VERSION 5.7 ;
BUSBITCHARS "[]" ;
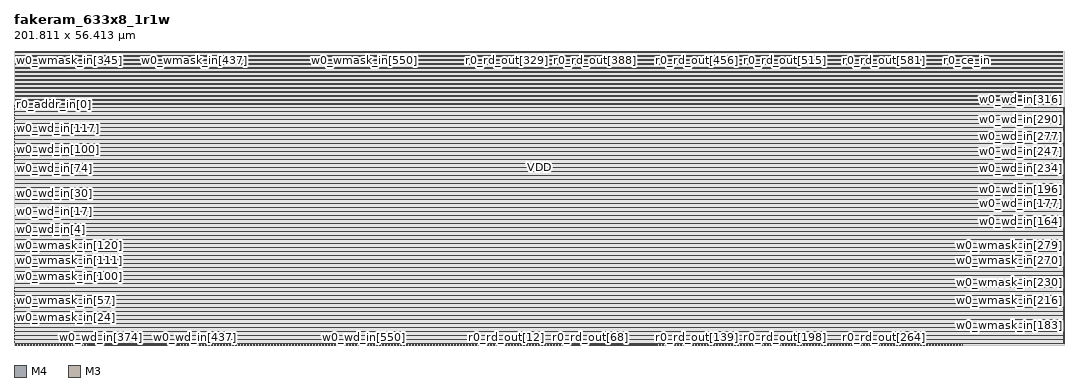
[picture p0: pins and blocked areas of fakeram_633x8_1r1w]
MACRO fakeram_633x8_1r1w
  FOREIGN fakeram_633x8_1r1w 0 0 ;
  SYMMETRY X Y R90 ;
  SIZE 201.811 BY 56.413 ;
  CLASS BLOCK ;
  PIN w0_wmask_in[0]
    DIRECTION INPUT ;
    USE SIGNAL ;
    SHAPE ABUTMENT ;
    PORT
      LAYER M4 ;
      RECT 0.000 0.276 0.072 0.300 ;
    END
  END w0_wmask_in[0]
  PIN w0_wmask_in[1]
    DIRECTION INPUT ;
    USE SIGNAL ;
    SHAPE ABUTMENT ;
    PORT
      LAYER M4 ;
      RECT 0.000 0.420 0.072 0.444 ;
    END
  END w0_wmask_in[1]
  PIN w0_wmask_in[2]
    DIRECTION INPUT ;
    USE SIGNAL ;
    SHAPE ABUTMENT ;
    PORT
      LAYER M4 ;
      RECT 0.000 0.564 0.072 0.588 ;
    END
  END w0_wmask_in[2]
  PIN w0_wmask_in[3]
    DIRECTION INPUT ;
    USE SIGNAL ;
    SHAPE ABUTMENT ;
    PORT
      LAYER M4 ;
      RECT 0.000 0.708 0.072 0.732 ;
    END
  END w0_wmask_in[3]
  PIN w0_wmask_in[4]
    DIRECTION INPUT ;
    USE SIGNAL ;
    SHAPE ABUTMENT ;
    PORT
      LAYER M4 ;
      RECT 0.000 0.852 0.072 0.876 ;
    END
  END w0_wmask_in[4]
  PIN w0_wmask_in[5]
    DIRECTION INPUT ;
    USE SIGNAL ;
    SHAPE ABUTMENT ;
    PORT
      LAYER M4 ;
      RECT 0.000 0.996 0.072 1.020 ;
    END
  END w0_wmask_in[5]
  PIN w0_wmask_in[6]
    DIRECTION INPUT ;
    USE SIGNAL ;
    SHAPE ABUTMENT ;
    PORT
      LAYER M4 ;
      RECT 0.000 1.140 0.072 1.164 ;
    END
  END w0_wmask_in[6]
  PIN w0_wmask_in[7]
    DIRECTION INPUT ;
    USE SIGNAL ;
    SHAPE ABUTMENT ;
    PORT
      LAYER M4 ;
      RECT 0.000 1.284 0.072 1.308 ;
    END
  END w0_wmask_in[7]
  PIN w0_wmask_in[8]
    DIRECTION INPUT ;
    USE SIGNAL ;
    SHAPE ABUTMENT ;
    PORT
      LAYER M4 ;
      RECT 0.000 1.428 0.072 1.452 ;
    END
  END w0_wmask_in[8]
  PIN w0_wmask_in[9]
    DIRECTION INPUT ;
    USE SIGNAL ;
    SHAPE ABUTMENT ;
    PORT
      LAYER M4 ;
      RECT 0.000 1.572 0.072 1.596 ;
    END
  END w0_wmask_in[9]
  PIN w0_wmask_in[10]
    DIRECTION INPUT ;
    USE SIGNAL ;
    SHAPE ABUTMENT ;
    PORT
      LAYER M4 ;
      RECT 0.000 1.716 0.072 1.740 ;
    END
  END w0_wmask_in[10]
  PIN w0_wmask_in[11]
    DIRECTION INPUT ;
    USE SIGNAL ;
    SHAPE ABUTMENT ;
    PORT
      LAYER M4 ;
      RECT 0.000 1.860 0.072 1.884 ;
    END
  END w0_wmask_in[11]
  PIN w0_wmask_in[12]
    DIRECTION INPUT ;
    USE SIGNAL ;
    SHAPE ABUTMENT ;
    PORT
      LAYER M4 ;
      RECT 0.000 2.004 0.072 2.028 ;
    END
  END w0_wmask_in[12]
  PIN w0_wmask_in[13]
    DIRECTION INPUT ;
    USE SIGNAL ;
    SHAPE ABUTMENT ;
    PORT
      LAYER M4 ;
      RECT 0.000 2.148 0.072 2.172 ;
    END
  END w0_wmask_in[13]
  PIN w0_wmask_in[14]
    DIRECTION INPUT ;
    USE SIGNAL ;
    SHAPE ABUTMENT ;
    PORT
      LAYER M4 ;
      RECT 0.000 2.292 0.072 2.316 ;
    END
  END w0_wmask_in[14]
  PIN w0_wmask_in[15]
    DIRECTION INPUT ;
    USE SIGNAL ;
    SHAPE ABUTMENT ;
    PORT
      LAYER M4 ;
      RECT 0.000 2.436 0.072 2.460 ;
    END
  END w0_wmask_in[15]
  PIN w0_wmask_in[16]
    DIRECTION INPUT ;
    USE SIGNAL ;
    SHAPE ABUTMENT ;
    PORT
      LAYER M4 ;
      RECT 0.000 2.580 0.072 2.604 ;
    END
  END w0_wmask_in[16]
  PIN w0_wmask_in[17]
    DIRECTION INPUT ;
    USE SIGNAL ;
    SHAPE ABUTMENT ;
    PORT
      LAYER M4 ;
      RECT 0.000 2.724 0.072 2.748 ;
    END
  END w0_wmask_in[17]
  PIN w0_wmask_in[18]
    DIRECTION INPUT ;
    USE SIGNAL ;
    SHAPE ABUTMENT ;
    PORT
      LAYER M4 ;
      RECT 0.000 2.868 0.072 2.892 ;
    END
  END w0_wmask_in[18]
  PIN w0_wmask_in[19]
    DIRECTION INPUT ;
    USE SIGNAL ;
    SHAPE ABUTMENT ;
    PORT
      LAYER M4 ;
      RECT 0.000 3.012 0.072 3.036 ;
    END
  END w0_wmask_in[19]
  PIN w0_wmask_in[20]
    DIRECTION INPUT ;
    USE SIGNAL ;
    SHAPE ABUTMENT ;
    PORT
      LAYER M4 ;
      RECT 0.000 3.156 0.072 3.180 ;
    END
  END w0_wmask_in[20]
  PIN w0_wmask_in[21]
    DIRECTION INPUT ;
    USE SIGNAL ;
    SHAPE ABUTMENT ;
    PORT
      LAYER M4 ;
      RECT 0.000 3.300 0.072 3.324 ;
    END
  END w0_wmask_in[21]
  PIN w0_wmask_in[22]
    DIRECTION INPUT ;
    USE SIGNAL ;
    SHAPE ABUTMENT ;
    PORT
      LAYER M4 ;
      RECT 0.000 3.444 0.072 3.468 ;
    END
  END w0_wmask_in[22]
  PIN w0_wmask_in[23]
    DIRECTION INPUT ;
    USE SIGNAL ;
    SHAPE ABUTMENT ;
    PORT
      LAYER M4 ;
      RECT 0.000 3.588 0.072 3.612 ;
    END
  END w0_wmask_in[23]
  PIN w0_wmask_in[24]
    DIRECTION INPUT ;
    USE SIGNAL ;
    SHAPE ABUTMENT ;
    PORT
      LAYER M4 ;
      RECT 0.000 3.732 0.072 3.756 ;
    END
  END w0_wmask_in[24]
  PIN w0_wmask_in[25]
    DIRECTION INPUT ;
    USE SIGNAL ;
    SHAPE ABUTMENT ;
    PORT
      LAYER M4 ;
      RECT 0.000 3.876 0.072 3.900 ;
    END
  END w0_wmask_in[25]
  PIN w0_wmask_in[26]
    DIRECTION INPUT ;
    USE SIGNAL ;
    SHAPE ABUTMENT ;
    PORT
      LAYER M4 ;
      RECT 0.000 4.020 0.072 4.044 ;
    END
  END w0_wmask_in[26]
  PIN w0_wmask_in[27]
    DIRECTION INPUT ;
    USE SIGNAL ;
    SHAPE ABUTMENT ;
    PORT
      LAYER M4 ;
      RECT 0.000 4.164 0.072 4.188 ;
    END
  END w0_wmask_in[27]
  PIN w0_wmask_in[28]
    DIRECTION INPUT ;
    USE SIGNAL ;
    SHAPE ABUTMENT ;
    PORT
      LAYER M4 ;
      RECT 0.000 4.308 0.072 4.332 ;
    END
  END w0_wmask_in[28]
  PIN w0_wmask_in[29]
    DIRECTION INPUT ;
    USE SIGNAL ;
    SHAPE ABUTMENT ;
    PORT
      LAYER M4 ;
      RECT 0.000 4.452 0.072 4.476 ;
    END
  END w0_wmask_in[29]
  PIN w0_wmask_in[30]
    DIRECTION INPUT ;
    USE SIGNAL ;
    SHAPE ABUTMENT ;
    PORT
      LAYER M4 ;
      RECT 0.000 4.596 0.072 4.620 ;
    END
  END w0_wmask_in[30]
  PIN w0_wmask_in[31]
    DIRECTION INPUT ;
    USE SIGNAL ;
    SHAPE ABUTMENT ;
    PORT
      LAYER M4 ;
      RECT 0.000 4.740 0.072 4.764 ;
    END
  END w0_wmask_in[31]
  PIN w0_wmask_in[32]
    DIRECTION INPUT ;
    USE SIGNAL ;
    SHAPE ABUTMENT ;
    PORT
      LAYER M4 ;
      RECT 0.000 4.884 0.072 4.908 ;
    END
  END w0_wmask_in[32]
  PIN w0_wmask_in[33]
    DIRECTION INPUT ;
    USE SIGNAL ;
    SHAPE ABUTMENT ;
    PORT
      LAYER M4 ;
      RECT 0.000 5.028 0.072 5.052 ;
    END
  END w0_wmask_in[33]
  PIN w0_wmask_in[34]
    DIRECTION INPUT ;
    USE SIGNAL ;
    SHAPE ABUTMENT ;
    PORT
      LAYER M4 ;
      RECT 0.000 5.172 0.072 5.196 ;
    END
  END w0_wmask_in[34]
  PIN w0_wmask_in[35]
    DIRECTION INPUT ;
    USE SIGNAL ;
    SHAPE ABUTMENT ;
    PORT
      LAYER M4 ;
      RECT 0.000 5.316 0.072 5.340 ;
    END
  END w0_wmask_in[35]
  PIN w0_wmask_in[36]
    DIRECTION INPUT ;
    USE SIGNAL ;
    SHAPE ABUTMENT ;
    PORT
      LAYER M4 ;
      RECT 0.000 5.460 0.072 5.484 ;
    END
  END w0_wmask_in[36]
  PIN w0_wmask_in[37]
    DIRECTION INPUT ;
    USE SIGNAL ;
    SHAPE ABUTMENT ;
    PORT
      LAYER M4 ;
      RECT 0.000 5.604 0.072 5.628 ;
    END
  END w0_wmask_in[37]
  PIN w0_wmask_in[38]
    DIRECTION INPUT ;
    USE SIGNAL ;
    SHAPE ABUTMENT ;
    PORT
      LAYER M4 ;
      RECT 0.000 5.748 0.072 5.772 ;
    END
  END w0_wmask_in[38]
  PIN w0_wmask_in[39]
    DIRECTION INPUT ;
    USE SIGNAL ;
    SHAPE ABUTMENT ;
    PORT
      LAYER M4 ;
      RECT 0.000 5.892 0.072 5.916 ;
    END
  END w0_wmask_in[39]
  PIN w0_wmask_in[40]
    DIRECTION INPUT ;
    USE SIGNAL ;
    SHAPE ABUTMENT ;
    PORT
      LAYER M4 ;
      RECT 0.000 6.036 0.072 6.060 ;
    END
  END w0_wmask_in[40]
  PIN w0_wmask_in[41]
    DIRECTION INPUT ;
    USE SIGNAL ;
    SHAPE ABUTMENT ;
    PORT
      LAYER M4 ;
      RECT 0.000 6.180 0.072 6.204 ;
    END
  END w0_wmask_in[41]
  PIN w0_wmask_in[42]
    DIRECTION INPUT ;
    USE SIGNAL ;
    SHAPE ABUTMENT ;
    PORT
      LAYER M4 ;
      RECT 0.000 6.324 0.072 6.348 ;
    END
  END w0_wmask_in[42]
  PIN w0_wmask_in[43]
    DIRECTION INPUT ;
    USE SIGNAL ;
    SHAPE ABUTMENT ;
    PORT
      LAYER M4 ;
      RECT 0.000 6.468 0.072 6.492 ;
    END
  END w0_wmask_in[43]
  PIN w0_wmask_in[44]
    DIRECTION INPUT ;
    USE SIGNAL ;
    SHAPE ABUTMENT ;
    PORT
      LAYER M4 ;
      RECT 0.000 6.612 0.072 6.636 ;
    END
  END w0_wmask_in[44]
  PIN w0_wmask_in[45]
    DIRECTION INPUT ;
    USE SIGNAL ;
    SHAPE ABUTMENT ;
    PORT
      LAYER M4 ;
      RECT 0.000 6.756 0.072 6.780 ;
    END
  END w0_wmask_in[45]
  PIN w0_wmask_in[46]
    DIRECTION INPUT ;
    USE SIGNAL ;
    SHAPE ABUTMENT ;
    PORT
      LAYER M4 ;
      RECT 0.000 6.900 0.072 6.924 ;
    END
  END w0_wmask_in[46]
  PIN w0_wmask_in[47]
    DIRECTION INPUT ;
    USE SIGNAL ;
    SHAPE ABUTMENT ;
    PORT
      LAYER M4 ;
      RECT 0.000 7.044 0.072 7.068 ;
    END
  END w0_wmask_in[47]
  PIN w0_wmask_in[48]
    DIRECTION INPUT ;
    USE SIGNAL ;
    SHAPE ABUTMENT ;
    PORT
      LAYER M4 ;
      RECT 0.000 7.188 0.072 7.212 ;
    END
  END w0_wmask_in[48]
  PIN w0_wmask_in[49]
    DIRECTION INPUT ;
    USE SIGNAL ;
    SHAPE ABUTMENT ;
    PORT
      LAYER M4 ;
      RECT 0.000 7.332 0.072 7.356 ;
    END
  END w0_wmask_in[49]
  PIN w0_wmask_in[50]
    DIRECTION INPUT ;
    USE SIGNAL ;
    SHAPE ABUTMENT ;
    PORT
      LAYER M4 ;
      RECT 0.000 7.476 0.072 7.500 ;
    END
  END w0_wmask_in[50]
  PIN w0_wmask_in[51]
    DIRECTION INPUT ;
    USE SIGNAL ;
    SHAPE ABUTMENT ;
    PORT
      LAYER M4 ;
      RECT 0.000 7.620 0.072 7.644 ;
    END
  END w0_wmask_in[51]
  PIN w0_wmask_in[52]
    DIRECTION INPUT ;
    USE SIGNAL ;
    SHAPE ABUTMENT ;
    PORT
      LAYER M4 ;
      RECT 0.000 7.764 0.072 7.788 ;
    END
  END w0_wmask_in[52]
  PIN w0_wmask_in[53]
    DIRECTION INPUT ;
    USE SIGNAL ;
    SHAPE ABUTMENT ;
    PORT
      LAYER M4 ;
      RECT 0.000 7.908 0.072 7.932 ;
    END
  END w0_wmask_in[53]
  PIN w0_wmask_in[54]
    DIRECTION INPUT ;
    USE SIGNAL ;
    SHAPE ABUTMENT ;
    PORT
      LAYER M4 ;
      RECT 0.000 8.052 0.072 8.076 ;
    END
  END w0_wmask_in[54]
  PIN w0_wmask_in[55]
    DIRECTION INPUT ;
    USE SIGNAL ;
    SHAPE ABUTMENT ;
    PORT
      LAYER M4 ;
      RECT 0.000 8.196 0.072 8.220 ;
    END
  END w0_wmask_in[55]
  PIN w0_wmask_in[56]
    DIRECTION INPUT ;
    USE SIGNAL ;
    SHAPE ABUTMENT ;
    PORT
      LAYER M4 ;
      RECT 0.000 8.340 0.072 8.364 ;
    END
  END w0_wmask_in[56]
  PIN w0_wmask_in[57]
    DIRECTION INPUT ;
    USE SIGNAL ;
    SHAPE ABUTMENT ;
    PORT
      LAYER M4 ;
      RECT 0.000 8.484 0.072 8.508 ;
    END
  END w0_wmask_in[57]
  PIN w0_wmask_in[58]
    DIRECTION INPUT ;
    USE SIGNAL ;
    SHAPE ABUTMENT ;
    PORT
      LAYER M4 ;
      RECT 0.000 8.628 0.072 8.652 ;
    END
  END w0_wmask_in[58]
  PIN w0_wmask_in[59]
    DIRECTION INPUT ;
    USE SIGNAL ;
    SHAPE ABUTMENT ;
    PORT
      LAYER M4 ;
      RECT 0.000 8.772 0.072 8.796 ;
    END
  END w0_wmask_in[59]
  PIN w0_wmask_in[60]
    DIRECTION INPUT ;
    USE SIGNAL ;
    SHAPE ABUTMENT ;
    PORT
      LAYER M4 ;
      RECT 0.000 8.916 0.072 8.940 ;
    END
  END w0_wmask_in[60]
  PIN w0_wmask_in[61]
    DIRECTION INPUT ;
    USE SIGNAL ;
    SHAPE ABUTMENT ;
    PORT
      LAYER M4 ;
      RECT 0.000 9.060 0.072 9.084 ;
    END
  END w0_wmask_in[61]
  PIN w0_wmask_in[62]
    DIRECTION INPUT ;
    USE SIGNAL ;
    SHAPE ABUTMENT ;
    PORT
      LAYER M4 ;
      RECT 0.000 9.204 0.072 9.228 ;
    END
  END w0_wmask_in[62]
  PIN w0_wmask_in[63]
    DIRECTION INPUT ;
    USE SIGNAL ;
    SHAPE ABUTMENT ;
    PORT
      LAYER M4 ;
      RECT 0.000 9.348 0.072 9.372 ;
    END
  END w0_wmask_in[63]
  PIN w0_wmask_in[64]
    DIRECTION INPUT ;
    USE SIGNAL ;
    SHAPE ABUTMENT ;
    PORT
      LAYER M4 ;
      RECT 0.000 9.492 0.072 9.516 ;
    END
  END w0_wmask_in[64]
  PIN w0_wmask_in[65]
    DIRECTION INPUT ;
    USE SIGNAL ;
    SHAPE ABUTMENT ;
    PORT
      LAYER M4 ;
      RECT 0.000 9.636 0.072 9.660 ;
    END
  END w0_wmask_in[65]
  PIN w0_wmask_in[66]
    DIRECTION INPUT ;
    USE SIGNAL ;
    SHAPE ABUTMENT ;
    PORT
      LAYER M4 ;
      RECT 0.000 9.780 0.072 9.804 ;
    END
  END w0_wmask_in[66]
  PIN w0_wmask_in[67]
    DIRECTION INPUT ;
    USE SIGNAL ;
    SHAPE ABUTMENT ;
    PORT
      LAYER M4 ;
      RECT 0.000 9.924 0.072 9.948 ;
    END
  END w0_wmask_in[67]
  PIN w0_wmask_in[68]
    DIRECTION INPUT ;
    USE SIGNAL ;
    SHAPE ABUTMENT ;
    PORT
      LAYER M4 ;
      RECT 0.000 10.068 0.072 10.092 ;
    END
  END w0_wmask_in[68]
  PIN w0_wmask_in[69]
    DIRECTION INPUT ;
    USE SIGNAL ;
    SHAPE ABUTMENT ;
    PORT
      LAYER M4 ;
      RECT 0.000 10.212 0.072 10.236 ;
    END
  END w0_wmask_in[69]
  PIN w0_wmask_in[70]
    DIRECTION INPUT ;
    USE SIGNAL ;
    SHAPE ABUTMENT ;
    PORT
      LAYER M4 ;
      RECT 0.000 10.356 0.072 10.380 ;
    END
  END w0_wmask_in[70]
  PIN w0_wmask_in[71]
    DIRECTION INPUT ;
    USE SIGNAL ;
    SHAPE ABUTMENT ;
    PORT
      LAYER M4 ;
      RECT 0.000 10.500 0.072 10.524 ;
    END
  END w0_wmask_in[71]
  PIN w0_wmask_in[72]
    DIRECTION INPUT ;
    USE SIGNAL ;
    SHAPE ABUTMENT ;
    PORT
      LAYER M4 ;
      RECT 0.000 10.644 0.072 10.668 ;
    END
  END w0_wmask_in[72]
  PIN w0_wmask_in[73]
    DIRECTION INPUT ;
    USE SIGNAL ;
    SHAPE ABUTMENT ;
    PORT
      LAYER M4 ;
      RECT 0.000 10.788 0.072 10.812 ;
    END
  END w0_wmask_in[73]
  PIN w0_wmask_in[74]
    DIRECTION INPUT ;
    USE SIGNAL ;
    SHAPE ABUTMENT ;
    PORT
      LAYER M4 ;
      RECT 0.000 10.932 0.072 10.956 ;
    END
  END w0_wmask_in[74]
  PIN w0_wmask_in[75]
    DIRECTION INPUT ;
    USE SIGNAL ;
    SHAPE ABUTMENT ;
    PORT
      LAYER M4 ;
      RECT 0.000 11.076 0.072 11.100 ;
    END
  END w0_wmask_in[75]
  PIN w0_wmask_in[76]
    DIRECTION INPUT ;
    USE SIGNAL ;
    SHAPE ABUTMENT ;
    PORT
      LAYER M4 ;
      RECT 0.000 11.220 0.072 11.244 ;
    END
  END w0_wmask_in[76]
  PIN w0_wmask_in[77]
    DIRECTION INPUT ;
    USE SIGNAL ;
    SHAPE ABUTMENT ;
    PORT
      LAYER M4 ;
      RECT 0.000 11.364 0.072 11.388 ;
    END
  END w0_wmask_in[77]
  PIN w0_wmask_in[78]
    DIRECTION INPUT ;
    USE SIGNAL ;
    SHAPE ABUTMENT ;
    PORT
      LAYER M4 ;
      RECT 0.000 11.508 0.072 11.532 ;
    END
  END w0_wmask_in[78]
  PIN w0_wmask_in[79]
    DIRECTION INPUT ;
    USE SIGNAL ;
    SHAPE ABUTMENT ;
    PORT
      LAYER M4 ;
      RECT 0.000 11.652 0.072 11.676 ;
    END
  END w0_wmask_in[79]
  PIN w0_wmask_in[80]
    DIRECTION INPUT ;
    USE SIGNAL ;
    SHAPE ABUTMENT ;
    PORT
      LAYER M4 ;
      RECT 0.000 11.796 0.072 11.820 ;
    END
  END w0_wmask_in[80]
  PIN w0_wmask_in[81]
    DIRECTION INPUT ;
    USE SIGNAL ;
    SHAPE ABUTMENT ;
    PORT
      LAYER M4 ;
      RECT 0.000 11.940 0.072 11.964 ;
    END
  END w0_wmask_in[81]
  PIN w0_wmask_in[82]
    DIRECTION INPUT ;
    USE SIGNAL ;
    SHAPE ABUTMENT ;
    PORT
      LAYER M4 ;
      RECT 0.000 12.084 0.072 12.108 ;
    END
  END w0_wmask_in[82]
  PIN w0_wmask_in[83]
    DIRECTION INPUT ;
    USE SIGNAL ;
    SHAPE ABUTMENT ;
    PORT
      LAYER M4 ;
      RECT 0.000 12.228 0.072 12.252 ;
    END
  END w0_wmask_in[83]
  PIN w0_wmask_in[84]
    DIRECTION INPUT ;
    USE SIGNAL ;
    SHAPE ABUTMENT ;
    PORT
      LAYER M4 ;
      RECT 0.000 12.372 0.072 12.396 ;
    END
  END w0_wmask_in[84]
  PIN w0_wmask_in[85]
    DIRECTION INPUT ;
    USE SIGNAL ;
    SHAPE ABUTMENT ;
    PORT
      LAYER M4 ;
      RECT 0.000 12.516 0.072 12.540 ;
    END
  END w0_wmask_in[85]
  PIN w0_wmask_in[86]
    DIRECTION INPUT ;
    USE SIGNAL ;
    SHAPE ABUTMENT ;
    PORT
      LAYER M4 ;
      RECT 0.000 12.660 0.072 12.684 ;
    END
  END w0_wmask_in[86]
  PIN w0_wmask_in[87]
    DIRECTION INPUT ;
    USE SIGNAL ;
    SHAPE ABUTMENT ;
    PORT
      LAYER M4 ;
      RECT 0.000 12.804 0.072 12.828 ;
    END
  END w0_wmask_in[87]
  PIN w0_wmask_in[88]
    DIRECTION INPUT ;
    USE SIGNAL ;
    SHAPE ABUTMENT ;
    PORT
      LAYER M4 ;
      RECT 0.000 12.948 0.072 12.972 ;
    END
  END w0_wmask_in[88]
  PIN w0_wmask_in[89]
    DIRECTION INPUT ;
    USE SIGNAL ;
    SHAPE ABUTMENT ;
    PORT
      LAYER M4 ;
      RECT 0.000 13.092 0.072 13.116 ;
    END
  END w0_wmask_in[89]
  PIN w0_wmask_in[90]
    DIRECTION INPUT ;
    USE SIGNAL ;
    SHAPE ABUTMENT ;
    PORT
      LAYER M4 ;
      RECT 0.000 13.236 0.072 13.260 ;
    END
  END w0_wmask_in[90]
  PIN w0_wmask_in[91]
    DIRECTION INPUT ;
    USE SIGNAL ;
    SHAPE ABUTMENT ;
    PORT
      LAYER M4 ;
      RECT 0.000 13.380 0.072 13.404 ;
    END
  END w0_wmask_in[91]
  PIN w0_wmask_in[92]
    DIRECTION INPUT ;
    USE SIGNAL ;
    SHAPE ABUTMENT ;
    PORT
      LAYER M4 ;
      RECT 0.000 13.524 0.072 13.548 ;
    END
  END w0_wmask_in[92]
  PIN w0_wmask_in[93]
    DIRECTION INPUT ;
    USE SIGNAL ;
    SHAPE ABUTMENT ;
    PORT
      LAYER M4 ;
      RECT 0.000 13.668 0.072 13.692 ;
    END
  END w0_wmask_in[93]
  PIN w0_wmask_in[94]
    DIRECTION INPUT ;
    USE SIGNAL ;
    SHAPE ABUTMENT ;
    PORT
      LAYER M4 ;
      RECT 0.000 13.812 0.072 13.836 ;
    END
  END w0_wmask_in[94]
  PIN w0_wmask_in[95]
    DIRECTION INPUT ;
    USE SIGNAL ;
    SHAPE ABUTMENT ;
    PORT
      LAYER M4 ;
      RECT 0.000 13.956 0.072 13.980 ;
    END
  END w0_wmask_in[95]
  PIN w0_wmask_in[96]
    DIRECTION INPUT ;
    USE SIGNAL ;
    SHAPE ABUTMENT ;
    PORT
      LAYER M4 ;
      RECT 0.000 14.100 0.072 14.124 ;
    END
  END w0_wmask_in[96]
  PIN w0_wmask_in[97]
    DIRECTION INPUT ;
    USE SIGNAL ;
    SHAPE ABUTMENT ;
    PORT
      LAYER M4 ;
      RECT 0.000 14.244 0.072 14.268 ;
    END
  END w0_wmask_in[97]
  PIN w0_wmask_in[98]
    DIRECTION INPUT ;
    USE SIGNAL ;
    SHAPE ABUTMENT ;
    PORT
      LAYER M4 ;
      RECT 0.000 14.388 0.072 14.412 ;
    END
  END w0_wmask_in[98]
  PIN w0_wmask_in[99]
    DIRECTION INPUT ;
    USE SIGNAL ;
    SHAPE ABUTMENT ;
    PORT
      LAYER M4 ;
      RECT 0.000 14.532 0.072 14.556 ;
    END
  END w0_wmask_in[99]
  PIN w0_wmask_in[100]
    DIRECTION INPUT ;
    USE SIGNAL ;
    SHAPE ABUTMENT ;
    PORT
      LAYER M4 ;
      RECT 0.000 14.676 0.072 14.700 ;
    END
  END w0_wmask_in[100]
  PIN w0_wmask_in[101]
    DIRECTION INPUT ;
    USE SIGNAL ;
    SHAPE ABUTMENT ;
    PORT
      LAYER M4 ;
      RECT 0.000 14.820 0.072 14.844 ;
    END
  END w0_wmask_in[101]
  PIN w0_wmask_in[102]
    DIRECTION INPUT ;
    USE SIGNAL ;
    SHAPE ABUTMENT ;
    PORT
      LAYER M4 ;
      RECT 0.000 14.964 0.072 14.988 ;
    END
  END w0_wmask_in[102]
  PIN w0_wmask_in[103]
    DIRECTION INPUT ;
    USE SIGNAL ;
    SHAPE ABUTMENT ;
    PORT
      LAYER M4 ;
      RECT 0.000 15.108 0.072 15.132 ;
    END
  END w0_wmask_in[103]
  PIN w0_wmask_in[104]
    DIRECTION INPUT ;
    USE SIGNAL ;
    SHAPE ABUTMENT ;
    PORT
      LAYER M4 ;
      RECT 0.000 15.252 0.072 15.276 ;
    END
  END w0_wmask_in[104]
  PIN w0_wmask_in[105]
    DIRECTION INPUT ;
    USE SIGNAL ;
    SHAPE ABUTMENT ;
    PORT
      LAYER M4 ;
      RECT 0.000 15.396 0.072 15.420 ;
    END
  END w0_wmask_in[105]
  PIN w0_wmask_in[106]
    DIRECTION INPUT ;
    USE SIGNAL ;
    SHAPE ABUTMENT ;
    PORT
      LAYER M4 ;
      RECT 0.000 15.540 0.072 15.564 ;
    END
  END w0_wmask_in[106]
  PIN w0_wmask_in[107]
    DIRECTION INPUT ;
    USE SIGNAL ;
    SHAPE ABUTMENT ;
    PORT
      LAYER M4 ;
      RECT 0.000 15.684 0.072 15.708 ;
    END
  END w0_wmask_in[107]
  PIN w0_wmask_in[108]
    DIRECTION INPUT ;
    USE SIGNAL ;
    SHAPE ABUTMENT ;
    PORT
      LAYER M4 ;
      RECT 0.000 15.828 0.072 15.852 ;
    END
  END w0_wmask_in[108]
  PIN w0_wmask_in[109]
    DIRECTION INPUT ;
    USE SIGNAL ;
    SHAPE ABUTMENT ;
    PORT
      LAYER M4 ;
      RECT 0.000 15.972 0.072 15.996 ;
    END
  END w0_wmask_in[109]
  PIN w0_wmask_in[110]
    DIRECTION INPUT ;
    USE SIGNAL ;
    SHAPE ABUTMENT ;
    PORT
      LAYER M4 ;
      RECT 0.000 16.116 0.072 16.140 ;
    END
  END w0_wmask_in[110]
  PIN w0_wmask_in[111]
    DIRECTION INPUT ;
    USE SIGNAL ;
    SHAPE ABUTMENT ;
    PORT
      LAYER M4 ;
      RECT 0.000 16.260 0.072 16.284 ;
    END
  END w0_wmask_in[111]
  PIN w0_wmask_in[112]
    DIRECTION INPUT ;
    USE SIGNAL ;
    SHAPE ABUTMENT ;
    PORT
      LAYER M4 ;
      RECT 0.000 16.404 0.072 16.428 ;
    END
  END w0_wmask_in[112]
  PIN w0_wmask_in[113]
    DIRECTION INPUT ;
    USE SIGNAL ;
    SHAPE ABUTMENT ;
    PORT
      LAYER M4 ;
      RECT 0.000 16.548 0.072 16.572 ;
    END
  END w0_wmask_in[113]
  PIN w0_wmask_in[114]
    DIRECTION INPUT ;
    USE SIGNAL ;
    SHAPE ABUTMENT ;
    PORT
      LAYER M4 ;
      RECT 0.000 16.692 0.072 16.716 ;
    END
  END w0_wmask_in[114]
  PIN w0_wmask_in[115]
    DIRECTION INPUT ;
    USE SIGNAL ;
    SHAPE ABUTMENT ;
    PORT
      LAYER M4 ;
      RECT 0.000 16.836 0.072 16.860 ;
    END
  END w0_wmask_in[115]
  PIN w0_wmask_in[116]
    DIRECTION INPUT ;
    USE SIGNAL ;
    SHAPE ABUTMENT ;
    PORT
      LAYER M4 ;
      RECT 0.000 16.980 0.072 17.004 ;
    END
  END w0_wmask_in[116]
  PIN w0_wmask_in[117]
    DIRECTION INPUT ;
    USE SIGNAL ;
    SHAPE ABUTMENT ;
    PORT
      LAYER M4 ;
      RECT 0.000 17.124 0.072 17.148 ;
    END
  END w0_wmask_in[117]
  PIN w0_wmask_in[118]
    DIRECTION INPUT ;
    USE SIGNAL ;
    SHAPE ABUTMENT ;
    PORT
      LAYER M4 ;
      RECT 0.000 17.268 0.072 17.292 ;
    END
  END w0_wmask_in[118]
  PIN w0_wmask_in[119]
    DIRECTION INPUT ;
    USE SIGNAL ;
    SHAPE ABUTMENT ;
    PORT
      LAYER M4 ;
      RECT 0.000 17.412 0.072 17.436 ;
    END
  END w0_wmask_in[119]
  PIN w0_wmask_in[120]
    DIRECTION INPUT ;
    USE SIGNAL ;
    SHAPE ABUTMENT ;
    PORT
      LAYER M4 ;
      RECT 0.000 17.556 0.072 17.580 ;
    END
  END w0_wmask_in[120]
  PIN w0_wmask_in[121]
    DIRECTION INPUT ;
    USE SIGNAL ;
    SHAPE ABUTMENT ;
    PORT
      LAYER M4 ;
      RECT 0.000 17.700 0.072 17.724 ;
    END
  END w0_wmask_in[121]
  PIN w0_wmask_in[122]
    DIRECTION INPUT ;
    USE SIGNAL ;
    SHAPE ABUTMENT ;
    PORT
      LAYER M4 ;
      RECT 0.000 17.844 0.072 17.868 ;
    END
  END w0_wmask_in[122]
  PIN w0_wmask_in[123]
    DIRECTION INPUT ;
    USE SIGNAL ;
    SHAPE ABUTMENT ;
    PORT
      LAYER M4 ;
      RECT 0.000 17.988 0.072 18.012 ;
    END
  END w0_wmask_in[123]
  PIN w0_wmask_in[124]
    DIRECTION INPUT ;
    USE SIGNAL ;
    SHAPE ABUTMENT ;
    PORT
      LAYER M4 ;
      RECT 0.000 18.132 0.072 18.156 ;
    END
  END w0_wmask_in[124]
  PIN w0_wmask_in[125]
    DIRECTION INPUT ;
    USE SIGNAL ;
    SHAPE ABUTMENT ;
    PORT
      LAYER M4 ;
      RECT 0.000 18.276 0.072 18.300 ;
    END
  END w0_wmask_in[125]
  PIN w0_wmask_in[126]
    DIRECTION INPUT ;
    USE SIGNAL ;
    SHAPE ABUTMENT ;
    PORT
      LAYER M4 ;
      RECT 0.000 18.420 0.072 18.444 ;
    END
  END w0_wmask_in[126]
  PIN w0_wmask_in[127]
    DIRECTION INPUT ;
    USE SIGNAL ;
    SHAPE ABUTMENT ;
    PORT
      LAYER M4 ;
      RECT 0.000 18.564 0.072 18.588 ;
    END
  END w0_wmask_in[127]
  PIN w0_wmask_in[128]
    DIRECTION INPUT ;
    USE SIGNAL ;
    SHAPE ABUTMENT ;
    PORT
      LAYER M4 ;
      RECT 0.000 18.708 0.072 18.732 ;
    END
  END w0_wmask_in[128]
  PIN w0_wmask_in[129]
    DIRECTION INPUT ;
    USE SIGNAL ;
    SHAPE ABUTMENT ;
    PORT
      LAYER M4 ;
      RECT 0.000 18.852 0.072 18.876 ;
    END
  END w0_wmask_in[129]
  PIN w0_wmask_in[130]
    DIRECTION INPUT ;
    USE SIGNAL ;
    SHAPE ABUTMENT ;
    PORT
      LAYER M4 ;
      RECT 0.000 18.996 0.072 19.020 ;
    END
  END w0_wmask_in[130]
  PIN w0_wmask_in[131]
    DIRECTION INPUT ;
    USE SIGNAL ;
    SHAPE ABUTMENT ;
    PORT
      LAYER M4 ;
      RECT 0.000 19.140 0.072 19.164 ;
    END
  END w0_wmask_in[131]
  PIN w0_wmask_in[132]
    DIRECTION INPUT ;
    USE SIGNAL ;
    SHAPE ABUTMENT ;
    PORT
      LAYER M4 ;
      RECT 0.000 19.284 0.072 19.308 ;
    END
  END w0_wmask_in[132]
  PIN w0_wmask_in[133]
    DIRECTION INPUT ;
    USE SIGNAL ;
    SHAPE ABUTMENT ;
    PORT
      LAYER M4 ;
      RECT 0.000 19.428 0.072 19.452 ;
    END
  END w0_wmask_in[133]
  PIN w0_wmask_in[134]
    DIRECTION INPUT ;
    USE SIGNAL ;
    SHAPE ABUTMENT ;
    PORT
      LAYER M4 ;
      RECT 0.000 19.572 0.072 19.596 ;
    END
  END w0_wmask_in[134]
  PIN w0_wmask_in[135]
    DIRECTION INPUT ;
    USE SIGNAL ;
    SHAPE ABUTMENT ;
    PORT
      LAYER M4 ;
      RECT 0.000 19.716 0.072 19.740 ;
    END
  END w0_wmask_in[135]
  PIN w0_wmask_in[136]
    DIRECTION INPUT ;
    USE SIGNAL ;
    SHAPE ABUTMENT ;
    PORT
      LAYER M4 ;
      RECT 0.000 19.860 0.072 19.884 ;
    END
  END w0_wmask_in[136]
  PIN w0_wmask_in[137]
    DIRECTION INPUT ;
    USE SIGNAL ;
    SHAPE ABUTMENT ;
    PORT
      LAYER M4 ;
      RECT 0.000 20.004 0.072 20.028 ;
    END
  END w0_wmask_in[137]
  PIN w0_wmask_in[138]
    DIRECTION INPUT ;
    USE SIGNAL ;
    SHAPE ABUTMENT ;
    PORT
      LAYER M4 ;
      RECT 0.000 20.148 0.072 20.172 ;
    END
  END w0_wmask_in[138]
  PIN w0_wmask_in[139]
    DIRECTION INPUT ;
    USE SIGNAL ;
    SHAPE ABUTMENT ;
    PORT
      LAYER M4 ;
      RECT 0.000 20.292 0.072 20.316 ;
    END
  END w0_wmask_in[139]
  PIN w0_wmask_in[140]
    DIRECTION INPUT ;
    USE SIGNAL ;
    SHAPE ABUTMENT ;
    PORT
      LAYER M4 ;
      RECT 0.000 20.436 0.072 20.460 ;
    END
  END w0_wmask_in[140]
  PIN w0_wmask_in[141]
    DIRECTION INPUT ;
    USE SIGNAL ;
    SHAPE ABUTMENT ;
    PORT
      LAYER M4 ;
      RECT 0.000 20.580 0.072 20.604 ;
    END
  END w0_wmask_in[141]
  PIN w0_wmask_in[142]
    DIRECTION INPUT ;
    USE SIGNAL ;
    SHAPE ABUTMENT ;
    PORT
      LAYER M4 ;
      RECT 0.000 20.724 0.072 20.748 ;
    END
  END w0_wmask_in[142]
  PIN w0_wmask_in[143]
    DIRECTION INPUT ;
    USE SIGNAL ;
    SHAPE ABUTMENT ;
    PORT
      LAYER M4 ;
      RECT 0.000 20.868 0.072 20.892 ;
    END
  END w0_wmask_in[143]
  PIN w0_wmask_in[144]
    DIRECTION INPUT ;
    USE SIGNAL ;
    SHAPE ABUTMENT ;
    PORT
      LAYER M4 ;
      RECT 0.000 21.012 0.072 21.036 ;
    END
  END w0_wmask_in[144]
  PIN w0_wmask_in[145]
    DIRECTION INPUT ;
    USE SIGNAL ;
    SHAPE ABUTMENT ;
    PORT
      LAYER M4 ;
      RECT 0.000 21.156 0.072 21.180 ;
    END
  END w0_wmask_in[145]
  PIN w0_wmask_in[146]
    DIRECTION INPUT ;
    USE SIGNAL ;
    SHAPE ABUTMENT ;
    PORT
      LAYER M4 ;
      RECT 0.000 21.300 0.072 21.324 ;
    END
  END w0_wmask_in[146]
  PIN w0_wmask_in[147]
    DIRECTION INPUT ;
    USE SIGNAL ;
    SHAPE ABUTMENT ;
    PORT
      LAYER M4 ;
      RECT 0.000 21.444 0.072 21.468 ;
    END
  END w0_wmask_in[147]
  PIN w0_wmask_in[148]
    DIRECTION INPUT ;
    USE SIGNAL ;
    SHAPE ABUTMENT ;
    PORT
      LAYER M4 ;
      RECT 0.000 21.588 0.072 21.612 ;
    END
  END w0_wmask_in[148]
  PIN w0_wmask_in[149]
    DIRECTION INPUT ;
    USE SIGNAL ;
    SHAPE ABUTMENT ;
    PORT
      LAYER M4 ;
      RECT 0.000 21.732 0.072 21.756 ;
    END
  END w0_wmask_in[149]
  PIN w0_wmask_in[150]
    DIRECTION INPUT ;
    USE SIGNAL ;
    SHAPE ABUTMENT ;
    PORT
      LAYER M4 ;
      RECT 0.000 21.876 0.072 21.900 ;
    END
  END w0_wmask_in[150]
  PIN w0_wmask_in[151]
    DIRECTION INPUT ;
    USE SIGNAL ;
    SHAPE ABUTMENT ;
    PORT
      LAYER M4 ;
      RECT 0.000 22.020 0.072 22.044 ;
    END
  END w0_wmask_in[151]
  PIN w0_wmask_in[152]
    DIRECTION INPUT ;
    USE SIGNAL ;
    SHAPE ABUTMENT ;
    PORT
      LAYER M4 ;
      RECT 0.000 22.164 0.072 22.188 ;
    END
  END w0_wmask_in[152]
  PIN w0_wmask_in[153]
    DIRECTION INPUT ;
    USE SIGNAL ;
    SHAPE ABUTMENT ;
    PORT
      LAYER M4 ;
      RECT 0.000 22.308 0.072 22.332 ;
    END
  END w0_wmask_in[153]
  PIN w0_wmask_in[154]
    DIRECTION INPUT ;
    USE SIGNAL ;
    SHAPE ABUTMENT ;
    PORT
      LAYER M4 ;
      RECT 0.000 22.452 0.072 22.476 ;
    END
  END w0_wmask_in[154]
  PIN w0_wmask_in[155]
    DIRECTION INPUT ;
    USE SIGNAL ;
    SHAPE ABUTMENT ;
    PORT
      LAYER M4 ;
      RECT 0.000 22.596 0.072 22.620 ;
    END
  END w0_wmask_in[155]
  PIN w0_wmask_in[156]
    DIRECTION INPUT ;
    USE SIGNAL ;
    SHAPE ABUTMENT ;
    PORT
      LAYER M4 ;
      RECT 0.000 22.740 0.072 22.764 ;
    END
  END w0_wmask_in[156]
  PIN w0_wmask_in[157]
    DIRECTION INPUT ;
    USE SIGNAL ;
    SHAPE ABUTMENT ;
    PORT
      LAYER M4 ;
      RECT 0.000 22.884 0.072 22.908 ;
    END
  END w0_wmask_in[157]
  PIN w0_wmask_in[158]
    DIRECTION INPUT ;
    USE SIGNAL ;
    SHAPE ABUTMENT ;
    PORT
      LAYER M4 ;
      RECT 0.000 23.028 0.072 23.052 ;
    END
  END w0_wmask_in[158]
  PIN w0_wmask_in[159]
    DIRECTION INPUT ;
    USE SIGNAL ;
    SHAPE ABUTMENT ;
    PORT
      LAYER M4 ;
      RECT 201.739 0.276 201.811 0.300 ;
    END
  END w0_wmask_in[159]
  PIN w0_wmask_in[160]
    DIRECTION INPUT ;
    USE SIGNAL ;
    SHAPE ABUTMENT ;
    PORT
      LAYER M4 ;
      RECT 201.739 0.420 201.811 0.444 ;
    END
  END w0_wmask_in[160]
  PIN w0_wmask_in[161]
    DIRECTION INPUT ;
    USE SIGNAL ;
    SHAPE ABUTMENT ;
    PORT
      LAYER M4 ;
      RECT 201.739 0.564 201.811 0.588 ;
    END
  END w0_wmask_in[161]
  PIN w0_wmask_in[162]
    DIRECTION INPUT ;
    USE SIGNAL ;
    SHAPE ABUTMENT ;
    PORT
      LAYER M4 ;
      RECT 201.739 0.708 201.811 0.732 ;
    END
  END w0_wmask_in[162]
  PIN w0_wmask_in[163]
    DIRECTION INPUT ;
    USE SIGNAL ;
    SHAPE ABUTMENT ;
    PORT
      LAYER M4 ;
      RECT 201.739 0.852 201.811 0.876 ;
    END
  END w0_wmask_in[163]
  PIN w0_wmask_in[164]
    DIRECTION INPUT ;
    USE SIGNAL ;
    SHAPE ABUTMENT ;
    PORT
      LAYER M4 ;
      RECT 201.739 0.996 201.811 1.020 ;
    END
  END w0_wmask_in[164]
  PIN w0_wmask_in[165]
    DIRECTION INPUT ;
    USE SIGNAL ;
    SHAPE ABUTMENT ;
    PORT
      LAYER M4 ;
      RECT 201.739 1.140 201.811 1.164 ;
    END
  END w0_wmask_in[165]
  PIN w0_wmask_in[166]
    DIRECTION INPUT ;
    USE SIGNAL ;
    SHAPE ABUTMENT ;
    PORT
      LAYER M4 ;
      RECT 201.739 1.284 201.811 1.308 ;
    END
  END w0_wmask_in[166]
  PIN w0_wmask_in[167]
    DIRECTION INPUT ;
    USE SIGNAL ;
    SHAPE ABUTMENT ;
    PORT
      LAYER M4 ;
      RECT 201.739 1.428 201.811 1.452 ;
    END
  END w0_wmask_in[167]
  PIN w0_wmask_in[168]
    DIRECTION INPUT ;
    USE SIGNAL ;
    SHAPE ABUTMENT ;
    PORT
      LAYER M4 ;
      RECT 201.739 1.572 201.811 1.596 ;
    END
  END w0_wmask_in[168]
  PIN w0_wmask_in[169]
    DIRECTION INPUT ;
    USE SIGNAL ;
    SHAPE ABUTMENT ;
    PORT
      LAYER M4 ;
      RECT 201.739 1.716 201.811 1.740 ;
    END
  END w0_wmask_in[169]
  PIN w0_wmask_in[170]
    DIRECTION INPUT ;
    USE SIGNAL ;
    SHAPE ABUTMENT ;
    PORT
      LAYER M4 ;
      RECT 201.739 1.860 201.811 1.884 ;
    END
  END w0_wmask_in[170]
  PIN w0_wmask_in[171]
    DIRECTION INPUT ;
    USE SIGNAL ;
    SHAPE ABUTMENT ;
    PORT
      LAYER M4 ;
      RECT 201.739 2.004 201.811 2.028 ;
    END
  END w0_wmask_in[171]
  PIN w0_wmask_in[172]
    DIRECTION INPUT ;
    USE SIGNAL ;
    SHAPE ABUTMENT ;
    PORT
      LAYER M4 ;
      RECT 201.739 2.148 201.811 2.172 ;
    END
  END w0_wmask_in[172]
  PIN w0_wmask_in[173]
    DIRECTION INPUT ;
    USE SIGNAL ;
    SHAPE ABUTMENT ;
    PORT
      LAYER M4 ;
      RECT 201.739 2.292 201.811 2.316 ;
    END
  END w0_wmask_in[173]
  PIN w0_wmask_in[174]
    DIRECTION INPUT ;
    USE SIGNAL ;
    SHAPE ABUTMENT ;
    PORT
      LAYER M4 ;
      RECT 201.739 2.436 201.811 2.460 ;
    END
  END w0_wmask_in[174]
  PIN w0_wmask_in[175]
    DIRECTION INPUT ;
    USE SIGNAL ;
    SHAPE ABUTMENT ;
    PORT
      LAYER M4 ;
      RECT 201.739 2.580 201.811 2.604 ;
    END
  END w0_wmask_in[175]
  PIN w0_wmask_in[176]
    DIRECTION INPUT ;
    USE SIGNAL ;
    SHAPE ABUTMENT ;
    PORT
      LAYER M4 ;
      RECT 201.739 2.724 201.811 2.748 ;
    END
  END w0_wmask_in[176]
  PIN w0_wmask_in[177]
    DIRECTION INPUT ;
    USE SIGNAL ;
    SHAPE ABUTMENT ;
    PORT
      LAYER M4 ;
      RECT 201.739 2.868 201.811 2.892 ;
    END
  END w0_wmask_in[177]
  PIN w0_wmask_in[178]
    DIRECTION INPUT ;
    USE SIGNAL ;
    SHAPE ABUTMENT ;
    PORT
      LAYER M4 ;
      RECT 201.739 3.012 201.811 3.036 ;
    END
  END w0_wmask_in[178]
  PIN w0_wmask_in[179]
    DIRECTION INPUT ;
    USE SIGNAL ;
    SHAPE ABUTMENT ;
    PORT
      LAYER M4 ;
      RECT 201.739 3.156 201.811 3.180 ;
    END
  END w0_wmask_in[179]
  PIN w0_wmask_in[180]
    DIRECTION INPUT ;
    USE SIGNAL ;
    SHAPE ABUTMENT ;
    PORT
      LAYER M4 ;
      RECT 201.739 3.300 201.811 3.324 ;
    END
  END w0_wmask_in[180]
  PIN w0_wmask_in[181]
    DIRECTION INPUT ;
    USE SIGNAL ;
    SHAPE ABUTMENT ;
    PORT
      LAYER M4 ;
      RECT 201.739 3.444 201.811 3.468 ;
    END
  END w0_wmask_in[181]
  PIN w0_wmask_in[182]
    DIRECTION INPUT ;
    USE SIGNAL ;
    SHAPE ABUTMENT ;
    PORT
      LAYER M4 ;
      RECT 201.739 3.588 201.811 3.612 ;
    END
  END w0_wmask_in[182]
  PIN w0_wmask_in[183]
    DIRECTION INPUT ;
    USE SIGNAL ;
    SHAPE ABUTMENT ;
    PORT
      LAYER M4 ;
      RECT 201.739 3.732 201.811 3.756 ;
    END
  END w0_wmask_in[183]
  PIN w0_wmask_in[184]
    DIRECTION INPUT ;
    USE SIGNAL ;
    SHAPE ABUTMENT ;
    PORT
      LAYER M4 ;
      RECT 201.739 3.876 201.811 3.900 ;
    END
  END w0_wmask_in[184]
  PIN w0_wmask_in[185]
    DIRECTION INPUT ;
    USE SIGNAL ;
    SHAPE ABUTMENT ;
    PORT
      LAYER M4 ;
      RECT 201.739 4.020 201.811 4.044 ;
    END
  END w0_wmask_in[185]
  PIN w0_wmask_in[186]
    DIRECTION INPUT ;
    USE SIGNAL ;
    SHAPE ABUTMENT ;
    PORT
      LAYER M4 ;
      RECT 201.739 4.164 201.811 4.188 ;
    END
  END w0_wmask_in[186]
  PIN w0_wmask_in[187]
    DIRECTION INPUT ;
    USE SIGNAL ;
    SHAPE ABUTMENT ;
    PORT
      LAYER M4 ;
      RECT 201.739 4.308 201.811 4.332 ;
    END
  END w0_wmask_in[187]
  PIN w0_wmask_in[188]
    DIRECTION INPUT ;
    USE SIGNAL ;
    SHAPE ABUTMENT ;
    PORT
      LAYER M4 ;
      RECT 201.739 4.452 201.811 4.476 ;
    END
  END w0_wmask_in[188]
  PIN w0_wmask_in[189]
    DIRECTION INPUT ;
    USE SIGNAL ;
    SHAPE ABUTMENT ;
    PORT
      LAYER M4 ;
      RECT 201.739 4.596 201.811 4.620 ;
    END
  END w0_wmask_in[189]
  PIN w0_wmask_in[190]
    DIRECTION INPUT ;
    USE SIGNAL ;
    SHAPE ABUTMENT ;
    PORT
      LAYER M4 ;
      RECT 201.739 4.740 201.811 4.764 ;
    END
  END w0_wmask_in[190]
  PIN w0_wmask_in[191]
    DIRECTION INPUT ;
    USE SIGNAL ;
    SHAPE ABUTMENT ;
    PORT
      LAYER M4 ;
      RECT 201.739 4.884 201.811 4.908 ;
    END
  END w0_wmask_in[191]
  PIN w0_wmask_in[192]
    DIRECTION INPUT ;
    USE SIGNAL ;
    SHAPE ABUTMENT ;
    PORT
      LAYER M4 ;
      RECT 201.739 5.028 201.811 5.052 ;
    END
  END w0_wmask_in[192]
  PIN w0_wmask_in[193]
    DIRECTION INPUT ;
    USE SIGNAL ;
    SHAPE ABUTMENT ;
    PORT
      LAYER M4 ;
      RECT 201.739 5.172 201.811 5.196 ;
    END
  END w0_wmask_in[193]
  PIN w0_wmask_in[194]
    DIRECTION INPUT ;
    USE SIGNAL ;
    SHAPE ABUTMENT ;
    PORT
      LAYER M4 ;
      RECT 201.739 5.316 201.811 5.340 ;
    END
  END w0_wmask_in[194]
  PIN w0_wmask_in[195]
    DIRECTION INPUT ;
    USE SIGNAL ;
    SHAPE ABUTMENT ;
    PORT
      LAYER M4 ;
      RECT 201.739 5.460 201.811 5.484 ;
    END
  END w0_wmask_in[195]
  PIN w0_wmask_in[196]
    DIRECTION INPUT ;
    USE SIGNAL ;
    SHAPE ABUTMENT ;
    PORT
      LAYER M4 ;
      RECT 201.739 5.604 201.811 5.628 ;
    END
  END w0_wmask_in[196]
  PIN w0_wmask_in[197]
    DIRECTION INPUT ;
    USE SIGNAL ;
    SHAPE ABUTMENT ;
    PORT
      LAYER M4 ;
      RECT 201.739 5.748 201.811 5.772 ;
    END
  END w0_wmask_in[197]
  PIN w0_wmask_in[198]
    DIRECTION INPUT ;
    USE SIGNAL ;
    SHAPE ABUTMENT ;
    PORT
      LAYER M4 ;
      RECT 201.739 5.892 201.811 5.916 ;
    END
  END w0_wmask_in[198]
  PIN w0_wmask_in[199]
    DIRECTION INPUT ;
    USE SIGNAL ;
    SHAPE ABUTMENT ;
    PORT
      LAYER M4 ;
      RECT 201.739 6.036 201.811 6.060 ;
    END
  END w0_wmask_in[199]
  PIN w0_wmask_in[200]
    DIRECTION INPUT ;
    USE SIGNAL ;
    SHAPE ABUTMENT ;
    PORT
      LAYER M4 ;
      RECT 201.739 6.180 201.811 6.204 ;
    END
  END w0_wmask_in[200]
  PIN w0_wmask_in[201]
    DIRECTION INPUT ;
    USE SIGNAL ;
    SHAPE ABUTMENT ;
    PORT
      LAYER M4 ;
      RECT 201.739 6.324 201.811 6.348 ;
    END
  END w0_wmask_in[201]
  PIN w0_wmask_in[202]
    DIRECTION INPUT ;
    USE SIGNAL ;
    SHAPE ABUTMENT ;
    PORT
      LAYER M4 ;
      RECT 201.739 6.468 201.811 6.492 ;
    END
  END w0_wmask_in[202]
  PIN w0_wmask_in[203]
    DIRECTION INPUT ;
    USE SIGNAL ;
    SHAPE ABUTMENT ;
    PORT
      LAYER M4 ;
      RECT 201.739 6.612 201.811 6.636 ;
    END
  END w0_wmask_in[203]
  PIN w0_wmask_in[204]
    DIRECTION INPUT ;
    USE SIGNAL ;
    SHAPE ABUTMENT ;
    PORT
      LAYER M4 ;
      RECT 201.739 6.756 201.811 6.780 ;
    END
  END w0_wmask_in[204]
  PIN w0_wmask_in[205]
    DIRECTION INPUT ;
    USE SIGNAL ;
    SHAPE ABUTMENT ;
    PORT
      LAYER M4 ;
      RECT 201.739 6.900 201.811 6.924 ;
    END
  END w0_wmask_in[205]
  PIN w0_wmask_in[206]
    DIRECTION INPUT ;
    USE SIGNAL ;
    SHAPE ABUTMENT ;
    PORT
      LAYER M4 ;
      RECT 201.739 7.044 201.811 7.068 ;
    END
  END w0_wmask_in[206]
  PIN w0_wmask_in[207]
    DIRECTION INPUT ;
    USE SIGNAL ;
    SHAPE ABUTMENT ;
    PORT
      LAYER M4 ;
      RECT 201.739 7.188 201.811 7.212 ;
    END
  END w0_wmask_in[207]
  PIN w0_wmask_in[208]
    DIRECTION INPUT ;
    USE SIGNAL ;
    SHAPE ABUTMENT ;
    PORT
      LAYER M4 ;
      RECT 201.739 7.332 201.811 7.356 ;
    END
  END w0_wmask_in[208]
  PIN w0_wmask_in[209]
    DIRECTION INPUT ;
    USE SIGNAL ;
    SHAPE ABUTMENT ;
    PORT
      LAYER M4 ;
      RECT 201.739 7.476 201.811 7.500 ;
    END
  END w0_wmask_in[209]
  PIN w0_wmask_in[210]
    DIRECTION INPUT ;
    USE SIGNAL ;
    SHAPE ABUTMENT ;
    PORT
      LAYER M4 ;
      RECT 201.739 7.620 201.811 7.644 ;
    END
  END w0_wmask_in[210]
  PIN w0_wmask_in[211]
    DIRECTION INPUT ;
    USE SIGNAL ;
    SHAPE ABUTMENT ;
    PORT
      LAYER M4 ;
      RECT 201.739 7.764 201.811 7.788 ;
    END
  END w0_wmask_in[211]
  PIN w0_wmask_in[212]
    DIRECTION INPUT ;
    USE SIGNAL ;
    SHAPE ABUTMENT ;
    PORT
      LAYER M4 ;
      RECT 201.739 7.908 201.811 7.932 ;
    END
  END w0_wmask_in[212]
  PIN w0_wmask_in[213]
    DIRECTION INPUT ;
    USE SIGNAL ;
    SHAPE ABUTMENT ;
    PORT
      LAYER M4 ;
      RECT 201.739 8.052 201.811 8.076 ;
    END
  END w0_wmask_in[213]
  PIN w0_wmask_in[214]
    DIRECTION INPUT ;
    USE SIGNAL ;
    SHAPE ABUTMENT ;
    PORT
      LAYER M4 ;
      RECT 201.739 8.196 201.811 8.220 ;
    END
  END w0_wmask_in[214]
  PIN w0_wmask_in[215]
    DIRECTION INPUT ;
    USE SIGNAL ;
    SHAPE ABUTMENT ;
    PORT
      LAYER M4 ;
      RECT 201.739 8.340 201.811 8.364 ;
    END
  END w0_wmask_in[215]
  PIN w0_wmask_in[216]
    DIRECTION INPUT ;
    USE SIGNAL ;
    SHAPE ABUTMENT ;
    PORT
      LAYER M4 ;
      RECT 201.739 8.484 201.811 8.508 ;
    END
  END w0_wmask_in[216]
  PIN w0_wmask_in[217]
    DIRECTION INPUT ;
    USE SIGNAL ;
    SHAPE ABUTMENT ;
    PORT
      LAYER M4 ;
      RECT 201.739 8.628 201.811 8.652 ;
    END
  END w0_wmask_in[217]
  PIN w0_wmask_in[218]
    DIRECTION INPUT ;
    USE SIGNAL ;
    SHAPE ABUTMENT ;
    PORT
      LAYER M4 ;
      RECT 201.739 8.772 201.811 8.796 ;
    END
  END w0_wmask_in[218]
  PIN w0_wmask_in[219]
    DIRECTION INPUT ;
    USE SIGNAL ;
    SHAPE ABUTMENT ;
    PORT
      LAYER M4 ;
      RECT 201.739 8.916 201.811 8.940 ;
    END
  END w0_wmask_in[219]
  PIN w0_wmask_in[220]
    DIRECTION INPUT ;
    USE SIGNAL ;
    SHAPE ABUTMENT ;
    PORT
      LAYER M4 ;
      RECT 201.739 9.060 201.811 9.084 ;
    END
  END w0_wmask_in[220]
  PIN w0_wmask_in[221]
    DIRECTION INPUT ;
    USE SIGNAL ;
    SHAPE ABUTMENT ;
    PORT
      LAYER M4 ;
      RECT 201.739 9.204 201.811 9.228 ;
    END
  END w0_wmask_in[221]
  PIN w0_wmask_in[222]
    DIRECTION INPUT ;
    USE SIGNAL ;
    SHAPE ABUTMENT ;
    PORT
      LAYER M4 ;
      RECT 201.739 9.348 201.811 9.372 ;
    END
  END w0_wmask_in[222]
  PIN w0_wmask_in[223]
    DIRECTION INPUT ;
    USE SIGNAL ;
    SHAPE ABUTMENT ;
    PORT
      LAYER M4 ;
      RECT 201.739 9.492 201.811 9.516 ;
    END
  END w0_wmask_in[223]
  PIN w0_wmask_in[224]
    DIRECTION INPUT ;
    USE SIGNAL ;
    SHAPE ABUTMENT ;
    PORT
      LAYER M4 ;
      RECT 201.739 9.636 201.811 9.660 ;
    END
  END w0_wmask_in[224]
  PIN w0_wmask_in[225]
    DIRECTION INPUT ;
    USE SIGNAL ;
    SHAPE ABUTMENT ;
    PORT
      LAYER M4 ;
      RECT 201.739 9.780 201.811 9.804 ;
    END
  END w0_wmask_in[225]
  PIN w0_wmask_in[226]
    DIRECTION INPUT ;
    USE SIGNAL ;
    SHAPE ABUTMENT ;
    PORT
      LAYER M4 ;
      RECT 201.739 9.924 201.811 9.948 ;
    END
  END w0_wmask_in[226]
  PIN w0_wmask_in[227]
    DIRECTION INPUT ;
    USE SIGNAL ;
    SHAPE ABUTMENT ;
    PORT
      LAYER M4 ;
      RECT 201.739 10.068 201.811 10.092 ;
    END
  END w0_wmask_in[227]
  PIN w0_wmask_in[228]
    DIRECTION INPUT ;
    USE SIGNAL ;
    SHAPE ABUTMENT ;
    PORT
      LAYER M4 ;
      RECT 201.739 10.212 201.811 10.236 ;
    END
  END w0_wmask_in[228]
  PIN w0_wmask_in[229]
    DIRECTION INPUT ;
    USE SIGNAL ;
    SHAPE ABUTMENT ;
    PORT
      LAYER M4 ;
      RECT 201.739 10.356 201.811 10.380 ;
    END
  END w0_wmask_in[229]
  PIN w0_wmask_in[230]
    DIRECTION INPUT ;
    USE SIGNAL ;
    SHAPE ABUTMENT ;
    PORT
      LAYER M4 ;
      RECT 201.739 10.500 201.811 10.524 ;
    END
  END w0_wmask_in[230]
  PIN w0_wmask_in[231]
    DIRECTION INPUT ;
    USE SIGNAL ;
    SHAPE ABUTMENT ;
    PORT
      LAYER M4 ;
      RECT 201.739 10.644 201.811 10.668 ;
    END
  END w0_wmask_in[231]
  PIN w0_wmask_in[232]
    DIRECTION INPUT ;
    USE SIGNAL ;
    SHAPE ABUTMENT ;
    PORT
      LAYER M4 ;
      RECT 201.739 10.788 201.811 10.812 ;
    END
  END w0_wmask_in[232]
  PIN w0_wmask_in[233]
    DIRECTION INPUT ;
    USE SIGNAL ;
    SHAPE ABUTMENT ;
    PORT
      LAYER M4 ;
      RECT 201.739 10.932 201.811 10.956 ;
    END
  END w0_wmask_in[233]
  PIN w0_wmask_in[234]
    DIRECTION INPUT ;
    USE SIGNAL ;
    SHAPE ABUTMENT ;
    PORT
      LAYER M4 ;
      RECT 201.739 11.076 201.811 11.100 ;
    END
  END w0_wmask_in[234]
  PIN w0_wmask_in[235]
    DIRECTION INPUT ;
    USE SIGNAL ;
    SHAPE ABUTMENT ;
    PORT
      LAYER M4 ;
      RECT 201.739 11.220 201.811 11.244 ;
    END
  END w0_wmask_in[235]
  PIN w0_wmask_in[236]
    DIRECTION INPUT ;
    USE SIGNAL ;
    SHAPE ABUTMENT ;
    PORT
      LAYER M4 ;
      RECT 201.739 11.364 201.811 11.388 ;
    END
  END w0_wmask_in[236]
  PIN w0_wmask_in[237]
    DIRECTION INPUT ;
    USE SIGNAL ;
    SHAPE ABUTMENT ;
    PORT
      LAYER M4 ;
      RECT 201.739 11.508 201.811 11.532 ;
    END
  END w0_wmask_in[237]
  PIN w0_wmask_in[238]
    DIRECTION INPUT ;
    USE SIGNAL ;
    SHAPE ABUTMENT ;
    PORT
      LAYER M4 ;
      RECT 201.739 11.652 201.811 11.676 ;
    END
  END w0_wmask_in[238]
  PIN w0_wmask_in[239]
    DIRECTION INPUT ;
    USE SIGNAL ;
    SHAPE ABUTMENT ;
    PORT
      LAYER M4 ;
      RECT 201.739 11.796 201.811 11.820 ;
    END
  END w0_wmask_in[239]
  PIN w0_wmask_in[240]
    DIRECTION INPUT ;
    USE SIGNAL ;
    SHAPE ABUTMENT ;
    PORT
      LAYER M4 ;
      RECT 201.739 11.940 201.811 11.964 ;
    END
  END w0_wmask_in[240]
  PIN w0_wmask_in[241]
    DIRECTION INPUT ;
    USE SIGNAL ;
    SHAPE ABUTMENT ;
    PORT
      LAYER M4 ;
      RECT 201.739 12.084 201.811 12.108 ;
    END
  END w0_wmask_in[241]
  PIN w0_wmask_in[242]
    DIRECTION INPUT ;
    USE SIGNAL ;
    SHAPE ABUTMENT ;
    PORT
      LAYER M4 ;
      RECT 201.739 12.228 201.811 12.252 ;
    END
  END w0_wmask_in[242]
  PIN w0_wmask_in[243]
    DIRECTION INPUT ;
    USE SIGNAL ;
    SHAPE ABUTMENT ;
    PORT
      LAYER M4 ;
      RECT 201.739 12.372 201.811 12.396 ;
    END
  END w0_wmask_in[243]
  PIN w0_wmask_in[244]
    DIRECTION INPUT ;
    USE SIGNAL ;
    SHAPE ABUTMENT ;
    PORT
      LAYER M4 ;
      RECT 201.739 12.516 201.811 12.540 ;
    END
  END w0_wmask_in[244]
  PIN w0_wmask_in[245]
    DIRECTION INPUT ;
    USE SIGNAL ;
    SHAPE ABUTMENT ;
    PORT
      LAYER M4 ;
      RECT 201.739 12.660 201.811 12.684 ;
    END
  END w0_wmask_in[245]
  PIN w0_wmask_in[246]
    DIRECTION INPUT ;
    USE SIGNAL ;
    SHAPE ABUTMENT ;
    PORT
      LAYER M4 ;
      RECT 201.739 12.804 201.811 12.828 ;
    END
  END w0_wmask_in[246]
  PIN w0_wmask_in[247]
    DIRECTION INPUT ;
    USE SIGNAL ;
    SHAPE ABUTMENT ;
    PORT
      LAYER M4 ;
      RECT 201.739 12.948 201.811 12.972 ;
    END
  END w0_wmask_in[247]
  PIN w0_wmask_in[248]
    DIRECTION INPUT ;
    USE SIGNAL ;
    SHAPE ABUTMENT ;
    PORT
      LAYER M4 ;
      RECT 201.739 13.092 201.811 13.116 ;
    END
  END w0_wmask_in[248]
  PIN w0_wmask_in[249]
    DIRECTION INPUT ;
    USE SIGNAL ;
    SHAPE ABUTMENT ;
    PORT
      LAYER M4 ;
      RECT 201.739 13.236 201.811 13.260 ;
    END
  END w0_wmask_in[249]
  PIN w0_wmask_in[250]
    DIRECTION INPUT ;
    USE SIGNAL ;
    SHAPE ABUTMENT ;
    PORT
      LAYER M4 ;
      RECT 201.739 13.380 201.811 13.404 ;
    END
  END w0_wmask_in[250]
  PIN w0_wmask_in[251]
    DIRECTION INPUT ;
    USE SIGNAL ;
    SHAPE ABUTMENT ;
    PORT
      LAYER M4 ;
      RECT 201.739 13.524 201.811 13.548 ;
    END
  END w0_wmask_in[251]
  PIN w0_wmask_in[252]
    DIRECTION INPUT ;
    USE SIGNAL ;
    SHAPE ABUTMENT ;
    PORT
      LAYER M4 ;
      RECT 201.739 13.668 201.811 13.692 ;
    END
  END w0_wmask_in[252]
  PIN w0_wmask_in[253]
    DIRECTION INPUT ;
    USE SIGNAL ;
    SHAPE ABUTMENT ;
    PORT
      LAYER M4 ;
      RECT 201.739 13.812 201.811 13.836 ;
    END
  END w0_wmask_in[253]
  PIN w0_wmask_in[254]
    DIRECTION INPUT ;
    USE SIGNAL ;
    SHAPE ABUTMENT ;
    PORT
      LAYER M4 ;
      RECT 201.739 13.956 201.811 13.980 ;
    END
  END w0_wmask_in[254]
  PIN w0_wmask_in[255]
    DIRECTION INPUT ;
    USE SIGNAL ;
    SHAPE ABUTMENT ;
    PORT
      LAYER M4 ;
      RECT 201.739 14.100 201.811 14.124 ;
    END
  END w0_wmask_in[255]
  PIN w0_wmask_in[256]
    DIRECTION INPUT ;
    USE SIGNAL ;
    SHAPE ABUTMENT ;
    PORT
      LAYER M4 ;
      RECT 201.739 14.244 201.811 14.268 ;
    END
  END w0_wmask_in[256]
  PIN w0_wmask_in[257]
    DIRECTION INPUT ;
    USE SIGNAL ;
    SHAPE ABUTMENT ;
    PORT
      LAYER M4 ;
      RECT 201.739 14.388 201.811 14.412 ;
    END
  END w0_wmask_in[257]
  PIN w0_wmask_in[258]
    DIRECTION INPUT ;
    USE SIGNAL ;
    SHAPE ABUTMENT ;
    PORT
      LAYER M4 ;
      RECT 201.739 14.532 201.811 14.556 ;
    END
  END w0_wmask_in[258]
  PIN w0_wmask_in[259]
    DIRECTION INPUT ;
    USE SIGNAL ;
    SHAPE ABUTMENT ;
    PORT
      LAYER M4 ;
      RECT 201.739 14.676 201.811 14.700 ;
    END
  END w0_wmask_in[259]
  PIN w0_wmask_in[260]
    DIRECTION INPUT ;
    USE SIGNAL ;
    SHAPE ABUTMENT ;
    PORT
      LAYER M4 ;
      RECT 201.739 14.820 201.811 14.844 ;
    END
  END w0_wmask_in[260]
  PIN w0_wmask_in[261]
    DIRECTION INPUT ;
    USE SIGNAL ;
    SHAPE ABUTMENT ;
    PORT
      LAYER M4 ;
      RECT 201.739 14.964 201.811 14.988 ;
    END
  END w0_wmask_in[261]
  PIN w0_wmask_in[262]
    DIRECTION INPUT ;
    USE SIGNAL ;
    SHAPE ABUTMENT ;
    PORT
      LAYER M4 ;
      RECT 201.739 15.108 201.811 15.132 ;
    END
  END w0_wmask_in[262]
  PIN w0_wmask_in[263]
    DIRECTION INPUT ;
    USE SIGNAL ;
    SHAPE ABUTMENT ;
    PORT
      LAYER M4 ;
      RECT 201.739 15.252 201.811 15.276 ;
    END
  END w0_wmask_in[263]
  PIN w0_wmask_in[264]
    DIRECTION INPUT ;
    USE SIGNAL ;
    SHAPE ABUTMENT ;
    PORT
      LAYER M4 ;
      RECT 201.739 15.396 201.811 15.420 ;
    END
  END w0_wmask_in[264]
  PIN w0_wmask_in[265]
    DIRECTION INPUT ;
    USE SIGNAL ;
    SHAPE ABUTMENT ;
    PORT
      LAYER M4 ;
      RECT 201.739 15.540 201.811 15.564 ;
    END
  END w0_wmask_in[265]
  PIN w0_wmask_in[266]
    DIRECTION INPUT ;
    USE SIGNAL ;
    SHAPE ABUTMENT ;
    PORT
      LAYER M4 ;
      RECT 201.739 15.684 201.811 15.708 ;
    END
  END w0_wmask_in[266]
  PIN w0_wmask_in[267]
    DIRECTION INPUT ;
    USE SIGNAL ;
    SHAPE ABUTMENT ;
    PORT
      LAYER M4 ;
      RECT 201.739 15.828 201.811 15.852 ;
    END
  END w0_wmask_in[267]
  PIN w0_wmask_in[268]
    DIRECTION INPUT ;
    USE SIGNAL ;
    SHAPE ABUTMENT ;
    PORT
      LAYER M4 ;
      RECT 201.739 15.972 201.811 15.996 ;
    END
  END w0_wmask_in[268]
  PIN w0_wmask_in[269]
    DIRECTION INPUT ;
    USE SIGNAL ;
    SHAPE ABUTMENT ;
    PORT
      LAYER M4 ;
      RECT 201.739 16.116 201.811 16.140 ;
    END
  END w0_wmask_in[269]
  PIN w0_wmask_in[270]
    DIRECTION INPUT ;
    USE SIGNAL ;
    SHAPE ABUTMENT ;
    PORT
      LAYER M4 ;
      RECT 201.739 16.260 201.811 16.284 ;
    END
  END w0_wmask_in[270]
  PIN w0_wmask_in[271]
    DIRECTION INPUT ;
    USE SIGNAL ;
    SHAPE ABUTMENT ;
    PORT
      LAYER M4 ;
      RECT 201.739 16.404 201.811 16.428 ;
    END
  END w0_wmask_in[271]
  PIN w0_wmask_in[272]
    DIRECTION INPUT ;
    USE SIGNAL ;
    SHAPE ABUTMENT ;
    PORT
      LAYER M4 ;
      RECT 201.739 16.548 201.811 16.572 ;
    END
  END w0_wmask_in[272]
  PIN w0_wmask_in[273]
    DIRECTION INPUT ;
    USE SIGNAL ;
    SHAPE ABUTMENT ;
    PORT
      LAYER M4 ;
      RECT 201.739 16.692 201.811 16.716 ;
    END
  END w0_wmask_in[273]
  PIN w0_wmask_in[274]
    DIRECTION INPUT ;
    USE SIGNAL ;
    SHAPE ABUTMENT ;
    PORT
      LAYER M4 ;
      RECT 201.739 16.836 201.811 16.860 ;
    END
  END w0_wmask_in[274]
  PIN w0_wmask_in[275]
    DIRECTION INPUT ;
    USE SIGNAL ;
    SHAPE ABUTMENT ;
    PORT
      LAYER M4 ;
      RECT 201.739 16.980 201.811 17.004 ;
    END
  END w0_wmask_in[275]
  PIN w0_wmask_in[276]
    DIRECTION INPUT ;
    USE SIGNAL ;
    SHAPE ABUTMENT ;
    PORT
      LAYER M4 ;
      RECT 201.739 17.124 201.811 17.148 ;
    END
  END w0_wmask_in[276]
  PIN w0_wmask_in[277]
    DIRECTION INPUT ;
    USE SIGNAL ;
    SHAPE ABUTMENT ;
    PORT
      LAYER M4 ;
      RECT 201.739 17.268 201.811 17.292 ;
    END
  END w0_wmask_in[277]
  PIN w0_wmask_in[278]
    DIRECTION INPUT ;
    USE SIGNAL ;
    SHAPE ABUTMENT ;
    PORT
      LAYER M4 ;
      RECT 201.739 17.412 201.811 17.436 ;
    END
  END w0_wmask_in[278]
  PIN w0_wmask_in[279]
    DIRECTION INPUT ;
    USE SIGNAL ;
    SHAPE ABUTMENT ;
    PORT
      LAYER M4 ;
      RECT 201.739 17.556 201.811 17.580 ;
    END
  END w0_wmask_in[279]
  PIN w0_wmask_in[280]
    DIRECTION INPUT ;
    USE SIGNAL ;
    SHAPE ABUTMENT ;
    PORT
      LAYER M4 ;
      RECT 201.739 17.700 201.811 17.724 ;
    END
  END w0_wmask_in[280]
  PIN w0_wmask_in[281]
    DIRECTION INPUT ;
    USE SIGNAL ;
    SHAPE ABUTMENT ;
    PORT
      LAYER M4 ;
      RECT 201.739 17.844 201.811 17.868 ;
    END
  END w0_wmask_in[281]
  PIN w0_wmask_in[282]
    DIRECTION INPUT ;
    USE SIGNAL ;
    SHAPE ABUTMENT ;
    PORT
      LAYER M4 ;
      RECT 201.739 17.988 201.811 18.012 ;
    END
  END w0_wmask_in[282]
  PIN w0_wmask_in[283]
    DIRECTION INPUT ;
    USE SIGNAL ;
    SHAPE ABUTMENT ;
    PORT
      LAYER M4 ;
      RECT 201.739 18.132 201.811 18.156 ;
    END
  END w0_wmask_in[283]
  PIN w0_wmask_in[284]
    DIRECTION INPUT ;
    USE SIGNAL ;
    SHAPE ABUTMENT ;
    PORT
      LAYER M4 ;
      RECT 201.739 18.276 201.811 18.300 ;
    END
  END w0_wmask_in[284]
  PIN w0_wmask_in[285]
    DIRECTION INPUT ;
    USE SIGNAL ;
    SHAPE ABUTMENT ;
    PORT
      LAYER M4 ;
      RECT 201.739 18.420 201.811 18.444 ;
    END
  END w0_wmask_in[285]
  PIN w0_wmask_in[286]
    DIRECTION INPUT ;
    USE SIGNAL ;
    SHAPE ABUTMENT ;
    PORT
      LAYER M4 ;
      RECT 201.739 18.564 201.811 18.588 ;
    END
  END w0_wmask_in[286]
  PIN w0_wmask_in[287]
    DIRECTION INPUT ;
    USE SIGNAL ;
    SHAPE ABUTMENT ;
    PORT
      LAYER M4 ;
      RECT 201.739 18.708 201.811 18.732 ;
    END
  END w0_wmask_in[287]
  PIN w0_wmask_in[288]
    DIRECTION INPUT ;
    USE SIGNAL ;
    SHAPE ABUTMENT ;
    PORT
      LAYER M4 ;
      RECT 201.739 18.852 201.811 18.876 ;
    END
  END w0_wmask_in[288]
  PIN w0_wmask_in[289]
    DIRECTION INPUT ;
    USE SIGNAL ;
    SHAPE ABUTMENT ;
    PORT
      LAYER M4 ;
      RECT 201.739 18.996 201.811 19.020 ;
    END
  END w0_wmask_in[289]
  PIN w0_wmask_in[290]
    DIRECTION INPUT ;
    USE SIGNAL ;
    SHAPE ABUTMENT ;
    PORT
      LAYER M4 ;
      RECT 201.739 19.140 201.811 19.164 ;
    END
  END w0_wmask_in[290]
  PIN w0_wmask_in[291]
    DIRECTION INPUT ;
    USE SIGNAL ;
    SHAPE ABUTMENT ;
    PORT
      LAYER M4 ;
      RECT 201.739 19.284 201.811 19.308 ;
    END
  END w0_wmask_in[291]
  PIN w0_wmask_in[292]
    DIRECTION INPUT ;
    USE SIGNAL ;
    SHAPE ABUTMENT ;
    PORT
      LAYER M4 ;
      RECT 201.739 19.428 201.811 19.452 ;
    END
  END w0_wmask_in[292]
  PIN w0_wmask_in[293]
    DIRECTION INPUT ;
    USE SIGNAL ;
    SHAPE ABUTMENT ;
    PORT
      LAYER M4 ;
      RECT 201.739 19.572 201.811 19.596 ;
    END
  END w0_wmask_in[293]
  PIN w0_wmask_in[294]
    DIRECTION INPUT ;
    USE SIGNAL ;
    SHAPE ABUTMENT ;
    PORT
      LAYER M4 ;
      RECT 201.739 19.716 201.811 19.740 ;
    END
  END w0_wmask_in[294]
  PIN w0_wmask_in[295]
    DIRECTION INPUT ;
    USE SIGNAL ;
    SHAPE ABUTMENT ;
    PORT
      LAYER M4 ;
      RECT 201.739 19.860 201.811 19.884 ;
    END
  END w0_wmask_in[295]
  PIN w0_wmask_in[296]
    DIRECTION INPUT ;
    USE SIGNAL ;
    SHAPE ABUTMENT ;
    PORT
      LAYER M4 ;
      RECT 201.739 20.004 201.811 20.028 ;
    END
  END w0_wmask_in[296]
  PIN w0_wmask_in[297]
    DIRECTION INPUT ;
    USE SIGNAL ;
    SHAPE ABUTMENT ;
    PORT
      LAYER M4 ;
      RECT 201.739 20.148 201.811 20.172 ;
    END
  END w0_wmask_in[297]
  PIN w0_wmask_in[298]
    DIRECTION INPUT ;
    USE SIGNAL ;
    SHAPE ABUTMENT ;
    PORT
      LAYER M4 ;
      RECT 201.739 20.292 201.811 20.316 ;
    END
  END w0_wmask_in[298]
  PIN w0_wmask_in[299]
    DIRECTION INPUT ;
    USE SIGNAL ;
    SHAPE ABUTMENT ;
    PORT
      LAYER M4 ;
      RECT 201.739 20.436 201.811 20.460 ;
    END
  END w0_wmask_in[299]
  PIN w0_wmask_in[300]
    DIRECTION INPUT ;
    USE SIGNAL ;
    SHAPE ABUTMENT ;
    PORT
      LAYER M4 ;
      RECT 201.739 20.580 201.811 20.604 ;
    END
  END w0_wmask_in[300]
  PIN w0_wmask_in[301]
    DIRECTION INPUT ;
    USE SIGNAL ;
    SHAPE ABUTMENT ;
    PORT
      LAYER M4 ;
      RECT 201.739 20.724 201.811 20.748 ;
    END
  END w0_wmask_in[301]
  PIN w0_wmask_in[302]
    DIRECTION INPUT ;
    USE SIGNAL ;
    SHAPE ABUTMENT ;
    PORT
      LAYER M4 ;
      RECT 201.739 20.868 201.811 20.892 ;
    END
  END w0_wmask_in[302]
  PIN w0_wmask_in[303]
    DIRECTION INPUT ;
    USE SIGNAL ;
    SHAPE ABUTMENT ;
    PORT
      LAYER M4 ;
      RECT 201.739 21.012 201.811 21.036 ;
    END
  END w0_wmask_in[303]
  PIN w0_wmask_in[304]
    DIRECTION INPUT ;
    USE SIGNAL ;
    SHAPE ABUTMENT ;
    PORT
      LAYER M4 ;
      RECT 201.739 21.156 201.811 21.180 ;
    END
  END w0_wmask_in[304]
  PIN w0_wmask_in[305]
    DIRECTION INPUT ;
    USE SIGNAL ;
    SHAPE ABUTMENT ;
    PORT
      LAYER M4 ;
      RECT 201.739 21.300 201.811 21.324 ;
    END
  END w0_wmask_in[305]
  PIN w0_wmask_in[306]
    DIRECTION INPUT ;
    USE SIGNAL ;
    SHAPE ABUTMENT ;
    PORT
      LAYER M4 ;
      RECT 201.739 21.444 201.811 21.468 ;
    END
  END w0_wmask_in[306]
  PIN w0_wmask_in[307]
    DIRECTION INPUT ;
    USE SIGNAL ;
    SHAPE ABUTMENT ;
    PORT
      LAYER M4 ;
      RECT 201.739 21.588 201.811 21.612 ;
    END
  END w0_wmask_in[307]
  PIN w0_wmask_in[308]
    DIRECTION INPUT ;
    USE SIGNAL ;
    SHAPE ABUTMENT ;
    PORT
      LAYER M4 ;
      RECT 201.739 21.732 201.811 21.756 ;
    END
  END w0_wmask_in[308]
  PIN w0_wmask_in[309]
    DIRECTION INPUT ;
    USE SIGNAL ;
    SHAPE ABUTMENT ;
    PORT
      LAYER M4 ;
      RECT 201.739 21.876 201.811 21.900 ;
    END
  END w0_wmask_in[309]
  PIN w0_wmask_in[310]
    DIRECTION INPUT ;
    USE SIGNAL ;
    SHAPE ABUTMENT ;
    PORT
      LAYER M4 ;
      RECT 201.739 22.020 201.811 22.044 ;
    END
  END w0_wmask_in[310]
  PIN w0_wmask_in[311]
    DIRECTION INPUT ;
    USE SIGNAL ;
    SHAPE ABUTMENT ;
    PORT
      LAYER M4 ;
      RECT 201.739 22.164 201.811 22.188 ;
    END
  END w0_wmask_in[311]
  PIN w0_wmask_in[312]
    DIRECTION INPUT ;
    USE SIGNAL ;
    SHAPE ABUTMENT ;
    PORT
      LAYER M4 ;
      RECT 201.739 22.308 201.811 22.332 ;
    END
  END w0_wmask_in[312]
  PIN w0_wmask_in[313]
    DIRECTION INPUT ;
    USE SIGNAL ;
    SHAPE ABUTMENT ;
    PORT
      LAYER M4 ;
      RECT 201.739 22.452 201.811 22.476 ;
    END
  END w0_wmask_in[313]
  PIN w0_wmask_in[314]
    DIRECTION INPUT ;
    USE SIGNAL ;
    SHAPE ABUTMENT ;
    PORT
      LAYER M4 ;
      RECT 201.739 22.596 201.811 22.620 ;
    END
  END w0_wmask_in[314]
  PIN w0_wmask_in[315]
    DIRECTION INPUT ;
    USE SIGNAL ;
    SHAPE ABUTMENT ;
    PORT
      LAYER M4 ;
      RECT 201.739 22.740 201.811 22.764 ;
    END
  END w0_wmask_in[315]
  PIN w0_wmask_in[316]
    DIRECTION INPUT ;
    USE SIGNAL ;
    SHAPE ABUTMENT ;
    PORT
      LAYER M4 ;
      RECT 201.739 22.884 201.811 22.908 ;
    END
  END w0_wmask_in[316]
  PIN w0_wmask_in[317]
    DIRECTION INPUT ;
    USE SIGNAL ;
    SHAPE ABUTMENT ;
    PORT
      LAYER M3 ;
      RECT 0.207 56.359 0.225 56.413 ;
    END
  END w0_wmask_in[317]
  PIN w0_wmask_in[318]
    DIRECTION INPUT ;
    USE SIGNAL ;
    SHAPE ABUTMENT ;
    PORT
      LAYER M3 ;
      RECT 0.495 56.359 0.513 56.413 ;
    END
  END w0_wmask_in[318]
  PIN w0_wmask_in[319]
    DIRECTION INPUT ;
    USE SIGNAL ;
    SHAPE ABUTMENT ;
    PORT
      LAYER M3 ;
      RECT 0.783 56.359 0.801 56.413 ;
    END
  END w0_wmask_in[319]
  PIN w0_wmask_in[320]
    DIRECTION INPUT ;
    USE SIGNAL ;
    SHAPE ABUTMENT ;
    PORT
      LAYER M3 ;
      RECT 1.071 56.359 1.089 56.413 ;
    END
  END w0_wmask_in[320]
  PIN w0_wmask_in[321]
    DIRECTION INPUT ;
    USE SIGNAL ;
    SHAPE ABUTMENT ;
    PORT
      LAYER M3 ;
      RECT 1.359 56.359 1.377 56.413 ;
    END
  END w0_wmask_in[321]
  PIN w0_wmask_in[322]
    DIRECTION INPUT ;
    USE SIGNAL ;
    SHAPE ABUTMENT ;
    PORT
      LAYER M3 ;
      RECT 1.647 56.359 1.665 56.413 ;
    END
  END w0_wmask_in[322]
  PIN w0_wmask_in[323]
    DIRECTION INPUT ;
    USE SIGNAL ;
    SHAPE ABUTMENT ;
    PORT
      LAYER M3 ;
      RECT 1.935 56.359 1.953 56.413 ;
    END
  END w0_wmask_in[323]
  PIN w0_wmask_in[324]
    DIRECTION INPUT ;
    USE SIGNAL ;
    SHAPE ABUTMENT ;
    PORT
      LAYER M3 ;
      RECT 2.223 56.359 2.241 56.413 ;
    END
  END w0_wmask_in[324]
  PIN w0_wmask_in[325]
    DIRECTION INPUT ;
    USE SIGNAL ;
    SHAPE ABUTMENT ;
    PORT
      LAYER M3 ;
      RECT 2.511 56.359 2.529 56.413 ;
    END
  END w0_wmask_in[325]
  PIN w0_wmask_in[326]
    DIRECTION INPUT ;
    USE SIGNAL ;
    SHAPE ABUTMENT ;
    PORT
      LAYER M3 ;
      RECT 2.799 56.359 2.817 56.413 ;
    END
  END w0_wmask_in[326]
  PIN w0_wmask_in[327]
    DIRECTION INPUT ;
    USE SIGNAL ;
    SHAPE ABUTMENT ;
    PORT
      LAYER M3 ;
      RECT 3.087 56.359 3.105 56.413 ;
    END
  END w0_wmask_in[327]
  PIN w0_wmask_in[328]
    DIRECTION INPUT ;
    USE SIGNAL ;
    SHAPE ABUTMENT ;
    PORT
      LAYER M3 ;
      RECT 3.375 56.359 3.393 56.413 ;
    END
  END w0_wmask_in[328]
  PIN w0_wmask_in[329]
    DIRECTION INPUT ;
    USE SIGNAL ;
    SHAPE ABUTMENT ;
    PORT
      LAYER M3 ;
      RECT 3.663 56.359 3.681 56.413 ;
    END
  END w0_wmask_in[329]
  PIN w0_wmask_in[330]
    DIRECTION INPUT ;
    USE SIGNAL ;
    SHAPE ABUTMENT ;
    PORT
      LAYER M3 ;
      RECT 3.951 56.359 3.969 56.413 ;
    END
  END w0_wmask_in[330]
  PIN w0_wmask_in[331]
    DIRECTION INPUT ;
    USE SIGNAL ;
    SHAPE ABUTMENT ;
    PORT
      LAYER M3 ;
      RECT 4.239 56.359 4.257 56.413 ;
    END
  END w0_wmask_in[331]
  PIN w0_wmask_in[332]
    DIRECTION INPUT ;
    USE SIGNAL ;
    SHAPE ABUTMENT ;
    PORT
      LAYER M3 ;
      RECT 4.527 56.359 4.545 56.413 ;
    END
  END w0_wmask_in[332]
  PIN w0_wmask_in[333]
    DIRECTION INPUT ;
    USE SIGNAL ;
    SHAPE ABUTMENT ;
    PORT
      LAYER M3 ;
      RECT 4.815 56.359 4.833 56.413 ;
    END
  END w0_wmask_in[333]
  PIN w0_wmask_in[334]
    DIRECTION INPUT ;
    USE SIGNAL ;
    SHAPE ABUTMENT ;
    PORT
      LAYER M3 ;
      RECT 5.103 56.359 5.121 56.413 ;
    END
  END w0_wmask_in[334]
  PIN w0_wmask_in[335]
    DIRECTION INPUT ;
    USE SIGNAL ;
    SHAPE ABUTMENT ;
    PORT
      LAYER M3 ;
      RECT 5.391 56.359 5.409 56.413 ;
    END
  END w0_wmask_in[335]
  PIN w0_wmask_in[336]
    DIRECTION INPUT ;
    USE SIGNAL ;
    SHAPE ABUTMENT ;
    PORT
      LAYER M3 ;
      RECT 5.679 56.359 5.697 56.413 ;
    END
  END w0_wmask_in[336]
  PIN w0_wmask_in[337]
    DIRECTION INPUT ;
    USE SIGNAL ;
    SHAPE ABUTMENT ;
    PORT
      LAYER M3 ;
      RECT 5.967 56.359 5.985 56.413 ;
    END
  END w0_wmask_in[337]
  PIN w0_wmask_in[338]
    DIRECTION INPUT ;
    USE SIGNAL ;
    SHAPE ABUTMENT ;
    PORT
      LAYER M3 ;
      RECT 6.255 56.359 6.273 56.413 ;
    END
  END w0_wmask_in[338]
  PIN w0_wmask_in[339]
    DIRECTION INPUT ;
    USE SIGNAL ;
    SHAPE ABUTMENT ;
    PORT
      LAYER M3 ;
      RECT 6.543 56.359 6.561 56.413 ;
    END
  END w0_wmask_in[339]
  PIN w0_wmask_in[340]
    DIRECTION INPUT ;
    USE SIGNAL ;
    SHAPE ABUTMENT ;
    PORT
      LAYER M3 ;
      RECT 6.831 56.359 6.849 56.413 ;
    END
  END w0_wmask_in[340]
  PIN w0_wmask_in[341]
    DIRECTION INPUT ;
    USE SIGNAL ;
    SHAPE ABUTMENT ;
    PORT
      LAYER M3 ;
      RECT 7.119 56.359 7.137 56.413 ;
    END
  END w0_wmask_in[341]
  PIN w0_wmask_in[342]
    DIRECTION INPUT ;
    USE SIGNAL ;
    SHAPE ABUTMENT ;
    PORT
      LAYER M3 ;
      RECT 7.407 56.359 7.425 56.413 ;
    END
  END w0_wmask_in[342]
  PIN w0_wmask_in[343]
    DIRECTION INPUT ;
    USE SIGNAL ;
    SHAPE ABUTMENT ;
    PORT
      LAYER M3 ;
      RECT 7.695 56.359 7.713 56.413 ;
    END
  END w0_wmask_in[343]
  PIN w0_wmask_in[344]
    DIRECTION INPUT ;
    USE SIGNAL ;
    SHAPE ABUTMENT ;
    PORT
      LAYER M3 ;
      RECT 7.983 56.359 8.001 56.413 ;
    END
  END w0_wmask_in[344]
  PIN w0_wmask_in[345]
    DIRECTION INPUT ;
    USE SIGNAL ;
    SHAPE ABUTMENT ;
    PORT
      LAYER M3 ;
      RECT 8.271 56.359 8.289 56.413 ;
    END
  END w0_wmask_in[345]
  PIN w0_wmask_in[346]
    DIRECTION INPUT ;
    USE SIGNAL ;
    SHAPE ABUTMENT ;
    PORT
      LAYER M3 ;
      RECT 8.559 56.359 8.577 56.413 ;
    END
  END w0_wmask_in[346]
  PIN w0_wmask_in[347]
    DIRECTION INPUT ;
    USE SIGNAL ;
    SHAPE ABUTMENT ;
    PORT
      LAYER M3 ;
      RECT 8.847 56.359 8.865 56.413 ;
    END
  END w0_wmask_in[347]
  PIN w0_wmask_in[348]
    DIRECTION INPUT ;
    USE SIGNAL ;
    SHAPE ABUTMENT ;
    PORT
      LAYER M3 ;
      RECT 9.135 56.359 9.153 56.413 ;
    END
  END w0_wmask_in[348]
  PIN w0_wmask_in[349]
    DIRECTION INPUT ;
    USE SIGNAL ;
    SHAPE ABUTMENT ;
    PORT
      LAYER M3 ;
      RECT 9.423 56.359 9.441 56.413 ;
    END
  END w0_wmask_in[349]
  PIN w0_wmask_in[350]
    DIRECTION INPUT ;
    USE SIGNAL ;
    SHAPE ABUTMENT ;
    PORT
      LAYER M3 ;
      RECT 9.711 56.359 9.729 56.413 ;
    END
  END w0_wmask_in[350]
  PIN w0_wmask_in[351]
    DIRECTION INPUT ;
    USE SIGNAL ;
    SHAPE ABUTMENT ;
    PORT
      LAYER M3 ;
      RECT 9.999 56.359 10.017 56.413 ;
    END
  END w0_wmask_in[351]
  PIN w0_wmask_in[352]
    DIRECTION INPUT ;
    USE SIGNAL ;
    SHAPE ABUTMENT ;
    PORT
      LAYER M3 ;
      RECT 10.287 56.359 10.305 56.413 ;
    END
  END w0_wmask_in[352]
  PIN w0_wmask_in[353]
    DIRECTION INPUT ;
    USE SIGNAL ;
    SHAPE ABUTMENT ;
    PORT
      LAYER M3 ;
      RECT 10.575 56.359 10.593 56.413 ;
    END
  END w0_wmask_in[353]
  PIN w0_wmask_in[354]
    DIRECTION INPUT ;
    USE SIGNAL ;
    SHAPE ABUTMENT ;
    PORT
      LAYER M3 ;
      RECT 10.863 56.359 10.881 56.413 ;
    END
  END w0_wmask_in[354]
  PIN w0_wmask_in[355]
    DIRECTION INPUT ;
    USE SIGNAL ;
    SHAPE ABUTMENT ;
    PORT
      LAYER M3 ;
      RECT 11.151 56.359 11.169 56.413 ;
    END
  END w0_wmask_in[355]
  PIN w0_wmask_in[356]
    DIRECTION INPUT ;
    USE SIGNAL ;
    SHAPE ABUTMENT ;
    PORT
      LAYER M3 ;
      RECT 11.439 56.359 11.457 56.413 ;
    END
  END w0_wmask_in[356]
  PIN w0_wmask_in[357]
    DIRECTION INPUT ;
    USE SIGNAL ;
    SHAPE ABUTMENT ;
    PORT
      LAYER M3 ;
      RECT 11.727 56.359 11.745 56.413 ;
    END
  END w0_wmask_in[357]
  PIN w0_wmask_in[358]
    DIRECTION INPUT ;
    USE SIGNAL ;
    SHAPE ABUTMENT ;
    PORT
      LAYER M3 ;
      RECT 12.015 56.359 12.033 56.413 ;
    END
  END w0_wmask_in[358]
  PIN w0_wmask_in[359]
    DIRECTION INPUT ;
    USE SIGNAL ;
    SHAPE ABUTMENT ;
    PORT
      LAYER M3 ;
      RECT 12.303 56.359 12.321 56.413 ;
    END
  END w0_wmask_in[359]
  PIN w0_wmask_in[360]
    DIRECTION INPUT ;
    USE SIGNAL ;
    SHAPE ABUTMENT ;
    PORT
      LAYER M3 ;
      RECT 12.591 56.359 12.609 56.413 ;
    END
  END w0_wmask_in[360]
  PIN w0_wmask_in[361]
    DIRECTION INPUT ;
    USE SIGNAL ;
    SHAPE ABUTMENT ;
    PORT
      LAYER M3 ;
      RECT 12.879 56.359 12.897 56.413 ;
    END
  END w0_wmask_in[361]
  PIN w0_wmask_in[362]
    DIRECTION INPUT ;
    USE SIGNAL ;
    SHAPE ABUTMENT ;
    PORT
      LAYER M3 ;
      RECT 13.167 56.359 13.185 56.413 ;
    END
  END w0_wmask_in[362]
  PIN w0_wmask_in[363]
    DIRECTION INPUT ;
    USE SIGNAL ;
    SHAPE ABUTMENT ;
    PORT
      LAYER M3 ;
      RECT 13.455 56.359 13.473 56.413 ;
    END
  END w0_wmask_in[363]
  PIN w0_wmask_in[364]
    DIRECTION INPUT ;
    USE SIGNAL ;
    SHAPE ABUTMENT ;
    PORT
      LAYER M3 ;
      RECT 13.743 56.359 13.761 56.413 ;
    END
  END w0_wmask_in[364]
  PIN w0_wmask_in[365]
    DIRECTION INPUT ;
    USE SIGNAL ;
    SHAPE ABUTMENT ;
    PORT
      LAYER M3 ;
      RECT 14.031 56.359 14.049 56.413 ;
    END
  END w0_wmask_in[365]
  PIN w0_wmask_in[366]
    DIRECTION INPUT ;
    USE SIGNAL ;
    SHAPE ABUTMENT ;
    PORT
      LAYER M3 ;
      RECT 14.319 56.359 14.337 56.413 ;
    END
  END w0_wmask_in[366]
  PIN w0_wmask_in[367]
    DIRECTION INPUT ;
    USE SIGNAL ;
    SHAPE ABUTMENT ;
    PORT
      LAYER M3 ;
      RECT 14.607 56.359 14.625 56.413 ;
    END
  END w0_wmask_in[367]
  PIN w0_wmask_in[368]
    DIRECTION INPUT ;
    USE SIGNAL ;
    SHAPE ABUTMENT ;
    PORT
      LAYER M3 ;
      RECT 14.895 56.359 14.913 56.413 ;
    END
  END w0_wmask_in[368]
  PIN w0_wmask_in[369]
    DIRECTION INPUT ;
    USE SIGNAL ;
    SHAPE ABUTMENT ;
    PORT
      LAYER M3 ;
      RECT 15.183 56.359 15.201 56.413 ;
    END
  END w0_wmask_in[369]
  PIN w0_wmask_in[370]
    DIRECTION INPUT ;
    USE SIGNAL ;
    SHAPE ABUTMENT ;
    PORT
      LAYER M3 ;
      RECT 15.471 56.359 15.489 56.413 ;
    END
  END w0_wmask_in[370]
  PIN w0_wmask_in[371]
    DIRECTION INPUT ;
    USE SIGNAL ;
    SHAPE ABUTMENT ;
    PORT
      LAYER M3 ;
      RECT 15.759 56.359 15.777 56.413 ;
    END
  END w0_wmask_in[371]
  PIN w0_wmask_in[372]
    DIRECTION INPUT ;
    USE SIGNAL ;
    SHAPE ABUTMENT ;
    PORT
      LAYER M3 ;
      RECT 16.047 56.359 16.065 56.413 ;
    END
  END w0_wmask_in[372]
  PIN w0_wmask_in[373]
    DIRECTION INPUT ;
    USE SIGNAL ;
    SHAPE ABUTMENT ;
    PORT
      LAYER M3 ;
      RECT 16.335 56.359 16.353 56.413 ;
    END
  END w0_wmask_in[373]
  PIN w0_wmask_in[374]
    DIRECTION INPUT ;
    USE SIGNAL ;
    SHAPE ABUTMENT ;
    PORT
      LAYER M3 ;
      RECT 16.623 56.359 16.641 56.413 ;
    END
  END w0_wmask_in[374]
  PIN w0_wmask_in[375]
    DIRECTION INPUT ;
    USE SIGNAL ;
    SHAPE ABUTMENT ;
    PORT
      LAYER M3 ;
      RECT 16.911 56.359 16.929 56.413 ;
    END
  END w0_wmask_in[375]
  PIN w0_wmask_in[376]
    DIRECTION INPUT ;
    USE SIGNAL ;
    SHAPE ABUTMENT ;
    PORT
      LAYER M3 ;
      RECT 17.199 56.359 17.217 56.413 ;
    END
  END w0_wmask_in[376]
  PIN w0_wmask_in[377]
    DIRECTION INPUT ;
    USE SIGNAL ;
    SHAPE ABUTMENT ;
    PORT
      LAYER M3 ;
      RECT 17.487 56.359 17.505 56.413 ;
    END
  END w0_wmask_in[377]
  PIN w0_wmask_in[378]
    DIRECTION INPUT ;
    USE SIGNAL ;
    SHAPE ABUTMENT ;
    PORT
      LAYER M3 ;
      RECT 17.775 56.359 17.793 56.413 ;
    END
  END w0_wmask_in[378]
  PIN w0_wmask_in[379]
    DIRECTION INPUT ;
    USE SIGNAL ;
    SHAPE ABUTMENT ;
    PORT
      LAYER M3 ;
      RECT 18.063 56.359 18.081 56.413 ;
    END
  END w0_wmask_in[379]
  PIN w0_wmask_in[380]
    DIRECTION INPUT ;
    USE SIGNAL ;
    SHAPE ABUTMENT ;
    PORT
      LAYER M3 ;
      RECT 18.351 56.359 18.369 56.413 ;
    END
  END w0_wmask_in[380]
  PIN w0_wmask_in[381]
    DIRECTION INPUT ;
    USE SIGNAL ;
    SHAPE ABUTMENT ;
    PORT
      LAYER M3 ;
      RECT 18.639 56.359 18.657 56.413 ;
    END
  END w0_wmask_in[381]
  PIN w0_wmask_in[382]
    DIRECTION INPUT ;
    USE SIGNAL ;
    SHAPE ABUTMENT ;
    PORT
      LAYER M3 ;
      RECT 18.927 56.359 18.945 56.413 ;
    END
  END w0_wmask_in[382]
  PIN w0_wmask_in[383]
    DIRECTION INPUT ;
    USE SIGNAL ;
    SHAPE ABUTMENT ;
    PORT
      LAYER M3 ;
      RECT 19.215 56.359 19.233 56.413 ;
    END
  END w0_wmask_in[383]
  PIN w0_wmask_in[384]
    DIRECTION INPUT ;
    USE SIGNAL ;
    SHAPE ABUTMENT ;
    PORT
      LAYER M3 ;
      RECT 19.503 56.359 19.521 56.413 ;
    END
  END w0_wmask_in[384]
  PIN w0_wmask_in[385]
    DIRECTION INPUT ;
    USE SIGNAL ;
    SHAPE ABUTMENT ;
    PORT
      LAYER M3 ;
      RECT 19.791 56.359 19.809 56.413 ;
    END
  END w0_wmask_in[385]
  PIN w0_wmask_in[386]
    DIRECTION INPUT ;
    USE SIGNAL ;
    SHAPE ABUTMENT ;
    PORT
      LAYER M3 ;
      RECT 20.079 56.359 20.097 56.413 ;
    END
  END w0_wmask_in[386]
  PIN w0_wmask_in[387]
    DIRECTION INPUT ;
    USE SIGNAL ;
    SHAPE ABUTMENT ;
    PORT
      LAYER M3 ;
      RECT 20.367 56.359 20.385 56.413 ;
    END
  END w0_wmask_in[387]
  PIN w0_wmask_in[388]
    DIRECTION INPUT ;
    USE SIGNAL ;
    SHAPE ABUTMENT ;
    PORT
      LAYER M3 ;
      RECT 20.655 56.359 20.673 56.413 ;
    END
  END w0_wmask_in[388]
  PIN w0_wmask_in[389]
    DIRECTION INPUT ;
    USE SIGNAL ;
    SHAPE ABUTMENT ;
    PORT
      LAYER M3 ;
      RECT 20.943 56.359 20.961 56.413 ;
    END
  END w0_wmask_in[389]
  PIN w0_wmask_in[390]
    DIRECTION INPUT ;
    USE SIGNAL ;
    SHAPE ABUTMENT ;
    PORT
      LAYER M3 ;
      RECT 21.231 56.359 21.249 56.413 ;
    END
  END w0_wmask_in[390]
  PIN w0_wmask_in[391]
    DIRECTION INPUT ;
    USE SIGNAL ;
    SHAPE ABUTMENT ;
    PORT
      LAYER M3 ;
      RECT 21.519 56.359 21.537 56.413 ;
    END
  END w0_wmask_in[391]
  PIN w0_wmask_in[392]
    DIRECTION INPUT ;
    USE SIGNAL ;
    SHAPE ABUTMENT ;
    PORT
      LAYER M3 ;
      RECT 21.807 56.359 21.825 56.413 ;
    END
  END w0_wmask_in[392]
  PIN w0_wmask_in[393]
    DIRECTION INPUT ;
    USE SIGNAL ;
    SHAPE ABUTMENT ;
    PORT
      LAYER M3 ;
      RECT 22.095 56.359 22.113 56.413 ;
    END
  END w0_wmask_in[393]
  PIN w0_wmask_in[394]
    DIRECTION INPUT ;
    USE SIGNAL ;
    SHAPE ABUTMENT ;
    PORT
      LAYER M3 ;
      RECT 22.383 56.359 22.401 56.413 ;
    END
  END w0_wmask_in[394]
  PIN w0_wmask_in[395]
    DIRECTION INPUT ;
    USE SIGNAL ;
    SHAPE ABUTMENT ;
    PORT
      LAYER M3 ;
      RECT 22.671 56.359 22.689 56.413 ;
    END
  END w0_wmask_in[395]
  PIN w0_wmask_in[396]
    DIRECTION INPUT ;
    USE SIGNAL ;
    SHAPE ABUTMENT ;
    PORT
      LAYER M3 ;
      RECT 22.959 56.359 22.977 56.413 ;
    END
  END w0_wmask_in[396]
  PIN w0_wmask_in[397]
    DIRECTION INPUT ;
    USE SIGNAL ;
    SHAPE ABUTMENT ;
    PORT
      LAYER M3 ;
      RECT 23.247 56.359 23.265 56.413 ;
    END
  END w0_wmask_in[397]
  PIN w0_wmask_in[398]
    DIRECTION INPUT ;
    USE SIGNAL ;
    SHAPE ABUTMENT ;
    PORT
      LAYER M3 ;
      RECT 23.535 56.359 23.553 56.413 ;
    END
  END w0_wmask_in[398]
  PIN w0_wmask_in[399]
    DIRECTION INPUT ;
    USE SIGNAL ;
    SHAPE ABUTMENT ;
    PORT
      LAYER M3 ;
      RECT 23.823 56.359 23.841 56.413 ;
    END
  END w0_wmask_in[399]
  PIN w0_wmask_in[400]
    DIRECTION INPUT ;
    USE SIGNAL ;
    SHAPE ABUTMENT ;
    PORT
      LAYER M3 ;
      RECT 24.111 56.359 24.129 56.413 ;
    END
  END w0_wmask_in[400]
  PIN w0_wmask_in[401]
    DIRECTION INPUT ;
    USE SIGNAL ;
    SHAPE ABUTMENT ;
    PORT
      LAYER M3 ;
      RECT 24.399 56.359 24.417 56.413 ;
    END
  END w0_wmask_in[401]
  PIN w0_wmask_in[402]
    DIRECTION INPUT ;
    USE SIGNAL ;
    SHAPE ABUTMENT ;
    PORT
      LAYER M3 ;
      RECT 24.687 56.359 24.705 56.413 ;
    END
  END w0_wmask_in[402]
  PIN w0_wmask_in[403]
    DIRECTION INPUT ;
    USE SIGNAL ;
    SHAPE ABUTMENT ;
    PORT
      LAYER M3 ;
      RECT 24.975 56.359 24.993 56.413 ;
    END
  END w0_wmask_in[403]
  PIN w0_wmask_in[404]
    DIRECTION INPUT ;
    USE SIGNAL ;
    SHAPE ABUTMENT ;
    PORT
      LAYER M3 ;
      RECT 25.263 56.359 25.281 56.413 ;
    END
  END w0_wmask_in[404]
  PIN w0_wmask_in[405]
    DIRECTION INPUT ;
    USE SIGNAL ;
    SHAPE ABUTMENT ;
    PORT
      LAYER M3 ;
      RECT 25.551 56.359 25.569 56.413 ;
    END
  END w0_wmask_in[405]
  PIN w0_wmask_in[406]
    DIRECTION INPUT ;
    USE SIGNAL ;
    SHAPE ABUTMENT ;
    PORT
      LAYER M3 ;
      RECT 25.839 56.359 25.857 56.413 ;
    END
  END w0_wmask_in[406]
  PIN w0_wmask_in[407]
    DIRECTION INPUT ;
    USE SIGNAL ;
    SHAPE ABUTMENT ;
    PORT
      LAYER M3 ;
      RECT 26.127 56.359 26.145 56.413 ;
    END
  END w0_wmask_in[407]
  PIN w0_wmask_in[408]
    DIRECTION INPUT ;
    USE SIGNAL ;
    SHAPE ABUTMENT ;
    PORT
      LAYER M3 ;
      RECT 26.415 56.359 26.433 56.413 ;
    END
  END w0_wmask_in[408]
  PIN w0_wmask_in[409]
    DIRECTION INPUT ;
    USE SIGNAL ;
    SHAPE ABUTMENT ;
    PORT
      LAYER M3 ;
      RECT 26.703 56.359 26.721 56.413 ;
    END
  END w0_wmask_in[409]
  PIN w0_wmask_in[410]
    DIRECTION INPUT ;
    USE SIGNAL ;
    SHAPE ABUTMENT ;
    PORT
      LAYER M3 ;
      RECT 26.991 56.359 27.009 56.413 ;
    END
  END w0_wmask_in[410]
  PIN w0_wmask_in[411]
    DIRECTION INPUT ;
    USE SIGNAL ;
    SHAPE ABUTMENT ;
    PORT
      LAYER M3 ;
      RECT 27.279 56.359 27.297 56.413 ;
    END
  END w0_wmask_in[411]
  PIN w0_wmask_in[412]
    DIRECTION INPUT ;
    USE SIGNAL ;
    SHAPE ABUTMENT ;
    PORT
      LAYER M3 ;
      RECT 27.567 56.359 27.585 56.413 ;
    END
  END w0_wmask_in[412]
  PIN w0_wmask_in[413]
    DIRECTION INPUT ;
    USE SIGNAL ;
    SHAPE ABUTMENT ;
    PORT
      LAYER M3 ;
      RECT 27.855 56.359 27.873 56.413 ;
    END
  END w0_wmask_in[413]
  PIN w0_wmask_in[414]
    DIRECTION INPUT ;
    USE SIGNAL ;
    SHAPE ABUTMENT ;
    PORT
      LAYER M3 ;
      RECT 28.143 56.359 28.161 56.413 ;
    END
  END w0_wmask_in[414]
  PIN w0_wmask_in[415]
    DIRECTION INPUT ;
    USE SIGNAL ;
    SHAPE ABUTMENT ;
    PORT
      LAYER M3 ;
      RECT 28.431 56.359 28.449 56.413 ;
    END
  END w0_wmask_in[415]
  PIN w0_wmask_in[416]
    DIRECTION INPUT ;
    USE SIGNAL ;
    SHAPE ABUTMENT ;
    PORT
      LAYER M3 ;
      RECT 28.719 56.359 28.737 56.413 ;
    END
  END w0_wmask_in[416]
  PIN w0_wmask_in[417]
    DIRECTION INPUT ;
    USE SIGNAL ;
    SHAPE ABUTMENT ;
    PORT
      LAYER M3 ;
      RECT 29.007 56.359 29.025 56.413 ;
    END
  END w0_wmask_in[417]
  PIN w0_wmask_in[418]
    DIRECTION INPUT ;
    USE SIGNAL ;
    SHAPE ABUTMENT ;
    PORT
      LAYER M3 ;
      RECT 29.295 56.359 29.313 56.413 ;
    END
  END w0_wmask_in[418]
  PIN w0_wmask_in[419]
    DIRECTION INPUT ;
    USE SIGNAL ;
    SHAPE ABUTMENT ;
    PORT
      LAYER M3 ;
      RECT 29.583 56.359 29.601 56.413 ;
    END
  END w0_wmask_in[419]
  PIN w0_wmask_in[420]
    DIRECTION INPUT ;
    USE SIGNAL ;
    SHAPE ABUTMENT ;
    PORT
      LAYER M3 ;
      RECT 29.871 56.359 29.889 56.413 ;
    END
  END w0_wmask_in[420]
  PIN w0_wmask_in[421]
    DIRECTION INPUT ;
    USE SIGNAL ;
    SHAPE ABUTMENT ;
    PORT
      LAYER M3 ;
      RECT 30.159 56.359 30.177 56.413 ;
    END
  END w0_wmask_in[421]
  PIN w0_wmask_in[422]
    DIRECTION INPUT ;
    USE SIGNAL ;
    SHAPE ABUTMENT ;
    PORT
      LAYER M3 ;
      RECT 30.447 56.359 30.465 56.413 ;
    END
  END w0_wmask_in[422]
  PIN w0_wmask_in[423]
    DIRECTION INPUT ;
    USE SIGNAL ;
    SHAPE ABUTMENT ;
    PORT
      LAYER M3 ;
      RECT 30.735 56.359 30.753 56.413 ;
    END
  END w0_wmask_in[423]
  PIN w0_wmask_in[424]
    DIRECTION INPUT ;
    USE SIGNAL ;
    SHAPE ABUTMENT ;
    PORT
      LAYER M3 ;
      RECT 31.023 56.359 31.041 56.413 ;
    END
  END w0_wmask_in[424]
  PIN w0_wmask_in[425]
    DIRECTION INPUT ;
    USE SIGNAL ;
    SHAPE ABUTMENT ;
    PORT
      LAYER M3 ;
      RECT 31.311 56.359 31.329 56.413 ;
    END
  END w0_wmask_in[425]
  PIN w0_wmask_in[426]
    DIRECTION INPUT ;
    USE SIGNAL ;
    SHAPE ABUTMENT ;
    PORT
      LAYER M3 ;
      RECT 31.599 56.359 31.617 56.413 ;
    END
  END w0_wmask_in[426]
  PIN w0_wmask_in[427]
    DIRECTION INPUT ;
    USE SIGNAL ;
    SHAPE ABUTMENT ;
    PORT
      LAYER M3 ;
      RECT 31.887 56.359 31.905 56.413 ;
    END
  END w0_wmask_in[427]
  PIN w0_wmask_in[428]
    DIRECTION INPUT ;
    USE SIGNAL ;
    SHAPE ABUTMENT ;
    PORT
      LAYER M3 ;
      RECT 32.175 56.359 32.193 56.413 ;
    END
  END w0_wmask_in[428]
  PIN w0_wmask_in[429]
    DIRECTION INPUT ;
    USE SIGNAL ;
    SHAPE ABUTMENT ;
    PORT
      LAYER M3 ;
      RECT 32.463 56.359 32.481 56.413 ;
    END
  END w0_wmask_in[429]
  PIN w0_wmask_in[430]
    DIRECTION INPUT ;
    USE SIGNAL ;
    SHAPE ABUTMENT ;
    PORT
      LAYER M3 ;
      RECT 32.751 56.359 32.769 56.413 ;
    END
  END w0_wmask_in[430]
  PIN w0_wmask_in[431]
    DIRECTION INPUT ;
    USE SIGNAL ;
    SHAPE ABUTMENT ;
    PORT
      LAYER M3 ;
      RECT 33.039 56.359 33.057 56.413 ;
    END
  END w0_wmask_in[431]
  PIN w0_wmask_in[432]
    DIRECTION INPUT ;
    USE SIGNAL ;
    SHAPE ABUTMENT ;
    PORT
      LAYER M3 ;
      RECT 33.327 56.359 33.345 56.413 ;
    END
  END w0_wmask_in[432]
  PIN w0_wmask_in[433]
    DIRECTION INPUT ;
    USE SIGNAL ;
    SHAPE ABUTMENT ;
    PORT
      LAYER M3 ;
      RECT 33.615 56.359 33.633 56.413 ;
    END
  END w0_wmask_in[433]
  PIN w0_wmask_in[434]
    DIRECTION INPUT ;
    USE SIGNAL ;
    SHAPE ABUTMENT ;
    PORT
      LAYER M3 ;
      RECT 33.903 56.359 33.921 56.413 ;
    END
  END w0_wmask_in[434]
  PIN w0_wmask_in[435]
    DIRECTION INPUT ;
    USE SIGNAL ;
    SHAPE ABUTMENT ;
    PORT
      LAYER M3 ;
      RECT 34.191 56.359 34.209 56.413 ;
    END
  END w0_wmask_in[435]
  PIN w0_wmask_in[436]
    DIRECTION INPUT ;
    USE SIGNAL ;
    SHAPE ABUTMENT ;
    PORT
      LAYER M3 ;
      RECT 34.479 56.359 34.497 56.413 ;
    END
  END w0_wmask_in[436]
  PIN w0_wmask_in[437]
    DIRECTION INPUT ;
    USE SIGNAL ;
    SHAPE ABUTMENT ;
    PORT
      LAYER M3 ;
      RECT 34.767 56.359 34.785 56.413 ;
    END
  END w0_wmask_in[437]
  PIN w0_wmask_in[438]
    DIRECTION INPUT ;
    USE SIGNAL ;
    SHAPE ABUTMENT ;
    PORT
      LAYER M3 ;
      RECT 35.055 56.359 35.073 56.413 ;
    END
  END w0_wmask_in[438]
  PIN w0_wmask_in[439]
    DIRECTION INPUT ;
    USE SIGNAL ;
    SHAPE ABUTMENT ;
    PORT
      LAYER M3 ;
      RECT 35.343 56.359 35.361 56.413 ;
    END
  END w0_wmask_in[439]
  PIN w0_wmask_in[440]
    DIRECTION INPUT ;
    USE SIGNAL ;
    SHAPE ABUTMENT ;
    PORT
      LAYER M3 ;
      RECT 35.631 56.359 35.649 56.413 ;
    END
  END w0_wmask_in[440]
  PIN w0_wmask_in[441]
    DIRECTION INPUT ;
    USE SIGNAL ;
    SHAPE ABUTMENT ;
    PORT
      LAYER M3 ;
      RECT 35.919 56.359 35.937 56.413 ;
    END
  END w0_wmask_in[441]
  PIN w0_wmask_in[442]
    DIRECTION INPUT ;
    USE SIGNAL ;
    SHAPE ABUTMENT ;
    PORT
      LAYER M3 ;
      RECT 36.207 56.359 36.225 56.413 ;
    END
  END w0_wmask_in[442]
  PIN w0_wmask_in[443]
    DIRECTION INPUT ;
    USE SIGNAL ;
    SHAPE ABUTMENT ;
    PORT
      LAYER M3 ;
      RECT 36.495 56.359 36.513 56.413 ;
    END
  END w0_wmask_in[443]
  PIN w0_wmask_in[444]
    DIRECTION INPUT ;
    USE SIGNAL ;
    SHAPE ABUTMENT ;
    PORT
      LAYER M3 ;
      RECT 36.783 56.359 36.801 56.413 ;
    END
  END w0_wmask_in[444]
  PIN w0_wmask_in[445]
    DIRECTION INPUT ;
    USE SIGNAL ;
    SHAPE ABUTMENT ;
    PORT
      LAYER M3 ;
      RECT 37.071 56.359 37.089 56.413 ;
    END
  END w0_wmask_in[445]
  PIN w0_wmask_in[446]
    DIRECTION INPUT ;
    USE SIGNAL ;
    SHAPE ABUTMENT ;
    PORT
      LAYER M3 ;
      RECT 37.359 56.359 37.377 56.413 ;
    END
  END w0_wmask_in[446]
  PIN w0_wmask_in[447]
    DIRECTION INPUT ;
    USE SIGNAL ;
    SHAPE ABUTMENT ;
    PORT
      LAYER M3 ;
      RECT 37.647 56.359 37.665 56.413 ;
    END
  END w0_wmask_in[447]
  PIN w0_wmask_in[448]
    DIRECTION INPUT ;
    USE SIGNAL ;
    SHAPE ABUTMENT ;
    PORT
      LAYER M3 ;
      RECT 37.935 56.359 37.953 56.413 ;
    END
  END w0_wmask_in[448]
  PIN w0_wmask_in[449]
    DIRECTION INPUT ;
    USE SIGNAL ;
    SHAPE ABUTMENT ;
    PORT
      LAYER M3 ;
      RECT 38.223 56.359 38.241 56.413 ;
    END
  END w0_wmask_in[449]
  PIN w0_wmask_in[450]
    DIRECTION INPUT ;
    USE SIGNAL ;
    SHAPE ABUTMENT ;
    PORT
      LAYER M3 ;
      RECT 38.511 56.359 38.529 56.413 ;
    END
  END w0_wmask_in[450]
  PIN w0_wmask_in[451]
    DIRECTION INPUT ;
    USE SIGNAL ;
    SHAPE ABUTMENT ;
    PORT
      LAYER M3 ;
      RECT 38.799 56.359 38.817 56.413 ;
    END
  END w0_wmask_in[451]
  PIN w0_wmask_in[452]
    DIRECTION INPUT ;
    USE SIGNAL ;
    SHAPE ABUTMENT ;
    PORT
      LAYER M3 ;
      RECT 39.087 56.359 39.105 56.413 ;
    END
  END w0_wmask_in[452]
  PIN w0_wmask_in[453]
    DIRECTION INPUT ;
    USE SIGNAL ;
    SHAPE ABUTMENT ;
    PORT
      LAYER M3 ;
      RECT 39.375 56.359 39.393 56.413 ;
    END
  END w0_wmask_in[453]
  PIN w0_wmask_in[454]
    DIRECTION INPUT ;
    USE SIGNAL ;
    SHAPE ABUTMENT ;
    PORT
      LAYER M3 ;
      RECT 39.663 56.359 39.681 56.413 ;
    END
  END w0_wmask_in[454]
  PIN w0_wmask_in[455]
    DIRECTION INPUT ;
    USE SIGNAL ;
    SHAPE ABUTMENT ;
    PORT
      LAYER M3 ;
      RECT 39.951 56.359 39.969 56.413 ;
    END
  END w0_wmask_in[455]
  PIN w0_wmask_in[456]
    DIRECTION INPUT ;
    USE SIGNAL ;
    SHAPE ABUTMENT ;
    PORT
      LAYER M3 ;
      RECT 40.239 56.359 40.257 56.413 ;
    END
  END w0_wmask_in[456]
  PIN w0_wmask_in[457]
    DIRECTION INPUT ;
    USE SIGNAL ;
    SHAPE ABUTMENT ;
    PORT
      LAYER M3 ;
      RECT 40.527 56.359 40.545 56.413 ;
    END
  END w0_wmask_in[457]
  PIN w0_wmask_in[458]
    DIRECTION INPUT ;
    USE SIGNAL ;
    SHAPE ABUTMENT ;
    PORT
      LAYER M3 ;
      RECT 40.815 56.359 40.833 56.413 ;
    END
  END w0_wmask_in[458]
  PIN w0_wmask_in[459]
    DIRECTION INPUT ;
    USE SIGNAL ;
    SHAPE ABUTMENT ;
    PORT
      LAYER M3 ;
      RECT 41.103 56.359 41.121 56.413 ;
    END
  END w0_wmask_in[459]
  PIN w0_wmask_in[460]
    DIRECTION INPUT ;
    USE SIGNAL ;
    SHAPE ABUTMENT ;
    PORT
      LAYER M3 ;
      RECT 41.391 56.359 41.409 56.413 ;
    END
  END w0_wmask_in[460]
  PIN w0_wmask_in[461]
    DIRECTION INPUT ;
    USE SIGNAL ;
    SHAPE ABUTMENT ;
    PORT
      LAYER M3 ;
      RECT 41.679 56.359 41.697 56.413 ;
    END
  END w0_wmask_in[461]
  PIN w0_wmask_in[462]
    DIRECTION INPUT ;
    USE SIGNAL ;
    SHAPE ABUTMENT ;
    PORT
      LAYER M3 ;
      RECT 41.967 56.359 41.985 56.413 ;
    END
  END w0_wmask_in[462]
  PIN w0_wmask_in[463]
    DIRECTION INPUT ;
    USE SIGNAL ;
    SHAPE ABUTMENT ;
    PORT
      LAYER M3 ;
      RECT 42.255 56.359 42.273 56.413 ;
    END
  END w0_wmask_in[463]
  PIN w0_wmask_in[464]
    DIRECTION INPUT ;
    USE SIGNAL ;
    SHAPE ABUTMENT ;
    PORT
      LAYER M3 ;
      RECT 42.543 56.359 42.561 56.413 ;
    END
  END w0_wmask_in[464]
  PIN w0_wmask_in[465]
    DIRECTION INPUT ;
    USE SIGNAL ;
    SHAPE ABUTMENT ;
    PORT
      LAYER M3 ;
      RECT 42.831 56.359 42.849 56.413 ;
    END
  END w0_wmask_in[465]
  PIN w0_wmask_in[466]
    DIRECTION INPUT ;
    USE SIGNAL ;
    SHAPE ABUTMENT ;
    PORT
      LAYER M3 ;
      RECT 43.119 56.359 43.137 56.413 ;
    END
  END w0_wmask_in[466]
  PIN w0_wmask_in[467]
    DIRECTION INPUT ;
    USE SIGNAL ;
    SHAPE ABUTMENT ;
    PORT
      LAYER M3 ;
      RECT 43.407 56.359 43.425 56.413 ;
    END
  END w0_wmask_in[467]
  PIN w0_wmask_in[468]
    DIRECTION INPUT ;
    USE SIGNAL ;
    SHAPE ABUTMENT ;
    PORT
      LAYER M3 ;
      RECT 43.695 56.359 43.713 56.413 ;
    END
  END w0_wmask_in[468]
  PIN w0_wmask_in[469]
    DIRECTION INPUT ;
    USE SIGNAL ;
    SHAPE ABUTMENT ;
    PORT
      LAYER M3 ;
      RECT 43.983 56.359 44.001 56.413 ;
    END
  END w0_wmask_in[469]
  PIN w0_wmask_in[470]
    DIRECTION INPUT ;
    USE SIGNAL ;
    SHAPE ABUTMENT ;
    PORT
      LAYER M3 ;
      RECT 44.271 56.359 44.289 56.413 ;
    END
  END w0_wmask_in[470]
  PIN w0_wmask_in[471]
    DIRECTION INPUT ;
    USE SIGNAL ;
    SHAPE ABUTMENT ;
    PORT
      LAYER M3 ;
      RECT 44.559 56.359 44.577 56.413 ;
    END
  END w0_wmask_in[471]
  PIN w0_wmask_in[472]
    DIRECTION INPUT ;
    USE SIGNAL ;
    SHAPE ABUTMENT ;
    PORT
      LAYER M3 ;
      RECT 44.847 56.359 44.865 56.413 ;
    END
  END w0_wmask_in[472]
  PIN w0_wmask_in[473]
    DIRECTION INPUT ;
    USE SIGNAL ;
    SHAPE ABUTMENT ;
    PORT
      LAYER M3 ;
      RECT 45.135 56.359 45.153 56.413 ;
    END
  END w0_wmask_in[473]
  PIN w0_wmask_in[474]
    DIRECTION INPUT ;
    USE SIGNAL ;
    SHAPE ABUTMENT ;
    PORT
      LAYER M3 ;
      RECT 45.423 56.359 45.441 56.413 ;
    END
  END w0_wmask_in[474]
  PIN w0_wmask_in[475]
    DIRECTION INPUT ;
    USE SIGNAL ;
    SHAPE ABUTMENT ;
    PORT
      LAYER M3 ;
      RECT 45.711 56.359 45.729 56.413 ;
    END
  END w0_wmask_in[475]
  PIN w0_wmask_in[476]
    DIRECTION INPUT ;
    USE SIGNAL ;
    SHAPE ABUTMENT ;
    PORT
      LAYER M3 ;
      RECT 45.999 56.359 46.017 56.413 ;
    END
  END w0_wmask_in[476]
  PIN w0_wmask_in[477]
    DIRECTION INPUT ;
    USE SIGNAL ;
    SHAPE ABUTMENT ;
    PORT
      LAYER M3 ;
      RECT 46.287 56.359 46.305 56.413 ;
    END
  END w0_wmask_in[477]
  PIN w0_wmask_in[478]
    DIRECTION INPUT ;
    USE SIGNAL ;
    SHAPE ABUTMENT ;
    PORT
      LAYER M3 ;
      RECT 46.575 56.359 46.593 56.413 ;
    END
  END w0_wmask_in[478]
  PIN w0_wmask_in[479]
    DIRECTION INPUT ;
    USE SIGNAL ;
    SHAPE ABUTMENT ;
    PORT
      LAYER M3 ;
      RECT 46.863 56.359 46.881 56.413 ;
    END
  END w0_wmask_in[479]
  PIN w0_wmask_in[480]
    DIRECTION INPUT ;
    USE SIGNAL ;
    SHAPE ABUTMENT ;
    PORT
      LAYER M3 ;
      RECT 47.151 56.359 47.169 56.413 ;
    END
  END w0_wmask_in[480]
  PIN w0_wmask_in[481]
    DIRECTION INPUT ;
    USE SIGNAL ;
    SHAPE ABUTMENT ;
    PORT
      LAYER M3 ;
      RECT 47.439 56.359 47.457 56.413 ;
    END
  END w0_wmask_in[481]
  PIN w0_wmask_in[482]
    DIRECTION INPUT ;
    USE SIGNAL ;
    SHAPE ABUTMENT ;
    PORT
      LAYER M3 ;
      RECT 47.727 56.359 47.745 56.413 ;
    END
  END w0_wmask_in[482]
  PIN w0_wmask_in[483]
    DIRECTION INPUT ;
    USE SIGNAL ;
    SHAPE ABUTMENT ;
    PORT
      LAYER M3 ;
      RECT 48.015 56.359 48.033 56.413 ;
    END
  END w0_wmask_in[483]
  PIN w0_wmask_in[484]
    DIRECTION INPUT ;
    USE SIGNAL ;
    SHAPE ABUTMENT ;
    PORT
      LAYER M3 ;
      RECT 48.303 56.359 48.321 56.413 ;
    END
  END w0_wmask_in[484]
  PIN w0_wmask_in[485]
    DIRECTION INPUT ;
    USE SIGNAL ;
    SHAPE ABUTMENT ;
    PORT
      LAYER M3 ;
      RECT 48.591 56.359 48.609 56.413 ;
    END
  END w0_wmask_in[485]
  PIN w0_wmask_in[486]
    DIRECTION INPUT ;
    USE SIGNAL ;
    SHAPE ABUTMENT ;
    PORT
      LAYER M3 ;
      RECT 48.879 56.359 48.897 56.413 ;
    END
  END w0_wmask_in[486]
  PIN w0_wmask_in[487]
    DIRECTION INPUT ;
    USE SIGNAL ;
    SHAPE ABUTMENT ;
    PORT
      LAYER M3 ;
      RECT 49.167 56.359 49.185 56.413 ;
    END
  END w0_wmask_in[487]
  PIN w0_wmask_in[488]
    DIRECTION INPUT ;
    USE SIGNAL ;
    SHAPE ABUTMENT ;
    PORT
      LAYER M3 ;
      RECT 49.455 56.359 49.473 56.413 ;
    END
  END w0_wmask_in[488]
  PIN w0_wmask_in[489]
    DIRECTION INPUT ;
    USE SIGNAL ;
    SHAPE ABUTMENT ;
    PORT
      LAYER M3 ;
      RECT 49.743 56.359 49.761 56.413 ;
    END
  END w0_wmask_in[489]
  PIN w0_wmask_in[490]
    DIRECTION INPUT ;
    USE SIGNAL ;
    SHAPE ABUTMENT ;
    PORT
      LAYER M3 ;
      RECT 50.031 56.359 50.049 56.413 ;
    END
  END w0_wmask_in[490]
  PIN w0_wmask_in[491]
    DIRECTION INPUT ;
    USE SIGNAL ;
    SHAPE ABUTMENT ;
    PORT
      LAYER M3 ;
      RECT 50.319 56.359 50.337 56.413 ;
    END
  END w0_wmask_in[491]
  PIN w0_wmask_in[492]
    DIRECTION INPUT ;
    USE SIGNAL ;
    SHAPE ABUTMENT ;
    PORT
      LAYER M3 ;
      RECT 50.607 56.359 50.625 56.413 ;
    END
  END w0_wmask_in[492]
  PIN w0_wmask_in[493]
    DIRECTION INPUT ;
    USE SIGNAL ;
    SHAPE ABUTMENT ;
    PORT
      LAYER M3 ;
      RECT 50.895 56.359 50.913 56.413 ;
    END
  END w0_wmask_in[493]
  PIN w0_wmask_in[494]
    DIRECTION INPUT ;
    USE SIGNAL ;
    SHAPE ABUTMENT ;
    PORT
      LAYER M3 ;
      RECT 51.183 56.359 51.201 56.413 ;
    END
  END w0_wmask_in[494]
  PIN w0_wmask_in[495]
    DIRECTION INPUT ;
    USE SIGNAL ;
    SHAPE ABUTMENT ;
    PORT
      LAYER M3 ;
      RECT 51.471 56.359 51.489 56.413 ;
    END
  END w0_wmask_in[495]
  PIN w0_wmask_in[496]
    DIRECTION INPUT ;
    USE SIGNAL ;
    SHAPE ABUTMENT ;
    PORT
      LAYER M3 ;
      RECT 51.759 56.359 51.777 56.413 ;
    END
  END w0_wmask_in[496]
  PIN w0_wmask_in[497]
    DIRECTION INPUT ;
    USE SIGNAL ;
    SHAPE ABUTMENT ;
    PORT
      LAYER M3 ;
      RECT 52.047 56.359 52.065 56.413 ;
    END
  END w0_wmask_in[497]
  PIN w0_wmask_in[498]
    DIRECTION INPUT ;
    USE SIGNAL ;
    SHAPE ABUTMENT ;
    PORT
      LAYER M3 ;
      RECT 52.335 56.359 52.353 56.413 ;
    END
  END w0_wmask_in[498]
  PIN w0_wmask_in[499]
    DIRECTION INPUT ;
    USE SIGNAL ;
    SHAPE ABUTMENT ;
    PORT
      LAYER M3 ;
      RECT 52.623 56.359 52.641 56.413 ;
    END
  END w0_wmask_in[499]
  PIN w0_wmask_in[500]
    DIRECTION INPUT ;
    USE SIGNAL ;
    SHAPE ABUTMENT ;
    PORT
      LAYER M3 ;
      RECT 52.911 56.359 52.929 56.413 ;
    END
  END w0_wmask_in[500]
  PIN w0_wmask_in[501]
    DIRECTION INPUT ;
    USE SIGNAL ;
    SHAPE ABUTMENT ;
    PORT
      LAYER M3 ;
      RECT 53.199 56.359 53.217 56.413 ;
    END
  END w0_wmask_in[501]
  PIN w0_wmask_in[502]
    DIRECTION INPUT ;
    USE SIGNAL ;
    SHAPE ABUTMENT ;
    PORT
      LAYER M3 ;
      RECT 53.487 56.359 53.505 56.413 ;
    END
  END w0_wmask_in[502]
  PIN w0_wmask_in[503]
    DIRECTION INPUT ;
    USE SIGNAL ;
    SHAPE ABUTMENT ;
    PORT
      LAYER M3 ;
      RECT 53.775 56.359 53.793 56.413 ;
    END
  END w0_wmask_in[503]
  PIN w0_wmask_in[504]
    DIRECTION INPUT ;
    USE SIGNAL ;
    SHAPE ABUTMENT ;
    PORT
      LAYER M3 ;
      RECT 54.063 56.359 54.081 56.413 ;
    END
  END w0_wmask_in[504]
  PIN w0_wmask_in[505]
    DIRECTION INPUT ;
    USE SIGNAL ;
    SHAPE ABUTMENT ;
    PORT
      LAYER M3 ;
      RECT 54.351 56.359 54.369 56.413 ;
    END
  END w0_wmask_in[505]
  PIN w0_wmask_in[506]
    DIRECTION INPUT ;
    USE SIGNAL ;
    SHAPE ABUTMENT ;
    PORT
      LAYER M3 ;
      RECT 54.639 56.359 54.657 56.413 ;
    END
  END w0_wmask_in[506]
  PIN w0_wmask_in[507]
    DIRECTION INPUT ;
    USE SIGNAL ;
    SHAPE ABUTMENT ;
    PORT
      LAYER M3 ;
      RECT 54.927 56.359 54.945 56.413 ;
    END
  END w0_wmask_in[507]
  PIN w0_wmask_in[508]
    DIRECTION INPUT ;
    USE SIGNAL ;
    SHAPE ABUTMENT ;
    PORT
      LAYER M3 ;
      RECT 55.215 56.359 55.233 56.413 ;
    END
  END w0_wmask_in[508]
  PIN w0_wmask_in[509]
    DIRECTION INPUT ;
    USE SIGNAL ;
    SHAPE ABUTMENT ;
    PORT
      LAYER M3 ;
      RECT 55.503 56.359 55.521 56.413 ;
    END
  END w0_wmask_in[509]
  PIN w0_wmask_in[510]
    DIRECTION INPUT ;
    USE SIGNAL ;
    SHAPE ABUTMENT ;
    PORT
      LAYER M3 ;
      RECT 55.791 56.359 55.809 56.413 ;
    END
  END w0_wmask_in[510]
  PIN w0_wmask_in[511]
    DIRECTION INPUT ;
    USE SIGNAL ;
    SHAPE ABUTMENT ;
    PORT
      LAYER M3 ;
      RECT 56.079 56.359 56.097 56.413 ;
    END
  END w0_wmask_in[511]
  PIN w0_wmask_in[512]
    DIRECTION INPUT ;
    USE SIGNAL ;
    SHAPE ABUTMENT ;
    PORT
      LAYER M3 ;
      RECT 56.367 56.359 56.385 56.413 ;
    END
  END w0_wmask_in[512]
  PIN w0_wmask_in[513]
    DIRECTION INPUT ;
    USE SIGNAL ;
    SHAPE ABUTMENT ;
    PORT
      LAYER M3 ;
      RECT 56.655 56.359 56.673 56.413 ;
    END
  END w0_wmask_in[513]
  PIN w0_wmask_in[514]
    DIRECTION INPUT ;
    USE SIGNAL ;
    SHAPE ABUTMENT ;
    PORT
      LAYER M3 ;
      RECT 56.943 56.359 56.961 56.413 ;
    END
  END w0_wmask_in[514]
  PIN w0_wmask_in[515]
    DIRECTION INPUT ;
    USE SIGNAL ;
    SHAPE ABUTMENT ;
    PORT
      LAYER M3 ;
      RECT 57.231 56.359 57.249 56.413 ;
    END
  END w0_wmask_in[515]
  PIN w0_wmask_in[516]
    DIRECTION INPUT ;
    USE SIGNAL ;
    SHAPE ABUTMENT ;
    PORT
      LAYER M3 ;
      RECT 57.519 56.359 57.537 56.413 ;
    END
  END w0_wmask_in[516]
  PIN w0_wmask_in[517]
    DIRECTION INPUT ;
    USE SIGNAL ;
    SHAPE ABUTMENT ;
    PORT
      LAYER M3 ;
      RECT 57.807 56.359 57.825 56.413 ;
    END
  END w0_wmask_in[517]
  PIN w0_wmask_in[518]
    DIRECTION INPUT ;
    USE SIGNAL ;
    SHAPE ABUTMENT ;
    PORT
      LAYER M3 ;
      RECT 58.095 56.359 58.113 56.413 ;
    END
  END w0_wmask_in[518]
  PIN w0_wmask_in[519]
    DIRECTION INPUT ;
    USE SIGNAL ;
    SHAPE ABUTMENT ;
    PORT
      LAYER M3 ;
      RECT 58.383 56.359 58.401 56.413 ;
    END
  END w0_wmask_in[519]
  PIN w0_wmask_in[520]
    DIRECTION INPUT ;
    USE SIGNAL ;
    SHAPE ABUTMENT ;
    PORT
      LAYER M3 ;
      RECT 58.671 56.359 58.689 56.413 ;
    END
  END w0_wmask_in[520]
  PIN w0_wmask_in[521]
    DIRECTION INPUT ;
    USE SIGNAL ;
    SHAPE ABUTMENT ;
    PORT
      LAYER M3 ;
      RECT 58.959 56.359 58.977 56.413 ;
    END
  END w0_wmask_in[521]
  PIN w0_wmask_in[522]
    DIRECTION INPUT ;
    USE SIGNAL ;
    SHAPE ABUTMENT ;
    PORT
      LAYER M3 ;
      RECT 59.247 56.359 59.265 56.413 ;
    END
  END w0_wmask_in[522]
  PIN w0_wmask_in[523]
    DIRECTION INPUT ;
    USE SIGNAL ;
    SHAPE ABUTMENT ;
    PORT
      LAYER M3 ;
      RECT 59.535 56.359 59.553 56.413 ;
    END
  END w0_wmask_in[523]
  PIN w0_wmask_in[524]
    DIRECTION INPUT ;
    USE SIGNAL ;
    SHAPE ABUTMENT ;
    PORT
      LAYER M3 ;
      RECT 59.823 56.359 59.841 56.413 ;
    END
  END w0_wmask_in[524]
  PIN w0_wmask_in[525]
    DIRECTION INPUT ;
    USE SIGNAL ;
    SHAPE ABUTMENT ;
    PORT
      LAYER M3 ;
      RECT 60.111 56.359 60.129 56.413 ;
    END
  END w0_wmask_in[525]
  PIN w0_wmask_in[526]
    DIRECTION INPUT ;
    USE SIGNAL ;
    SHAPE ABUTMENT ;
    PORT
      LAYER M3 ;
      RECT 60.399 56.359 60.417 56.413 ;
    END
  END w0_wmask_in[526]
  PIN w0_wmask_in[527]
    DIRECTION INPUT ;
    USE SIGNAL ;
    SHAPE ABUTMENT ;
    PORT
      LAYER M3 ;
      RECT 60.687 56.359 60.705 56.413 ;
    END
  END w0_wmask_in[527]
  PIN w0_wmask_in[528]
    DIRECTION INPUT ;
    USE SIGNAL ;
    SHAPE ABUTMENT ;
    PORT
      LAYER M3 ;
      RECT 60.975 56.359 60.993 56.413 ;
    END
  END w0_wmask_in[528]
  PIN w0_wmask_in[529]
    DIRECTION INPUT ;
    USE SIGNAL ;
    SHAPE ABUTMENT ;
    PORT
      LAYER M3 ;
      RECT 61.263 56.359 61.281 56.413 ;
    END
  END w0_wmask_in[529]
  PIN w0_wmask_in[530]
    DIRECTION INPUT ;
    USE SIGNAL ;
    SHAPE ABUTMENT ;
    PORT
      LAYER M3 ;
      RECT 61.551 56.359 61.569 56.413 ;
    END
  END w0_wmask_in[530]
  PIN w0_wmask_in[531]
    DIRECTION INPUT ;
    USE SIGNAL ;
    SHAPE ABUTMENT ;
    PORT
      LAYER M3 ;
      RECT 61.839 56.359 61.857 56.413 ;
    END
  END w0_wmask_in[531]
  PIN w0_wmask_in[532]
    DIRECTION INPUT ;
    USE SIGNAL ;
    SHAPE ABUTMENT ;
    PORT
      LAYER M3 ;
      RECT 62.127 56.359 62.145 56.413 ;
    END
  END w0_wmask_in[532]
  PIN w0_wmask_in[533]
    DIRECTION INPUT ;
    USE SIGNAL ;
    SHAPE ABUTMENT ;
    PORT
      LAYER M3 ;
      RECT 62.415 56.359 62.433 56.413 ;
    END
  END w0_wmask_in[533]
  PIN w0_wmask_in[534]
    DIRECTION INPUT ;
    USE SIGNAL ;
    SHAPE ABUTMENT ;
    PORT
      LAYER M3 ;
      RECT 62.703 56.359 62.721 56.413 ;
    END
  END w0_wmask_in[534]
  PIN w0_wmask_in[535]
    DIRECTION INPUT ;
    USE SIGNAL ;
    SHAPE ABUTMENT ;
    PORT
      LAYER M3 ;
      RECT 62.991 56.359 63.009 56.413 ;
    END
  END w0_wmask_in[535]
  PIN w0_wmask_in[536]
    DIRECTION INPUT ;
    USE SIGNAL ;
    SHAPE ABUTMENT ;
    PORT
      LAYER M3 ;
      RECT 63.279 56.359 63.297 56.413 ;
    END
  END w0_wmask_in[536]
  PIN w0_wmask_in[537]
    DIRECTION INPUT ;
    USE SIGNAL ;
    SHAPE ABUTMENT ;
    PORT
      LAYER M3 ;
      RECT 63.567 56.359 63.585 56.413 ;
    END
  END w0_wmask_in[537]
  PIN w0_wmask_in[538]
    DIRECTION INPUT ;
    USE SIGNAL ;
    SHAPE ABUTMENT ;
    PORT
      LAYER M3 ;
      RECT 63.855 56.359 63.873 56.413 ;
    END
  END w0_wmask_in[538]
  PIN w0_wmask_in[539]
    DIRECTION INPUT ;
    USE SIGNAL ;
    SHAPE ABUTMENT ;
    PORT
      LAYER M3 ;
      RECT 64.143 56.359 64.161 56.413 ;
    END
  END w0_wmask_in[539]
  PIN w0_wmask_in[540]
    DIRECTION INPUT ;
    USE SIGNAL ;
    SHAPE ABUTMENT ;
    PORT
      LAYER M3 ;
      RECT 64.431 56.359 64.449 56.413 ;
    END
  END w0_wmask_in[540]
  PIN w0_wmask_in[541]
    DIRECTION INPUT ;
    USE SIGNAL ;
    SHAPE ABUTMENT ;
    PORT
      LAYER M3 ;
      RECT 64.719 56.359 64.737 56.413 ;
    END
  END w0_wmask_in[541]
  PIN w0_wmask_in[542]
    DIRECTION INPUT ;
    USE SIGNAL ;
    SHAPE ABUTMENT ;
    PORT
      LAYER M3 ;
      RECT 65.007 56.359 65.025 56.413 ;
    END
  END w0_wmask_in[542]
  PIN w0_wmask_in[543]
    DIRECTION INPUT ;
    USE SIGNAL ;
    SHAPE ABUTMENT ;
    PORT
      LAYER M3 ;
      RECT 65.295 56.359 65.313 56.413 ;
    END
  END w0_wmask_in[543]
  PIN w0_wmask_in[544]
    DIRECTION INPUT ;
    USE SIGNAL ;
    SHAPE ABUTMENT ;
    PORT
      LAYER M3 ;
      RECT 65.583 56.359 65.601 56.413 ;
    END
  END w0_wmask_in[544]
  PIN w0_wmask_in[545]
    DIRECTION INPUT ;
    USE SIGNAL ;
    SHAPE ABUTMENT ;
    PORT
      LAYER M3 ;
      RECT 65.871 56.359 65.889 56.413 ;
    END
  END w0_wmask_in[545]
  PIN w0_wmask_in[546]
    DIRECTION INPUT ;
    USE SIGNAL ;
    SHAPE ABUTMENT ;
    PORT
      LAYER M3 ;
      RECT 66.159 56.359 66.177 56.413 ;
    END
  END w0_wmask_in[546]
  PIN w0_wmask_in[547]
    DIRECTION INPUT ;
    USE SIGNAL ;
    SHAPE ABUTMENT ;
    PORT
      LAYER M3 ;
      RECT 66.447 56.359 66.465 56.413 ;
    END
  END w0_wmask_in[547]
  PIN w0_wmask_in[548]
    DIRECTION INPUT ;
    USE SIGNAL ;
    SHAPE ABUTMENT ;
    PORT
      LAYER M3 ;
      RECT 66.735 56.359 66.753 56.413 ;
    END
  END w0_wmask_in[548]
  PIN w0_wmask_in[549]
    DIRECTION INPUT ;
    USE SIGNAL ;
    SHAPE ABUTMENT ;
    PORT
      LAYER M3 ;
      RECT 67.023 56.359 67.041 56.413 ;
    END
  END w0_wmask_in[549]
  PIN w0_wmask_in[550]
    DIRECTION INPUT ;
    USE SIGNAL ;
    SHAPE ABUTMENT ;
    PORT
      LAYER M3 ;
      RECT 67.311 56.359 67.329 56.413 ;
    END
  END w0_wmask_in[550]
  PIN w0_wmask_in[551]
    DIRECTION INPUT ;
    USE SIGNAL ;
    SHAPE ABUTMENT ;
    PORT
      LAYER M3 ;
      RECT 67.599 56.359 67.617 56.413 ;
    END
  END w0_wmask_in[551]
  PIN w0_wmask_in[552]
    DIRECTION INPUT ;
    USE SIGNAL ;
    SHAPE ABUTMENT ;
    PORT
      LAYER M3 ;
      RECT 67.887 56.359 67.905 56.413 ;
    END
  END w0_wmask_in[552]
  PIN w0_wmask_in[553]
    DIRECTION INPUT ;
    USE SIGNAL ;
    SHAPE ABUTMENT ;
    PORT
      LAYER M3 ;
      RECT 68.175 56.359 68.193 56.413 ;
    END
  END w0_wmask_in[553]
  PIN w0_wmask_in[554]
    DIRECTION INPUT ;
    USE SIGNAL ;
    SHAPE ABUTMENT ;
    PORT
      LAYER M3 ;
      RECT 68.463 56.359 68.481 56.413 ;
    END
  END w0_wmask_in[554]
  PIN w0_wmask_in[555]
    DIRECTION INPUT ;
    USE SIGNAL ;
    SHAPE ABUTMENT ;
    PORT
      LAYER M3 ;
      RECT 68.751 56.359 68.769 56.413 ;
    END
  END w0_wmask_in[555]
  PIN w0_wmask_in[556]
    DIRECTION INPUT ;
    USE SIGNAL ;
    SHAPE ABUTMENT ;
    PORT
      LAYER M3 ;
      RECT 69.039 56.359 69.057 56.413 ;
    END
  END w0_wmask_in[556]
  PIN w0_wmask_in[557]
    DIRECTION INPUT ;
    USE SIGNAL ;
    SHAPE ABUTMENT ;
    PORT
      LAYER M3 ;
      RECT 69.327 56.359 69.345 56.413 ;
    END
  END w0_wmask_in[557]
  PIN w0_wmask_in[558]
    DIRECTION INPUT ;
    USE SIGNAL ;
    SHAPE ABUTMENT ;
    PORT
      LAYER M3 ;
      RECT 69.615 56.359 69.633 56.413 ;
    END
  END w0_wmask_in[558]
  PIN w0_wmask_in[559]
    DIRECTION INPUT ;
    USE SIGNAL ;
    SHAPE ABUTMENT ;
    PORT
      LAYER M3 ;
      RECT 69.903 56.359 69.921 56.413 ;
    END
  END w0_wmask_in[559]
  PIN w0_wmask_in[560]
    DIRECTION INPUT ;
    USE SIGNAL ;
    SHAPE ABUTMENT ;
    PORT
      LAYER M3 ;
      RECT 70.191 56.359 70.209 56.413 ;
    END
  END w0_wmask_in[560]
  PIN w0_wmask_in[561]
    DIRECTION INPUT ;
    USE SIGNAL ;
    SHAPE ABUTMENT ;
    PORT
      LAYER M3 ;
      RECT 70.479 56.359 70.497 56.413 ;
    END
  END w0_wmask_in[561]
  PIN w0_wmask_in[562]
    DIRECTION INPUT ;
    USE SIGNAL ;
    SHAPE ABUTMENT ;
    PORT
      LAYER M3 ;
      RECT 70.767 56.359 70.785 56.413 ;
    END
  END w0_wmask_in[562]
  PIN w0_wmask_in[563]
    DIRECTION INPUT ;
    USE SIGNAL ;
    SHAPE ABUTMENT ;
    PORT
      LAYER M3 ;
      RECT 71.055 56.359 71.073 56.413 ;
    END
  END w0_wmask_in[563]
  PIN w0_wmask_in[564]
    DIRECTION INPUT ;
    USE SIGNAL ;
    SHAPE ABUTMENT ;
    PORT
      LAYER M3 ;
      RECT 71.343 56.359 71.361 56.413 ;
    END
  END w0_wmask_in[564]
  PIN w0_wmask_in[565]
    DIRECTION INPUT ;
    USE SIGNAL ;
    SHAPE ABUTMENT ;
    PORT
      LAYER M3 ;
      RECT 71.631 56.359 71.649 56.413 ;
    END
  END w0_wmask_in[565]
  PIN w0_wmask_in[566]
    DIRECTION INPUT ;
    USE SIGNAL ;
    SHAPE ABUTMENT ;
    PORT
      LAYER M3 ;
      RECT 71.919 56.359 71.937 56.413 ;
    END
  END w0_wmask_in[566]
  PIN w0_wmask_in[567]
    DIRECTION INPUT ;
    USE SIGNAL ;
    SHAPE ABUTMENT ;
    PORT
      LAYER M3 ;
      RECT 72.207 56.359 72.225 56.413 ;
    END
  END w0_wmask_in[567]
  PIN w0_wmask_in[568]
    DIRECTION INPUT ;
    USE SIGNAL ;
    SHAPE ABUTMENT ;
    PORT
      LAYER M3 ;
      RECT 72.495 56.359 72.513 56.413 ;
    END
  END w0_wmask_in[568]
  PIN w0_wmask_in[569]
    DIRECTION INPUT ;
    USE SIGNAL ;
    SHAPE ABUTMENT ;
    PORT
      LAYER M3 ;
      RECT 72.783 56.359 72.801 56.413 ;
    END
  END w0_wmask_in[569]
  PIN w0_wmask_in[570]
    DIRECTION INPUT ;
    USE SIGNAL ;
    SHAPE ABUTMENT ;
    PORT
      LAYER M3 ;
      RECT 73.071 56.359 73.089 56.413 ;
    END
  END w0_wmask_in[570]
  PIN w0_wmask_in[571]
    DIRECTION INPUT ;
    USE SIGNAL ;
    SHAPE ABUTMENT ;
    PORT
      LAYER M3 ;
      RECT 73.359 56.359 73.377 56.413 ;
    END
  END w0_wmask_in[571]
  PIN w0_wmask_in[572]
    DIRECTION INPUT ;
    USE SIGNAL ;
    SHAPE ABUTMENT ;
    PORT
      LAYER M3 ;
      RECT 73.647 56.359 73.665 56.413 ;
    END
  END w0_wmask_in[572]
  PIN w0_wmask_in[573]
    DIRECTION INPUT ;
    USE SIGNAL ;
    SHAPE ABUTMENT ;
    PORT
      LAYER M3 ;
      RECT 73.935 56.359 73.953 56.413 ;
    END
  END w0_wmask_in[573]
  PIN w0_wmask_in[574]
    DIRECTION INPUT ;
    USE SIGNAL ;
    SHAPE ABUTMENT ;
    PORT
      LAYER M3 ;
      RECT 74.223 56.359 74.241 56.413 ;
    END
  END w0_wmask_in[574]
  PIN w0_wmask_in[575]
    DIRECTION INPUT ;
    USE SIGNAL ;
    SHAPE ABUTMENT ;
    PORT
      LAYER M3 ;
      RECT 74.511 56.359 74.529 56.413 ;
    END
  END w0_wmask_in[575]
  PIN w0_wmask_in[576]
    DIRECTION INPUT ;
    USE SIGNAL ;
    SHAPE ABUTMENT ;
    PORT
      LAYER M3 ;
      RECT 74.799 56.359 74.817 56.413 ;
    END
  END w0_wmask_in[576]
  PIN w0_wmask_in[577]
    DIRECTION INPUT ;
    USE SIGNAL ;
    SHAPE ABUTMENT ;
    PORT
      LAYER M3 ;
      RECT 75.087 56.359 75.105 56.413 ;
    END
  END w0_wmask_in[577]
  PIN w0_wmask_in[578]
    DIRECTION INPUT ;
    USE SIGNAL ;
    SHAPE ABUTMENT ;
    PORT
      LAYER M3 ;
      RECT 75.375 56.359 75.393 56.413 ;
    END
  END w0_wmask_in[578]
  PIN w0_wmask_in[579]
    DIRECTION INPUT ;
    USE SIGNAL ;
    SHAPE ABUTMENT ;
    PORT
      LAYER M3 ;
      RECT 75.663 56.359 75.681 56.413 ;
    END
  END w0_wmask_in[579]
  PIN w0_wmask_in[580]
    DIRECTION INPUT ;
    USE SIGNAL ;
    SHAPE ABUTMENT ;
    PORT
      LAYER M3 ;
      RECT 75.951 56.359 75.969 56.413 ;
    END
  END w0_wmask_in[580]
  PIN w0_wmask_in[581]
    DIRECTION INPUT ;
    USE SIGNAL ;
    SHAPE ABUTMENT ;
    PORT
      LAYER M3 ;
      RECT 76.239 56.359 76.257 56.413 ;
    END
  END w0_wmask_in[581]
  PIN w0_wmask_in[582]
    DIRECTION INPUT ;
    USE SIGNAL ;
    SHAPE ABUTMENT ;
    PORT
      LAYER M3 ;
      RECT 76.527 56.359 76.545 56.413 ;
    END
  END w0_wmask_in[582]
  PIN w0_wmask_in[583]
    DIRECTION INPUT ;
    USE SIGNAL ;
    SHAPE ABUTMENT ;
    PORT
      LAYER M3 ;
      RECT 76.815 56.359 76.833 56.413 ;
    END
  END w0_wmask_in[583]
  PIN w0_wmask_in[584]
    DIRECTION INPUT ;
    USE SIGNAL ;
    SHAPE ABUTMENT ;
    PORT
      LAYER M3 ;
      RECT 77.103 56.359 77.121 56.413 ;
    END
  END w0_wmask_in[584]
  PIN w0_wmask_in[585]
    DIRECTION INPUT ;
    USE SIGNAL ;
    SHAPE ABUTMENT ;
    PORT
      LAYER M3 ;
      RECT 77.391 56.359 77.409 56.413 ;
    END
  END w0_wmask_in[585]
  PIN w0_wmask_in[586]
    DIRECTION INPUT ;
    USE SIGNAL ;
    SHAPE ABUTMENT ;
    PORT
      LAYER M3 ;
      RECT 77.679 56.359 77.697 56.413 ;
    END
  END w0_wmask_in[586]
  PIN w0_wmask_in[587]
    DIRECTION INPUT ;
    USE SIGNAL ;
    SHAPE ABUTMENT ;
    PORT
      LAYER M3 ;
      RECT 77.967 56.359 77.985 56.413 ;
    END
  END w0_wmask_in[587]
  PIN w0_wmask_in[588]
    DIRECTION INPUT ;
    USE SIGNAL ;
    SHAPE ABUTMENT ;
    PORT
      LAYER M3 ;
      RECT 78.255 56.359 78.273 56.413 ;
    END
  END w0_wmask_in[588]
  PIN w0_wmask_in[589]
    DIRECTION INPUT ;
    USE SIGNAL ;
    SHAPE ABUTMENT ;
    PORT
      LAYER M3 ;
      RECT 78.543 56.359 78.561 56.413 ;
    END
  END w0_wmask_in[589]
  PIN w0_wmask_in[590]
    DIRECTION INPUT ;
    USE SIGNAL ;
    SHAPE ABUTMENT ;
    PORT
      LAYER M3 ;
      RECT 78.831 56.359 78.849 56.413 ;
    END
  END w0_wmask_in[590]
  PIN w0_wmask_in[591]
    DIRECTION INPUT ;
    USE SIGNAL ;
    SHAPE ABUTMENT ;
    PORT
      LAYER M3 ;
      RECT 79.119 56.359 79.137 56.413 ;
    END
  END w0_wmask_in[591]
  PIN w0_wmask_in[592]
    DIRECTION INPUT ;
    USE SIGNAL ;
    SHAPE ABUTMENT ;
    PORT
      LAYER M3 ;
      RECT 79.407 56.359 79.425 56.413 ;
    END
  END w0_wmask_in[592]
  PIN w0_wmask_in[593]
    DIRECTION INPUT ;
    USE SIGNAL ;
    SHAPE ABUTMENT ;
    PORT
      LAYER M3 ;
      RECT 79.695 56.359 79.713 56.413 ;
    END
  END w0_wmask_in[593]
  PIN w0_wmask_in[594]
    DIRECTION INPUT ;
    USE SIGNAL ;
    SHAPE ABUTMENT ;
    PORT
      LAYER M3 ;
      RECT 79.983 56.359 80.001 56.413 ;
    END
  END w0_wmask_in[594]
  PIN w0_wmask_in[595]
    DIRECTION INPUT ;
    USE SIGNAL ;
    SHAPE ABUTMENT ;
    PORT
      LAYER M3 ;
      RECT 80.271 56.359 80.289 56.413 ;
    END
  END w0_wmask_in[595]
  PIN w0_wmask_in[596]
    DIRECTION INPUT ;
    USE SIGNAL ;
    SHAPE ABUTMENT ;
    PORT
      LAYER M3 ;
      RECT 80.559 56.359 80.577 56.413 ;
    END
  END w0_wmask_in[596]
  PIN w0_wmask_in[597]
    DIRECTION INPUT ;
    USE SIGNAL ;
    SHAPE ABUTMENT ;
    PORT
      LAYER M3 ;
      RECT 80.847 56.359 80.865 56.413 ;
    END
  END w0_wmask_in[597]
  PIN w0_wmask_in[598]
    DIRECTION INPUT ;
    USE SIGNAL ;
    SHAPE ABUTMENT ;
    PORT
      LAYER M3 ;
      RECT 81.135 56.359 81.153 56.413 ;
    END
  END w0_wmask_in[598]
  PIN w0_wmask_in[599]
    DIRECTION INPUT ;
    USE SIGNAL ;
    SHAPE ABUTMENT ;
    PORT
      LAYER M3 ;
      RECT 81.423 56.359 81.441 56.413 ;
    END
  END w0_wmask_in[599]
  PIN w0_wmask_in[600]
    DIRECTION INPUT ;
    USE SIGNAL ;
    SHAPE ABUTMENT ;
    PORT
      LAYER M3 ;
      RECT 81.711 56.359 81.729 56.413 ;
    END
  END w0_wmask_in[600]
  PIN w0_wmask_in[601]
    DIRECTION INPUT ;
    USE SIGNAL ;
    SHAPE ABUTMENT ;
    PORT
      LAYER M3 ;
      RECT 81.999 56.359 82.017 56.413 ;
    END
  END w0_wmask_in[601]
  PIN w0_wmask_in[602]
    DIRECTION INPUT ;
    USE SIGNAL ;
    SHAPE ABUTMENT ;
    PORT
      LAYER M3 ;
      RECT 82.287 56.359 82.305 56.413 ;
    END
  END w0_wmask_in[602]
  PIN w0_wmask_in[603]
    DIRECTION INPUT ;
    USE SIGNAL ;
    SHAPE ABUTMENT ;
    PORT
      LAYER M3 ;
      RECT 82.575 56.359 82.593 56.413 ;
    END
  END w0_wmask_in[603]
  PIN w0_wmask_in[604]
    DIRECTION INPUT ;
    USE SIGNAL ;
    SHAPE ABUTMENT ;
    PORT
      LAYER M3 ;
      RECT 82.863 56.359 82.881 56.413 ;
    END
  END w0_wmask_in[604]
  PIN w0_wmask_in[605]
    DIRECTION INPUT ;
    USE SIGNAL ;
    SHAPE ABUTMENT ;
    PORT
      LAYER M3 ;
      RECT 83.151 56.359 83.169 56.413 ;
    END
  END w0_wmask_in[605]
  PIN w0_wmask_in[606]
    DIRECTION INPUT ;
    USE SIGNAL ;
    SHAPE ABUTMENT ;
    PORT
      LAYER M3 ;
      RECT 83.439 56.359 83.457 56.413 ;
    END
  END w0_wmask_in[606]
  PIN w0_wmask_in[607]
    DIRECTION INPUT ;
    USE SIGNAL ;
    SHAPE ABUTMENT ;
    PORT
      LAYER M3 ;
      RECT 83.727 56.359 83.745 56.413 ;
    END
  END w0_wmask_in[607]
  PIN w0_wmask_in[608]
    DIRECTION INPUT ;
    USE SIGNAL ;
    SHAPE ABUTMENT ;
    PORT
      LAYER M3 ;
      RECT 84.015 56.359 84.033 56.413 ;
    END
  END w0_wmask_in[608]
  PIN w0_wmask_in[609]
    DIRECTION INPUT ;
    USE SIGNAL ;
    SHAPE ABUTMENT ;
    PORT
      LAYER M3 ;
      RECT 84.303 56.359 84.321 56.413 ;
    END
  END w0_wmask_in[609]
  PIN w0_wmask_in[610]
    DIRECTION INPUT ;
    USE SIGNAL ;
    SHAPE ABUTMENT ;
    PORT
      LAYER M3 ;
      RECT 84.591 56.359 84.609 56.413 ;
    END
  END w0_wmask_in[610]
  PIN w0_wmask_in[611]
    DIRECTION INPUT ;
    USE SIGNAL ;
    SHAPE ABUTMENT ;
    PORT
      LAYER M3 ;
      RECT 84.879 56.359 84.897 56.413 ;
    END
  END w0_wmask_in[611]
  PIN w0_wmask_in[612]
    DIRECTION INPUT ;
    USE SIGNAL ;
    SHAPE ABUTMENT ;
    PORT
      LAYER M3 ;
      RECT 85.167 56.359 85.185 56.413 ;
    END
  END w0_wmask_in[612]
  PIN w0_wmask_in[613]
    DIRECTION INPUT ;
    USE SIGNAL ;
    SHAPE ABUTMENT ;
    PORT
      LAYER M3 ;
      RECT 85.455 56.359 85.473 56.413 ;
    END
  END w0_wmask_in[613]
  PIN w0_wmask_in[614]
    DIRECTION INPUT ;
    USE SIGNAL ;
    SHAPE ABUTMENT ;
    PORT
      LAYER M3 ;
      RECT 85.743 56.359 85.761 56.413 ;
    END
  END w0_wmask_in[614]
  PIN w0_wmask_in[615]
    DIRECTION INPUT ;
    USE SIGNAL ;
    SHAPE ABUTMENT ;
    PORT
      LAYER M3 ;
      RECT 86.031 56.359 86.049 56.413 ;
    END
  END w0_wmask_in[615]
  PIN w0_wmask_in[616]
    DIRECTION INPUT ;
    USE SIGNAL ;
    SHAPE ABUTMENT ;
    PORT
      LAYER M3 ;
      RECT 86.319 56.359 86.337 56.413 ;
    END
  END w0_wmask_in[616]
  PIN w0_wmask_in[617]
    DIRECTION INPUT ;
    USE SIGNAL ;
    SHAPE ABUTMENT ;
    PORT
      LAYER M3 ;
      RECT 86.607 56.359 86.625 56.413 ;
    END
  END w0_wmask_in[617]
  PIN w0_wmask_in[618]
    DIRECTION INPUT ;
    USE SIGNAL ;
    SHAPE ABUTMENT ;
    PORT
      LAYER M3 ;
      RECT 86.895 56.359 86.913 56.413 ;
    END
  END w0_wmask_in[618]
  PIN w0_wmask_in[619]
    DIRECTION INPUT ;
    USE SIGNAL ;
    SHAPE ABUTMENT ;
    PORT
      LAYER M3 ;
      RECT 87.183 56.359 87.201 56.413 ;
    END
  END w0_wmask_in[619]
  PIN w0_wmask_in[620]
    DIRECTION INPUT ;
    USE SIGNAL ;
    SHAPE ABUTMENT ;
    PORT
      LAYER M3 ;
      RECT 87.471 56.359 87.489 56.413 ;
    END
  END w0_wmask_in[620]
  PIN w0_wmask_in[621]
    DIRECTION INPUT ;
    USE SIGNAL ;
    SHAPE ABUTMENT ;
    PORT
      LAYER M3 ;
      RECT 87.759 56.359 87.777 56.413 ;
    END
  END w0_wmask_in[621]
  PIN w0_wmask_in[622]
    DIRECTION INPUT ;
    USE SIGNAL ;
    SHAPE ABUTMENT ;
    PORT
      LAYER M3 ;
      RECT 88.047 56.359 88.065 56.413 ;
    END
  END w0_wmask_in[622]
  PIN w0_wmask_in[623]
    DIRECTION INPUT ;
    USE SIGNAL ;
    SHAPE ABUTMENT ;
    PORT
      LAYER M3 ;
      RECT 88.335 56.359 88.353 56.413 ;
    END
  END w0_wmask_in[623]
  PIN w0_wmask_in[624]
    DIRECTION INPUT ;
    USE SIGNAL ;
    SHAPE ABUTMENT ;
    PORT
      LAYER M3 ;
      RECT 88.623 56.359 88.641 56.413 ;
    END
  END w0_wmask_in[624]
  PIN w0_wmask_in[625]
    DIRECTION INPUT ;
    USE SIGNAL ;
    SHAPE ABUTMENT ;
    PORT
      LAYER M3 ;
      RECT 88.911 56.359 88.929 56.413 ;
    END
  END w0_wmask_in[625]
  PIN w0_wmask_in[626]
    DIRECTION INPUT ;
    USE SIGNAL ;
    SHAPE ABUTMENT ;
    PORT
      LAYER M3 ;
      RECT 89.199 56.359 89.217 56.413 ;
    END
  END w0_wmask_in[626]
  PIN w0_wmask_in[627]
    DIRECTION INPUT ;
    USE SIGNAL ;
    SHAPE ABUTMENT ;
    PORT
      LAYER M3 ;
      RECT 89.487 56.359 89.505 56.413 ;
    END
  END w0_wmask_in[627]
  PIN w0_wmask_in[628]
    DIRECTION INPUT ;
    USE SIGNAL ;
    SHAPE ABUTMENT ;
    PORT
      LAYER M3 ;
      RECT 89.775 56.359 89.793 56.413 ;
    END
  END w0_wmask_in[628]
  PIN w0_wmask_in[629]
    DIRECTION INPUT ;
    USE SIGNAL ;
    SHAPE ABUTMENT ;
    PORT
      LAYER M3 ;
      RECT 90.063 56.359 90.081 56.413 ;
    END
  END w0_wmask_in[629]
  PIN w0_wmask_in[630]
    DIRECTION INPUT ;
    USE SIGNAL ;
    SHAPE ABUTMENT ;
    PORT
      LAYER M3 ;
      RECT 90.351 56.359 90.369 56.413 ;
    END
  END w0_wmask_in[630]
  PIN w0_wmask_in[631]
    DIRECTION INPUT ;
    USE SIGNAL ;
    SHAPE ABUTMENT ;
    PORT
      LAYER M3 ;
      RECT 90.639 56.359 90.657 56.413 ;
    END
  END w0_wmask_in[631]
  PIN w0_wmask_in[632]
    DIRECTION INPUT ;
    USE SIGNAL ;
    SHAPE ABUTMENT ;
    PORT
      LAYER M3 ;
      RECT 90.927 56.359 90.945 56.413 ;
    END
  END w0_wmask_in[632]
  PIN w0_wd_in[0]
    DIRECTION INPUT ;
    USE SIGNAL ;
    SHAPE ABUTMENT ;
    PORT
      LAYER M4 ;
      RECT 0.000 23.172 0.072 23.196 ;
    END
  END w0_wd_in[0]
  PIN w0_wd_in[1]
    DIRECTION INPUT ;
    USE SIGNAL ;
    SHAPE ABUTMENT ;
    PORT
      LAYER M4 ;
      RECT 0.000 23.316 0.072 23.340 ;
    END
  END w0_wd_in[1]
  PIN w0_wd_in[2]
    DIRECTION INPUT ;
    USE SIGNAL ;
    SHAPE ABUTMENT ;
    PORT
      LAYER M4 ;
      RECT 0.000 23.460 0.072 23.484 ;
    END
  END w0_wd_in[2]
  PIN w0_wd_in[3]
    DIRECTION INPUT ;
    USE SIGNAL ;
    SHAPE ABUTMENT ;
    PORT
      LAYER M4 ;
      RECT 0.000 23.604 0.072 23.628 ;
    END
  END w0_wd_in[3]
  PIN w0_wd_in[4]
    DIRECTION INPUT ;
    USE SIGNAL ;
    SHAPE ABUTMENT ;
    PORT
      LAYER M4 ;
      RECT 0.000 23.748 0.072 23.772 ;
    END
  END w0_wd_in[4]
  PIN w0_wd_in[5]
    DIRECTION INPUT ;
    USE SIGNAL ;
    SHAPE ABUTMENT ;
    PORT
      LAYER M4 ;
      RECT 0.000 23.892 0.072 23.916 ;
    END
  END w0_wd_in[5]
  PIN w0_wd_in[6]
    DIRECTION INPUT ;
    USE SIGNAL ;
    SHAPE ABUTMENT ;
    PORT
      LAYER M4 ;
      RECT 0.000 24.036 0.072 24.060 ;
    END
  END w0_wd_in[6]
  PIN w0_wd_in[7]
    DIRECTION INPUT ;
    USE SIGNAL ;
    SHAPE ABUTMENT ;
    PORT
      LAYER M4 ;
      RECT 0.000 24.180 0.072 24.204 ;
    END
  END w0_wd_in[7]
  PIN w0_wd_in[8]
    DIRECTION INPUT ;
    USE SIGNAL ;
    SHAPE ABUTMENT ;
    PORT
      LAYER M4 ;
      RECT 0.000 24.324 0.072 24.348 ;
    END
  END w0_wd_in[8]
  PIN w0_wd_in[9]
    DIRECTION INPUT ;
    USE SIGNAL ;
    SHAPE ABUTMENT ;
    PORT
      LAYER M4 ;
      RECT 0.000 24.468 0.072 24.492 ;
    END
  END w0_wd_in[9]
  PIN w0_wd_in[10]
    DIRECTION INPUT ;
    USE SIGNAL ;
    SHAPE ABUTMENT ;
    PORT
      LAYER M4 ;
      RECT 0.000 24.612 0.072 24.636 ;
    END
  END w0_wd_in[10]
  PIN w0_wd_in[11]
    DIRECTION INPUT ;
    USE SIGNAL ;
    SHAPE ABUTMENT ;
    PORT
      LAYER M4 ;
      RECT 0.000 24.756 0.072 24.780 ;
    END
  END w0_wd_in[11]
  PIN w0_wd_in[12]
    DIRECTION INPUT ;
    USE SIGNAL ;
    SHAPE ABUTMENT ;
    PORT
      LAYER M4 ;
      RECT 0.000 24.900 0.072 24.924 ;
    END
  END w0_wd_in[12]
  PIN w0_wd_in[13]
    DIRECTION INPUT ;
    USE SIGNAL ;
    SHAPE ABUTMENT ;
    PORT
      LAYER M4 ;
      RECT 0.000 25.044 0.072 25.068 ;
    END
  END w0_wd_in[13]
  PIN w0_wd_in[14]
    DIRECTION INPUT ;
    USE SIGNAL ;
    SHAPE ABUTMENT ;
    PORT
      LAYER M4 ;
      RECT 0.000 25.188 0.072 25.212 ;
    END
  END w0_wd_in[14]
  PIN w0_wd_in[15]
    DIRECTION INPUT ;
    USE SIGNAL ;
    SHAPE ABUTMENT ;
    PORT
      LAYER M4 ;
      RECT 0.000 25.332 0.072 25.356 ;
    END
  END w0_wd_in[15]
  PIN w0_wd_in[16]
    DIRECTION INPUT ;
    USE SIGNAL ;
    SHAPE ABUTMENT ;
    PORT
      LAYER M4 ;
      RECT 0.000 25.476 0.072 25.500 ;
    END
  END w0_wd_in[16]
  PIN w0_wd_in[17]
    DIRECTION INPUT ;
    USE SIGNAL ;
    SHAPE ABUTMENT ;
    PORT
      LAYER M4 ;
      RECT 0.000 25.620 0.072 25.644 ;
    END
  END w0_wd_in[17]
  PIN w0_wd_in[18]
    DIRECTION INPUT ;
    USE SIGNAL ;
    SHAPE ABUTMENT ;
    PORT
      LAYER M4 ;
      RECT 0.000 25.764 0.072 25.788 ;
    END
  END w0_wd_in[18]
  PIN w0_wd_in[19]
    DIRECTION INPUT ;
    USE SIGNAL ;
    SHAPE ABUTMENT ;
    PORT
      LAYER M4 ;
      RECT 0.000 25.908 0.072 25.932 ;
    END
  END w0_wd_in[19]
  PIN w0_wd_in[20]
    DIRECTION INPUT ;
    USE SIGNAL ;
    SHAPE ABUTMENT ;
    PORT
      LAYER M4 ;
      RECT 0.000 26.052 0.072 26.076 ;
    END
  END w0_wd_in[20]
  PIN w0_wd_in[21]
    DIRECTION INPUT ;
    USE SIGNAL ;
    SHAPE ABUTMENT ;
    PORT
      LAYER M4 ;
      RECT 0.000 26.196 0.072 26.220 ;
    END
  END w0_wd_in[21]
  PIN w0_wd_in[22]
    DIRECTION INPUT ;
    USE SIGNAL ;
    SHAPE ABUTMENT ;
    PORT
      LAYER M4 ;
      RECT 0.000 26.340 0.072 26.364 ;
    END
  END w0_wd_in[22]
  PIN w0_wd_in[23]
    DIRECTION INPUT ;
    USE SIGNAL ;
    SHAPE ABUTMENT ;
    PORT
      LAYER M4 ;
      RECT 0.000 26.484 0.072 26.508 ;
    END
  END w0_wd_in[23]
  PIN w0_wd_in[24]
    DIRECTION INPUT ;
    USE SIGNAL ;
    SHAPE ABUTMENT ;
    PORT
      LAYER M4 ;
      RECT 0.000 26.628 0.072 26.652 ;
    END
  END w0_wd_in[24]
  PIN w0_wd_in[25]
    DIRECTION INPUT ;
    USE SIGNAL ;
    SHAPE ABUTMENT ;
    PORT
      LAYER M4 ;
      RECT 0.000 26.772 0.072 26.796 ;
    END
  END w0_wd_in[25]
  PIN w0_wd_in[26]
    DIRECTION INPUT ;
    USE SIGNAL ;
    SHAPE ABUTMENT ;
    PORT
      LAYER M4 ;
      RECT 0.000 26.916 0.072 26.940 ;
    END
  END w0_wd_in[26]
  PIN w0_wd_in[27]
    DIRECTION INPUT ;
    USE SIGNAL ;
    SHAPE ABUTMENT ;
    PORT
      LAYER M4 ;
      RECT 0.000 27.060 0.072 27.084 ;
    END
  END w0_wd_in[27]
  PIN w0_wd_in[28]
    DIRECTION INPUT ;
    USE SIGNAL ;
    SHAPE ABUTMENT ;
    PORT
      LAYER M4 ;
      RECT 0.000 27.204 0.072 27.228 ;
    END
  END w0_wd_in[28]
  PIN w0_wd_in[29]
    DIRECTION INPUT ;
    USE SIGNAL ;
    SHAPE ABUTMENT ;
    PORT
      LAYER M4 ;
      RECT 0.000 27.348 0.072 27.372 ;
    END
  END w0_wd_in[29]
  PIN w0_wd_in[30]
    DIRECTION INPUT ;
    USE SIGNAL ;
    SHAPE ABUTMENT ;
    PORT
      LAYER M4 ;
      RECT 0.000 27.492 0.072 27.516 ;
    END
  END w0_wd_in[30]
  PIN w0_wd_in[31]
    DIRECTION INPUT ;
    USE SIGNAL ;
    SHAPE ABUTMENT ;
    PORT
      LAYER M4 ;
      RECT 0.000 27.636 0.072 27.660 ;
    END
  END w0_wd_in[31]
  PIN w0_wd_in[32]
    DIRECTION INPUT ;
    USE SIGNAL ;
    SHAPE ABUTMENT ;
    PORT
      LAYER M4 ;
      RECT 0.000 27.780 0.072 27.804 ;
    END
  END w0_wd_in[32]
  PIN w0_wd_in[33]
    DIRECTION INPUT ;
    USE SIGNAL ;
    SHAPE ABUTMENT ;
    PORT
      LAYER M4 ;
      RECT 0.000 27.924 0.072 27.948 ;
    END
  END w0_wd_in[33]
  PIN w0_wd_in[34]
    DIRECTION INPUT ;
    USE SIGNAL ;
    SHAPE ABUTMENT ;
    PORT
      LAYER M4 ;
      RECT 0.000 28.068 0.072 28.092 ;
    END
  END w0_wd_in[34]
  PIN w0_wd_in[35]
    DIRECTION INPUT ;
    USE SIGNAL ;
    SHAPE ABUTMENT ;
    PORT
      LAYER M4 ;
      RECT 0.000 28.212 0.072 28.236 ;
    END
  END w0_wd_in[35]
  PIN w0_wd_in[36]
    DIRECTION INPUT ;
    USE SIGNAL ;
    SHAPE ABUTMENT ;
    PORT
      LAYER M4 ;
      RECT 0.000 28.356 0.072 28.380 ;
    END
  END w0_wd_in[36]
  PIN w0_wd_in[37]
    DIRECTION INPUT ;
    USE SIGNAL ;
    SHAPE ABUTMENT ;
    PORT
      LAYER M4 ;
      RECT 0.000 28.500 0.072 28.524 ;
    END
  END w0_wd_in[37]
  PIN w0_wd_in[38]
    DIRECTION INPUT ;
    USE SIGNAL ;
    SHAPE ABUTMENT ;
    PORT
      LAYER M4 ;
      RECT 0.000 28.644 0.072 28.668 ;
    END
  END w0_wd_in[38]
  PIN w0_wd_in[39]
    DIRECTION INPUT ;
    USE SIGNAL ;
    SHAPE ABUTMENT ;
    PORT
      LAYER M4 ;
      RECT 0.000 28.788 0.072 28.812 ;
    END
  END w0_wd_in[39]
  PIN w0_wd_in[40]
    DIRECTION INPUT ;
    USE SIGNAL ;
    SHAPE ABUTMENT ;
    PORT
      LAYER M4 ;
      RECT 0.000 28.932 0.072 28.956 ;
    END
  END w0_wd_in[40]
  PIN w0_wd_in[41]
    DIRECTION INPUT ;
    USE SIGNAL ;
    SHAPE ABUTMENT ;
    PORT
      LAYER M4 ;
      RECT 0.000 29.076 0.072 29.100 ;
    END
  END w0_wd_in[41]
  PIN w0_wd_in[42]
    DIRECTION INPUT ;
    USE SIGNAL ;
    SHAPE ABUTMENT ;
    PORT
      LAYER M4 ;
      RECT 0.000 29.220 0.072 29.244 ;
    END
  END w0_wd_in[42]
  PIN w0_wd_in[43]
    DIRECTION INPUT ;
    USE SIGNAL ;
    SHAPE ABUTMENT ;
    PORT
      LAYER M4 ;
      RECT 0.000 29.364 0.072 29.388 ;
    END
  END w0_wd_in[43]
  PIN w0_wd_in[44]
    DIRECTION INPUT ;
    USE SIGNAL ;
    SHAPE ABUTMENT ;
    PORT
      LAYER M4 ;
      RECT 0.000 29.508 0.072 29.532 ;
    END
  END w0_wd_in[44]
  PIN w0_wd_in[45]
    DIRECTION INPUT ;
    USE SIGNAL ;
    SHAPE ABUTMENT ;
    PORT
      LAYER M4 ;
      RECT 0.000 29.652 0.072 29.676 ;
    END
  END w0_wd_in[45]
  PIN w0_wd_in[46]
    DIRECTION INPUT ;
    USE SIGNAL ;
    SHAPE ABUTMENT ;
    PORT
      LAYER M4 ;
      RECT 0.000 29.796 0.072 29.820 ;
    END
  END w0_wd_in[46]
  PIN w0_wd_in[47]
    DIRECTION INPUT ;
    USE SIGNAL ;
    SHAPE ABUTMENT ;
    PORT
      LAYER M4 ;
      RECT 0.000 29.940 0.072 29.964 ;
    END
  END w0_wd_in[47]
  PIN w0_wd_in[48]
    DIRECTION INPUT ;
    USE SIGNAL ;
    SHAPE ABUTMENT ;
    PORT
      LAYER M4 ;
      RECT 0.000 30.084 0.072 30.108 ;
    END
  END w0_wd_in[48]
  PIN w0_wd_in[49]
    DIRECTION INPUT ;
    USE SIGNAL ;
    SHAPE ABUTMENT ;
    PORT
      LAYER M4 ;
      RECT 0.000 30.228 0.072 30.252 ;
    END
  END w0_wd_in[49]
  PIN w0_wd_in[50]
    DIRECTION INPUT ;
    USE SIGNAL ;
    SHAPE ABUTMENT ;
    PORT
      LAYER M4 ;
      RECT 0.000 30.372 0.072 30.396 ;
    END
  END w0_wd_in[50]
  PIN w0_wd_in[51]
    DIRECTION INPUT ;
    USE SIGNAL ;
    SHAPE ABUTMENT ;
    PORT
      LAYER M4 ;
      RECT 0.000 30.516 0.072 30.540 ;
    END
  END w0_wd_in[51]
  PIN w0_wd_in[52]
    DIRECTION INPUT ;
    USE SIGNAL ;
    SHAPE ABUTMENT ;
    PORT
      LAYER M4 ;
      RECT 0.000 30.660 0.072 30.684 ;
    END
  END w0_wd_in[52]
  PIN w0_wd_in[53]
    DIRECTION INPUT ;
    USE SIGNAL ;
    SHAPE ABUTMENT ;
    PORT
      LAYER M4 ;
      RECT 0.000 30.804 0.072 30.828 ;
    END
  END w0_wd_in[53]
  PIN w0_wd_in[54]
    DIRECTION INPUT ;
    USE SIGNAL ;
    SHAPE ABUTMENT ;
    PORT
      LAYER M4 ;
      RECT 0.000 30.948 0.072 30.972 ;
    END
  END w0_wd_in[54]
  PIN w0_wd_in[55]
    DIRECTION INPUT ;
    USE SIGNAL ;
    SHAPE ABUTMENT ;
    PORT
      LAYER M4 ;
      RECT 0.000 31.092 0.072 31.116 ;
    END
  END w0_wd_in[55]
  PIN w0_wd_in[56]
    DIRECTION INPUT ;
    USE SIGNAL ;
    SHAPE ABUTMENT ;
    PORT
      LAYER M4 ;
      RECT 0.000 31.236 0.072 31.260 ;
    END
  END w0_wd_in[56]
  PIN w0_wd_in[57]
    DIRECTION INPUT ;
    USE SIGNAL ;
    SHAPE ABUTMENT ;
    PORT
      LAYER M4 ;
      RECT 0.000 31.380 0.072 31.404 ;
    END
  END w0_wd_in[57]
  PIN w0_wd_in[58]
    DIRECTION INPUT ;
    USE SIGNAL ;
    SHAPE ABUTMENT ;
    PORT
      LAYER M4 ;
      RECT 0.000 31.524 0.072 31.548 ;
    END
  END w0_wd_in[58]
  PIN w0_wd_in[59]
    DIRECTION INPUT ;
    USE SIGNAL ;
    SHAPE ABUTMENT ;
    PORT
      LAYER M4 ;
      RECT 0.000 31.668 0.072 31.692 ;
    END
  END w0_wd_in[59]
  PIN w0_wd_in[60]
    DIRECTION INPUT ;
    USE SIGNAL ;
    SHAPE ABUTMENT ;
    PORT
      LAYER M4 ;
      RECT 0.000 31.812 0.072 31.836 ;
    END
  END w0_wd_in[60]
  PIN w0_wd_in[61]
    DIRECTION INPUT ;
    USE SIGNAL ;
    SHAPE ABUTMENT ;
    PORT
      LAYER M4 ;
      RECT 0.000 31.956 0.072 31.980 ;
    END
  END w0_wd_in[61]
  PIN w0_wd_in[62]
    DIRECTION INPUT ;
    USE SIGNAL ;
    SHAPE ABUTMENT ;
    PORT
      LAYER M4 ;
      RECT 0.000 32.100 0.072 32.124 ;
    END
  END w0_wd_in[62]
  PIN w0_wd_in[63]
    DIRECTION INPUT ;
    USE SIGNAL ;
    SHAPE ABUTMENT ;
    PORT
      LAYER M4 ;
      RECT 0.000 32.244 0.072 32.268 ;
    END
  END w0_wd_in[63]
  PIN w0_wd_in[64]
    DIRECTION INPUT ;
    USE SIGNAL ;
    SHAPE ABUTMENT ;
    PORT
      LAYER M4 ;
      RECT 0.000 32.388 0.072 32.412 ;
    END
  END w0_wd_in[64]
  PIN w0_wd_in[65]
    DIRECTION INPUT ;
    USE SIGNAL ;
    SHAPE ABUTMENT ;
    PORT
      LAYER M4 ;
      RECT 0.000 32.532 0.072 32.556 ;
    END
  END w0_wd_in[65]
  PIN w0_wd_in[66]
    DIRECTION INPUT ;
    USE SIGNAL ;
    SHAPE ABUTMENT ;
    PORT
      LAYER M4 ;
      RECT 0.000 32.676 0.072 32.700 ;
    END
  END w0_wd_in[66]
  PIN w0_wd_in[67]
    DIRECTION INPUT ;
    USE SIGNAL ;
    SHAPE ABUTMENT ;
    PORT
      LAYER M4 ;
      RECT 0.000 32.820 0.072 32.844 ;
    END
  END w0_wd_in[67]
  PIN w0_wd_in[68]
    DIRECTION INPUT ;
    USE SIGNAL ;
    SHAPE ABUTMENT ;
    PORT
      LAYER M4 ;
      RECT 0.000 32.964 0.072 32.988 ;
    END
  END w0_wd_in[68]
  PIN w0_wd_in[69]
    DIRECTION INPUT ;
    USE SIGNAL ;
    SHAPE ABUTMENT ;
    PORT
      LAYER M4 ;
      RECT 0.000 33.108 0.072 33.132 ;
    END
  END w0_wd_in[69]
  PIN w0_wd_in[70]
    DIRECTION INPUT ;
    USE SIGNAL ;
    SHAPE ABUTMENT ;
    PORT
      LAYER M4 ;
      RECT 0.000 33.252 0.072 33.276 ;
    END
  END w0_wd_in[70]
  PIN w0_wd_in[71]
    DIRECTION INPUT ;
    USE SIGNAL ;
    SHAPE ABUTMENT ;
    PORT
      LAYER M4 ;
      RECT 0.000 33.396 0.072 33.420 ;
    END
  END w0_wd_in[71]
  PIN w0_wd_in[72]
    DIRECTION INPUT ;
    USE SIGNAL ;
    SHAPE ABUTMENT ;
    PORT
      LAYER M4 ;
      RECT 0.000 33.540 0.072 33.564 ;
    END
  END w0_wd_in[72]
  PIN w0_wd_in[73]
    DIRECTION INPUT ;
    USE SIGNAL ;
    SHAPE ABUTMENT ;
    PORT
      LAYER M4 ;
      RECT 0.000 33.684 0.072 33.708 ;
    END
  END w0_wd_in[73]
  PIN w0_wd_in[74]
    DIRECTION INPUT ;
    USE SIGNAL ;
    SHAPE ABUTMENT ;
    PORT
      LAYER M4 ;
      RECT 0.000 33.828 0.072 33.852 ;
    END
  END w0_wd_in[74]
  PIN w0_wd_in[75]
    DIRECTION INPUT ;
    USE SIGNAL ;
    SHAPE ABUTMENT ;
    PORT
      LAYER M4 ;
      RECT 0.000 33.972 0.072 33.996 ;
    END
  END w0_wd_in[75]
  PIN w0_wd_in[76]
    DIRECTION INPUT ;
    USE SIGNAL ;
    SHAPE ABUTMENT ;
    PORT
      LAYER M4 ;
      RECT 0.000 34.116 0.072 34.140 ;
    END
  END w0_wd_in[76]
  PIN w0_wd_in[77]
    DIRECTION INPUT ;
    USE SIGNAL ;
    SHAPE ABUTMENT ;
    PORT
      LAYER M4 ;
      RECT 0.000 34.260 0.072 34.284 ;
    END
  END w0_wd_in[77]
  PIN w0_wd_in[78]
    DIRECTION INPUT ;
    USE SIGNAL ;
    SHAPE ABUTMENT ;
    PORT
      LAYER M4 ;
      RECT 0.000 34.404 0.072 34.428 ;
    END
  END w0_wd_in[78]
  PIN w0_wd_in[79]
    DIRECTION INPUT ;
    USE SIGNAL ;
    SHAPE ABUTMENT ;
    PORT
      LAYER M4 ;
      RECT 0.000 34.548 0.072 34.572 ;
    END
  END w0_wd_in[79]
  PIN w0_wd_in[80]
    DIRECTION INPUT ;
    USE SIGNAL ;
    SHAPE ABUTMENT ;
    PORT
      LAYER M4 ;
      RECT 0.000 34.692 0.072 34.716 ;
    END
  END w0_wd_in[80]
  PIN w0_wd_in[81]
    DIRECTION INPUT ;
    USE SIGNAL ;
    SHAPE ABUTMENT ;
    PORT
      LAYER M4 ;
      RECT 0.000 34.836 0.072 34.860 ;
    END
  END w0_wd_in[81]
  PIN w0_wd_in[82]
    DIRECTION INPUT ;
    USE SIGNAL ;
    SHAPE ABUTMENT ;
    PORT
      LAYER M4 ;
      RECT 0.000 34.980 0.072 35.004 ;
    END
  END w0_wd_in[82]
  PIN w0_wd_in[83]
    DIRECTION INPUT ;
    USE SIGNAL ;
    SHAPE ABUTMENT ;
    PORT
      LAYER M4 ;
      RECT 0.000 35.124 0.072 35.148 ;
    END
  END w0_wd_in[83]
  PIN w0_wd_in[84]
    DIRECTION INPUT ;
    USE SIGNAL ;
    SHAPE ABUTMENT ;
    PORT
      LAYER M4 ;
      RECT 0.000 35.268 0.072 35.292 ;
    END
  END w0_wd_in[84]
  PIN w0_wd_in[85]
    DIRECTION INPUT ;
    USE SIGNAL ;
    SHAPE ABUTMENT ;
    PORT
      LAYER M4 ;
      RECT 0.000 35.412 0.072 35.436 ;
    END
  END w0_wd_in[85]
  PIN w0_wd_in[86]
    DIRECTION INPUT ;
    USE SIGNAL ;
    SHAPE ABUTMENT ;
    PORT
      LAYER M4 ;
      RECT 0.000 35.556 0.072 35.580 ;
    END
  END w0_wd_in[86]
  PIN w0_wd_in[87]
    DIRECTION INPUT ;
    USE SIGNAL ;
    SHAPE ABUTMENT ;
    PORT
      LAYER M4 ;
      RECT 0.000 35.700 0.072 35.724 ;
    END
  END w0_wd_in[87]
  PIN w0_wd_in[88]
    DIRECTION INPUT ;
    USE SIGNAL ;
    SHAPE ABUTMENT ;
    PORT
      LAYER M4 ;
      RECT 0.000 35.844 0.072 35.868 ;
    END
  END w0_wd_in[88]
  PIN w0_wd_in[89]
    DIRECTION INPUT ;
    USE SIGNAL ;
    SHAPE ABUTMENT ;
    PORT
      LAYER M4 ;
      RECT 0.000 35.988 0.072 36.012 ;
    END
  END w0_wd_in[89]
  PIN w0_wd_in[90]
    DIRECTION INPUT ;
    USE SIGNAL ;
    SHAPE ABUTMENT ;
    PORT
      LAYER M4 ;
      RECT 0.000 36.132 0.072 36.156 ;
    END
  END w0_wd_in[90]
  PIN w0_wd_in[91]
    DIRECTION INPUT ;
    USE SIGNAL ;
    SHAPE ABUTMENT ;
    PORT
      LAYER M4 ;
      RECT 0.000 36.276 0.072 36.300 ;
    END
  END w0_wd_in[91]
  PIN w0_wd_in[92]
    DIRECTION INPUT ;
    USE SIGNAL ;
    SHAPE ABUTMENT ;
    PORT
      LAYER M4 ;
      RECT 0.000 36.420 0.072 36.444 ;
    END
  END w0_wd_in[92]
  PIN w0_wd_in[93]
    DIRECTION INPUT ;
    USE SIGNAL ;
    SHAPE ABUTMENT ;
    PORT
      LAYER M4 ;
      RECT 0.000 36.564 0.072 36.588 ;
    END
  END w0_wd_in[93]
  PIN w0_wd_in[94]
    DIRECTION INPUT ;
    USE SIGNAL ;
    SHAPE ABUTMENT ;
    PORT
      LAYER M4 ;
      RECT 0.000 36.708 0.072 36.732 ;
    END
  END w0_wd_in[94]
  PIN w0_wd_in[95]
    DIRECTION INPUT ;
    USE SIGNAL ;
    SHAPE ABUTMENT ;
    PORT
      LAYER M4 ;
      RECT 0.000 36.852 0.072 36.876 ;
    END
  END w0_wd_in[95]
  PIN w0_wd_in[96]
    DIRECTION INPUT ;
    USE SIGNAL ;
    SHAPE ABUTMENT ;
    PORT
      LAYER M4 ;
      RECT 0.000 36.996 0.072 37.020 ;
    END
  END w0_wd_in[96]
  PIN w0_wd_in[97]
    DIRECTION INPUT ;
    USE SIGNAL ;
    SHAPE ABUTMENT ;
    PORT
      LAYER M4 ;
      RECT 0.000 37.140 0.072 37.164 ;
    END
  END w0_wd_in[97]
  PIN w0_wd_in[98]
    DIRECTION INPUT ;
    USE SIGNAL ;
    SHAPE ABUTMENT ;
    PORT
      LAYER M4 ;
      RECT 0.000 37.284 0.072 37.308 ;
    END
  END w0_wd_in[98]
  PIN w0_wd_in[99]
    DIRECTION INPUT ;
    USE SIGNAL ;
    SHAPE ABUTMENT ;
    PORT
      LAYER M4 ;
      RECT 0.000 37.428 0.072 37.452 ;
    END
  END w0_wd_in[99]
  PIN w0_wd_in[100]
    DIRECTION INPUT ;
    USE SIGNAL ;
    SHAPE ABUTMENT ;
    PORT
      LAYER M4 ;
      RECT 0.000 37.572 0.072 37.596 ;
    END
  END w0_wd_in[100]
  PIN w0_wd_in[101]
    DIRECTION INPUT ;
    USE SIGNAL ;
    SHAPE ABUTMENT ;
    PORT
      LAYER M4 ;
      RECT 0.000 37.716 0.072 37.740 ;
    END
  END w0_wd_in[101]
  PIN w0_wd_in[102]
    DIRECTION INPUT ;
    USE SIGNAL ;
    SHAPE ABUTMENT ;
    PORT
      LAYER M4 ;
      RECT 0.000 37.860 0.072 37.884 ;
    END
  END w0_wd_in[102]
  PIN w0_wd_in[103]
    DIRECTION INPUT ;
    USE SIGNAL ;
    SHAPE ABUTMENT ;
    PORT
      LAYER M4 ;
      RECT 0.000 38.004 0.072 38.028 ;
    END
  END w0_wd_in[103]
  PIN w0_wd_in[104]
    DIRECTION INPUT ;
    USE SIGNAL ;
    SHAPE ABUTMENT ;
    PORT
      LAYER M4 ;
      RECT 0.000 38.148 0.072 38.172 ;
    END
  END w0_wd_in[104]
  PIN w0_wd_in[105]
    DIRECTION INPUT ;
    USE SIGNAL ;
    SHAPE ABUTMENT ;
    PORT
      LAYER M4 ;
      RECT 0.000 38.292 0.072 38.316 ;
    END
  END w0_wd_in[105]
  PIN w0_wd_in[106]
    DIRECTION INPUT ;
    USE SIGNAL ;
    SHAPE ABUTMENT ;
    PORT
      LAYER M4 ;
      RECT 0.000 38.436 0.072 38.460 ;
    END
  END w0_wd_in[106]
  PIN w0_wd_in[107]
    DIRECTION INPUT ;
    USE SIGNAL ;
    SHAPE ABUTMENT ;
    PORT
      LAYER M4 ;
      RECT 0.000 38.580 0.072 38.604 ;
    END
  END w0_wd_in[107]
  PIN w0_wd_in[108]
    DIRECTION INPUT ;
    USE SIGNAL ;
    SHAPE ABUTMENT ;
    PORT
      LAYER M4 ;
      RECT 0.000 38.724 0.072 38.748 ;
    END
  END w0_wd_in[108]
  PIN w0_wd_in[109]
    DIRECTION INPUT ;
    USE SIGNAL ;
    SHAPE ABUTMENT ;
    PORT
      LAYER M4 ;
      RECT 0.000 38.868 0.072 38.892 ;
    END
  END w0_wd_in[109]
  PIN w0_wd_in[110]
    DIRECTION INPUT ;
    USE SIGNAL ;
    SHAPE ABUTMENT ;
    PORT
      LAYER M4 ;
      RECT 0.000 39.012 0.072 39.036 ;
    END
  END w0_wd_in[110]
  PIN w0_wd_in[111]
    DIRECTION INPUT ;
    USE SIGNAL ;
    SHAPE ABUTMENT ;
    PORT
      LAYER M4 ;
      RECT 0.000 39.156 0.072 39.180 ;
    END
  END w0_wd_in[111]
  PIN w0_wd_in[112]
    DIRECTION INPUT ;
    USE SIGNAL ;
    SHAPE ABUTMENT ;
    PORT
      LAYER M4 ;
      RECT 0.000 39.300 0.072 39.324 ;
    END
  END w0_wd_in[112]
  PIN w0_wd_in[113]
    DIRECTION INPUT ;
    USE SIGNAL ;
    SHAPE ABUTMENT ;
    PORT
      LAYER M4 ;
      RECT 0.000 39.444 0.072 39.468 ;
    END
  END w0_wd_in[113]
  PIN w0_wd_in[114]
    DIRECTION INPUT ;
    USE SIGNAL ;
    SHAPE ABUTMENT ;
    PORT
      LAYER M4 ;
      RECT 0.000 39.588 0.072 39.612 ;
    END
  END w0_wd_in[114]
  PIN w0_wd_in[115]
    DIRECTION INPUT ;
    USE SIGNAL ;
    SHAPE ABUTMENT ;
    PORT
      LAYER M4 ;
      RECT 0.000 39.732 0.072 39.756 ;
    END
  END w0_wd_in[115]
  PIN w0_wd_in[116]
    DIRECTION INPUT ;
    USE SIGNAL ;
    SHAPE ABUTMENT ;
    PORT
      LAYER M4 ;
      RECT 0.000 39.876 0.072 39.900 ;
    END
  END w0_wd_in[116]
  PIN w0_wd_in[117]
    DIRECTION INPUT ;
    USE SIGNAL ;
    SHAPE ABUTMENT ;
    PORT
      LAYER M4 ;
      RECT 0.000 40.020 0.072 40.044 ;
    END
  END w0_wd_in[117]
  PIN w0_wd_in[118]
    DIRECTION INPUT ;
    USE SIGNAL ;
    SHAPE ABUTMENT ;
    PORT
      LAYER M4 ;
      RECT 0.000 40.164 0.072 40.188 ;
    END
  END w0_wd_in[118]
  PIN w0_wd_in[119]
    DIRECTION INPUT ;
    USE SIGNAL ;
    SHAPE ABUTMENT ;
    PORT
      LAYER M4 ;
      RECT 0.000 40.308 0.072 40.332 ;
    END
  END w0_wd_in[119]
  PIN w0_wd_in[120]
    DIRECTION INPUT ;
    USE SIGNAL ;
    SHAPE ABUTMENT ;
    PORT
      LAYER M4 ;
      RECT 0.000 40.452 0.072 40.476 ;
    END
  END w0_wd_in[120]
  PIN w0_wd_in[121]
    DIRECTION INPUT ;
    USE SIGNAL ;
    SHAPE ABUTMENT ;
    PORT
      LAYER M4 ;
      RECT 0.000 40.596 0.072 40.620 ;
    END
  END w0_wd_in[121]
  PIN w0_wd_in[122]
    DIRECTION INPUT ;
    USE SIGNAL ;
    SHAPE ABUTMENT ;
    PORT
      LAYER M4 ;
      RECT 0.000 40.740 0.072 40.764 ;
    END
  END w0_wd_in[122]
  PIN w0_wd_in[123]
    DIRECTION INPUT ;
    USE SIGNAL ;
    SHAPE ABUTMENT ;
    PORT
      LAYER M4 ;
      RECT 0.000 40.884 0.072 40.908 ;
    END
  END w0_wd_in[123]
  PIN w0_wd_in[124]
    DIRECTION INPUT ;
    USE SIGNAL ;
    SHAPE ABUTMENT ;
    PORT
      LAYER M4 ;
      RECT 0.000 41.028 0.072 41.052 ;
    END
  END w0_wd_in[124]
  PIN w0_wd_in[125]
    DIRECTION INPUT ;
    USE SIGNAL ;
    SHAPE ABUTMENT ;
    PORT
      LAYER M4 ;
      RECT 0.000 41.172 0.072 41.196 ;
    END
  END w0_wd_in[125]
  PIN w0_wd_in[126]
    DIRECTION INPUT ;
    USE SIGNAL ;
    SHAPE ABUTMENT ;
    PORT
      LAYER M4 ;
      RECT 0.000 41.316 0.072 41.340 ;
    END
  END w0_wd_in[126]
  PIN w0_wd_in[127]
    DIRECTION INPUT ;
    USE SIGNAL ;
    SHAPE ABUTMENT ;
    PORT
      LAYER M4 ;
      RECT 0.000 41.460 0.072 41.484 ;
    END
  END w0_wd_in[127]
  PIN w0_wd_in[128]
    DIRECTION INPUT ;
    USE SIGNAL ;
    SHAPE ABUTMENT ;
    PORT
      LAYER M4 ;
      RECT 0.000 41.604 0.072 41.628 ;
    END
  END w0_wd_in[128]
  PIN w0_wd_in[129]
    DIRECTION INPUT ;
    USE SIGNAL ;
    SHAPE ABUTMENT ;
    PORT
      LAYER M4 ;
      RECT 0.000 41.748 0.072 41.772 ;
    END
  END w0_wd_in[129]
  PIN w0_wd_in[130]
    DIRECTION INPUT ;
    USE SIGNAL ;
    SHAPE ABUTMENT ;
    PORT
      LAYER M4 ;
      RECT 0.000 41.892 0.072 41.916 ;
    END
  END w0_wd_in[130]
  PIN w0_wd_in[131]
    DIRECTION INPUT ;
    USE SIGNAL ;
    SHAPE ABUTMENT ;
    PORT
      LAYER M4 ;
      RECT 0.000 42.036 0.072 42.060 ;
    END
  END w0_wd_in[131]
  PIN w0_wd_in[132]
    DIRECTION INPUT ;
    USE SIGNAL ;
    SHAPE ABUTMENT ;
    PORT
      LAYER M4 ;
      RECT 0.000 42.180 0.072 42.204 ;
    END
  END w0_wd_in[132]
  PIN w0_wd_in[133]
    DIRECTION INPUT ;
    USE SIGNAL ;
    SHAPE ABUTMENT ;
    PORT
      LAYER M4 ;
      RECT 0.000 42.324 0.072 42.348 ;
    END
  END w0_wd_in[133]
  PIN w0_wd_in[134]
    DIRECTION INPUT ;
    USE SIGNAL ;
    SHAPE ABUTMENT ;
    PORT
      LAYER M4 ;
      RECT 0.000 42.468 0.072 42.492 ;
    END
  END w0_wd_in[134]
  PIN w0_wd_in[135]
    DIRECTION INPUT ;
    USE SIGNAL ;
    SHAPE ABUTMENT ;
    PORT
      LAYER M4 ;
      RECT 0.000 42.612 0.072 42.636 ;
    END
  END w0_wd_in[135]
  PIN w0_wd_in[136]
    DIRECTION INPUT ;
    USE SIGNAL ;
    SHAPE ABUTMENT ;
    PORT
      LAYER M4 ;
      RECT 0.000 42.756 0.072 42.780 ;
    END
  END w0_wd_in[136]
  PIN w0_wd_in[137]
    DIRECTION INPUT ;
    USE SIGNAL ;
    SHAPE ABUTMENT ;
    PORT
      LAYER M4 ;
      RECT 0.000 42.900 0.072 42.924 ;
    END
  END w0_wd_in[137]
  PIN w0_wd_in[138]
    DIRECTION INPUT ;
    USE SIGNAL ;
    SHAPE ABUTMENT ;
    PORT
      LAYER M4 ;
      RECT 0.000 43.044 0.072 43.068 ;
    END
  END w0_wd_in[138]
  PIN w0_wd_in[139]
    DIRECTION INPUT ;
    USE SIGNAL ;
    SHAPE ABUTMENT ;
    PORT
      LAYER M4 ;
      RECT 0.000 43.188 0.072 43.212 ;
    END
  END w0_wd_in[139]
  PIN w0_wd_in[140]
    DIRECTION INPUT ;
    USE SIGNAL ;
    SHAPE ABUTMENT ;
    PORT
      LAYER M4 ;
      RECT 0.000 43.332 0.072 43.356 ;
    END
  END w0_wd_in[140]
  PIN w0_wd_in[141]
    DIRECTION INPUT ;
    USE SIGNAL ;
    SHAPE ABUTMENT ;
    PORT
      LAYER M4 ;
      RECT 0.000 43.476 0.072 43.500 ;
    END
  END w0_wd_in[141]
  PIN w0_wd_in[142]
    DIRECTION INPUT ;
    USE SIGNAL ;
    SHAPE ABUTMENT ;
    PORT
      LAYER M4 ;
      RECT 0.000 43.620 0.072 43.644 ;
    END
  END w0_wd_in[142]
  PIN w0_wd_in[143]
    DIRECTION INPUT ;
    USE SIGNAL ;
    SHAPE ABUTMENT ;
    PORT
      LAYER M4 ;
      RECT 0.000 43.764 0.072 43.788 ;
    END
  END w0_wd_in[143]
  PIN w0_wd_in[144]
    DIRECTION INPUT ;
    USE SIGNAL ;
    SHAPE ABUTMENT ;
    PORT
      LAYER M4 ;
      RECT 0.000 43.908 0.072 43.932 ;
    END
  END w0_wd_in[144]
  PIN w0_wd_in[145]
    DIRECTION INPUT ;
    USE SIGNAL ;
    SHAPE ABUTMENT ;
    PORT
      LAYER M4 ;
      RECT 0.000 44.052 0.072 44.076 ;
    END
  END w0_wd_in[145]
  PIN w0_wd_in[146]
    DIRECTION INPUT ;
    USE SIGNAL ;
    SHAPE ABUTMENT ;
    PORT
      LAYER M4 ;
      RECT 0.000 44.196 0.072 44.220 ;
    END
  END w0_wd_in[146]
  PIN w0_wd_in[147]
    DIRECTION INPUT ;
    USE SIGNAL ;
    SHAPE ABUTMENT ;
    PORT
      LAYER M4 ;
      RECT 0.000 44.340 0.072 44.364 ;
    END
  END w0_wd_in[147]
  PIN w0_wd_in[148]
    DIRECTION INPUT ;
    USE SIGNAL ;
    SHAPE ABUTMENT ;
    PORT
      LAYER M4 ;
      RECT 0.000 44.484 0.072 44.508 ;
    END
  END w0_wd_in[148]
  PIN w0_wd_in[149]
    DIRECTION INPUT ;
    USE SIGNAL ;
    SHAPE ABUTMENT ;
    PORT
      LAYER M4 ;
      RECT 0.000 44.628 0.072 44.652 ;
    END
  END w0_wd_in[149]
  PIN w0_wd_in[150]
    DIRECTION INPUT ;
    USE SIGNAL ;
    SHAPE ABUTMENT ;
    PORT
      LAYER M4 ;
      RECT 0.000 44.772 0.072 44.796 ;
    END
  END w0_wd_in[150]
  PIN w0_wd_in[151]
    DIRECTION INPUT ;
    USE SIGNAL ;
    SHAPE ABUTMENT ;
    PORT
      LAYER M4 ;
      RECT 0.000 44.916 0.072 44.940 ;
    END
  END w0_wd_in[151]
  PIN w0_wd_in[152]
    DIRECTION INPUT ;
    USE SIGNAL ;
    SHAPE ABUTMENT ;
    PORT
      LAYER M4 ;
      RECT 0.000 45.060 0.072 45.084 ;
    END
  END w0_wd_in[152]
  PIN w0_wd_in[153]
    DIRECTION INPUT ;
    USE SIGNAL ;
    SHAPE ABUTMENT ;
    PORT
      LAYER M4 ;
      RECT 0.000 45.204 0.072 45.228 ;
    END
  END w0_wd_in[153]
  PIN w0_wd_in[154]
    DIRECTION INPUT ;
    USE SIGNAL ;
    SHAPE ABUTMENT ;
    PORT
      LAYER M4 ;
      RECT 0.000 45.348 0.072 45.372 ;
    END
  END w0_wd_in[154]
  PIN w0_wd_in[155]
    DIRECTION INPUT ;
    USE SIGNAL ;
    SHAPE ABUTMENT ;
    PORT
      LAYER M4 ;
      RECT 0.000 45.492 0.072 45.516 ;
    END
  END w0_wd_in[155]
  PIN w0_wd_in[156]
    DIRECTION INPUT ;
    USE SIGNAL ;
    SHAPE ABUTMENT ;
    PORT
      LAYER M4 ;
      RECT 0.000 45.636 0.072 45.660 ;
    END
  END w0_wd_in[156]
  PIN w0_wd_in[157]
    DIRECTION INPUT ;
    USE SIGNAL ;
    SHAPE ABUTMENT ;
    PORT
      LAYER M4 ;
      RECT 0.000 45.780 0.072 45.804 ;
    END
  END w0_wd_in[157]
  PIN w0_wd_in[158]
    DIRECTION INPUT ;
    USE SIGNAL ;
    SHAPE ABUTMENT ;
    PORT
      LAYER M4 ;
      RECT 0.000 45.924 0.072 45.948 ;
    END
  END w0_wd_in[158]
  PIN w0_wd_in[159]
    DIRECTION INPUT ;
    USE SIGNAL ;
    SHAPE ABUTMENT ;
    PORT
      LAYER M4 ;
      RECT 201.739 23.028 201.811 23.052 ;
    END
  END w0_wd_in[159]
  PIN w0_wd_in[160]
    DIRECTION INPUT ;
    USE SIGNAL ;
    SHAPE ABUTMENT ;
    PORT
      LAYER M4 ;
      RECT 201.739 23.172 201.811 23.196 ;
    END
  END w0_wd_in[160]
  PIN w0_wd_in[161]
    DIRECTION INPUT ;
    USE SIGNAL ;
    SHAPE ABUTMENT ;
    PORT
      LAYER M4 ;
      RECT 201.739 23.316 201.811 23.340 ;
    END
  END w0_wd_in[161]
  PIN w0_wd_in[162]
    DIRECTION INPUT ;
    USE SIGNAL ;
    SHAPE ABUTMENT ;
    PORT
      LAYER M4 ;
      RECT 201.739 23.460 201.811 23.484 ;
    END
  END w0_wd_in[162]
  PIN w0_wd_in[163]
    DIRECTION INPUT ;
    USE SIGNAL ;
    SHAPE ABUTMENT ;
    PORT
      LAYER M4 ;
      RECT 201.739 23.604 201.811 23.628 ;
    END
  END w0_wd_in[163]
  PIN w0_wd_in[164]
    DIRECTION INPUT ;
    USE SIGNAL ;
    SHAPE ABUTMENT ;
    PORT
      LAYER M4 ;
      RECT 201.739 23.748 201.811 23.772 ;
    END
  END w0_wd_in[164]
  PIN w0_wd_in[165]
    DIRECTION INPUT ;
    USE SIGNAL ;
    SHAPE ABUTMENT ;
    PORT
      LAYER M4 ;
      RECT 201.739 23.892 201.811 23.916 ;
    END
  END w0_wd_in[165]
  PIN w0_wd_in[166]
    DIRECTION INPUT ;
    USE SIGNAL ;
    SHAPE ABUTMENT ;
    PORT
      LAYER M4 ;
      RECT 201.739 24.036 201.811 24.060 ;
    END
  END w0_wd_in[166]
  PIN w0_wd_in[167]
    DIRECTION INPUT ;
    USE SIGNAL ;
    SHAPE ABUTMENT ;
    PORT
      LAYER M4 ;
      RECT 201.739 24.180 201.811 24.204 ;
    END
  END w0_wd_in[167]
  PIN w0_wd_in[168]
    DIRECTION INPUT ;
    USE SIGNAL ;
    SHAPE ABUTMENT ;
    PORT
      LAYER M4 ;
      RECT 201.739 24.324 201.811 24.348 ;
    END
  END w0_wd_in[168]
  PIN w0_wd_in[169]
    DIRECTION INPUT ;
    USE SIGNAL ;
    SHAPE ABUTMENT ;
    PORT
      LAYER M4 ;
      RECT 201.739 24.468 201.811 24.492 ;
    END
  END w0_wd_in[169]
  PIN w0_wd_in[170]
    DIRECTION INPUT ;
    USE SIGNAL ;
    SHAPE ABUTMENT ;
    PORT
      LAYER M4 ;
      RECT 201.739 24.612 201.811 24.636 ;
    END
  END w0_wd_in[170]
  PIN w0_wd_in[171]
    DIRECTION INPUT ;
    USE SIGNAL ;
    SHAPE ABUTMENT ;
    PORT
      LAYER M4 ;
      RECT 201.739 24.756 201.811 24.780 ;
    END
  END w0_wd_in[171]
  PIN w0_wd_in[172]
    DIRECTION INPUT ;
    USE SIGNAL ;
    SHAPE ABUTMENT ;
    PORT
      LAYER M4 ;
      RECT 201.739 24.900 201.811 24.924 ;
    END
  END w0_wd_in[172]
  PIN w0_wd_in[173]
    DIRECTION INPUT ;
    USE SIGNAL ;
    SHAPE ABUTMENT ;
    PORT
      LAYER M4 ;
      RECT 201.739 25.044 201.811 25.068 ;
    END
  END w0_wd_in[173]
  PIN w0_wd_in[174]
    DIRECTION INPUT ;
    USE SIGNAL ;
    SHAPE ABUTMENT ;
    PORT
      LAYER M4 ;
      RECT 201.739 25.188 201.811 25.212 ;
    END
  END w0_wd_in[174]
  PIN w0_wd_in[175]
    DIRECTION INPUT ;
    USE SIGNAL ;
    SHAPE ABUTMENT ;
    PORT
      LAYER M4 ;
      RECT 201.739 25.332 201.811 25.356 ;
    END
  END w0_wd_in[175]
  PIN w0_wd_in[176]
    DIRECTION INPUT ;
    USE SIGNAL ;
    SHAPE ABUTMENT ;
    PORT
      LAYER M4 ;
      RECT 201.739 25.476 201.811 25.500 ;
    END
  END w0_wd_in[176]
  PIN w0_wd_in[177]
    DIRECTION INPUT ;
    USE SIGNAL ;
    SHAPE ABUTMENT ;
    PORT
      LAYER M4 ;
      RECT 201.739 25.620 201.811 25.644 ;
    END
  END w0_wd_in[177]
  PIN w0_wd_in[178]
    DIRECTION INPUT ;
    USE SIGNAL ;
    SHAPE ABUTMENT ;
    PORT
      LAYER M4 ;
      RECT 201.739 25.764 201.811 25.788 ;
    END
  END w0_wd_in[178]
  PIN w0_wd_in[179]
    DIRECTION INPUT ;
    USE SIGNAL ;
    SHAPE ABUTMENT ;
    PORT
      LAYER M4 ;
      RECT 201.739 25.908 201.811 25.932 ;
    END
  END w0_wd_in[179]
  PIN w0_wd_in[180]
    DIRECTION INPUT ;
    USE SIGNAL ;
    SHAPE ABUTMENT ;
    PORT
      LAYER M4 ;
      RECT 201.739 26.052 201.811 26.076 ;
    END
  END w0_wd_in[180]
  PIN w0_wd_in[181]
    DIRECTION INPUT ;
    USE SIGNAL ;
    SHAPE ABUTMENT ;
    PORT
      LAYER M4 ;
      RECT 201.739 26.196 201.811 26.220 ;
    END
  END w0_wd_in[181]
  PIN w0_wd_in[182]
    DIRECTION INPUT ;
    USE SIGNAL ;
    SHAPE ABUTMENT ;
    PORT
      LAYER M4 ;
      RECT 201.739 26.340 201.811 26.364 ;
    END
  END w0_wd_in[182]
  PIN w0_wd_in[183]
    DIRECTION INPUT ;
    USE SIGNAL ;
    SHAPE ABUTMENT ;
    PORT
      LAYER M4 ;
      RECT 201.739 26.484 201.811 26.508 ;
    END
  END w0_wd_in[183]
  PIN w0_wd_in[184]
    DIRECTION INPUT ;
    USE SIGNAL ;
    SHAPE ABUTMENT ;
    PORT
      LAYER M4 ;
      RECT 201.739 26.628 201.811 26.652 ;
    END
  END w0_wd_in[184]
  PIN w0_wd_in[185]
    DIRECTION INPUT ;
    USE SIGNAL ;
    SHAPE ABUTMENT ;
    PORT
      LAYER M4 ;
      RECT 201.739 26.772 201.811 26.796 ;
    END
  END w0_wd_in[185]
  PIN w0_wd_in[186]
    DIRECTION INPUT ;
    USE SIGNAL ;
    SHAPE ABUTMENT ;
    PORT
      LAYER M4 ;
      RECT 201.739 26.916 201.811 26.940 ;
    END
  END w0_wd_in[186]
  PIN w0_wd_in[187]
    DIRECTION INPUT ;
    USE SIGNAL ;
    SHAPE ABUTMENT ;
    PORT
      LAYER M4 ;
      RECT 201.739 27.060 201.811 27.084 ;
    END
  END w0_wd_in[187]
  PIN w0_wd_in[188]
    DIRECTION INPUT ;
    USE SIGNAL ;
    SHAPE ABUTMENT ;
    PORT
      LAYER M4 ;
      RECT 201.739 27.204 201.811 27.228 ;
    END
  END w0_wd_in[188]
  PIN w0_wd_in[189]
    DIRECTION INPUT ;
    USE SIGNAL ;
    SHAPE ABUTMENT ;
    PORT
      LAYER M4 ;
      RECT 201.739 27.348 201.811 27.372 ;
    END
  END w0_wd_in[189]
  PIN w0_wd_in[190]
    DIRECTION INPUT ;
    USE SIGNAL ;
    SHAPE ABUTMENT ;
    PORT
      LAYER M4 ;
      RECT 201.739 27.492 201.811 27.516 ;
    END
  END w0_wd_in[190]
  PIN w0_wd_in[191]
    DIRECTION INPUT ;
    USE SIGNAL ;
    SHAPE ABUTMENT ;
    PORT
      LAYER M4 ;
      RECT 201.739 27.636 201.811 27.660 ;
    END
  END w0_wd_in[191]
  PIN w0_wd_in[192]
    DIRECTION INPUT ;
    USE SIGNAL ;
    SHAPE ABUTMENT ;
    PORT
      LAYER M4 ;
      RECT 201.739 27.780 201.811 27.804 ;
    END
  END w0_wd_in[192]
  PIN w0_wd_in[193]
    DIRECTION INPUT ;
    USE SIGNAL ;
    SHAPE ABUTMENT ;
    PORT
      LAYER M4 ;
      RECT 201.739 27.924 201.811 27.948 ;
    END
  END w0_wd_in[193]
  PIN w0_wd_in[194]
    DIRECTION INPUT ;
    USE SIGNAL ;
    SHAPE ABUTMENT ;
    PORT
      LAYER M4 ;
      RECT 201.739 28.068 201.811 28.092 ;
    END
  END w0_wd_in[194]
  PIN w0_wd_in[195]
    DIRECTION INPUT ;
    USE SIGNAL ;
    SHAPE ABUTMENT ;
    PORT
      LAYER M4 ;
      RECT 201.739 28.212 201.811 28.236 ;
    END
  END w0_wd_in[195]
  PIN w0_wd_in[196]
    DIRECTION INPUT ;
    USE SIGNAL ;
    SHAPE ABUTMENT ;
    PORT
      LAYER M4 ;
      RECT 201.739 28.356 201.811 28.380 ;
    END
  END w0_wd_in[196]
  PIN w0_wd_in[197]
    DIRECTION INPUT ;
    USE SIGNAL ;
    SHAPE ABUTMENT ;
    PORT
      LAYER M4 ;
      RECT 201.739 28.500 201.811 28.524 ;
    END
  END w0_wd_in[197]
  PIN w0_wd_in[198]
    DIRECTION INPUT ;
    USE SIGNAL ;
    SHAPE ABUTMENT ;
    PORT
      LAYER M4 ;
      RECT 201.739 28.644 201.811 28.668 ;
    END
  END w0_wd_in[198]
  PIN w0_wd_in[199]
    DIRECTION INPUT ;
    USE SIGNAL ;
    SHAPE ABUTMENT ;
    PORT
      LAYER M4 ;
      RECT 201.739 28.788 201.811 28.812 ;
    END
  END w0_wd_in[199]
  PIN w0_wd_in[200]
    DIRECTION INPUT ;
    USE SIGNAL ;
    SHAPE ABUTMENT ;
    PORT
      LAYER M4 ;
      RECT 201.739 28.932 201.811 28.956 ;
    END
  END w0_wd_in[200]
  PIN w0_wd_in[201]
    DIRECTION INPUT ;
    USE SIGNAL ;
    SHAPE ABUTMENT ;
    PORT
      LAYER M4 ;
      RECT 201.739 29.076 201.811 29.100 ;
    END
  END w0_wd_in[201]
  PIN w0_wd_in[202]
    DIRECTION INPUT ;
    USE SIGNAL ;
    SHAPE ABUTMENT ;
    PORT
      LAYER M4 ;
      RECT 201.739 29.220 201.811 29.244 ;
    END
  END w0_wd_in[202]
  PIN w0_wd_in[203]
    DIRECTION INPUT ;
    USE SIGNAL ;
    SHAPE ABUTMENT ;
    PORT
      LAYER M4 ;
      RECT 201.739 29.364 201.811 29.388 ;
    END
  END w0_wd_in[203]
  PIN w0_wd_in[204]
    DIRECTION INPUT ;
    USE SIGNAL ;
    SHAPE ABUTMENT ;
    PORT
      LAYER M4 ;
      RECT 201.739 29.508 201.811 29.532 ;
    END
  END w0_wd_in[204]
  PIN w0_wd_in[205]
    DIRECTION INPUT ;
    USE SIGNAL ;
    SHAPE ABUTMENT ;
    PORT
      LAYER M4 ;
      RECT 201.739 29.652 201.811 29.676 ;
    END
  END w0_wd_in[205]
  PIN w0_wd_in[206]
    DIRECTION INPUT ;
    USE SIGNAL ;
    SHAPE ABUTMENT ;
    PORT
      LAYER M4 ;
      RECT 201.739 29.796 201.811 29.820 ;
    END
  END w0_wd_in[206]
  PIN w0_wd_in[207]
    DIRECTION INPUT ;
    USE SIGNAL ;
    SHAPE ABUTMENT ;
    PORT
      LAYER M4 ;
      RECT 201.739 29.940 201.811 29.964 ;
    END
  END w0_wd_in[207]
  PIN w0_wd_in[208]
    DIRECTION INPUT ;
    USE SIGNAL ;
    SHAPE ABUTMENT ;
    PORT
      LAYER M4 ;
      RECT 201.739 30.084 201.811 30.108 ;
    END
  END w0_wd_in[208]
  PIN w0_wd_in[209]
    DIRECTION INPUT ;
    USE SIGNAL ;
    SHAPE ABUTMENT ;
    PORT
      LAYER M4 ;
      RECT 201.739 30.228 201.811 30.252 ;
    END
  END w0_wd_in[209]
  PIN w0_wd_in[210]
    DIRECTION INPUT ;
    USE SIGNAL ;
    SHAPE ABUTMENT ;
    PORT
      LAYER M4 ;
      RECT 201.739 30.372 201.811 30.396 ;
    END
  END w0_wd_in[210]
  PIN w0_wd_in[211]
    DIRECTION INPUT ;
    USE SIGNAL ;
    SHAPE ABUTMENT ;
    PORT
      LAYER M4 ;
      RECT 201.739 30.516 201.811 30.540 ;
    END
  END w0_wd_in[211]
  PIN w0_wd_in[212]
    DIRECTION INPUT ;
    USE SIGNAL ;
    SHAPE ABUTMENT ;
    PORT
      LAYER M4 ;
      RECT 201.739 30.660 201.811 30.684 ;
    END
  END w0_wd_in[212]
  PIN w0_wd_in[213]
    DIRECTION INPUT ;
    USE SIGNAL ;
    SHAPE ABUTMENT ;
    PORT
      LAYER M4 ;
      RECT 201.739 30.804 201.811 30.828 ;
    END
  END w0_wd_in[213]
  PIN w0_wd_in[214]
    DIRECTION INPUT ;
    USE SIGNAL ;
    SHAPE ABUTMENT ;
    PORT
      LAYER M4 ;
      RECT 201.739 30.948 201.811 30.972 ;
    END
  END w0_wd_in[214]
  PIN w0_wd_in[215]
    DIRECTION INPUT ;
    USE SIGNAL ;
    SHAPE ABUTMENT ;
    PORT
      LAYER M4 ;
      RECT 201.739 31.092 201.811 31.116 ;
    END
  END w0_wd_in[215]
  PIN w0_wd_in[216]
    DIRECTION INPUT ;
    USE SIGNAL ;
    SHAPE ABUTMENT ;
    PORT
      LAYER M4 ;
      RECT 201.739 31.236 201.811 31.260 ;
    END
  END w0_wd_in[216]
  PIN w0_wd_in[217]
    DIRECTION INPUT ;
    USE SIGNAL ;
    SHAPE ABUTMENT ;
    PORT
      LAYER M4 ;
      RECT 201.739 31.380 201.811 31.404 ;
    END
  END w0_wd_in[217]
  PIN w0_wd_in[218]
    DIRECTION INPUT ;
    USE SIGNAL ;
    SHAPE ABUTMENT ;
    PORT
      LAYER M4 ;
      RECT 201.739 31.524 201.811 31.548 ;
    END
  END w0_wd_in[218]
  PIN w0_wd_in[219]
    DIRECTION INPUT ;
    USE SIGNAL ;
    SHAPE ABUTMENT ;
    PORT
      LAYER M4 ;
      RECT 201.739 31.668 201.811 31.692 ;
    END
  END w0_wd_in[219]
  PIN w0_wd_in[220]
    DIRECTION INPUT ;
    USE SIGNAL ;
    SHAPE ABUTMENT ;
    PORT
      LAYER M4 ;
      RECT 201.739 31.812 201.811 31.836 ;
    END
  END w0_wd_in[220]
  PIN w0_wd_in[221]
    DIRECTION INPUT ;
    USE SIGNAL ;
    SHAPE ABUTMENT ;
    PORT
      LAYER M4 ;
      RECT 201.739 31.956 201.811 31.980 ;
    END
  END w0_wd_in[221]
  PIN w0_wd_in[222]
    DIRECTION INPUT ;
    USE SIGNAL ;
    SHAPE ABUTMENT ;
    PORT
      LAYER M4 ;
      RECT 201.739 32.100 201.811 32.124 ;
    END
  END w0_wd_in[222]
  PIN w0_wd_in[223]
    DIRECTION INPUT ;
    USE SIGNAL ;
    SHAPE ABUTMENT ;
    PORT
      LAYER M4 ;
      RECT 201.739 32.244 201.811 32.268 ;
    END
  END w0_wd_in[223]
  PIN w0_wd_in[224]
    DIRECTION INPUT ;
    USE SIGNAL ;
    SHAPE ABUTMENT ;
    PORT
      LAYER M4 ;
      RECT 201.739 32.388 201.811 32.412 ;
    END
  END w0_wd_in[224]
  PIN w0_wd_in[225]
    DIRECTION INPUT ;
    USE SIGNAL ;
    SHAPE ABUTMENT ;
    PORT
      LAYER M4 ;
      RECT 201.739 32.532 201.811 32.556 ;
    END
  END w0_wd_in[225]
  PIN w0_wd_in[226]
    DIRECTION INPUT ;
    USE SIGNAL ;
    SHAPE ABUTMENT ;
    PORT
      LAYER M4 ;
      RECT 201.739 32.676 201.811 32.700 ;
    END
  END w0_wd_in[226]
  PIN w0_wd_in[227]
    DIRECTION INPUT ;
    USE SIGNAL ;
    SHAPE ABUTMENT ;
    PORT
      LAYER M4 ;
      RECT 201.739 32.820 201.811 32.844 ;
    END
  END w0_wd_in[227]
  PIN w0_wd_in[228]
    DIRECTION INPUT ;
    USE SIGNAL ;
    SHAPE ABUTMENT ;
    PORT
      LAYER M4 ;
      RECT 201.739 32.964 201.811 32.988 ;
    END
  END w0_wd_in[228]
  PIN w0_wd_in[229]
    DIRECTION INPUT ;
    USE SIGNAL ;
    SHAPE ABUTMENT ;
    PORT
      LAYER M4 ;
      RECT 201.739 33.108 201.811 33.132 ;
    END
  END w0_wd_in[229]
  PIN w0_wd_in[230]
    DIRECTION INPUT ;
    USE SIGNAL ;
    SHAPE ABUTMENT ;
    PORT
      LAYER M4 ;
      RECT 201.739 33.252 201.811 33.276 ;
    END
  END w0_wd_in[230]
  PIN w0_wd_in[231]
    DIRECTION INPUT ;
    USE SIGNAL ;
    SHAPE ABUTMENT ;
    PORT
      LAYER M4 ;
      RECT 201.739 33.396 201.811 33.420 ;
    END
  END w0_wd_in[231]
  PIN w0_wd_in[232]
    DIRECTION INPUT ;
    USE SIGNAL ;
    SHAPE ABUTMENT ;
    PORT
      LAYER M4 ;
      RECT 201.739 33.540 201.811 33.564 ;
    END
  END w0_wd_in[232]
  PIN w0_wd_in[233]
    DIRECTION INPUT ;
    USE SIGNAL ;
    SHAPE ABUTMENT ;
    PORT
      LAYER M4 ;
      RECT 201.739 33.684 201.811 33.708 ;
    END
  END w0_wd_in[233]
  PIN w0_wd_in[234]
    DIRECTION INPUT ;
    USE SIGNAL ;
    SHAPE ABUTMENT ;
    PORT
      LAYER M4 ;
      RECT 201.739 33.828 201.811 33.852 ;
    END
  END w0_wd_in[234]
  PIN w0_wd_in[235]
    DIRECTION INPUT ;
    USE SIGNAL ;
    SHAPE ABUTMENT ;
    PORT
      LAYER M4 ;
      RECT 201.739 33.972 201.811 33.996 ;
    END
  END w0_wd_in[235]
  PIN w0_wd_in[236]
    DIRECTION INPUT ;
    USE SIGNAL ;
    SHAPE ABUTMENT ;
    PORT
      LAYER M4 ;
      RECT 201.739 34.116 201.811 34.140 ;
    END
  END w0_wd_in[236]
  PIN w0_wd_in[237]
    DIRECTION INPUT ;
    USE SIGNAL ;
    SHAPE ABUTMENT ;
    PORT
      LAYER M4 ;
      RECT 201.739 34.260 201.811 34.284 ;
    END
  END w0_wd_in[237]
  PIN w0_wd_in[238]
    DIRECTION INPUT ;
    USE SIGNAL ;
    SHAPE ABUTMENT ;
    PORT
      LAYER M4 ;
      RECT 201.739 34.404 201.811 34.428 ;
    END
  END w0_wd_in[238]
  PIN w0_wd_in[239]
    DIRECTION INPUT ;
    USE SIGNAL ;
    SHAPE ABUTMENT ;
    PORT
      LAYER M4 ;
      RECT 201.739 34.548 201.811 34.572 ;
    END
  END w0_wd_in[239]
  PIN w0_wd_in[240]
    DIRECTION INPUT ;
    USE SIGNAL ;
    SHAPE ABUTMENT ;
    PORT
      LAYER M4 ;
      RECT 201.739 34.692 201.811 34.716 ;
    END
  END w0_wd_in[240]
  PIN w0_wd_in[241]
    DIRECTION INPUT ;
    USE SIGNAL ;
    SHAPE ABUTMENT ;
    PORT
      LAYER M4 ;
      RECT 201.739 34.836 201.811 34.860 ;
    END
  END w0_wd_in[241]
  PIN w0_wd_in[242]
    DIRECTION INPUT ;
    USE SIGNAL ;
    SHAPE ABUTMENT ;
    PORT
      LAYER M4 ;
      RECT 201.739 34.980 201.811 35.004 ;
    END
  END w0_wd_in[242]
  PIN w0_wd_in[243]
    DIRECTION INPUT ;
    USE SIGNAL ;
    SHAPE ABUTMENT ;
    PORT
      LAYER M4 ;
      RECT 201.739 35.124 201.811 35.148 ;
    END
  END w0_wd_in[243]
  PIN w0_wd_in[244]
    DIRECTION INPUT ;
    USE SIGNAL ;
    SHAPE ABUTMENT ;
    PORT
      LAYER M4 ;
      RECT 201.739 35.268 201.811 35.292 ;
    END
  END w0_wd_in[244]
  PIN w0_wd_in[245]
    DIRECTION INPUT ;
    USE SIGNAL ;
    SHAPE ABUTMENT ;
    PORT
      LAYER M4 ;
      RECT 201.739 35.412 201.811 35.436 ;
    END
  END w0_wd_in[245]
  PIN w0_wd_in[246]
    DIRECTION INPUT ;
    USE SIGNAL ;
    SHAPE ABUTMENT ;
    PORT
      LAYER M4 ;
      RECT 201.739 35.556 201.811 35.580 ;
    END
  END w0_wd_in[246]
  PIN w0_wd_in[247]
    DIRECTION INPUT ;
    USE SIGNAL ;
    SHAPE ABUTMENT ;
    PORT
      LAYER M4 ;
      RECT 201.739 35.700 201.811 35.724 ;
    END
  END w0_wd_in[247]
  PIN w0_wd_in[248]
    DIRECTION INPUT ;
    USE SIGNAL ;
    SHAPE ABUTMENT ;
    PORT
      LAYER M4 ;
      RECT 201.739 35.844 201.811 35.868 ;
    END
  END w0_wd_in[248]
  PIN w0_wd_in[249]
    DIRECTION INPUT ;
    USE SIGNAL ;
    SHAPE ABUTMENT ;
    PORT
      LAYER M4 ;
      RECT 201.739 35.988 201.811 36.012 ;
    END
  END w0_wd_in[249]
  PIN w0_wd_in[250]
    DIRECTION INPUT ;
    USE SIGNAL ;
    SHAPE ABUTMENT ;
    PORT
      LAYER M4 ;
      RECT 201.739 36.132 201.811 36.156 ;
    END
  END w0_wd_in[250]
  PIN w0_wd_in[251]
    DIRECTION INPUT ;
    USE SIGNAL ;
    SHAPE ABUTMENT ;
    PORT
      LAYER M4 ;
      RECT 201.739 36.276 201.811 36.300 ;
    END
  END w0_wd_in[251]
  PIN w0_wd_in[252]
    DIRECTION INPUT ;
    USE SIGNAL ;
    SHAPE ABUTMENT ;
    PORT
      LAYER M4 ;
      RECT 201.739 36.420 201.811 36.444 ;
    END
  END w0_wd_in[252]
  PIN w0_wd_in[253]
    DIRECTION INPUT ;
    USE SIGNAL ;
    SHAPE ABUTMENT ;
    PORT
      LAYER M4 ;
      RECT 201.739 36.564 201.811 36.588 ;
    END
  END w0_wd_in[253]
  PIN w0_wd_in[254]
    DIRECTION INPUT ;
    USE SIGNAL ;
    SHAPE ABUTMENT ;
    PORT
      LAYER M4 ;
      RECT 201.739 36.708 201.811 36.732 ;
    END
  END w0_wd_in[254]
  PIN w0_wd_in[255]
    DIRECTION INPUT ;
    USE SIGNAL ;
    SHAPE ABUTMENT ;
    PORT
      LAYER M4 ;
      RECT 201.739 36.852 201.811 36.876 ;
    END
  END w0_wd_in[255]
  PIN w0_wd_in[256]
    DIRECTION INPUT ;
    USE SIGNAL ;
    SHAPE ABUTMENT ;
    PORT
      LAYER M4 ;
      RECT 201.739 36.996 201.811 37.020 ;
    END
  END w0_wd_in[256]
  PIN w0_wd_in[257]
    DIRECTION INPUT ;
    USE SIGNAL ;
    SHAPE ABUTMENT ;
    PORT
      LAYER M4 ;
      RECT 201.739 37.140 201.811 37.164 ;
    END
  END w0_wd_in[257]
  PIN w0_wd_in[258]
    DIRECTION INPUT ;
    USE SIGNAL ;
    SHAPE ABUTMENT ;
    PORT
      LAYER M4 ;
      RECT 201.739 37.284 201.811 37.308 ;
    END
  END w0_wd_in[258]
  PIN w0_wd_in[259]
    DIRECTION INPUT ;
    USE SIGNAL ;
    SHAPE ABUTMENT ;
    PORT
      LAYER M4 ;
      RECT 201.739 37.428 201.811 37.452 ;
    END
  END w0_wd_in[259]
  PIN w0_wd_in[260]
    DIRECTION INPUT ;
    USE SIGNAL ;
    SHAPE ABUTMENT ;
    PORT
      LAYER M4 ;
      RECT 201.739 37.572 201.811 37.596 ;
    END
  END w0_wd_in[260]
  PIN w0_wd_in[261]
    DIRECTION INPUT ;
    USE SIGNAL ;
    SHAPE ABUTMENT ;
    PORT
      LAYER M4 ;
      RECT 201.739 37.716 201.811 37.740 ;
    END
  END w0_wd_in[261]
  PIN w0_wd_in[262]
    DIRECTION INPUT ;
    USE SIGNAL ;
    SHAPE ABUTMENT ;
    PORT
      LAYER M4 ;
      RECT 201.739 37.860 201.811 37.884 ;
    END
  END w0_wd_in[262]
  PIN w0_wd_in[263]
    DIRECTION INPUT ;
    USE SIGNAL ;
    SHAPE ABUTMENT ;
    PORT
      LAYER M4 ;
      RECT 201.739 38.004 201.811 38.028 ;
    END
  END w0_wd_in[263]
  PIN w0_wd_in[264]
    DIRECTION INPUT ;
    USE SIGNAL ;
    SHAPE ABUTMENT ;
    PORT
      LAYER M4 ;
      RECT 201.739 38.148 201.811 38.172 ;
    END
  END w0_wd_in[264]
  PIN w0_wd_in[265]
    DIRECTION INPUT ;
    USE SIGNAL ;
    SHAPE ABUTMENT ;
    PORT
      LAYER M4 ;
      RECT 201.739 38.292 201.811 38.316 ;
    END
  END w0_wd_in[265]
  PIN w0_wd_in[266]
    DIRECTION INPUT ;
    USE SIGNAL ;
    SHAPE ABUTMENT ;
    PORT
      LAYER M4 ;
      RECT 201.739 38.436 201.811 38.460 ;
    END
  END w0_wd_in[266]
  PIN w0_wd_in[267]
    DIRECTION INPUT ;
    USE SIGNAL ;
    SHAPE ABUTMENT ;
    PORT
      LAYER M4 ;
      RECT 201.739 38.580 201.811 38.604 ;
    END
  END w0_wd_in[267]
  PIN w0_wd_in[268]
    DIRECTION INPUT ;
    USE SIGNAL ;
    SHAPE ABUTMENT ;
    PORT
      LAYER M4 ;
      RECT 201.739 38.724 201.811 38.748 ;
    END
  END w0_wd_in[268]
  PIN w0_wd_in[269]
    DIRECTION INPUT ;
    USE SIGNAL ;
    SHAPE ABUTMENT ;
    PORT
      LAYER M4 ;
      RECT 201.739 38.868 201.811 38.892 ;
    END
  END w0_wd_in[269]
  PIN w0_wd_in[270]
    DIRECTION INPUT ;
    USE SIGNAL ;
    SHAPE ABUTMENT ;
    PORT
      LAYER M4 ;
      RECT 201.739 39.012 201.811 39.036 ;
    END
  END w0_wd_in[270]
  PIN w0_wd_in[271]
    DIRECTION INPUT ;
    USE SIGNAL ;
    SHAPE ABUTMENT ;
    PORT
      LAYER M4 ;
      RECT 201.739 39.156 201.811 39.180 ;
    END
  END w0_wd_in[271]
  PIN w0_wd_in[272]
    DIRECTION INPUT ;
    USE SIGNAL ;
    SHAPE ABUTMENT ;
    PORT
      LAYER M4 ;
      RECT 201.739 39.300 201.811 39.324 ;
    END
  END w0_wd_in[272]
  PIN w0_wd_in[273]
    DIRECTION INPUT ;
    USE SIGNAL ;
    SHAPE ABUTMENT ;
    PORT
      LAYER M4 ;
      RECT 201.739 39.444 201.811 39.468 ;
    END
  END w0_wd_in[273]
  PIN w0_wd_in[274]
    DIRECTION INPUT ;
    USE SIGNAL ;
    SHAPE ABUTMENT ;
    PORT
      LAYER M4 ;
      RECT 201.739 39.588 201.811 39.612 ;
    END
  END w0_wd_in[274]
  PIN w0_wd_in[275]
    DIRECTION INPUT ;
    USE SIGNAL ;
    SHAPE ABUTMENT ;
    PORT
      LAYER M4 ;
      RECT 201.739 39.732 201.811 39.756 ;
    END
  END w0_wd_in[275]
  PIN w0_wd_in[276]
    DIRECTION INPUT ;
    USE SIGNAL ;
    SHAPE ABUTMENT ;
    PORT
      LAYER M4 ;
      RECT 201.739 39.876 201.811 39.900 ;
    END
  END w0_wd_in[276]
  PIN w0_wd_in[277]
    DIRECTION INPUT ;
    USE SIGNAL ;
    SHAPE ABUTMENT ;
    PORT
      LAYER M4 ;
      RECT 201.739 40.020 201.811 40.044 ;
    END
  END w0_wd_in[277]
  PIN w0_wd_in[278]
    DIRECTION INPUT ;
    USE SIGNAL ;
    SHAPE ABUTMENT ;
    PORT
      LAYER M4 ;
      RECT 201.739 40.164 201.811 40.188 ;
    END
  END w0_wd_in[278]
  PIN w0_wd_in[279]
    DIRECTION INPUT ;
    USE SIGNAL ;
    SHAPE ABUTMENT ;
    PORT
      LAYER M4 ;
      RECT 201.739 40.308 201.811 40.332 ;
    END
  END w0_wd_in[279]
  PIN w0_wd_in[280]
    DIRECTION INPUT ;
    USE SIGNAL ;
    SHAPE ABUTMENT ;
    PORT
      LAYER M4 ;
      RECT 201.739 40.452 201.811 40.476 ;
    END
  END w0_wd_in[280]
  PIN w0_wd_in[281]
    DIRECTION INPUT ;
    USE SIGNAL ;
    SHAPE ABUTMENT ;
    PORT
      LAYER M4 ;
      RECT 201.739 40.596 201.811 40.620 ;
    END
  END w0_wd_in[281]
  PIN w0_wd_in[282]
    DIRECTION INPUT ;
    USE SIGNAL ;
    SHAPE ABUTMENT ;
    PORT
      LAYER M4 ;
      RECT 201.739 40.740 201.811 40.764 ;
    END
  END w0_wd_in[282]
  PIN w0_wd_in[283]
    DIRECTION INPUT ;
    USE SIGNAL ;
    SHAPE ABUTMENT ;
    PORT
      LAYER M4 ;
      RECT 201.739 40.884 201.811 40.908 ;
    END
  END w0_wd_in[283]
  PIN w0_wd_in[284]
    DIRECTION INPUT ;
    USE SIGNAL ;
    SHAPE ABUTMENT ;
    PORT
      LAYER M4 ;
      RECT 201.739 41.028 201.811 41.052 ;
    END
  END w0_wd_in[284]
  PIN w0_wd_in[285]
    DIRECTION INPUT ;
    USE SIGNAL ;
    SHAPE ABUTMENT ;
    PORT
      LAYER M4 ;
      RECT 201.739 41.172 201.811 41.196 ;
    END
  END w0_wd_in[285]
  PIN w0_wd_in[286]
    DIRECTION INPUT ;
    USE SIGNAL ;
    SHAPE ABUTMENT ;
    PORT
      LAYER M4 ;
      RECT 201.739 41.316 201.811 41.340 ;
    END
  END w0_wd_in[286]
  PIN w0_wd_in[287]
    DIRECTION INPUT ;
    USE SIGNAL ;
    SHAPE ABUTMENT ;
    PORT
      LAYER M4 ;
      RECT 201.739 41.460 201.811 41.484 ;
    END
  END w0_wd_in[287]
  PIN w0_wd_in[288]
    DIRECTION INPUT ;
    USE SIGNAL ;
    SHAPE ABUTMENT ;
    PORT
      LAYER M4 ;
      RECT 201.739 41.604 201.811 41.628 ;
    END
  END w0_wd_in[288]
  PIN w0_wd_in[289]
    DIRECTION INPUT ;
    USE SIGNAL ;
    SHAPE ABUTMENT ;
    PORT
      LAYER M4 ;
      RECT 201.739 41.748 201.811 41.772 ;
    END
  END w0_wd_in[289]
  PIN w0_wd_in[290]
    DIRECTION INPUT ;
    USE SIGNAL ;
    SHAPE ABUTMENT ;
    PORT
      LAYER M4 ;
      RECT 201.739 41.892 201.811 41.916 ;
    END
  END w0_wd_in[290]
  PIN w0_wd_in[291]
    DIRECTION INPUT ;
    USE SIGNAL ;
    SHAPE ABUTMENT ;
    PORT
      LAYER M4 ;
      RECT 201.739 42.036 201.811 42.060 ;
    END
  END w0_wd_in[291]
  PIN w0_wd_in[292]
    DIRECTION INPUT ;
    USE SIGNAL ;
    SHAPE ABUTMENT ;
    PORT
      LAYER M4 ;
      RECT 201.739 42.180 201.811 42.204 ;
    END
  END w0_wd_in[292]
  PIN w0_wd_in[293]
    DIRECTION INPUT ;
    USE SIGNAL ;
    SHAPE ABUTMENT ;
    PORT
      LAYER M4 ;
      RECT 201.739 42.324 201.811 42.348 ;
    END
  END w0_wd_in[293]
  PIN w0_wd_in[294]
    DIRECTION INPUT ;
    USE SIGNAL ;
    SHAPE ABUTMENT ;
    PORT
      LAYER M4 ;
      RECT 201.739 42.468 201.811 42.492 ;
    END
  END w0_wd_in[294]
  PIN w0_wd_in[295]
    DIRECTION INPUT ;
    USE SIGNAL ;
    SHAPE ABUTMENT ;
    PORT
      LAYER M4 ;
      RECT 201.739 42.612 201.811 42.636 ;
    END
  END w0_wd_in[295]
  PIN w0_wd_in[296]
    DIRECTION INPUT ;
    USE SIGNAL ;
    SHAPE ABUTMENT ;
    PORT
      LAYER M4 ;
      RECT 201.739 42.756 201.811 42.780 ;
    END
  END w0_wd_in[296]
  PIN w0_wd_in[297]
    DIRECTION INPUT ;
    USE SIGNAL ;
    SHAPE ABUTMENT ;
    PORT
      LAYER M4 ;
      RECT 201.739 42.900 201.811 42.924 ;
    END
  END w0_wd_in[297]
  PIN w0_wd_in[298]
    DIRECTION INPUT ;
    USE SIGNAL ;
    SHAPE ABUTMENT ;
    PORT
      LAYER M4 ;
      RECT 201.739 43.044 201.811 43.068 ;
    END
  END w0_wd_in[298]
  PIN w0_wd_in[299]
    DIRECTION INPUT ;
    USE SIGNAL ;
    SHAPE ABUTMENT ;
    PORT
      LAYER M4 ;
      RECT 201.739 43.188 201.811 43.212 ;
    END
  END w0_wd_in[299]
  PIN w0_wd_in[300]
    DIRECTION INPUT ;
    USE SIGNAL ;
    SHAPE ABUTMENT ;
    PORT
      LAYER M4 ;
      RECT 201.739 43.332 201.811 43.356 ;
    END
  END w0_wd_in[300]
  PIN w0_wd_in[301]
    DIRECTION INPUT ;
    USE SIGNAL ;
    SHAPE ABUTMENT ;
    PORT
      LAYER M4 ;
      RECT 201.739 43.476 201.811 43.500 ;
    END
  END w0_wd_in[301]
  PIN w0_wd_in[302]
    DIRECTION INPUT ;
    USE SIGNAL ;
    SHAPE ABUTMENT ;
    PORT
      LAYER M4 ;
      RECT 201.739 43.620 201.811 43.644 ;
    END
  END w0_wd_in[302]
  PIN w0_wd_in[303]
    DIRECTION INPUT ;
    USE SIGNAL ;
    SHAPE ABUTMENT ;
    PORT
      LAYER M4 ;
      RECT 201.739 43.764 201.811 43.788 ;
    END
  END w0_wd_in[303]
  PIN w0_wd_in[304]
    DIRECTION INPUT ;
    USE SIGNAL ;
    SHAPE ABUTMENT ;
    PORT
      LAYER M4 ;
      RECT 201.739 43.908 201.811 43.932 ;
    END
  END w0_wd_in[304]
  PIN w0_wd_in[305]
    DIRECTION INPUT ;
    USE SIGNAL ;
    SHAPE ABUTMENT ;
    PORT
      LAYER M4 ;
      RECT 201.739 44.052 201.811 44.076 ;
    END
  END w0_wd_in[305]
  PIN w0_wd_in[306]
    DIRECTION INPUT ;
    USE SIGNAL ;
    SHAPE ABUTMENT ;
    PORT
      LAYER M4 ;
      RECT 201.739 44.196 201.811 44.220 ;
    END
  END w0_wd_in[306]
  PIN w0_wd_in[307]
    DIRECTION INPUT ;
    USE SIGNAL ;
    SHAPE ABUTMENT ;
    PORT
      LAYER M4 ;
      RECT 201.739 44.340 201.811 44.364 ;
    END
  END w0_wd_in[307]
  PIN w0_wd_in[308]
    DIRECTION INPUT ;
    USE SIGNAL ;
    SHAPE ABUTMENT ;
    PORT
      LAYER M4 ;
      RECT 201.739 44.484 201.811 44.508 ;
    END
  END w0_wd_in[308]
  PIN w0_wd_in[309]
    DIRECTION INPUT ;
    USE SIGNAL ;
    SHAPE ABUTMENT ;
    PORT
      LAYER M4 ;
      RECT 201.739 44.628 201.811 44.652 ;
    END
  END w0_wd_in[309]
  PIN w0_wd_in[310]
    DIRECTION INPUT ;
    USE SIGNAL ;
    SHAPE ABUTMENT ;
    PORT
      LAYER M4 ;
      RECT 201.739 44.772 201.811 44.796 ;
    END
  END w0_wd_in[310]
  PIN w0_wd_in[311]
    DIRECTION INPUT ;
    USE SIGNAL ;
    SHAPE ABUTMENT ;
    PORT
      LAYER M4 ;
      RECT 201.739 44.916 201.811 44.940 ;
    END
  END w0_wd_in[311]
  PIN w0_wd_in[312]
    DIRECTION INPUT ;
    USE SIGNAL ;
    SHAPE ABUTMENT ;
    PORT
      LAYER M4 ;
      RECT 201.739 45.060 201.811 45.084 ;
    END
  END w0_wd_in[312]
  PIN w0_wd_in[313]
    DIRECTION INPUT ;
    USE SIGNAL ;
    SHAPE ABUTMENT ;
    PORT
      LAYER M4 ;
      RECT 201.739 45.204 201.811 45.228 ;
    END
  END w0_wd_in[313]
  PIN w0_wd_in[314]
    DIRECTION INPUT ;
    USE SIGNAL ;
    SHAPE ABUTMENT ;
    PORT
      LAYER M4 ;
      RECT 201.739 45.348 201.811 45.372 ;
    END
  END w0_wd_in[314]
  PIN w0_wd_in[315]
    DIRECTION INPUT ;
    USE SIGNAL ;
    SHAPE ABUTMENT ;
    PORT
      LAYER M4 ;
      RECT 201.739 45.492 201.811 45.516 ;
    END
  END w0_wd_in[315]
  PIN w0_wd_in[316]
    DIRECTION INPUT ;
    USE SIGNAL ;
    SHAPE ABUTMENT ;
    PORT
      LAYER M4 ;
      RECT 201.739 45.636 201.811 45.660 ;
    END
  END w0_wd_in[316]
  PIN w0_wd_in[317]
    DIRECTION OUTPUT ;
    USE SIGNAL ;
    SHAPE ABUTMENT ;
    PORT
      LAYER M3 ;
      RECT 0.207 0.000 0.225 0.054 ;
    END
  END w0_wd_in[317]
  PIN w0_wd_in[318]
    DIRECTION OUTPUT ;
    USE SIGNAL ;
    SHAPE ABUTMENT ;
    PORT
      LAYER M3 ;
      RECT 0.495 0.000 0.513 0.054 ;
    END
  END w0_wd_in[318]
  PIN w0_wd_in[319]
    DIRECTION OUTPUT ;
    USE SIGNAL ;
    SHAPE ABUTMENT ;
    PORT
      LAYER M3 ;
      RECT 0.783 0.000 0.801 0.054 ;
    END
  END w0_wd_in[319]
  PIN w0_wd_in[320]
    DIRECTION OUTPUT ;
    USE SIGNAL ;
    SHAPE ABUTMENT ;
    PORT
      LAYER M3 ;
      RECT 1.071 0.000 1.089 0.054 ;
    END
  END w0_wd_in[320]
  PIN w0_wd_in[321]
    DIRECTION OUTPUT ;
    USE SIGNAL ;
    SHAPE ABUTMENT ;
    PORT
      LAYER M3 ;
      RECT 1.359 0.000 1.377 0.054 ;
    END
  END w0_wd_in[321]
  PIN w0_wd_in[322]
    DIRECTION OUTPUT ;
    USE SIGNAL ;
    SHAPE ABUTMENT ;
    PORT
      LAYER M3 ;
      RECT 1.647 0.000 1.665 0.054 ;
    END
  END w0_wd_in[322]
  PIN w0_wd_in[323]
    DIRECTION OUTPUT ;
    USE SIGNAL ;
    SHAPE ABUTMENT ;
    PORT
      LAYER M3 ;
      RECT 1.935 0.000 1.953 0.054 ;
    END
  END w0_wd_in[323]
  PIN w0_wd_in[324]
    DIRECTION OUTPUT ;
    USE SIGNAL ;
    SHAPE ABUTMENT ;
    PORT
      LAYER M3 ;
      RECT 2.223 0.000 2.241 0.054 ;
    END
  END w0_wd_in[324]
  PIN w0_wd_in[325]
    DIRECTION OUTPUT ;
    USE SIGNAL ;
    SHAPE ABUTMENT ;
    PORT
      LAYER M3 ;
      RECT 2.511 0.000 2.529 0.054 ;
    END
  END w0_wd_in[325]
  PIN w0_wd_in[326]
    DIRECTION OUTPUT ;
    USE SIGNAL ;
    SHAPE ABUTMENT ;
    PORT
      LAYER M3 ;
      RECT 2.799 0.000 2.817 0.054 ;
    END
  END w0_wd_in[326]
  PIN w0_wd_in[327]
    DIRECTION OUTPUT ;
    USE SIGNAL ;
    SHAPE ABUTMENT ;
    PORT
      LAYER M3 ;
      RECT 3.087 0.000 3.105 0.054 ;
    END
  END w0_wd_in[327]
  PIN w0_wd_in[328]
    DIRECTION OUTPUT ;
    USE SIGNAL ;
    SHAPE ABUTMENT ;
    PORT
      LAYER M3 ;
      RECT 3.375 0.000 3.393 0.054 ;
    END
  END w0_wd_in[328]
  PIN w0_wd_in[329]
    DIRECTION OUTPUT ;
    USE SIGNAL ;
    SHAPE ABUTMENT ;
    PORT
      LAYER M3 ;
      RECT 3.663 0.000 3.681 0.054 ;
    END
  END w0_wd_in[329]
  PIN w0_wd_in[330]
    DIRECTION OUTPUT ;
    USE SIGNAL ;
    SHAPE ABUTMENT ;
    PORT
      LAYER M3 ;
      RECT 3.951 0.000 3.969 0.054 ;
    END
  END w0_wd_in[330]
  PIN w0_wd_in[331]
    DIRECTION OUTPUT ;
    USE SIGNAL ;
    SHAPE ABUTMENT ;
    PORT
      LAYER M3 ;
      RECT 4.239 0.000 4.257 0.054 ;
    END
  END w0_wd_in[331]
  PIN w0_wd_in[332]
    DIRECTION OUTPUT ;
    USE SIGNAL ;
    SHAPE ABUTMENT ;
    PORT
      LAYER M3 ;
      RECT 4.527 0.000 4.545 0.054 ;
    END
  END w0_wd_in[332]
  PIN w0_wd_in[333]
    DIRECTION OUTPUT ;
    USE SIGNAL ;
    SHAPE ABUTMENT ;
    PORT
      LAYER M3 ;
      RECT 4.815 0.000 4.833 0.054 ;
    END
  END w0_wd_in[333]
  PIN w0_wd_in[334]
    DIRECTION OUTPUT ;
    USE SIGNAL ;
    SHAPE ABUTMENT ;
    PORT
      LAYER M3 ;
      RECT 5.103 0.000 5.121 0.054 ;
    END
  END w0_wd_in[334]
  PIN w0_wd_in[335]
    DIRECTION OUTPUT ;
    USE SIGNAL ;
    SHAPE ABUTMENT ;
    PORT
      LAYER M3 ;
      RECT 5.391 0.000 5.409 0.054 ;
    END
  END w0_wd_in[335]
  PIN w0_wd_in[336]
    DIRECTION OUTPUT ;
    USE SIGNAL ;
    SHAPE ABUTMENT ;
    PORT
      LAYER M3 ;
      RECT 5.679 0.000 5.697 0.054 ;
    END
  END w0_wd_in[336]
  PIN w0_wd_in[337]
    DIRECTION OUTPUT ;
    USE SIGNAL ;
    SHAPE ABUTMENT ;
    PORT
      LAYER M3 ;
      RECT 5.967 0.000 5.985 0.054 ;
    END
  END w0_wd_in[337]
  PIN w0_wd_in[338]
    DIRECTION OUTPUT ;
    USE SIGNAL ;
    SHAPE ABUTMENT ;
    PORT
      LAYER M3 ;
      RECT 6.255 0.000 6.273 0.054 ;
    END
  END w0_wd_in[338]
  PIN w0_wd_in[339]
    DIRECTION OUTPUT ;
    USE SIGNAL ;
    SHAPE ABUTMENT ;
    PORT
      LAYER M3 ;
      RECT 6.543 0.000 6.561 0.054 ;
    END
  END w0_wd_in[339]
  PIN w0_wd_in[340]
    DIRECTION OUTPUT ;
    USE SIGNAL ;
    SHAPE ABUTMENT ;
    PORT
      LAYER M3 ;
      RECT 6.831 0.000 6.849 0.054 ;
    END
  END w0_wd_in[340]
  PIN w0_wd_in[341]
    DIRECTION OUTPUT ;
    USE SIGNAL ;
    SHAPE ABUTMENT ;
    PORT
      LAYER M3 ;
      RECT 7.119 0.000 7.137 0.054 ;
    END
  END w0_wd_in[341]
  PIN w0_wd_in[342]
    DIRECTION OUTPUT ;
    USE SIGNAL ;
    SHAPE ABUTMENT ;
    PORT
      LAYER M3 ;
      RECT 7.407 0.000 7.425 0.054 ;
    END
  END w0_wd_in[342]
  PIN w0_wd_in[343]
    DIRECTION OUTPUT ;
    USE SIGNAL ;
    SHAPE ABUTMENT ;
    PORT
      LAYER M3 ;
      RECT 7.695 0.000 7.713 0.054 ;
    END
  END w0_wd_in[343]
  PIN w0_wd_in[344]
    DIRECTION OUTPUT ;
    USE SIGNAL ;
    SHAPE ABUTMENT ;
    PORT
      LAYER M3 ;
      RECT 7.983 0.000 8.001 0.054 ;
    END
  END w0_wd_in[344]
  PIN w0_wd_in[345]
    DIRECTION OUTPUT ;
    USE SIGNAL ;
    SHAPE ABUTMENT ;
    PORT
      LAYER M3 ;
      RECT 8.271 0.000 8.289 0.054 ;
    END
  END w0_wd_in[345]
  PIN w0_wd_in[346]
    DIRECTION OUTPUT ;
    USE SIGNAL ;
    SHAPE ABUTMENT ;
    PORT
      LAYER M3 ;
      RECT 8.559 0.000 8.577 0.054 ;
    END
  END w0_wd_in[346]
  PIN w0_wd_in[347]
    DIRECTION OUTPUT ;
    USE SIGNAL ;
    SHAPE ABUTMENT ;
    PORT
      LAYER M3 ;
      RECT 8.847 0.000 8.865 0.054 ;
    END
  END w0_wd_in[347]
  PIN w0_wd_in[348]
    DIRECTION OUTPUT ;
    USE SIGNAL ;
    SHAPE ABUTMENT ;
    PORT
      LAYER M3 ;
      RECT 9.135 0.000 9.153 0.054 ;
    END
  END w0_wd_in[348]
  PIN w0_wd_in[349]
    DIRECTION OUTPUT ;
    USE SIGNAL ;
    SHAPE ABUTMENT ;
    PORT
      LAYER M3 ;
      RECT 9.423 0.000 9.441 0.054 ;
    END
  END w0_wd_in[349]
  PIN w0_wd_in[350]
    DIRECTION OUTPUT ;
    USE SIGNAL ;
    SHAPE ABUTMENT ;
    PORT
      LAYER M3 ;
      RECT 9.711 0.000 9.729 0.054 ;
    END
  END w0_wd_in[350]
  PIN w0_wd_in[351]
    DIRECTION OUTPUT ;
    USE SIGNAL ;
    SHAPE ABUTMENT ;
    PORT
      LAYER M3 ;
      RECT 9.999 0.000 10.017 0.054 ;
    END
  END w0_wd_in[351]
  PIN w0_wd_in[352]
    DIRECTION OUTPUT ;
    USE SIGNAL ;
    SHAPE ABUTMENT ;
    PORT
      LAYER M3 ;
      RECT 10.287 0.000 10.305 0.054 ;
    END
  END w0_wd_in[352]
  PIN w0_wd_in[353]
    DIRECTION OUTPUT ;
    USE SIGNAL ;
    SHAPE ABUTMENT ;
    PORT
      LAYER M3 ;
      RECT 10.575 0.000 10.593 0.054 ;
    END
  END w0_wd_in[353]
  PIN w0_wd_in[354]
    DIRECTION OUTPUT ;
    USE SIGNAL ;
    SHAPE ABUTMENT ;
    PORT
      LAYER M3 ;
      RECT 10.863 0.000 10.881 0.054 ;
    END
  END w0_wd_in[354]
  PIN w0_wd_in[355]
    DIRECTION OUTPUT ;
    USE SIGNAL ;
    SHAPE ABUTMENT ;
    PORT
      LAYER M3 ;
      RECT 11.151 0.000 11.169 0.054 ;
    END
  END w0_wd_in[355]
  PIN w0_wd_in[356]
    DIRECTION OUTPUT ;
    USE SIGNAL ;
    SHAPE ABUTMENT ;
    PORT
      LAYER M3 ;
      RECT 11.439 0.000 11.457 0.054 ;
    END
  END w0_wd_in[356]
  PIN w0_wd_in[357]
    DIRECTION OUTPUT ;
    USE SIGNAL ;
    SHAPE ABUTMENT ;
    PORT
      LAYER M3 ;
      RECT 11.727 0.000 11.745 0.054 ;
    END
  END w0_wd_in[357]
  PIN w0_wd_in[358]
    DIRECTION OUTPUT ;
    USE SIGNAL ;
    SHAPE ABUTMENT ;
    PORT
      LAYER M3 ;
      RECT 12.015 0.000 12.033 0.054 ;
    END
  END w0_wd_in[358]
  PIN w0_wd_in[359]
    DIRECTION OUTPUT ;
    USE SIGNAL ;
    SHAPE ABUTMENT ;
    PORT
      LAYER M3 ;
      RECT 12.303 0.000 12.321 0.054 ;
    END
  END w0_wd_in[359]
  PIN w0_wd_in[360]
    DIRECTION OUTPUT ;
    USE SIGNAL ;
    SHAPE ABUTMENT ;
    PORT
      LAYER M3 ;
      RECT 12.591 0.000 12.609 0.054 ;
    END
  END w0_wd_in[360]
  PIN w0_wd_in[361]
    DIRECTION OUTPUT ;
    USE SIGNAL ;
    SHAPE ABUTMENT ;
    PORT
      LAYER M3 ;
      RECT 12.879 0.000 12.897 0.054 ;
    END
  END w0_wd_in[361]
  PIN w0_wd_in[362]
    DIRECTION OUTPUT ;
    USE SIGNAL ;
    SHAPE ABUTMENT ;
    PORT
      LAYER M3 ;
      RECT 13.167 0.000 13.185 0.054 ;
    END
  END w0_wd_in[362]
  PIN w0_wd_in[363]
    DIRECTION OUTPUT ;
    USE SIGNAL ;
    SHAPE ABUTMENT ;
    PORT
      LAYER M3 ;
      RECT 13.455 0.000 13.473 0.054 ;
    END
  END w0_wd_in[363]
  PIN w0_wd_in[364]
    DIRECTION OUTPUT ;
    USE SIGNAL ;
    SHAPE ABUTMENT ;
    PORT
      LAYER M3 ;
      RECT 13.743 0.000 13.761 0.054 ;
    END
  END w0_wd_in[364]
  PIN w0_wd_in[365]
    DIRECTION OUTPUT ;
    USE SIGNAL ;
    SHAPE ABUTMENT ;
    PORT
      LAYER M3 ;
      RECT 14.031 0.000 14.049 0.054 ;
    END
  END w0_wd_in[365]
  PIN w0_wd_in[366]
    DIRECTION OUTPUT ;
    USE SIGNAL ;
    SHAPE ABUTMENT ;
    PORT
      LAYER M3 ;
      RECT 14.319 0.000 14.337 0.054 ;
    END
  END w0_wd_in[366]
  PIN w0_wd_in[367]
    DIRECTION OUTPUT ;
    USE SIGNAL ;
    SHAPE ABUTMENT ;
    PORT
      LAYER M3 ;
      RECT 14.607 0.000 14.625 0.054 ;
    END
  END w0_wd_in[367]
  PIN w0_wd_in[368]
    DIRECTION OUTPUT ;
    USE SIGNAL ;
    SHAPE ABUTMENT ;
    PORT
      LAYER M3 ;
      RECT 14.895 0.000 14.913 0.054 ;
    END
  END w0_wd_in[368]
  PIN w0_wd_in[369]
    DIRECTION OUTPUT ;
    USE SIGNAL ;
    SHAPE ABUTMENT ;
    PORT
      LAYER M3 ;
      RECT 15.183 0.000 15.201 0.054 ;
    END
  END w0_wd_in[369]
  PIN w0_wd_in[370]
    DIRECTION OUTPUT ;
    USE SIGNAL ;
    SHAPE ABUTMENT ;
    PORT
      LAYER M3 ;
      RECT 15.471 0.000 15.489 0.054 ;
    END
  END w0_wd_in[370]
  PIN w0_wd_in[371]
    DIRECTION OUTPUT ;
    USE SIGNAL ;
    SHAPE ABUTMENT ;
    PORT
      LAYER M3 ;
      RECT 15.759 0.000 15.777 0.054 ;
    END
  END w0_wd_in[371]
  PIN w0_wd_in[372]
    DIRECTION OUTPUT ;
    USE SIGNAL ;
    SHAPE ABUTMENT ;
    PORT
      LAYER M3 ;
      RECT 16.047 0.000 16.065 0.054 ;
    END
  END w0_wd_in[372]
  PIN w0_wd_in[373]
    DIRECTION OUTPUT ;
    USE SIGNAL ;
    SHAPE ABUTMENT ;
    PORT
      LAYER M3 ;
      RECT 16.335 0.000 16.353 0.054 ;
    END
  END w0_wd_in[373]
  PIN w0_wd_in[374]
    DIRECTION OUTPUT ;
    USE SIGNAL ;
    SHAPE ABUTMENT ;
    PORT
      LAYER M3 ;
      RECT 16.623 0.000 16.641 0.054 ;
    END
  END w0_wd_in[374]
  PIN w0_wd_in[375]
    DIRECTION OUTPUT ;
    USE SIGNAL ;
    SHAPE ABUTMENT ;
    PORT
      LAYER M3 ;
      RECT 16.911 0.000 16.929 0.054 ;
    END
  END w0_wd_in[375]
  PIN w0_wd_in[376]
    DIRECTION OUTPUT ;
    USE SIGNAL ;
    SHAPE ABUTMENT ;
    PORT
      LAYER M3 ;
      RECT 17.199 0.000 17.217 0.054 ;
    END
  END w0_wd_in[376]
  PIN w0_wd_in[377]
    DIRECTION OUTPUT ;
    USE SIGNAL ;
    SHAPE ABUTMENT ;
    PORT
      LAYER M3 ;
      RECT 17.487 0.000 17.505 0.054 ;
    END
  END w0_wd_in[377]
  PIN w0_wd_in[378]
    DIRECTION OUTPUT ;
    USE SIGNAL ;
    SHAPE ABUTMENT ;
    PORT
      LAYER M3 ;
      RECT 17.775 0.000 17.793 0.054 ;
    END
  END w0_wd_in[378]
  PIN w0_wd_in[379]
    DIRECTION OUTPUT ;
    USE SIGNAL ;
    SHAPE ABUTMENT ;
    PORT
      LAYER M3 ;
      RECT 18.063 0.000 18.081 0.054 ;
    END
  END w0_wd_in[379]
  PIN w0_wd_in[380]
    DIRECTION OUTPUT ;
    USE SIGNAL ;
    SHAPE ABUTMENT ;
    PORT
      LAYER M3 ;
      RECT 18.351 0.000 18.369 0.054 ;
    END
  END w0_wd_in[380]
  PIN w0_wd_in[381]
    DIRECTION OUTPUT ;
    USE SIGNAL ;
    SHAPE ABUTMENT ;
    PORT
      LAYER M3 ;
      RECT 18.639 0.000 18.657 0.054 ;
    END
  END w0_wd_in[381]
  PIN w0_wd_in[382]
    DIRECTION OUTPUT ;
    USE SIGNAL ;
    SHAPE ABUTMENT ;
    PORT
      LAYER M3 ;
      RECT 18.927 0.000 18.945 0.054 ;
    END
  END w0_wd_in[382]
  PIN w0_wd_in[383]
    DIRECTION OUTPUT ;
    USE SIGNAL ;
    SHAPE ABUTMENT ;
    PORT
      LAYER M3 ;
      RECT 19.215 0.000 19.233 0.054 ;
    END
  END w0_wd_in[383]
  PIN w0_wd_in[384]
    DIRECTION OUTPUT ;
    USE SIGNAL ;
    SHAPE ABUTMENT ;
    PORT
      LAYER M3 ;
      RECT 19.503 0.000 19.521 0.054 ;
    END
  END w0_wd_in[384]
  PIN w0_wd_in[385]
    DIRECTION OUTPUT ;
    USE SIGNAL ;
    SHAPE ABUTMENT ;
    PORT
      LAYER M3 ;
      RECT 19.791 0.000 19.809 0.054 ;
    END
  END w0_wd_in[385]
  PIN w0_wd_in[386]
    DIRECTION OUTPUT ;
    USE SIGNAL ;
    SHAPE ABUTMENT ;
    PORT
      LAYER M3 ;
      RECT 20.079 0.000 20.097 0.054 ;
    END
  END w0_wd_in[386]
  PIN w0_wd_in[387]
    DIRECTION OUTPUT ;
    USE SIGNAL ;
    SHAPE ABUTMENT ;
    PORT
      LAYER M3 ;
      RECT 20.367 0.000 20.385 0.054 ;
    END
  END w0_wd_in[387]
  PIN w0_wd_in[388]
    DIRECTION OUTPUT ;
    USE SIGNAL ;
    SHAPE ABUTMENT ;
    PORT
      LAYER M3 ;
      RECT 20.655 0.000 20.673 0.054 ;
    END
  END w0_wd_in[388]
  PIN w0_wd_in[389]
    DIRECTION OUTPUT ;
    USE SIGNAL ;
    SHAPE ABUTMENT ;
    PORT
      LAYER M3 ;
      RECT 20.943 0.000 20.961 0.054 ;
    END
  END w0_wd_in[389]
  PIN w0_wd_in[390]
    DIRECTION OUTPUT ;
    USE SIGNAL ;
    SHAPE ABUTMENT ;
    PORT
      LAYER M3 ;
      RECT 21.231 0.000 21.249 0.054 ;
    END
  END w0_wd_in[390]
  PIN w0_wd_in[391]
    DIRECTION OUTPUT ;
    USE SIGNAL ;
    SHAPE ABUTMENT ;
    PORT
      LAYER M3 ;
      RECT 21.519 0.000 21.537 0.054 ;
    END
  END w0_wd_in[391]
  PIN w0_wd_in[392]
    DIRECTION OUTPUT ;
    USE SIGNAL ;
    SHAPE ABUTMENT ;
    PORT
      LAYER M3 ;
      RECT 21.807 0.000 21.825 0.054 ;
    END
  END w0_wd_in[392]
  PIN w0_wd_in[393]
    DIRECTION OUTPUT ;
    USE SIGNAL ;
    SHAPE ABUTMENT ;
    PORT
      LAYER M3 ;
      RECT 22.095 0.000 22.113 0.054 ;
    END
  END w0_wd_in[393]
  PIN w0_wd_in[394]
    DIRECTION OUTPUT ;
    USE SIGNAL ;
    SHAPE ABUTMENT ;
    PORT
      LAYER M3 ;
      RECT 22.383 0.000 22.401 0.054 ;
    END
  END w0_wd_in[394]
  PIN w0_wd_in[395]
    DIRECTION OUTPUT ;
    USE SIGNAL ;
    SHAPE ABUTMENT ;
    PORT
      LAYER M3 ;
      RECT 22.671 0.000 22.689 0.054 ;
    END
  END w0_wd_in[395]
  PIN w0_wd_in[396]
    DIRECTION OUTPUT ;
    USE SIGNAL ;
    SHAPE ABUTMENT ;
    PORT
      LAYER M3 ;
      RECT 22.959 0.000 22.977 0.054 ;
    END
  END w0_wd_in[396]
  PIN w0_wd_in[397]
    DIRECTION OUTPUT ;
    USE SIGNAL ;
    SHAPE ABUTMENT ;
    PORT
      LAYER M3 ;
      RECT 23.247 0.000 23.265 0.054 ;
    END
  END w0_wd_in[397]
  PIN w0_wd_in[398]
    DIRECTION OUTPUT ;
    USE SIGNAL ;
    SHAPE ABUTMENT ;
    PORT
      LAYER M3 ;
      RECT 23.535 0.000 23.553 0.054 ;
    END
  END w0_wd_in[398]
  PIN w0_wd_in[399]
    DIRECTION OUTPUT ;
    USE SIGNAL ;
    SHAPE ABUTMENT ;
    PORT
      LAYER M3 ;
      RECT 23.823 0.000 23.841 0.054 ;
    END
  END w0_wd_in[399]
  PIN w0_wd_in[400]
    DIRECTION OUTPUT ;
    USE SIGNAL ;
    SHAPE ABUTMENT ;
    PORT
      LAYER M3 ;
      RECT 24.111 0.000 24.129 0.054 ;
    END
  END w0_wd_in[400]
  PIN w0_wd_in[401]
    DIRECTION OUTPUT ;
    USE SIGNAL ;
    SHAPE ABUTMENT ;
    PORT
      LAYER M3 ;
      RECT 24.399 0.000 24.417 0.054 ;
    END
  END w0_wd_in[401]
  PIN w0_wd_in[402]
    DIRECTION OUTPUT ;
    USE SIGNAL ;
    SHAPE ABUTMENT ;
    PORT
      LAYER M3 ;
      RECT 24.687 0.000 24.705 0.054 ;
    END
  END w0_wd_in[402]
  PIN w0_wd_in[403]
    DIRECTION OUTPUT ;
    USE SIGNAL ;
    SHAPE ABUTMENT ;
    PORT
      LAYER M3 ;
      RECT 24.975 0.000 24.993 0.054 ;
    END
  END w0_wd_in[403]
  PIN w0_wd_in[404]
    DIRECTION OUTPUT ;
    USE SIGNAL ;
    SHAPE ABUTMENT ;
    PORT
      LAYER M3 ;
      RECT 25.263 0.000 25.281 0.054 ;
    END
  END w0_wd_in[404]
  PIN w0_wd_in[405]
    DIRECTION OUTPUT ;
    USE SIGNAL ;
    SHAPE ABUTMENT ;
    PORT
      LAYER M3 ;
      RECT 25.551 0.000 25.569 0.054 ;
    END
  END w0_wd_in[405]
  PIN w0_wd_in[406]
    DIRECTION OUTPUT ;
    USE SIGNAL ;
    SHAPE ABUTMENT ;
    PORT
      LAYER M3 ;
      RECT 25.839 0.000 25.857 0.054 ;
    END
  END w0_wd_in[406]
  PIN w0_wd_in[407]
    DIRECTION OUTPUT ;
    USE SIGNAL ;
    SHAPE ABUTMENT ;
    PORT
      LAYER M3 ;
      RECT 26.127 0.000 26.145 0.054 ;
    END
  END w0_wd_in[407]
  PIN w0_wd_in[408]
    DIRECTION OUTPUT ;
    USE SIGNAL ;
    SHAPE ABUTMENT ;
    PORT
      LAYER M3 ;
      RECT 26.415 0.000 26.433 0.054 ;
    END
  END w0_wd_in[408]
  PIN w0_wd_in[409]
    DIRECTION OUTPUT ;
    USE SIGNAL ;
    SHAPE ABUTMENT ;
    PORT
      LAYER M3 ;
      RECT 26.703 0.000 26.721 0.054 ;
    END
  END w0_wd_in[409]
  PIN w0_wd_in[410]
    DIRECTION OUTPUT ;
    USE SIGNAL ;
    SHAPE ABUTMENT ;
    PORT
      LAYER M3 ;
      RECT 26.991 0.000 27.009 0.054 ;
    END
  END w0_wd_in[410]
  PIN w0_wd_in[411]
    DIRECTION OUTPUT ;
    USE SIGNAL ;
    SHAPE ABUTMENT ;
    PORT
      LAYER M3 ;
      RECT 27.279 0.000 27.297 0.054 ;
    END
  END w0_wd_in[411]
  PIN w0_wd_in[412]
    DIRECTION OUTPUT ;
    USE SIGNAL ;
    SHAPE ABUTMENT ;
    PORT
      LAYER M3 ;
      RECT 27.567 0.000 27.585 0.054 ;
    END
  END w0_wd_in[412]
  PIN w0_wd_in[413]
    DIRECTION OUTPUT ;
    USE SIGNAL ;
    SHAPE ABUTMENT ;
    PORT
      LAYER M3 ;
      RECT 27.855 0.000 27.873 0.054 ;
    END
  END w0_wd_in[413]
  PIN w0_wd_in[414]
    DIRECTION OUTPUT ;
    USE SIGNAL ;
    SHAPE ABUTMENT ;
    PORT
      LAYER M3 ;
      RECT 28.143 0.000 28.161 0.054 ;
    END
  END w0_wd_in[414]
  PIN w0_wd_in[415]
    DIRECTION OUTPUT ;
    USE SIGNAL ;
    SHAPE ABUTMENT ;
    PORT
      LAYER M3 ;
      RECT 28.431 0.000 28.449 0.054 ;
    END
  END w0_wd_in[415]
  PIN w0_wd_in[416]
    DIRECTION OUTPUT ;
    USE SIGNAL ;
    SHAPE ABUTMENT ;
    PORT
      LAYER M3 ;
      RECT 28.719 0.000 28.737 0.054 ;
    END
  END w0_wd_in[416]
  PIN w0_wd_in[417]
    DIRECTION OUTPUT ;
    USE SIGNAL ;
    SHAPE ABUTMENT ;
    PORT
      LAYER M3 ;
      RECT 29.007 0.000 29.025 0.054 ;
    END
  END w0_wd_in[417]
  PIN w0_wd_in[418]
    DIRECTION OUTPUT ;
    USE SIGNAL ;
    SHAPE ABUTMENT ;
    PORT
      LAYER M3 ;
      RECT 29.295 0.000 29.313 0.054 ;
    END
  END w0_wd_in[418]
  PIN w0_wd_in[419]
    DIRECTION OUTPUT ;
    USE SIGNAL ;
    SHAPE ABUTMENT ;
    PORT
      LAYER M3 ;
      RECT 29.583 0.000 29.601 0.054 ;
    END
  END w0_wd_in[419]
  PIN w0_wd_in[420]
    DIRECTION OUTPUT ;
    USE SIGNAL ;
    SHAPE ABUTMENT ;
    PORT
      LAYER M3 ;
      RECT 29.871 0.000 29.889 0.054 ;
    END
  END w0_wd_in[420]
  PIN w0_wd_in[421]
    DIRECTION OUTPUT ;
    USE SIGNAL ;
    SHAPE ABUTMENT ;
    PORT
      LAYER M3 ;
      RECT 30.159 0.000 30.177 0.054 ;
    END
  END w0_wd_in[421]
  PIN w0_wd_in[422]
    DIRECTION OUTPUT ;
    USE SIGNAL ;
    SHAPE ABUTMENT ;
    PORT
      LAYER M3 ;
      RECT 30.447 0.000 30.465 0.054 ;
    END
  END w0_wd_in[422]
  PIN w0_wd_in[423]
    DIRECTION OUTPUT ;
    USE SIGNAL ;
    SHAPE ABUTMENT ;
    PORT
      LAYER M3 ;
      RECT 30.735 0.000 30.753 0.054 ;
    END
  END w0_wd_in[423]
  PIN w0_wd_in[424]
    DIRECTION OUTPUT ;
    USE SIGNAL ;
    SHAPE ABUTMENT ;
    PORT
      LAYER M3 ;
      RECT 31.023 0.000 31.041 0.054 ;
    END
  END w0_wd_in[424]
  PIN w0_wd_in[425]
    DIRECTION OUTPUT ;
    USE SIGNAL ;
    SHAPE ABUTMENT ;
    PORT
      LAYER M3 ;
      RECT 31.311 0.000 31.329 0.054 ;
    END
  END w0_wd_in[425]
  PIN w0_wd_in[426]
    DIRECTION OUTPUT ;
    USE SIGNAL ;
    SHAPE ABUTMENT ;
    PORT
      LAYER M3 ;
      RECT 31.599 0.000 31.617 0.054 ;
    END
  END w0_wd_in[426]
  PIN w0_wd_in[427]
    DIRECTION OUTPUT ;
    USE SIGNAL ;
    SHAPE ABUTMENT ;
    PORT
      LAYER M3 ;
      RECT 31.887 0.000 31.905 0.054 ;
    END
  END w0_wd_in[427]
  PIN w0_wd_in[428]
    DIRECTION OUTPUT ;
    USE SIGNAL ;
    SHAPE ABUTMENT ;
    PORT
      LAYER M3 ;
      RECT 32.175 0.000 32.193 0.054 ;
    END
  END w0_wd_in[428]
  PIN w0_wd_in[429]
    DIRECTION OUTPUT ;
    USE SIGNAL ;
    SHAPE ABUTMENT ;
    PORT
      LAYER M3 ;
      RECT 32.463 0.000 32.481 0.054 ;
    END
  END w0_wd_in[429]
  PIN w0_wd_in[430]
    DIRECTION OUTPUT ;
    USE SIGNAL ;
    SHAPE ABUTMENT ;
    PORT
      LAYER M3 ;
      RECT 32.751 0.000 32.769 0.054 ;
    END
  END w0_wd_in[430]
  PIN w0_wd_in[431]
    DIRECTION OUTPUT ;
    USE SIGNAL ;
    SHAPE ABUTMENT ;
    PORT
      LAYER M3 ;
      RECT 33.039 0.000 33.057 0.054 ;
    END
  END w0_wd_in[431]
  PIN w0_wd_in[432]
    DIRECTION OUTPUT ;
    USE SIGNAL ;
    SHAPE ABUTMENT ;
    PORT
      LAYER M3 ;
      RECT 33.327 0.000 33.345 0.054 ;
    END
  END w0_wd_in[432]
  PIN w0_wd_in[433]
    DIRECTION OUTPUT ;
    USE SIGNAL ;
    SHAPE ABUTMENT ;
    PORT
      LAYER M3 ;
      RECT 33.615 0.000 33.633 0.054 ;
    END
  END w0_wd_in[433]
  PIN w0_wd_in[434]
    DIRECTION OUTPUT ;
    USE SIGNAL ;
    SHAPE ABUTMENT ;
    PORT
      LAYER M3 ;
      RECT 33.903 0.000 33.921 0.054 ;
    END
  END w0_wd_in[434]
  PIN w0_wd_in[435]
    DIRECTION OUTPUT ;
    USE SIGNAL ;
    SHAPE ABUTMENT ;
    PORT
      LAYER M3 ;
      RECT 34.191 0.000 34.209 0.054 ;
    END
  END w0_wd_in[435]
  PIN w0_wd_in[436]
    DIRECTION OUTPUT ;
    USE SIGNAL ;
    SHAPE ABUTMENT ;
    PORT
      LAYER M3 ;
      RECT 34.479 0.000 34.497 0.054 ;
    END
  END w0_wd_in[436]
  PIN w0_wd_in[437]
    DIRECTION OUTPUT ;
    USE SIGNAL ;
    SHAPE ABUTMENT ;
    PORT
      LAYER M3 ;
      RECT 34.767 0.000 34.785 0.054 ;
    END
  END w0_wd_in[437]
  PIN w0_wd_in[438]
    DIRECTION OUTPUT ;
    USE SIGNAL ;
    SHAPE ABUTMENT ;
    PORT
      LAYER M3 ;
      RECT 35.055 0.000 35.073 0.054 ;
    END
  END w0_wd_in[438]
  PIN w0_wd_in[439]
    DIRECTION OUTPUT ;
    USE SIGNAL ;
    SHAPE ABUTMENT ;
    PORT
      LAYER M3 ;
      RECT 35.343 0.000 35.361 0.054 ;
    END
  END w0_wd_in[439]
  PIN w0_wd_in[440]
    DIRECTION OUTPUT ;
    USE SIGNAL ;
    SHAPE ABUTMENT ;
    PORT
      LAYER M3 ;
      RECT 35.631 0.000 35.649 0.054 ;
    END
  END w0_wd_in[440]
  PIN w0_wd_in[441]
    DIRECTION OUTPUT ;
    USE SIGNAL ;
    SHAPE ABUTMENT ;
    PORT
      LAYER M3 ;
      RECT 35.919 0.000 35.937 0.054 ;
    END
  END w0_wd_in[441]
  PIN w0_wd_in[442]
    DIRECTION OUTPUT ;
    USE SIGNAL ;
    SHAPE ABUTMENT ;
    PORT
      LAYER M3 ;
      RECT 36.207 0.000 36.225 0.054 ;
    END
  END w0_wd_in[442]
  PIN w0_wd_in[443]
    DIRECTION OUTPUT ;
    USE SIGNAL ;
    SHAPE ABUTMENT ;
    PORT
      LAYER M3 ;
      RECT 36.495 0.000 36.513 0.054 ;
    END
  END w0_wd_in[443]
  PIN w0_wd_in[444]
    DIRECTION OUTPUT ;
    USE SIGNAL ;
    SHAPE ABUTMENT ;
    PORT
      LAYER M3 ;
      RECT 36.783 0.000 36.801 0.054 ;
    END
  END w0_wd_in[444]
  PIN w0_wd_in[445]
    DIRECTION OUTPUT ;
    USE SIGNAL ;
    SHAPE ABUTMENT ;
    PORT
      LAYER M3 ;
      RECT 37.071 0.000 37.089 0.054 ;
    END
  END w0_wd_in[445]
  PIN w0_wd_in[446]
    DIRECTION OUTPUT ;
    USE SIGNAL ;
    SHAPE ABUTMENT ;
    PORT
      LAYER M3 ;
      RECT 37.359 0.000 37.377 0.054 ;
    END
  END w0_wd_in[446]
  PIN w0_wd_in[447]
    DIRECTION OUTPUT ;
    USE SIGNAL ;
    SHAPE ABUTMENT ;
    PORT
      LAYER M3 ;
      RECT 37.647 0.000 37.665 0.054 ;
    END
  END w0_wd_in[447]
  PIN w0_wd_in[448]
    DIRECTION OUTPUT ;
    USE SIGNAL ;
    SHAPE ABUTMENT ;
    PORT
      LAYER M3 ;
      RECT 37.935 0.000 37.953 0.054 ;
    END
  END w0_wd_in[448]
  PIN w0_wd_in[449]
    DIRECTION OUTPUT ;
    USE SIGNAL ;
    SHAPE ABUTMENT ;
    PORT
      LAYER M3 ;
      RECT 38.223 0.000 38.241 0.054 ;
    END
  END w0_wd_in[449]
  PIN w0_wd_in[450]
    DIRECTION OUTPUT ;
    USE SIGNAL ;
    SHAPE ABUTMENT ;
    PORT
      LAYER M3 ;
      RECT 38.511 0.000 38.529 0.054 ;
    END
  END w0_wd_in[450]
  PIN w0_wd_in[451]
    DIRECTION OUTPUT ;
    USE SIGNAL ;
    SHAPE ABUTMENT ;
    PORT
      LAYER M3 ;
      RECT 38.799 0.000 38.817 0.054 ;
    END
  END w0_wd_in[451]
  PIN w0_wd_in[452]
    DIRECTION OUTPUT ;
    USE SIGNAL ;
    SHAPE ABUTMENT ;
    PORT
      LAYER M3 ;
      RECT 39.087 0.000 39.105 0.054 ;
    END
  END w0_wd_in[452]
  PIN w0_wd_in[453]
    DIRECTION OUTPUT ;
    USE SIGNAL ;
    SHAPE ABUTMENT ;
    PORT
      LAYER M3 ;
      RECT 39.375 0.000 39.393 0.054 ;
    END
  END w0_wd_in[453]
  PIN w0_wd_in[454]
    DIRECTION OUTPUT ;
    USE SIGNAL ;
    SHAPE ABUTMENT ;
    PORT
      LAYER M3 ;
      RECT 39.663 0.000 39.681 0.054 ;
    END
  END w0_wd_in[454]
  PIN w0_wd_in[455]
    DIRECTION OUTPUT ;
    USE SIGNAL ;
    SHAPE ABUTMENT ;
    PORT
      LAYER M3 ;
      RECT 39.951 0.000 39.969 0.054 ;
    END
  END w0_wd_in[455]
  PIN w0_wd_in[456]
    DIRECTION OUTPUT ;
    USE SIGNAL ;
    SHAPE ABUTMENT ;
    PORT
      LAYER M3 ;
      RECT 40.239 0.000 40.257 0.054 ;
    END
  END w0_wd_in[456]
  PIN w0_wd_in[457]
    DIRECTION OUTPUT ;
    USE SIGNAL ;
    SHAPE ABUTMENT ;
    PORT
      LAYER M3 ;
      RECT 40.527 0.000 40.545 0.054 ;
    END
  END w0_wd_in[457]
  PIN w0_wd_in[458]
    DIRECTION OUTPUT ;
    USE SIGNAL ;
    SHAPE ABUTMENT ;
    PORT
      LAYER M3 ;
      RECT 40.815 0.000 40.833 0.054 ;
    END
  END w0_wd_in[458]
  PIN w0_wd_in[459]
    DIRECTION OUTPUT ;
    USE SIGNAL ;
    SHAPE ABUTMENT ;
    PORT
      LAYER M3 ;
      RECT 41.103 0.000 41.121 0.054 ;
    END
  END w0_wd_in[459]
  PIN w0_wd_in[460]
    DIRECTION OUTPUT ;
    USE SIGNAL ;
    SHAPE ABUTMENT ;
    PORT
      LAYER M3 ;
      RECT 41.391 0.000 41.409 0.054 ;
    END
  END w0_wd_in[460]
  PIN w0_wd_in[461]
    DIRECTION OUTPUT ;
    USE SIGNAL ;
    SHAPE ABUTMENT ;
    PORT
      LAYER M3 ;
      RECT 41.679 0.000 41.697 0.054 ;
    END
  END w0_wd_in[461]
  PIN w0_wd_in[462]
    DIRECTION OUTPUT ;
    USE SIGNAL ;
    SHAPE ABUTMENT ;
    PORT
      LAYER M3 ;
      RECT 41.967 0.000 41.985 0.054 ;
    END
  END w0_wd_in[462]
  PIN w0_wd_in[463]
    DIRECTION OUTPUT ;
    USE SIGNAL ;
    SHAPE ABUTMENT ;
    PORT
      LAYER M3 ;
      RECT 42.255 0.000 42.273 0.054 ;
    END
  END w0_wd_in[463]
  PIN w0_wd_in[464]
    DIRECTION OUTPUT ;
    USE SIGNAL ;
    SHAPE ABUTMENT ;
    PORT
      LAYER M3 ;
      RECT 42.543 0.000 42.561 0.054 ;
    END
  END w0_wd_in[464]
  PIN w0_wd_in[465]
    DIRECTION OUTPUT ;
    USE SIGNAL ;
    SHAPE ABUTMENT ;
    PORT
      LAYER M3 ;
      RECT 42.831 0.000 42.849 0.054 ;
    END
  END w0_wd_in[465]
  PIN w0_wd_in[466]
    DIRECTION OUTPUT ;
    USE SIGNAL ;
    SHAPE ABUTMENT ;
    PORT
      LAYER M3 ;
      RECT 43.119 0.000 43.137 0.054 ;
    END
  END w0_wd_in[466]
  PIN w0_wd_in[467]
    DIRECTION OUTPUT ;
    USE SIGNAL ;
    SHAPE ABUTMENT ;
    PORT
      LAYER M3 ;
      RECT 43.407 0.000 43.425 0.054 ;
    END
  END w0_wd_in[467]
  PIN w0_wd_in[468]
    DIRECTION OUTPUT ;
    USE SIGNAL ;
    SHAPE ABUTMENT ;
    PORT
      LAYER M3 ;
      RECT 43.695 0.000 43.713 0.054 ;
    END
  END w0_wd_in[468]
  PIN w0_wd_in[469]
    DIRECTION OUTPUT ;
    USE SIGNAL ;
    SHAPE ABUTMENT ;
    PORT
      LAYER M3 ;
      RECT 43.983 0.000 44.001 0.054 ;
    END
  END w0_wd_in[469]
  PIN w0_wd_in[470]
    DIRECTION OUTPUT ;
    USE SIGNAL ;
    SHAPE ABUTMENT ;
    PORT
      LAYER M3 ;
      RECT 44.271 0.000 44.289 0.054 ;
    END
  END w0_wd_in[470]
  PIN w0_wd_in[471]
    DIRECTION OUTPUT ;
    USE SIGNAL ;
    SHAPE ABUTMENT ;
    PORT
      LAYER M3 ;
      RECT 44.559 0.000 44.577 0.054 ;
    END
  END w0_wd_in[471]
  PIN w0_wd_in[472]
    DIRECTION OUTPUT ;
    USE SIGNAL ;
    SHAPE ABUTMENT ;
    PORT
      LAYER M3 ;
      RECT 44.847 0.000 44.865 0.054 ;
    END
  END w0_wd_in[472]
  PIN w0_wd_in[473]
    DIRECTION OUTPUT ;
    USE SIGNAL ;
    SHAPE ABUTMENT ;
    PORT
      LAYER M3 ;
      RECT 45.135 0.000 45.153 0.054 ;
    END
  END w0_wd_in[473]
  PIN w0_wd_in[474]
    DIRECTION OUTPUT ;
    USE SIGNAL ;
    SHAPE ABUTMENT ;
    PORT
      LAYER M3 ;
      RECT 45.423 0.000 45.441 0.054 ;
    END
  END w0_wd_in[474]
  PIN w0_wd_in[475]
    DIRECTION OUTPUT ;
    USE SIGNAL ;
    SHAPE ABUTMENT ;
    PORT
      LAYER M3 ;
      RECT 45.711 0.000 45.729 0.054 ;
    END
  END w0_wd_in[475]
  PIN w0_wd_in[476]
    DIRECTION OUTPUT ;
    USE SIGNAL ;
    SHAPE ABUTMENT ;
    PORT
      LAYER M3 ;
      RECT 45.999 0.000 46.017 0.054 ;
    END
  END w0_wd_in[476]
  PIN w0_wd_in[477]
    DIRECTION OUTPUT ;
    USE SIGNAL ;
    SHAPE ABUTMENT ;
    PORT
      LAYER M3 ;
      RECT 46.287 0.000 46.305 0.054 ;
    END
  END w0_wd_in[477]
  PIN w0_wd_in[478]
    DIRECTION OUTPUT ;
    USE SIGNAL ;
    SHAPE ABUTMENT ;
    PORT
      LAYER M3 ;
      RECT 46.575 0.000 46.593 0.054 ;
    END
  END w0_wd_in[478]
  PIN w0_wd_in[479]
    DIRECTION OUTPUT ;
    USE SIGNAL ;
    SHAPE ABUTMENT ;
    PORT
      LAYER M3 ;
      RECT 46.863 0.000 46.881 0.054 ;
    END
  END w0_wd_in[479]
  PIN w0_wd_in[480]
    DIRECTION OUTPUT ;
    USE SIGNAL ;
    SHAPE ABUTMENT ;
    PORT
      LAYER M3 ;
      RECT 47.151 0.000 47.169 0.054 ;
    END
  END w0_wd_in[480]
  PIN w0_wd_in[481]
    DIRECTION OUTPUT ;
    USE SIGNAL ;
    SHAPE ABUTMENT ;
    PORT
      LAYER M3 ;
      RECT 47.439 0.000 47.457 0.054 ;
    END
  END w0_wd_in[481]
  PIN w0_wd_in[482]
    DIRECTION OUTPUT ;
    USE SIGNAL ;
    SHAPE ABUTMENT ;
    PORT
      LAYER M3 ;
      RECT 47.727 0.000 47.745 0.054 ;
    END
  END w0_wd_in[482]
  PIN w0_wd_in[483]
    DIRECTION OUTPUT ;
    USE SIGNAL ;
    SHAPE ABUTMENT ;
    PORT
      LAYER M3 ;
      RECT 48.015 0.000 48.033 0.054 ;
    END
  END w0_wd_in[483]
  PIN w0_wd_in[484]
    DIRECTION OUTPUT ;
    USE SIGNAL ;
    SHAPE ABUTMENT ;
    PORT
      LAYER M3 ;
      RECT 48.303 0.000 48.321 0.054 ;
    END
  END w0_wd_in[484]
  PIN w0_wd_in[485]
    DIRECTION OUTPUT ;
    USE SIGNAL ;
    SHAPE ABUTMENT ;
    PORT
      LAYER M3 ;
      RECT 48.591 0.000 48.609 0.054 ;
    END
  END w0_wd_in[485]
  PIN w0_wd_in[486]
    DIRECTION OUTPUT ;
    USE SIGNAL ;
    SHAPE ABUTMENT ;
    PORT
      LAYER M3 ;
      RECT 48.879 0.000 48.897 0.054 ;
    END
  END w0_wd_in[486]
  PIN w0_wd_in[487]
    DIRECTION OUTPUT ;
    USE SIGNAL ;
    SHAPE ABUTMENT ;
    PORT
      LAYER M3 ;
      RECT 49.167 0.000 49.185 0.054 ;
    END
  END w0_wd_in[487]
  PIN w0_wd_in[488]
    DIRECTION OUTPUT ;
    USE SIGNAL ;
    SHAPE ABUTMENT ;
    PORT
      LAYER M3 ;
      RECT 49.455 0.000 49.473 0.054 ;
    END
  END w0_wd_in[488]
  PIN w0_wd_in[489]
    DIRECTION OUTPUT ;
    USE SIGNAL ;
    SHAPE ABUTMENT ;
    PORT
      LAYER M3 ;
      RECT 49.743 0.000 49.761 0.054 ;
    END
  END w0_wd_in[489]
  PIN w0_wd_in[490]
    DIRECTION OUTPUT ;
    USE SIGNAL ;
    SHAPE ABUTMENT ;
    PORT
      LAYER M3 ;
      RECT 50.031 0.000 50.049 0.054 ;
    END
  END w0_wd_in[490]
  PIN w0_wd_in[491]
    DIRECTION OUTPUT ;
    USE SIGNAL ;
    SHAPE ABUTMENT ;
    PORT
      LAYER M3 ;
      RECT 50.319 0.000 50.337 0.054 ;
    END
  END w0_wd_in[491]
  PIN w0_wd_in[492]
    DIRECTION OUTPUT ;
    USE SIGNAL ;
    SHAPE ABUTMENT ;
    PORT
      LAYER M3 ;
      RECT 50.607 0.000 50.625 0.054 ;
    END
  END w0_wd_in[492]
  PIN w0_wd_in[493]
    DIRECTION OUTPUT ;
    USE SIGNAL ;
    SHAPE ABUTMENT ;
    PORT
      LAYER M3 ;
      RECT 50.895 0.000 50.913 0.054 ;
    END
  END w0_wd_in[493]
  PIN w0_wd_in[494]
    DIRECTION OUTPUT ;
    USE SIGNAL ;
    SHAPE ABUTMENT ;
    PORT
      LAYER M3 ;
      RECT 51.183 0.000 51.201 0.054 ;
    END
  END w0_wd_in[494]
  PIN w0_wd_in[495]
    DIRECTION OUTPUT ;
    USE SIGNAL ;
    SHAPE ABUTMENT ;
    PORT
      LAYER M3 ;
      RECT 51.471 0.000 51.489 0.054 ;
    END
  END w0_wd_in[495]
  PIN w0_wd_in[496]
    DIRECTION OUTPUT ;
    USE SIGNAL ;
    SHAPE ABUTMENT ;
    PORT
      LAYER M3 ;
      RECT 51.759 0.000 51.777 0.054 ;
    END
  END w0_wd_in[496]
  PIN w0_wd_in[497]
    DIRECTION OUTPUT ;
    USE SIGNAL ;
    SHAPE ABUTMENT ;
    PORT
      LAYER M3 ;
      RECT 52.047 0.000 52.065 0.054 ;
    END
  END w0_wd_in[497]
  PIN w0_wd_in[498]
    DIRECTION OUTPUT ;
    USE SIGNAL ;
    SHAPE ABUTMENT ;
    PORT
      LAYER M3 ;
      RECT 52.335 0.000 52.353 0.054 ;
    END
  END w0_wd_in[498]
  PIN w0_wd_in[499]
    DIRECTION OUTPUT ;
    USE SIGNAL ;
    SHAPE ABUTMENT ;
    PORT
      LAYER M3 ;
      RECT 52.623 0.000 52.641 0.054 ;
    END
  END w0_wd_in[499]
  PIN w0_wd_in[500]
    DIRECTION OUTPUT ;
    USE SIGNAL ;
    SHAPE ABUTMENT ;
    PORT
      LAYER M3 ;
      RECT 52.911 0.000 52.929 0.054 ;
    END
  END w0_wd_in[500]
  PIN w0_wd_in[501]
    DIRECTION OUTPUT ;
    USE SIGNAL ;
    SHAPE ABUTMENT ;
    PORT
      LAYER M3 ;
      RECT 53.199 0.000 53.217 0.054 ;
    END
  END w0_wd_in[501]
  PIN w0_wd_in[502]
    DIRECTION OUTPUT ;
    USE SIGNAL ;
    SHAPE ABUTMENT ;
    PORT
      LAYER M3 ;
      RECT 53.487 0.000 53.505 0.054 ;
    END
  END w0_wd_in[502]
  PIN w0_wd_in[503]
    DIRECTION OUTPUT ;
    USE SIGNAL ;
    SHAPE ABUTMENT ;
    PORT
      LAYER M3 ;
      RECT 53.775 0.000 53.793 0.054 ;
    END
  END w0_wd_in[503]
  PIN w0_wd_in[504]
    DIRECTION OUTPUT ;
    USE SIGNAL ;
    SHAPE ABUTMENT ;
    PORT
      LAYER M3 ;
      RECT 54.063 0.000 54.081 0.054 ;
    END
  END w0_wd_in[504]
  PIN w0_wd_in[505]
    DIRECTION OUTPUT ;
    USE SIGNAL ;
    SHAPE ABUTMENT ;
    PORT
      LAYER M3 ;
      RECT 54.351 0.000 54.369 0.054 ;
    END
  END w0_wd_in[505]
  PIN w0_wd_in[506]
    DIRECTION OUTPUT ;
    USE SIGNAL ;
    SHAPE ABUTMENT ;
    PORT
      LAYER M3 ;
      RECT 54.639 0.000 54.657 0.054 ;
    END
  END w0_wd_in[506]
  PIN w0_wd_in[507]
    DIRECTION OUTPUT ;
    USE SIGNAL ;
    SHAPE ABUTMENT ;
    PORT
      LAYER M3 ;
      RECT 54.927 0.000 54.945 0.054 ;
    END
  END w0_wd_in[507]
  PIN w0_wd_in[508]
    DIRECTION OUTPUT ;
    USE SIGNAL ;
    SHAPE ABUTMENT ;
    PORT
      LAYER M3 ;
      RECT 55.215 0.000 55.233 0.054 ;
    END
  END w0_wd_in[508]
  PIN w0_wd_in[509]
    DIRECTION OUTPUT ;
    USE SIGNAL ;
    SHAPE ABUTMENT ;
    PORT
      LAYER M3 ;
      RECT 55.503 0.000 55.521 0.054 ;
    END
  END w0_wd_in[509]
  PIN w0_wd_in[510]
    DIRECTION OUTPUT ;
    USE SIGNAL ;
    SHAPE ABUTMENT ;
    PORT
      LAYER M3 ;
      RECT 55.791 0.000 55.809 0.054 ;
    END
  END w0_wd_in[510]
  PIN w0_wd_in[511]
    DIRECTION OUTPUT ;
    USE SIGNAL ;
    SHAPE ABUTMENT ;
    PORT
      LAYER M3 ;
      RECT 56.079 0.000 56.097 0.054 ;
    END
  END w0_wd_in[511]
  PIN w0_wd_in[512]
    DIRECTION OUTPUT ;
    USE SIGNAL ;
    SHAPE ABUTMENT ;
    PORT
      LAYER M3 ;
      RECT 56.367 0.000 56.385 0.054 ;
    END
  END w0_wd_in[512]
  PIN w0_wd_in[513]
    DIRECTION OUTPUT ;
    USE SIGNAL ;
    SHAPE ABUTMENT ;
    PORT
      LAYER M3 ;
      RECT 56.655 0.000 56.673 0.054 ;
    END
  END w0_wd_in[513]
  PIN w0_wd_in[514]
    DIRECTION OUTPUT ;
    USE SIGNAL ;
    SHAPE ABUTMENT ;
    PORT
      LAYER M3 ;
      RECT 56.943 0.000 56.961 0.054 ;
    END
  END w0_wd_in[514]
  PIN w0_wd_in[515]
    DIRECTION OUTPUT ;
    USE SIGNAL ;
    SHAPE ABUTMENT ;
    PORT
      LAYER M3 ;
      RECT 57.231 0.000 57.249 0.054 ;
    END
  END w0_wd_in[515]
  PIN w0_wd_in[516]
    DIRECTION OUTPUT ;
    USE SIGNAL ;
    SHAPE ABUTMENT ;
    PORT
      LAYER M3 ;
      RECT 57.519 0.000 57.537 0.054 ;
    END
  END w0_wd_in[516]
  PIN w0_wd_in[517]
    DIRECTION OUTPUT ;
    USE SIGNAL ;
    SHAPE ABUTMENT ;
    PORT
      LAYER M3 ;
      RECT 57.807 0.000 57.825 0.054 ;
    END
  END w0_wd_in[517]
  PIN w0_wd_in[518]
    DIRECTION OUTPUT ;
    USE SIGNAL ;
    SHAPE ABUTMENT ;
    PORT
      LAYER M3 ;
      RECT 58.095 0.000 58.113 0.054 ;
    END
  END w0_wd_in[518]
  PIN w0_wd_in[519]
    DIRECTION OUTPUT ;
    USE SIGNAL ;
    SHAPE ABUTMENT ;
    PORT
      LAYER M3 ;
      RECT 58.383 0.000 58.401 0.054 ;
    END
  END w0_wd_in[519]
  PIN w0_wd_in[520]
    DIRECTION OUTPUT ;
    USE SIGNAL ;
    SHAPE ABUTMENT ;
    PORT
      LAYER M3 ;
      RECT 58.671 0.000 58.689 0.054 ;
    END
  END w0_wd_in[520]
  PIN w0_wd_in[521]
    DIRECTION OUTPUT ;
    USE SIGNAL ;
    SHAPE ABUTMENT ;
    PORT
      LAYER M3 ;
      RECT 58.959 0.000 58.977 0.054 ;
    END
  END w0_wd_in[521]
  PIN w0_wd_in[522]
    DIRECTION OUTPUT ;
    USE SIGNAL ;
    SHAPE ABUTMENT ;
    PORT
      LAYER M3 ;
      RECT 59.247 0.000 59.265 0.054 ;
    END
  END w0_wd_in[522]
  PIN w0_wd_in[523]
    DIRECTION OUTPUT ;
    USE SIGNAL ;
    SHAPE ABUTMENT ;
    PORT
      LAYER M3 ;
      RECT 59.535 0.000 59.553 0.054 ;
    END
  END w0_wd_in[523]
  PIN w0_wd_in[524]
    DIRECTION OUTPUT ;
    USE SIGNAL ;
    SHAPE ABUTMENT ;
    PORT
      LAYER M3 ;
      RECT 59.823 0.000 59.841 0.054 ;
    END
  END w0_wd_in[524]
  PIN w0_wd_in[525]
    DIRECTION OUTPUT ;
    USE SIGNAL ;
    SHAPE ABUTMENT ;
    PORT
      LAYER M3 ;
      RECT 60.111 0.000 60.129 0.054 ;
    END
  END w0_wd_in[525]
  PIN w0_wd_in[526]
    DIRECTION OUTPUT ;
    USE SIGNAL ;
    SHAPE ABUTMENT ;
    PORT
      LAYER M3 ;
      RECT 60.399 0.000 60.417 0.054 ;
    END
  END w0_wd_in[526]
  PIN w0_wd_in[527]
    DIRECTION OUTPUT ;
    USE SIGNAL ;
    SHAPE ABUTMENT ;
    PORT
      LAYER M3 ;
      RECT 60.687 0.000 60.705 0.054 ;
    END
  END w0_wd_in[527]
  PIN w0_wd_in[528]
    DIRECTION OUTPUT ;
    USE SIGNAL ;
    SHAPE ABUTMENT ;
    PORT
      LAYER M3 ;
      RECT 60.975 0.000 60.993 0.054 ;
    END
  END w0_wd_in[528]
  PIN w0_wd_in[529]
    DIRECTION OUTPUT ;
    USE SIGNAL ;
    SHAPE ABUTMENT ;
    PORT
      LAYER M3 ;
      RECT 61.263 0.000 61.281 0.054 ;
    END
  END w0_wd_in[529]
  PIN w0_wd_in[530]
    DIRECTION OUTPUT ;
    USE SIGNAL ;
    SHAPE ABUTMENT ;
    PORT
      LAYER M3 ;
      RECT 61.551 0.000 61.569 0.054 ;
    END
  END w0_wd_in[530]
  PIN w0_wd_in[531]
    DIRECTION OUTPUT ;
    USE SIGNAL ;
    SHAPE ABUTMENT ;
    PORT
      LAYER M3 ;
      RECT 61.839 0.000 61.857 0.054 ;
    END
  END w0_wd_in[531]
  PIN w0_wd_in[532]
    DIRECTION OUTPUT ;
    USE SIGNAL ;
    SHAPE ABUTMENT ;
    PORT
      LAYER M3 ;
      RECT 62.127 0.000 62.145 0.054 ;
    END
  END w0_wd_in[532]
  PIN w0_wd_in[533]
    DIRECTION OUTPUT ;
    USE SIGNAL ;
    SHAPE ABUTMENT ;
    PORT
      LAYER M3 ;
      RECT 62.415 0.000 62.433 0.054 ;
    END
  END w0_wd_in[533]
  PIN w0_wd_in[534]
    DIRECTION OUTPUT ;
    USE SIGNAL ;
    SHAPE ABUTMENT ;
    PORT
      LAYER M3 ;
      RECT 62.703 0.000 62.721 0.054 ;
    END
  END w0_wd_in[534]
  PIN w0_wd_in[535]
    DIRECTION OUTPUT ;
    USE SIGNAL ;
    SHAPE ABUTMENT ;
    PORT
      LAYER M3 ;
      RECT 62.991 0.000 63.009 0.054 ;
    END
  END w0_wd_in[535]
  PIN w0_wd_in[536]
    DIRECTION OUTPUT ;
    USE SIGNAL ;
    SHAPE ABUTMENT ;
    PORT
      LAYER M3 ;
      RECT 63.279 0.000 63.297 0.054 ;
    END
  END w0_wd_in[536]
  PIN w0_wd_in[537]
    DIRECTION OUTPUT ;
    USE SIGNAL ;
    SHAPE ABUTMENT ;
    PORT
      LAYER M3 ;
      RECT 63.567 0.000 63.585 0.054 ;
    END
  END w0_wd_in[537]
  PIN w0_wd_in[538]
    DIRECTION OUTPUT ;
    USE SIGNAL ;
    SHAPE ABUTMENT ;
    PORT
      LAYER M3 ;
      RECT 63.855 0.000 63.873 0.054 ;
    END
  END w0_wd_in[538]
  PIN w0_wd_in[539]
    DIRECTION OUTPUT ;
    USE SIGNAL ;
    SHAPE ABUTMENT ;
    PORT
      LAYER M3 ;
      RECT 64.143 0.000 64.161 0.054 ;
    END
  END w0_wd_in[539]
  PIN w0_wd_in[540]
    DIRECTION OUTPUT ;
    USE SIGNAL ;
    SHAPE ABUTMENT ;
    PORT
      LAYER M3 ;
      RECT 64.431 0.000 64.449 0.054 ;
    END
  END w0_wd_in[540]
  PIN w0_wd_in[541]
    DIRECTION OUTPUT ;
    USE SIGNAL ;
    SHAPE ABUTMENT ;
    PORT
      LAYER M3 ;
      RECT 64.719 0.000 64.737 0.054 ;
    END
  END w0_wd_in[541]
  PIN w0_wd_in[542]
    DIRECTION OUTPUT ;
    USE SIGNAL ;
    SHAPE ABUTMENT ;
    PORT
      LAYER M3 ;
      RECT 65.007 0.000 65.025 0.054 ;
    END
  END w0_wd_in[542]
  PIN w0_wd_in[543]
    DIRECTION OUTPUT ;
    USE SIGNAL ;
    SHAPE ABUTMENT ;
    PORT
      LAYER M3 ;
      RECT 65.295 0.000 65.313 0.054 ;
    END
  END w0_wd_in[543]
  PIN w0_wd_in[544]
    DIRECTION OUTPUT ;
    USE SIGNAL ;
    SHAPE ABUTMENT ;
    PORT
      LAYER M3 ;
      RECT 65.583 0.000 65.601 0.054 ;
    END
  END w0_wd_in[544]
  PIN w0_wd_in[545]
    DIRECTION OUTPUT ;
    USE SIGNAL ;
    SHAPE ABUTMENT ;
    PORT
      LAYER M3 ;
      RECT 65.871 0.000 65.889 0.054 ;
    END
  END w0_wd_in[545]
  PIN w0_wd_in[546]
    DIRECTION OUTPUT ;
    USE SIGNAL ;
    SHAPE ABUTMENT ;
    PORT
      LAYER M3 ;
      RECT 66.159 0.000 66.177 0.054 ;
    END
  END w0_wd_in[546]
  PIN w0_wd_in[547]
    DIRECTION OUTPUT ;
    USE SIGNAL ;
    SHAPE ABUTMENT ;
    PORT
      LAYER M3 ;
      RECT 66.447 0.000 66.465 0.054 ;
    END
  END w0_wd_in[547]
  PIN w0_wd_in[548]
    DIRECTION OUTPUT ;
    USE SIGNAL ;
    SHAPE ABUTMENT ;
    PORT
      LAYER M3 ;
      RECT 66.735 0.000 66.753 0.054 ;
    END
  END w0_wd_in[548]
  PIN w0_wd_in[549]
    DIRECTION OUTPUT ;
    USE SIGNAL ;
    SHAPE ABUTMENT ;
    PORT
      LAYER M3 ;
      RECT 67.023 0.000 67.041 0.054 ;
    END
  END w0_wd_in[549]
  PIN w0_wd_in[550]
    DIRECTION OUTPUT ;
    USE SIGNAL ;
    SHAPE ABUTMENT ;
    PORT
      LAYER M3 ;
      RECT 67.311 0.000 67.329 0.054 ;
    END
  END w0_wd_in[550]
  PIN w0_wd_in[551]
    DIRECTION OUTPUT ;
    USE SIGNAL ;
    SHAPE ABUTMENT ;
    PORT
      LAYER M3 ;
      RECT 67.599 0.000 67.617 0.054 ;
    END
  END w0_wd_in[551]
  PIN w0_wd_in[552]
    DIRECTION OUTPUT ;
    USE SIGNAL ;
    SHAPE ABUTMENT ;
    PORT
      LAYER M3 ;
      RECT 67.887 0.000 67.905 0.054 ;
    END
  END w0_wd_in[552]
  PIN w0_wd_in[553]
    DIRECTION OUTPUT ;
    USE SIGNAL ;
    SHAPE ABUTMENT ;
    PORT
      LAYER M3 ;
      RECT 68.175 0.000 68.193 0.054 ;
    END
  END w0_wd_in[553]
  PIN w0_wd_in[554]
    DIRECTION OUTPUT ;
    USE SIGNAL ;
    SHAPE ABUTMENT ;
    PORT
      LAYER M3 ;
      RECT 68.463 0.000 68.481 0.054 ;
    END
  END w0_wd_in[554]
  PIN w0_wd_in[555]
    DIRECTION OUTPUT ;
    USE SIGNAL ;
    SHAPE ABUTMENT ;
    PORT
      LAYER M3 ;
      RECT 68.751 0.000 68.769 0.054 ;
    END
  END w0_wd_in[555]
  PIN w0_wd_in[556]
    DIRECTION OUTPUT ;
    USE SIGNAL ;
    SHAPE ABUTMENT ;
    PORT
      LAYER M3 ;
      RECT 69.039 0.000 69.057 0.054 ;
    END
  END w0_wd_in[556]
  PIN w0_wd_in[557]
    DIRECTION OUTPUT ;
    USE SIGNAL ;
    SHAPE ABUTMENT ;
    PORT
      LAYER M3 ;
      RECT 69.327 0.000 69.345 0.054 ;
    END
  END w0_wd_in[557]
  PIN w0_wd_in[558]
    DIRECTION OUTPUT ;
    USE SIGNAL ;
    SHAPE ABUTMENT ;
    PORT
      LAYER M3 ;
      RECT 69.615 0.000 69.633 0.054 ;
    END
  END w0_wd_in[558]
  PIN w0_wd_in[559]
    DIRECTION OUTPUT ;
    USE SIGNAL ;
    SHAPE ABUTMENT ;
    PORT
      LAYER M3 ;
      RECT 69.903 0.000 69.921 0.054 ;
    END
  END w0_wd_in[559]
  PIN w0_wd_in[560]
    DIRECTION OUTPUT ;
    USE SIGNAL ;
    SHAPE ABUTMENT ;
    PORT
      LAYER M3 ;
      RECT 70.191 0.000 70.209 0.054 ;
    END
  END w0_wd_in[560]
  PIN w0_wd_in[561]
    DIRECTION OUTPUT ;
    USE SIGNAL ;
    SHAPE ABUTMENT ;
    PORT
      LAYER M3 ;
      RECT 70.479 0.000 70.497 0.054 ;
    END
  END w0_wd_in[561]
  PIN w0_wd_in[562]
    DIRECTION OUTPUT ;
    USE SIGNAL ;
    SHAPE ABUTMENT ;
    PORT
      LAYER M3 ;
      RECT 70.767 0.000 70.785 0.054 ;
    END
  END w0_wd_in[562]
  PIN w0_wd_in[563]
    DIRECTION OUTPUT ;
    USE SIGNAL ;
    SHAPE ABUTMENT ;
    PORT
      LAYER M3 ;
      RECT 71.055 0.000 71.073 0.054 ;
    END
  END w0_wd_in[563]
  PIN w0_wd_in[564]
    DIRECTION OUTPUT ;
    USE SIGNAL ;
    SHAPE ABUTMENT ;
    PORT
      LAYER M3 ;
      RECT 71.343 0.000 71.361 0.054 ;
    END
  END w0_wd_in[564]
  PIN w0_wd_in[565]
    DIRECTION OUTPUT ;
    USE SIGNAL ;
    SHAPE ABUTMENT ;
    PORT
      LAYER M3 ;
      RECT 71.631 0.000 71.649 0.054 ;
    END
  END w0_wd_in[565]
  PIN w0_wd_in[566]
    DIRECTION OUTPUT ;
    USE SIGNAL ;
    SHAPE ABUTMENT ;
    PORT
      LAYER M3 ;
      RECT 71.919 0.000 71.937 0.054 ;
    END
  END w0_wd_in[566]
  PIN w0_wd_in[567]
    DIRECTION OUTPUT ;
    USE SIGNAL ;
    SHAPE ABUTMENT ;
    PORT
      LAYER M3 ;
      RECT 72.207 0.000 72.225 0.054 ;
    END
  END w0_wd_in[567]
  PIN w0_wd_in[568]
    DIRECTION OUTPUT ;
    USE SIGNAL ;
    SHAPE ABUTMENT ;
    PORT
      LAYER M3 ;
      RECT 72.495 0.000 72.513 0.054 ;
    END
  END w0_wd_in[568]
  PIN w0_wd_in[569]
    DIRECTION OUTPUT ;
    USE SIGNAL ;
    SHAPE ABUTMENT ;
    PORT
      LAYER M3 ;
      RECT 72.783 0.000 72.801 0.054 ;
    END
  END w0_wd_in[569]
  PIN w0_wd_in[570]
    DIRECTION OUTPUT ;
    USE SIGNAL ;
    SHAPE ABUTMENT ;
    PORT
      LAYER M3 ;
      RECT 73.071 0.000 73.089 0.054 ;
    END
  END w0_wd_in[570]
  PIN w0_wd_in[571]
    DIRECTION OUTPUT ;
    USE SIGNAL ;
    SHAPE ABUTMENT ;
    PORT
      LAYER M3 ;
      RECT 73.359 0.000 73.377 0.054 ;
    END
  END w0_wd_in[571]
  PIN w0_wd_in[572]
    DIRECTION OUTPUT ;
    USE SIGNAL ;
    SHAPE ABUTMENT ;
    PORT
      LAYER M3 ;
      RECT 73.647 0.000 73.665 0.054 ;
    END
  END w0_wd_in[572]
  PIN w0_wd_in[573]
    DIRECTION OUTPUT ;
    USE SIGNAL ;
    SHAPE ABUTMENT ;
    PORT
      LAYER M3 ;
      RECT 73.935 0.000 73.953 0.054 ;
    END
  END w0_wd_in[573]
  PIN w0_wd_in[574]
    DIRECTION OUTPUT ;
    USE SIGNAL ;
    SHAPE ABUTMENT ;
    PORT
      LAYER M3 ;
      RECT 74.223 0.000 74.241 0.054 ;
    END
  END w0_wd_in[574]
  PIN w0_wd_in[575]
    DIRECTION OUTPUT ;
    USE SIGNAL ;
    SHAPE ABUTMENT ;
    PORT
      LAYER M3 ;
      RECT 74.511 0.000 74.529 0.054 ;
    END
  END w0_wd_in[575]
  PIN w0_wd_in[576]
    DIRECTION OUTPUT ;
    USE SIGNAL ;
    SHAPE ABUTMENT ;
    PORT
      LAYER M3 ;
      RECT 74.799 0.000 74.817 0.054 ;
    END
  END w0_wd_in[576]
  PIN w0_wd_in[577]
    DIRECTION OUTPUT ;
    USE SIGNAL ;
    SHAPE ABUTMENT ;
    PORT
      LAYER M3 ;
      RECT 75.087 0.000 75.105 0.054 ;
    END
  END w0_wd_in[577]
  PIN w0_wd_in[578]
    DIRECTION OUTPUT ;
    USE SIGNAL ;
    SHAPE ABUTMENT ;
    PORT
      LAYER M3 ;
      RECT 75.375 0.000 75.393 0.054 ;
    END
  END w0_wd_in[578]
  PIN w0_wd_in[579]
    DIRECTION OUTPUT ;
    USE SIGNAL ;
    SHAPE ABUTMENT ;
    PORT
      LAYER M3 ;
      RECT 75.663 0.000 75.681 0.054 ;
    END
  END w0_wd_in[579]
  PIN w0_wd_in[580]
    DIRECTION OUTPUT ;
    USE SIGNAL ;
    SHAPE ABUTMENT ;
    PORT
      LAYER M3 ;
      RECT 75.951 0.000 75.969 0.054 ;
    END
  END w0_wd_in[580]
  PIN w0_wd_in[581]
    DIRECTION OUTPUT ;
    USE SIGNAL ;
    SHAPE ABUTMENT ;
    PORT
      LAYER M3 ;
      RECT 76.239 0.000 76.257 0.054 ;
    END
  END w0_wd_in[581]
  PIN w0_wd_in[582]
    DIRECTION OUTPUT ;
    USE SIGNAL ;
    SHAPE ABUTMENT ;
    PORT
      LAYER M3 ;
      RECT 76.527 0.000 76.545 0.054 ;
    END
  END w0_wd_in[582]
  PIN w0_wd_in[583]
    DIRECTION OUTPUT ;
    USE SIGNAL ;
    SHAPE ABUTMENT ;
    PORT
      LAYER M3 ;
      RECT 76.815 0.000 76.833 0.054 ;
    END
  END w0_wd_in[583]
  PIN w0_wd_in[584]
    DIRECTION OUTPUT ;
    USE SIGNAL ;
    SHAPE ABUTMENT ;
    PORT
      LAYER M3 ;
      RECT 77.103 0.000 77.121 0.054 ;
    END
  END w0_wd_in[584]
  PIN w0_wd_in[585]
    DIRECTION OUTPUT ;
    USE SIGNAL ;
    SHAPE ABUTMENT ;
    PORT
      LAYER M3 ;
      RECT 77.391 0.000 77.409 0.054 ;
    END
  END w0_wd_in[585]
  PIN w0_wd_in[586]
    DIRECTION OUTPUT ;
    USE SIGNAL ;
    SHAPE ABUTMENT ;
    PORT
      LAYER M3 ;
      RECT 77.679 0.000 77.697 0.054 ;
    END
  END w0_wd_in[586]
  PIN w0_wd_in[587]
    DIRECTION OUTPUT ;
    USE SIGNAL ;
    SHAPE ABUTMENT ;
    PORT
      LAYER M3 ;
      RECT 77.967 0.000 77.985 0.054 ;
    END
  END w0_wd_in[587]
  PIN w0_wd_in[588]
    DIRECTION OUTPUT ;
    USE SIGNAL ;
    SHAPE ABUTMENT ;
    PORT
      LAYER M3 ;
      RECT 78.255 0.000 78.273 0.054 ;
    END
  END w0_wd_in[588]
  PIN w0_wd_in[589]
    DIRECTION OUTPUT ;
    USE SIGNAL ;
    SHAPE ABUTMENT ;
    PORT
      LAYER M3 ;
      RECT 78.543 0.000 78.561 0.054 ;
    END
  END w0_wd_in[589]
  PIN w0_wd_in[590]
    DIRECTION OUTPUT ;
    USE SIGNAL ;
    SHAPE ABUTMENT ;
    PORT
      LAYER M3 ;
      RECT 78.831 0.000 78.849 0.054 ;
    END
  END w0_wd_in[590]
  PIN w0_wd_in[591]
    DIRECTION OUTPUT ;
    USE SIGNAL ;
    SHAPE ABUTMENT ;
    PORT
      LAYER M3 ;
      RECT 79.119 0.000 79.137 0.054 ;
    END
  END w0_wd_in[591]
  PIN w0_wd_in[592]
    DIRECTION OUTPUT ;
    USE SIGNAL ;
    SHAPE ABUTMENT ;
    PORT
      LAYER M3 ;
      RECT 79.407 0.000 79.425 0.054 ;
    END
  END w0_wd_in[592]
  PIN w0_wd_in[593]
    DIRECTION OUTPUT ;
    USE SIGNAL ;
    SHAPE ABUTMENT ;
    PORT
      LAYER M3 ;
      RECT 79.695 0.000 79.713 0.054 ;
    END
  END w0_wd_in[593]
  PIN w0_wd_in[594]
    DIRECTION OUTPUT ;
    USE SIGNAL ;
    SHAPE ABUTMENT ;
    PORT
      LAYER M3 ;
      RECT 79.983 0.000 80.001 0.054 ;
    END
  END w0_wd_in[594]
  PIN w0_wd_in[595]
    DIRECTION OUTPUT ;
    USE SIGNAL ;
    SHAPE ABUTMENT ;
    PORT
      LAYER M3 ;
      RECT 80.271 0.000 80.289 0.054 ;
    END
  END w0_wd_in[595]
  PIN w0_wd_in[596]
    DIRECTION OUTPUT ;
    USE SIGNAL ;
    SHAPE ABUTMENT ;
    PORT
      LAYER M3 ;
      RECT 80.559 0.000 80.577 0.054 ;
    END
  END w0_wd_in[596]
  PIN w0_wd_in[597]
    DIRECTION OUTPUT ;
    USE SIGNAL ;
    SHAPE ABUTMENT ;
    PORT
      LAYER M3 ;
      RECT 80.847 0.000 80.865 0.054 ;
    END
  END w0_wd_in[597]
  PIN w0_wd_in[598]
    DIRECTION OUTPUT ;
    USE SIGNAL ;
    SHAPE ABUTMENT ;
    PORT
      LAYER M3 ;
      RECT 81.135 0.000 81.153 0.054 ;
    END
  END w0_wd_in[598]
  PIN w0_wd_in[599]
    DIRECTION OUTPUT ;
    USE SIGNAL ;
    SHAPE ABUTMENT ;
    PORT
      LAYER M3 ;
      RECT 81.423 0.000 81.441 0.054 ;
    END
  END w0_wd_in[599]
  PIN w0_wd_in[600]
    DIRECTION OUTPUT ;
    USE SIGNAL ;
    SHAPE ABUTMENT ;
    PORT
      LAYER M3 ;
      RECT 81.711 0.000 81.729 0.054 ;
    END
  END w0_wd_in[600]
  PIN w0_wd_in[601]
    DIRECTION OUTPUT ;
    USE SIGNAL ;
    SHAPE ABUTMENT ;
    PORT
      LAYER M3 ;
      RECT 81.999 0.000 82.017 0.054 ;
    END
  END w0_wd_in[601]
  PIN w0_wd_in[602]
    DIRECTION OUTPUT ;
    USE SIGNAL ;
    SHAPE ABUTMENT ;
    PORT
      LAYER M3 ;
      RECT 82.287 0.000 82.305 0.054 ;
    END
  END w0_wd_in[602]
  PIN w0_wd_in[603]
    DIRECTION OUTPUT ;
    USE SIGNAL ;
    SHAPE ABUTMENT ;
    PORT
      LAYER M3 ;
      RECT 82.575 0.000 82.593 0.054 ;
    END
  END w0_wd_in[603]
  PIN w0_wd_in[604]
    DIRECTION OUTPUT ;
    USE SIGNAL ;
    SHAPE ABUTMENT ;
    PORT
      LAYER M3 ;
      RECT 82.863 0.000 82.881 0.054 ;
    END
  END w0_wd_in[604]
  PIN w0_wd_in[605]
    DIRECTION OUTPUT ;
    USE SIGNAL ;
    SHAPE ABUTMENT ;
    PORT
      LAYER M3 ;
      RECT 83.151 0.000 83.169 0.054 ;
    END
  END w0_wd_in[605]
  PIN w0_wd_in[606]
    DIRECTION OUTPUT ;
    USE SIGNAL ;
    SHAPE ABUTMENT ;
    PORT
      LAYER M3 ;
      RECT 83.439 0.000 83.457 0.054 ;
    END
  END w0_wd_in[606]
  PIN w0_wd_in[607]
    DIRECTION OUTPUT ;
    USE SIGNAL ;
    SHAPE ABUTMENT ;
    PORT
      LAYER M3 ;
      RECT 83.727 0.000 83.745 0.054 ;
    END
  END w0_wd_in[607]
  PIN w0_wd_in[608]
    DIRECTION OUTPUT ;
    USE SIGNAL ;
    SHAPE ABUTMENT ;
    PORT
      LAYER M3 ;
      RECT 84.015 0.000 84.033 0.054 ;
    END
  END w0_wd_in[608]
  PIN w0_wd_in[609]
    DIRECTION OUTPUT ;
    USE SIGNAL ;
    SHAPE ABUTMENT ;
    PORT
      LAYER M3 ;
      RECT 84.303 0.000 84.321 0.054 ;
    END
  END w0_wd_in[609]
  PIN w0_wd_in[610]
    DIRECTION OUTPUT ;
    USE SIGNAL ;
    SHAPE ABUTMENT ;
    PORT
      LAYER M3 ;
      RECT 84.591 0.000 84.609 0.054 ;
    END
  END w0_wd_in[610]
  PIN w0_wd_in[611]
    DIRECTION OUTPUT ;
    USE SIGNAL ;
    SHAPE ABUTMENT ;
    PORT
      LAYER M3 ;
      RECT 84.879 0.000 84.897 0.054 ;
    END
  END w0_wd_in[611]
  PIN w0_wd_in[612]
    DIRECTION OUTPUT ;
    USE SIGNAL ;
    SHAPE ABUTMENT ;
    PORT
      LAYER M3 ;
      RECT 85.167 0.000 85.185 0.054 ;
    END
  END w0_wd_in[612]
  PIN w0_wd_in[613]
    DIRECTION OUTPUT ;
    USE SIGNAL ;
    SHAPE ABUTMENT ;
    PORT
      LAYER M3 ;
      RECT 85.455 0.000 85.473 0.054 ;
    END
  END w0_wd_in[613]
  PIN w0_wd_in[614]
    DIRECTION OUTPUT ;
    USE SIGNAL ;
    SHAPE ABUTMENT ;
    PORT
      LAYER M3 ;
      RECT 85.743 0.000 85.761 0.054 ;
    END
  END w0_wd_in[614]
  PIN w0_wd_in[615]
    DIRECTION OUTPUT ;
    USE SIGNAL ;
    SHAPE ABUTMENT ;
    PORT
      LAYER M3 ;
      RECT 86.031 0.000 86.049 0.054 ;
    END
  END w0_wd_in[615]
  PIN w0_wd_in[616]
    DIRECTION OUTPUT ;
    USE SIGNAL ;
    SHAPE ABUTMENT ;
    PORT
      LAYER M3 ;
      RECT 86.319 0.000 86.337 0.054 ;
    END
  END w0_wd_in[616]
  PIN w0_wd_in[617]
    DIRECTION OUTPUT ;
    USE SIGNAL ;
    SHAPE ABUTMENT ;
    PORT
      LAYER M3 ;
      RECT 86.607 0.000 86.625 0.054 ;
    END
  END w0_wd_in[617]
  PIN w0_wd_in[618]
    DIRECTION OUTPUT ;
    USE SIGNAL ;
    SHAPE ABUTMENT ;
    PORT
      LAYER M3 ;
      RECT 86.895 0.000 86.913 0.054 ;
    END
  END w0_wd_in[618]
  PIN w0_wd_in[619]
    DIRECTION OUTPUT ;
    USE SIGNAL ;
    SHAPE ABUTMENT ;
    PORT
      LAYER M3 ;
      RECT 87.183 0.000 87.201 0.054 ;
    END
  END w0_wd_in[619]
  PIN w0_wd_in[620]
    DIRECTION OUTPUT ;
    USE SIGNAL ;
    SHAPE ABUTMENT ;
    PORT
      LAYER M3 ;
      RECT 87.471 0.000 87.489 0.054 ;
    END
  END w0_wd_in[620]
  PIN w0_wd_in[621]
    DIRECTION OUTPUT ;
    USE SIGNAL ;
    SHAPE ABUTMENT ;
    PORT
      LAYER M3 ;
      RECT 87.759 0.000 87.777 0.054 ;
    END
  END w0_wd_in[621]
  PIN w0_wd_in[622]
    DIRECTION OUTPUT ;
    USE SIGNAL ;
    SHAPE ABUTMENT ;
    PORT
      LAYER M3 ;
      RECT 88.047 0.000 88.065 0.054 ;
    END
  END w0_wd_in[622]
  PIN w0_wd_in[623]
    DIRECTION OUTPUT ;
    USE SIGNAL ;
    SHAPE ABUTMENT ;
    PORT
      LAYER M3 ;
      RECT 88.335 0.000 88.353 0.054 ;
    END
  END w0_wd_in[623]
  PIN w0_wd_in[624]
    DIRECTION OUTPUT ;
    USE SIGNAL ;
    SHAPE ABUTMENT ;
    PORT
      LAYER M3 ;
      RECT 88.623 0.000 88.641 0.054 ;
    END
  END w0_wd_in[624]
  PIN w0_wd_in[625]
    DIRECTION OUTPUT ;
    USE SIGNAL ;
    SHAPE ABUTMENT ;
    PORT
      LAYER M3 ;
      RECT 88.911 0.000 88.929 0.054 ;
    END
  END w0_wd_in[625]
  PIN w0_wd_in[626]
    DIRECTION OUTPUT ;
    USE SIGNAL ;
    SHAPE ABUTMENT ;
    PORT
      LAYER M3 ;
      RECT 89.199 0.000 89.217 0.054 ;
    END
  END w0_wd_in[626]
  PIN w0_wd_in[627]
    DIRECTION OUTPUT ;
    USE SIGNAL ;
    SHAPE ABUTMENT ;
    PORT
      LAYER M3 ;
      RECT 89.487 0.000 89.505 0.054 ;
    END
  END w0_wd_in[627]
  PIN w0_wd_in[628]
    DIRECTION OUTPUT ;
    USE SIGNAL ;
    SHAPE ABUTMENT ;
    PORT
      LAYER M3 ;
      RECT 89.775 0.000 89.793 0.054 ;
    END
  END w0_wd_in[628]
  PIN w0_wd_in[629]
    DIRECTION OUTPUT ;
    USE SIGNAL ;
    SHAPE ABUTMENT ;
    PORT
      LAYER M3 ;
      RECT 90.063 0.000 90.081 0.054 ;
    END
  END w0_wd_in[629]
  PIN w0_wd_in[630]
    DIRECTION OUTPUT ;
    USE SIGNAL ;
    SHAPE ABUTMENT ;
    PORT
      LAYER M3 ;
      RECT 90.351 0.000 90.369 0.054 ;
    END
  END w0_wd_in[630]
  PIN w0_wd_in[631]
    DIRECTION OUTPUT ;
    USE SIGNAL ;
    SHAPE ABUTMENT ;
    PORT
      LAYER M3 ;
      RECT 90.639 0.000 90.657 0.054 ;
    END
  END w0_wd_in[631]
  PIN w0_wd_in[632]
    DIRECTION OUTPUT ;
    USE SIGNAL ;
    SHAPE ABUTMENT ;
    PORT
      LAYER M3 ;
      RECT 90.927 0.000 90.945 0.054 ;
    END
  END w0_wd_in[632]
  PIN r0_rd_out[0]
    DIRECTION OUTPUT ;
    USE SIGNAL ;
    SHAPE ABUTMENT ;
    PORT
      LAYER M3 ;
      RECT 91.215 0.000 91.233 0.054 ;
    END
  END r0_rd_out[0]
  PIN r0_rd_out[1]
    DIRECTION OUTPUT ;
    USE SIGNAL ;
    SHAPE ABUTMENT ;
    PORT
      LAYER M3 ;
      RECT 91.503 0.000 91.521 0.054 ;
    END
  END r0_rd_out[1]
  PIN r0_rd_out[2]
    DIRECTION OUTPUT ;
    USE SIGNAL ;
    SHAPE ABUTMENT ;
    PORT
      LAYER M3 ;
      RECT 91.791 0.000 91.809 0.054 ;
    END
  END r0_rd_out[2]
  PIN r0_rd_out[3]
    DIRECTION OUTPUT ;
    USE SIGNAL ;
    SHAPE ABUTMENT ;
    PORT
      LAYER M3 ;
      RECT 92.079 0.000 92.097 0.054 ;
    END
  END r0_rd_out[3]
  PIN r0_rd_out[4]
    DIRECTION OUTPUT ;
    USE SIGNAL ;
    SHAPE ABUTMENT ;
    PORT
      LAYER M3 ;
      RECT 92.367 0.000 92.385 0.054 ;
    END
  END r0_rd_out[4]
  PIN r0_rd_out[5]
    DIRECTION OUTPUT ;
    USE SIGNAL ;
    SHAPE ABUTMENT ;
    PORT
      LAYER M3 ;
      RECT 92.655 0.000 92.673 0.054 ;
    END
  END r0_rd_out[5]
  PIN r0_rd_out[6]
    DIRECTION OUTPUT ;
    USE SIGNAL ;
    SHAPE ABUTMENT ;
    PORT
      LAYER M3 ;
      RECT 92.943 0.000 92.961 0.054 ;
    END
  END r0_rd_out[6]
  PIN r0_rd_out[7]
    DIRECTION OUTPUT ;
    USE SIGNAL ;
    SHAPE ABUTMENT ;
    PORT
      LAYER M3 ;
      RECT 93.231 0.000 93.249 0.054 ;
    END
  END r0_rd_out[7]
  PIN r0_rd_out[8]
    DIRECTION OUTPUT ;
    USE SIGNAL ;
    SHAPE ABUTMENT ;
    PORT
      LAYER M3 ;
      RECT 93.519 0.000 93.537 0.054 ;
    END
  END r0_rd_out[8]
  PIN r0_rd_out[9]
    DIRECTION OUTPUT ;
    USE SIGNAL ;
    SHAPE ABUTMENT ;
    PORT
      LAYER M3 ;
      RECT 93.807 0.000 93.825 0.054 ;
    END
  END r0_rd_out[9]
  PIN r0_rd_out[10]
    DIRECTION OUTPUT ;
    USE SIGNAL ;
    SHAPE ABUTMENT ;
    PORT
      LAYER M3 ;
      RECT 94.095 0.000 94.113 0.054 ;
    END
  END r0_rd_out[10]
  PIN r0_rd_out[11]
    DIRECTION OUTPUT ;
    USE SIGNAL ;
    SHAPE ABUTMENT ;
    PORT
      LAYER M3 ;
      RECT 94.383 0.000 94.401 0.054 ;
    END
  END r0_rd_out[11]
  PIN r0_rd_out[12]
    DIRECTION OUTPUT ;
    USE SIGNAL ;
    SHAPE ABUTMENT ;
    PORT
      LAYER M3 ;
      RECT 94.671 0.000 94.689 0.054 ;
    END
  END r0_rd_out[12]
  PIN r0_rd_out[13]
    DIRECTION OUTPUT ;
    USE SIGNAL ;
    SHAPE ABUTMENT ;
    PORT
      LAYER M3 ;
      RECT 94.959 0.000 94.977 0.054 ;
    END
  END r0_rd_out[13]
  PIN r0_rd_out[14]
    DIRECTION OUTPUT ;
    USE SIGNAL ;
    SHAPE ABUTMENT ;
    PORT
      LAYER M3 ;
      RECT 95.247 0.000 95.265 0.054 ;
    END
  END r0_rd_out[14]
  PIN r0_rd_out[15]
    DIRECTION OUTPUT ;
    USE SIGNAL ;
    SHAPE ABUTMENT ;
    PORT
      LAYER M3 ;
      RECT 95.535 0.000 95.553 0.054 ;
    END
  END r0_rd_out[15]
  PIN r0_rd_out[16]
    DIRECTION OUTPUT ;
    USE SIGNAL ;
    SHAPE ABUTMENT ;
    PORT
      LAYER M3 ;
      RECT 95.823 0.000 95.841 0.054 ;
    END
  END r0_rd_out[16]
  PIN r0_rd_out[17]
    DIRECTION OUTPUT ;
    USE SIGNAL ;
    SHAPE ABUTMENT ;
    PORT
      LAYER M3 ;
      RECT 96.111 0.000 96.129 0.054 ;
    END
  END r0_rd_out[17]
  PIN r0_rd_out[18]
    DIRECTION OUTPUT ;
    USE SIGNAL ;
    SHAPE ABUTMENT ;
    PORT
      LAYER M3 ;
      RECT 96.399 0.000 96.417 0.054 ;
    END
  END r0_rd_out[18]
  PIN r0_rd_out[19]
    DIRECTION OUTPUT ;
    USE SIGNAL ;
    SHAPE ABUTMENT ;
    PORT
      LAYER M3 ;
      RECT 96.687 0.000 96.705 0.054 ;
    END
  END r0_rd_out[19]
  PIN r0_rd_out[20]
    DIRECTION OUTPUT ;
    USE SIGNAL ;
    SHAPE ABUTMENT ;
    PORT
      LAYER M3 ;
      RECT 96.975 0.000 96.993 0.054 ;
    END
  END r0_rd_out[20]
  PIN r0_rd_out[21]
    DIRECTION OUTPUT ;
    USE SIGNAL ;
    SHAPE ABUTMENT ;
    PORT
      LAYER M3 ;
      RECT 97.263 0.000 97.281 0.054 ;
    END
  END r0_rd_out[21]
  PIN r0_rd_out[22]
    DIRECTION OUTPUT ;
    USE SIGNAL ;
    SHAPE ABUTMENT ;
    PORT
      LAYER M3 ;
      RECT 97.551 0.000 97.569 0.054 ;
    END
  END r0_rd_out[22]
  PIN r0_rd_out[23]
    DIRECTION OUTPUT ;
    USE SIGNAL ;
    SHAPE ABUTMENT ;
    PORT
      LAYER M3 ;
      RECT 97.839 0.000 97.857 0.054 ;
    END
  END r0_rd_out[23]
  PIN r0_rd_out[24]
    DIRECTION OUTPUT ;
    USE SIGNAL ;
    SHAPE ABUTMENT ;
    PORT
      LAYER M3 ;
      RECT 98.127 0.000 98.145 0.054 ;
    END
  END r0_rd_out[24]
  PIN r0_rd_out[25]
    DIRECTION OUTPUT ;
    USE SIGNAL ;
    SHAPE ABUTMENT ;
    PORT
      LAYER M3 ;
      RECT 98.415 0.000 98.433 0.054 ;
    END
  END r0_rd_out[25]
  PIN r0_rd_out[26]
    DIRECTION OUTPUT ;
    USE SIGNAL ;
    SHAPE ABUTMENT ;
    PORT
      LAYER M3 ;
      RECT 98.703 0.000 98.721 0.054 ;
    END
  END r0_rd_out[26]
  PIN r0_rd_out[27]
    DIRECTION OUTPUT ;
    USE SIGNAL ;
    SHAPE ABUTMENT ;
    PORT
      LAYER M3 ;
      RECT 98.991 0.000 99.009 0.054 ;
    END
  END r0_rd_out[27]
  PIN r0_rd_out[28]
    DIRECTION OUTPUT ;
    USE SIGNAL ;
    SHAPE ABUTMENT ;
    PORT
      LAYER M3 ;
      RECT 99.279 0.000 99.297 0.054 ;
    END
  END r0_rd_out[28]
  PIN r0_rd_out[29]
    DIRECTION OUTPUT ;
    USE SIGNAL ;
    SHAPE ABUTMENT ;
    PORT
      LAYER M3 ;
      RECT 99.567 0.000 99.585 0.054 ;
    END
  END r0_rd_out[29]
  PIN r0_rd_out[30]
    DIRECTION OUTPUT ;
    USE SIGNAL ;
    SHAPE ABUTMENT ;
    PORT
      LAYER M3 ;
      RECT 99.855 0.000 99.873 0.054 ;
    END
  END r0_rd_out[30]
  PIN r0_rd_out[31]
    DIRECTION OUTPUT ;
    USE SIGNAL ;
    SHAPE ABUTMENT ;
    PORT
      LAYER M3 ;
      RECT 100.143 0.000 100.161 0.054 ;
    END
  END r0_rd_out[31]
  PIN r0_rd_out[32]
    DIRECTION OUTPUT ;
    USE SIGNAL ;
    SHAPE ABUTMENT ;
    PORT
      LAYER M3 ;
      RECT 100.431 0.000 100.449 0.054 ;
    END
  END r0_rd_out[32]
  PIN r0_rd_out[33]
    DIRECTION OUTPUT ;
    USE SIGNAL ;
    SHAPE ABUTMENT ;
    PORT
      LAYER M3 ;
      RECT 100.719 0.000 100.737 0.054 ;
    END
  END r0_rd_out[33]
  PIN r0_rd_out[34]
    DIRECTION OUTPUT ;
    USE SIGNAL ;
    SHAPE ABUTMENT ;
    PORT
      LAYER M3 ;
      RECT 101.007 0.000 101.025 0.054 ;
    END
  END r0_rd_out[34]
  PIN r0_rd_out[35]
    DIRECTION OUTPUT ;
    USE SIGNAL ;
    SHAPE ABUTMENT ;
    PORT
      LAYER M3 ;
      RECT 101.295 0.000 101.313 0.054 ;
    END
  END r0_rd_out[35]
  PIN r0_rd_out[36]
    DIRECTION OUTPUT ;
    USE SIGNAL ;
    SHAPE ABUTMENT ;
    PORT
      LAYER M3 ;
      RECT 101.583 0.000 101.601 0.054 ;
    END
  END r0_rd_out[36]
  PIN r0_rd_out[37]
    DIRECTION OUTPUT ;
    USE SIGNAL ;
    SHAPE ABUTMENT ;
    PORT
      LAYER M3 ;
      RECT 101.871 0.000 101.889 0.054 ;
    END
  END r0_rd_out[37]
  PIN r0_rd_out[38]
    DIRECTION OUTPUT ;
    USE SIGNAL ;
    SHAPE ABUTMENT ;
    PORT
      LAYER M3 ;
      RECT 102.159 0.000 102.177 0.054 ;
    END
  END r0_rd_out[38]
  PIN r0_rd_out[39]
    DIRECTION OUTPUT ;
    USE SIGNAL ;
    SHAPE ABUTMENT ;
    PORT
      LAYER M3 ;
      RECT 102.447 0.000 102.465 0.054 ;
    END
  END r0_rd_out[39]
  PIN r0_rd_out[40]
    DIRECTION OUTPUT ;
    USE SIGNAL ;
    SHAPE ABUTMENT ;
    PORT
      LAYER M3 ;
      RECT 102.735 0.000 102.753 0.054 ;
    END
  END r0_rd_out[40]
  PIN r0_rd_out[41]
    DIRECTION OUTPUT ;
    USE SIGNAL ;
    SHAPE ABUTMENT ;
    PORT
      LAYER M3 ;
      RECT 103.023 0.000 103.041 0.054 ;
    END
  END r0_rd_out[41]
  PIN r0_rd_out[42]
    DIRECTION OUTPUT ;
    USE SIGNAL ;
    SHAPE ABUTMENT ;
    PORT
      LAYER M3 ;
      RECT 103.311 0.000 103.329 0.054 ;
    END
  END r0_rd_out[42]
  PIN r0_rd_out[43]
    DIRECTION OUTPUT ;
    USE SIGNAL ;
    SHAPE ABUTMENT ;
    PORT
      LAYER M3 ;
      RECT 103.599 0.000 103.617 0.054 ;
    END
  END r0_rd_out[43]
  PIN r0_rd_out[44]
    DIRECTION OUTPUT ;
    USE SIGNAL ;
    SHAPE ABUTMENT ;
    PORT
      LAYER M3 ;
      RECT 103.887 0.000 103.905 0.054 ;
    END
  END r0_rd_out[44]
  PIN r0_rd_out[45]
    DIRECTION OUTPUT ;
    USE SIGNAL ;
    SHAPE ABUTMENT ;
    PORT
      LAYER M3 ;
      RECT 104.175 0.000 104.193 0.054 ;
    END
  END r0_rd_out[45]
  PIN r0_rd_out[46]
    DIRECTION OUTPUT ;
    USE SIGNAL ;
    SHAPE ABUTMENT ;
    PORT
      LAYER M3 ;
      RECT 104.463 0.000 104.481 0.054 ;
    END
  END r0_rd_out[46]
  PIN r0_rd_out[47]
    DIRECTION OUTPUT ;
    USE SIGNAL ;
    SHAPE ABUTMENT ;
    PORT
      LAYER M3 ;
      RECT 104.751 0.000 104.769 0.054 ;
    END
  END r0_rd_out[47]
  PIN r0_rd_out[48]
    DIRECTION OUTPUT ;
    USE SIGNAL ;
    SHAPE ABUTMENT ;
    PORT
      LAYER M3 ;
      RECT 105.039 0.000 105.057 0.054 ;
    END
  END r0_rd_out[48]
  PIN r0_rd_out[49]
    DIRECTION OUTPUT ;
    USE SIGNAL ;
    SHAPE ABUTMENT ;
    PORT
      LAYER M3 ;
      RECT 105.327 0.000 105.345 0.054 ;
    END
  END r0_rd_out[49]
  PIN r0_rd_out[50]
    DIRECTION OUTPUT ;
    USE SIGNAL ;
    SHAPE ABUTMENT ;
    PORT
      LAYER M3 ;
      RECT 105.615 0.000 105.633 0.054 ;
    END
  END r0_rd_out[50]
  PIN r0_rd_out[51]
    DIRECTION OUTPUT ;
    USE SIGNAL ;
    SHAPE ABUTMENT ;
    PORT
      LAYER M3 ;
      RECT 105.903 0.000 105.921 0.054 ;
    END
  END r0_rd_out[51]
  PIN r0_rd_out[52]
    DIRECTION OUTPUT ;
    USE SIGNAL ;
    SHAPE ABUTMENT ;
    PORT
      LAYER M3 ;
      RECT 106.191 0.000 106.209 0.054 ;
    END
  END r0_rd_out[52]
  PIN r0_rd_out[53]
    DIRECTION OUTPUT ;
    USE SIGNAL ;
    SHAPE ABUTMENT ;
    PORT
      LAYER M3 ;
      RECT 106.479 0.000 106.497 0.054 ;
    END
  END r0_rd_out[53]
  PIN r0_rd_out[54]
    DIRECTION OUTPUT ;
    USE SIGNAL ;
    SHAPE ABUTMENT ;
    PORT
      LAYER M3 ;
      RECT 106.767 0.000 106.785 0.054 ;
    END
  END r0_rd_out[54]
  PIN r0_rd_out[55]
    DIRECTION OUTPUT ;
    USE SIGNAL ;
    SHAPE ABUTMENT ;
    PORT
      LAYER M3 ;
      RECT 107.055 0.000 107.073 0.054 ;
    END
  END r0_rd_out[55]
  PIN r0_rd_out[56]
    DIRECTION OUTPUT ;
    USE SIGNAL ;
    SHAPE ABUTMENT ;
    PORT
      LAYER M3 ;
      RECT 107.343 0.000 107.361 0.054 ;
    END
  END r0_rd_out[56]
  PIN r0_rd_out[57]
    DIRECTION OUTPUT ;
    USE SIGNAL ;
    SHAPE ABUTMENT ;
    PORT
      LAYER M3 ;
      RECT 107.631 0.000 107.649 0.054 ;
    END
  END r0_rd_out[57]
  PIN r0_rd_out[58]
    DIRECTION OUTPUT ;
    USE SIGNAL ;
    SHAPE ABUTMENT ;
    PORT
      LAYER M3 ;
      RECT 107.919 0.000 107.937 0.054 ;
    END
  END r0_rd_out[58]
  PIN r0_rd_out[59]
    DIRECTION OUTPUT ;
    USE SIGNAL ;
    SHAPE ABUTMENT ;
    PORT
      LAYER M3 ;
      RECT 108.207 0.000 108.225 0.054 ;
    END
  END r0_rd_out[59]
  PIN r0_rd_out[60]
    DIRECTION OUTPUT ;
    USE SIGNAL ;
    SHAPE ABUTMENT ;
    PORT
      LAYER M3 ;
      RECT 108.495 0.000 108.513 0.054 ;
    END
  END r0_rd_out[60]
  PIN r0_rd_out[61]
    DIRECTION OUTPUT ;
    USE SIGNAL ;
    SHAPE ABUTMENT ;
    PORT
      LAYER M3 ;
      RECT 108.783 0.000 108.801 0.054 ;
    END
  END r0_rd_out[61]
  PIN r0_rd_out[62]
    DIRECTION OUTPUT ;
    USE SIGNAL ;
    SHAPE ABUTMENT ;
    PORT
      LAYER M3 ;
      RECT 109.071 0.000 109.089 0.054 ;
    END
  END r0_rd_out[62]
  PIN r0_rd_out[63]
    DIRECTION OUTPUT ;
    USE SIGNAL ;
    SHAPE ABUTMENT ;
    PORT
      LAYER M3 ;
      RECT 109.359 0.000 109.377 0.054 ;
    END
  END r0_rd_out[63]
  PIN r0_rd_out[64]
    DIRECTION OUTPUT ;
    USE SIGNAL ;
    SHAPE ABUTMENT ;
    PORT
      LAYER M3 ;
      RECT 109.647 0.000 109.665 0.054 ;
    END
  END r0_rd_out[64]
  PIN r0_rd_out[65]
    DIRECTION OUTPUT ;
    USE SIGNAL ;
    SHAPE ABUTMENT ;
    PORT
      LAYER M3 ;
      RECT 109.935 0.000 109.953 0.054 ;
    END
  END r0_rd_out[65]
  PIN r0_rd_out[66]
    DIRECTION OUTPUT ;
    USE SIGNAL ;
    SHAPE ABUTMENT ;
    PORT
      LAYER M3 ;
      RECT 110.223 0.000 110.241 0.054 ;
    END
  END r0_rd_out[66]
  PIN r0_rd_out[67]
    DIRECTION OUTPUT ;
    USE SIGNAL ;
    SHAPE ABUTMENT ;
    PORT
      LAYER M3 ;
      RECT 110.511 0.000 110.529 0.054 ;
    END
  END r0_rd_out[67]
  PIN r0_rd_out[68]
    DIRECTION OUTPUT ;
    USE SIGNAL ;
    SHAPE ABUTMENT ;
    PORT
      LAYER M3 ;
      RECT 110.799 0.000 110.817 0.054 ;
    END
  END r0_rd_out[68]
  PIN r0_rd_out[69]
    DIRECTION OUTPUT ;
    USE SIGNAL ;
    SHAPE ABUTMENT ;
    PORT
      LAYER M3 ;
      RECT 111.087 0.000 111.105 0.054 ;
    END
  END r0_rd_out[69]
  PIN r0_rd_out[70]
    DIRECTION OUTPUT ;
    USE SIGNAL ;
    SHAPE ABUTMENT ;
    PORT
      LAYER M3 ;
      RECT 111.375 0.000 111.393 0.054 ;
    END
  END r0_rd_out[70]
  PIN r0_rd_out[71]
    DIRECTION OUTPUT ;
    USE SIGNAL ;
    SHAPE ABUTMENT ;
    PORT
      LAYER M3 ;
      RECT 111.663 0.000 111.681 0.054 ;
    END
  END r0_rd_out[71]
  PIN r0_rd_out[72]
    DIRECTION OUTPUT ;
    USE SIGNAL ;
    SHAPE ABUTMENT ;
    PORT
      LAYER M3 ;
      RECT 111.951 0.000 111.969 0.054 ;
    END
  END r0_rd_out[72]
  PIN r0_rd_out[73]
    DIRECTION OUTPUT ;
    USE SIGNAL ;
    SHAPE ABUTMENT ;
    PORT
      LAYER M3 ;
      RECT 112.239 0.000 112.257 0.054 ;
    END
  END r0_rd_out[73]
  PIN r0_rd_out[74]
    DIRECTION OUTPUT ;
    USE SIGNAL ;
    SHAPE ABUTMENT ;
    PORT
      LAYER M3 ;
      RECT 112.527 0.000 112.545 0.054 ;
    END
  END r0_rd_out[74]
  PIN r0_rd_out[75]
    DIRECTION OUTPUT ;
    USE SIGNAL ;
    SHAPE ABUTMENT ;
    PORT
      LAYER M3 ;
      RECT 112.815 0.000 112.833 0.054 ;
    END
  END r0_rd_out[75]
  PIN r0_rd_out[76]
    DIRECTION OUTPUT ;
    USE SIGNAL ;
    SHAPE ABUTMENT ;
    PORT
      LAYER M3 ;
      RECT 113.103 0.000 113.121 0.054 ;
    END
  END r0_rd_out[76]
  PIN r0_rd_out[77]
    DIRECTION OUTPUT ;
    USE SIGNAL ;
    SHAPE ABUTMENT ;
    PORT
      LAYER M3 ;
      RECT 113.391 0.000 113.409 0.054 ;
    END
  END r0_rd_out[77]
  PIN r0_rd_out[78]
    DIRECTION OUTPUT ;
    USE SIGNAL ;
    SHAPE ABUTMENT ;
    PORT
      LAYER M3 ;
      RECT 113.679 0.000 113.697 0.054 ;
    END
  END r0_rd_out[78]
  PIN r0_rd_out[79]
    DIRECTION OUTPUT ;
    USE SIGNAL ;
    SHAPE ABUTMENT ;
    PORT
      LAYER M3 ;
      RECT 113.967 0.000 113.985 0.054 ;
    END
  END r0_rd_out[79]
  PIN r0_rd_out[80]
    DIRECTION OUTPUT ;
    USE SIGNAL ;
    SHAPE ABUTMENT ;
    PORT
      LAYER M3 ;
      RECT 114.255 0.000 114.273 0.054 ;
    END
  END r0_rd_out[80]
  PIN r0_rd_out[81]
    DIRECTION OUTPUT ;
    USE SIGNAL ;
    SHAPE ABUTMENT ;
    PORT
      LAYER M3 ;
      RECT 114.543 0.000 114.561 0.054 ;
    END
  END r0_rd_out[81]
  PIN r0_rd_out[82]
    DIRECTION OUTPUT ;
    USE SIGNAL ;
    SHAPE ABUTMENT ;
    PORT
      LAYER M3 ;
      RECT 114.831 0.000 114.849 0.054 ;
    END
  END r0_rd_out[82]
  PIN r0_rd_out[83]
    DIRECTION OUTPUT ;
    USE SIGNAL ;
    SHAPE ABUTMENT ;
    PORT
      LAYER M3 ;
      RECT 115.119 0.000 115.137 0.054 ;
    END
  END r0_rd_out[83]
  PIN r0_rd_out[84]
    DIRECTION OUTPUT ;
    USE SIGNAL ;
    SHAPE ABUTMENT ;
    PORT
      LAYER M3 ;
      RECT 115.407 0.000 115.425 0.054 ;
    END
  END r0_rd_out[84]
  PIN r0_rd_out[85]
    DIRECTION OUTPUT ;
    USE SIGNAL ;
    SHAPE ABUTMENT ;
    PORT
      LAYER M3 ;
      RECT 115.695 0.000 115.713 0.054 ;
    END
  END r0_rd_out[85]
  PIN r0_rd_out[86]
    DIRECTION OUTPUT ;
    USE SIGNAL ;
    SHAPE ABUTMENT ;
    PORT
      LAYER M3 ;
      RECT 115.983 0.000 116.001 0.054 ;
    END
  END r0_rd_out[86]
  PIN r0_rd_out[87]
    DIRECTION OUTPUT ;
    USE SIGNAL ;
    SHAPE ABUTMENT ;
    PORT
      LAYER M3 ;
      RECT 116.271 0.000 116.289 0.054 ;
    END
  END r0_rd_out[87]
  PIN r0_rd_out[88]
    DIRECTION OUTPUT ;
    USE SIGNAL ;
    SHAPE ABUTMENT ;
    PORT
      LAYER M3 ;
      RECT 116.559 0.000 116.577 0.054 ;
    END
  END r0_rd_out[88]
  PIN r0_rd_out[89]
    DIRECTION OUTPUT ;
    USE SIGNAL ;
    SHAPE ABUTMENT ;
    PORT
      LAYER M3 ;
      RECT 116.847 0.000 116.865 0.054 ;
    END
  END r0_rd_out[89]
  PIN r0_rd_out[90]
    DIRECTION OUTPUT ;
    USE SIGNAL ;
    SHAPE ABUTMENT ;
    PORT
      LAYER M3 ;
      RECT 117.135 0.000 117.153 0.054 ;
    END
  END r0_rd_out[90]
  PIN r0_rd_out[91]
    DIRECTION OUTPUT ;
    USE SIGNAL ;
    SHAPE ABUTMENT ;
    PORT
      LAYER M3 ;
      RECT 117.423 0.000 117.441 0.054 ;
    END
  END r0_rd_out[91]
  PIN r0_rd_out[92]
    DIRECTION OUTPUT ;
    USE SIGNAL ;
    SHAPE ABUTMENT ;
    PORT
      LAYER M3 ;
      RECT 117.711 0.000 117.729 0.054 ;
    END
  END r0_rd_out[92]
  PIN r0_rd_out[93]
    DIRECTION OUTPUT ;
    USE SIGNAL ;
    SHAPE ABUTMENT ;
    PORT
      LAYER M3 ;
      RECT 117.999 0.000 118.017 0.054 ;
    END
  END r0_rd_out[93]
  PIN r0_rd_out[94]
    DIRECTION OUTPUT ;
    USE SIGNAL ;
    SHAPE ABUTMENT ;
    PORT
      LAYER M3 ;
      RECT 118.287 0.000 118.305 0.054 ;
    END
  END r0_rd_out[94]
  PIN r0_rd_out[95]
    DIRECTION OUTPUT ;
    USE SIGNAL ;
    SHAPE ABUTMENT ;
    PORT
      LAYER M3 ;
      RECT 118.575 0.000 118.593 0.054 ;
    END
  END r0_rd_out[95]
  PIN r0_rd_out[96]
    DIRECTION OUTPUT ;
    USE SIGNAL ;
    SHAPE ABUTMENT ;
    PORT
      LAYER M3 ;
      RECT 118.863 0.000 118.881 0.054 ;
    END
  END r0_rd_out[96]
  PIN r0_rd_out[97]
    DIRECTION OUTPUT ;
    USE SIGNAL ;
    SHAPE ABUTMENT ;
    PORT
      LAYER M3 ;
      RECT 119.151 0.000 119.169 0.054 ;
    END
  END r0_rd_out[97]
  PIN r0_rd_out[98]
    DIRECTION OUTPUT ;
    USE SIGNAL ;
    SHAPE ABUTMENT ;
    PORT
      LAYER M3 ;
      RECT 119.439 0.000 119.457 0.054 ;
    END
  END r0_rd_out[98]
  PIN r0_rd_out[99]
    DIRECTION OUTPUT ;
    USE SIGNAL ;
    SHAPE ABUTMENT ;
    PORT
      LAYER M3 ;
      RECT 119.727 0.000 119.745 0.054 ;
    END
  END r0_rd_out[99]
  PIN r0_rd_out[100]
    DIRECTION OUTPUT ;
    USE SIGNAL ;
    SHAPE ABUTMENT ;
    PORT
      LAYER M3 ;
      RECT 120.015 0.000 120.033 0.054 ;
    END
  END r0_rd_out[100]
  PIN r0_rd_out[101]
    DIRECTION OUTPUT ;
    USE SIGNAL ;
    SHAPE ABUTMENT ;
    PORT
      LAYER M3 ;
      RECT 120.303 0.000 120.321 0.054 ;
    END
  END r0_rd_out[101]
  PIN r0_rd_out[102]
    DIRECTION OUTPUT ;
    USE SIGNAL ;
    SHAPE ABUTMENT ;
    PORT
      LAYER M3 ;
      RECT 120.591 0.000 120.609 0.054 ;
    END
  END r0_rd_out[102]
  PIN r0_rd_out[103]
    DIRECTION OUTPUT ;
    USE SIGNAL ;
    SHAPE ABUTMENT ;
    PORT
      LAYER M3 ;
      RECT 120.879 0.000 120.897 0.054 ;
    END
  END r0_rd_out[103]
  PIN r0_rd_out[104]
    DIRECTION OUTPUT ;
    USE SIGNAL ;
    SHAPE ABUTMENT ;
    PORT
      LAYER M3 ;
      RECT 121.167 0.000 121.185 0.054 ;
    END
  END r0_rd_out[104]
  PIN r0_rd_out[105]
    DIRECTION OUTPUT ;
    USE SIGNAL ;
    SHAPE ABUTMENT ;
    PORT
      LAYER M3 ;
      RECT 121.455 0.000 121.473 0.054 ;
    END
  END r0_rd_out[105]
  PIN r0_rd_out[106]
    DIRECTION OUTPUT ;
    USE SIGNAL ;
    SHAPE ABUTMENT ;
    PORT
      LAYER M3 ;
      RECT 121.743 0.000 121.761 0.054 ;
    END
  END r0_rd_out[106]
  PIN r0_rd_out[107]
    DIRECTION OUTPUT ;
    USE SIGNAL ;
    SHAPE ABUTMENT ;
    PORT
      LAYER M3 ;
      RECT 122.031 0.000 122.049 0.054 ;
    END
  END r0_rd_out[107]
  PIN r0_rd_out[108]
    DIRECTION OUTPUT ;
    USE SIGNAL ;
    SHAPE ABUTMENT ;
    PORT
      LAYER M3 ;
      RECT 122.319 0.000 122.337 0.054 ;
    END
  END r0_rd_out[108]
  PIN r0_rd_out[109]
    DIRECTION OUTPUT ;
    USE SIGNAL ;
    SHAPE ABUTMENT ;
    PORT
      LAYER M3 ;
      RECT 122.607 0.000 122.625 0.054 ;
    END
  END r0_rd_out[109]
  PIN r0_rd_out[110]
    DIRECTION OUTPUT ;
    USE SIGNAL ;
    SHAPE ABUTMENT ;
    PORT
      LAYER M3 ;
      RECT 122.895 0.000 122.913 0.054 ;
    END
  END r0_rd_out[110]
  PIN r0_rd_out[111]
    DIRECTION OUTPUT ;
    USE SIGNAL ;
    SHAPE ABUTMENT ;
    PORT
      LAYER M3 ;
      RECT 123.183 0.000 123.201 0.054 ;
    END
  END r0_rd_out[111]
  PIN r0_rd_out[112]
    DIRECTION OUTPUT ;
    USE SIGNAL ;
    SHAPE ABUTMENT ;
    PORT
      LAYER M3 ;
      RECT 123.471 0.000 123.489 0.054 ;
    END
  END r0_rd_out[112]
  PIN r0_rd_out[113]
    DIRECTION OUTPUT ;
    USE SIGNAL ;
    SHAPE ABUTMENT ;
    PORT
      LAYER M3 ;
      RECT 123.759 0.000 123.777 0.054 ;
    END
  END r0_rd_out[113]
  PIN r0_rd_out[114]
    DIRECTION OUTPUT ;
    USE SIGNAL ;
    SHAPE ABUTMENT ;
    PORT
      LAYER M3 ;
      RECT 124.047 0.000 124.065 0.054 ;
    END
  END r0_rd_out[114]
  PIN r0_rd_out[115]
    DIRECTION OUTPUT ;
    USE SIGNAL ;
    SHAPE ABUTMENT ;
    PORT
      LAYER M3 ;
      RECT 124.335 0.000 124.353 0.054 ;
    END
  END r0_rd_out[115]
  PIN r0_rd_out[116]
    DIRECTION OUTPUT ;
    USE SIGNAL ;
    SHAPE ABUTMENT ;
    PORT
      LAYER M3 ;
      RECT 124.623 0.000 124.641 0.054 ;
    END
  END r0_rd_out[116]
  PIN r0_rd_out[117]
    DIRECTION OUTPUT ;
    USE SIGNAL ;
    SHAPE ABUTMENT ;
    PORT
      LAYER M3 ;
      RECT 124.911 0.000 124.929 0.054 ;
    END
  END r0_rd_out[117]
  PIN r0_rd_out[118]
    DIRECTION OUTPUT ;
    USE SIGNAL ;
    SHAPE ABUTMENT ;
    PORT
      LAYER M3 ;
      RECT 125.199 0.000 125.217 0.054 ;
    END
  END r0_rd_out[118]
  PIN r0_rd_out[119]
    DIRECTION OUTPUT ;
    USE SIGNAL ;
    SHAPE ABUTMENT ;
    PORT
      LAYER M3 ;
      RECT 125.487 0.000 125.505 0.054 ;
    END
  END r0_rd_out[119]
  PIN r0_rd_out[120]
    DIRECTION OUTPUT ;
    USE SIGNAL ;
    SHAPE ABUTMENT ;
    PORT
      LAYER M3 ;
      RECT 125.775 0.000 125.793 0.054 ;
    END
  END r0_rd_out[120]
  PIN r0_rd_out[121]
    DIRECTION OUTPUT ;
    USE SIGNAL ;
    SHAPE ABUTMENT ;
    PORT
      LAYER M3 ;
      RECT 126.063 0.000 126.081 0.054 ;
    END
  END r0_rd_out[121]
  PIN r0_rd_out[122]
    DIRECTION OUTPUT ;
    USE SIGNAL ;
    SHAPE ABUTMENT ;
    PORT
      LAYER M3 ;
      RECT 126.351 0.000 126.369 0.054 ;
    END
  END r0_rd_out[122]
  PIN r0_rd_out[123]
    DIRECTION OUTPUT ;
    USE SIGNAL ;
    SHAPE ABUTMENT ;
    PORT
      LAYER M3 ;
      RECT 126.639 0.000 126.657 0.054 ;
    END
  END r0_rd_out[123]
  PIN r0_rd_out[124]
    DIRECTION OUTPUT ;
    USE SIGNAL ;
    SHAPE ABUTMENT ;
    PORT
      LAYER M3 ;
      RECT 126.927 0.000 126.945 0.054 ;
    END
  END r0_rd_out[124]
  PIN r0_rd_out[125]
    DIRECTION OUTPUT ;
    USE SIGNAL ;
    SHAPE ABUTMENT ;
    PORT
      LAYER M3 ;
      RECT 127.215 0.000 127.233 0.054 ;
    END
  END r0_rd_out[125]
  PIN r0_rd_out[126]
    DIRECTION OUTPUT ;
    USE SIGNAL ;
    SHAPE ABUTMENT ;
    PORT
      LAYER M3 ;
      RECT 127.503 0.000 127.521 0.054 ;
    END
  END r0_rd_out[126]
  PIN r0_rd_out[127]
    DIRECTION OUTPUT ;
    USE SIGNAL ;
    SHAPE ABUTMENT ;
    PORT
      LAYER M3 ;
      RECT 127.791 0.000 127.809 0.054 ;
    END
  END r0_rd_out[127]
  PIN r0_rd_out[128]
    DIRECTION OUTPUT ;
    USE SIGNAL ;
    SHAPE ABUTMENT ;
    PORT
      LAYER M3 ;
      RECT 128.079 0.000 128.097 0.054 ;
    END
  END r0_rd_out[128]
  PIN r0_rd_out[129]
    DIRECTION OUTPUT ;
    USE SIGNAL ;
    SHAPE ABUTMENT ;
    PORT
      LAYER M3 ;
      RECT 128.367 0.000 128.385 0.054 ;
    END
  END r0_rd_out[129]
  PIN r0_rd_out[130]
    DIRECTION OUTPUT ;
    USE SIGNAL ;
    SHAPE ABUTMENT ;
    PORT
      LAYER M3 ;
      RECT 128.655 0.000 128.673 0.054 ;
    END
  END r0_rd_out[130]
  PIN r0_rd_out[131]
    DIRECTION OUTPUT ;
    USE SIGNAL ;
    SHAPE ABUTMENT ;
    PORT
      LAYER M3 ;
      RECT 128.943 0.000 128.961 0.054 ;
    END
  END r0_rd_out[131]
  PIN r0_rd_out[132]
    DIRECTION OUTPUT ;
    USE SIGNAL ;
    SHAPE ABUTMENT ;
    PORT
      LAYER M3 ;
      RECT 129.231 0.000 129.249 0.054 ;
    END
  END r0_rd_out[132]
  PIN r0_rd_out[133]
    DIRECTION OUTPUT ;
    USE SIGNAL ;
    SHAPE ABUTMENT ;
    PORT
      LAYER M3 ;
      RECT 129.519 0.000 129.537 0.054 ;
    END
  END r0_rd_out[133]
  PIN r0_rd_out[134]
    DIRECTION OUTPUT ;
    USE SIGNAL ;
    SHAPE ABUTMENT ;
    PORT
      LAYER M3 ;
      RECT 129.807 0.000 129.825 0.054 ;
    END
  END r0_rd_out[134]
  PIN r0_rd_out[135]
    DIRECTION OUTPUT ;
    USE SIGNAL ;
    SHAPE ABUTMENT ;
    PORT
      LAYER M3 ;
      RECT 130.095 0.000 130.113 0.054 ;
    END
  END r0_rd_out[135]
  PIN r0_rd_out[136]
    DIRECTION OUTPUT ;
    USE SIGNAL ;
    SHAPE ABUTMENT ;
    PORT
      LAYER M3 ;
      RECT 130.383 0.000 130.401 0.054 ;
    END
  END r0_rd_out[136]
  PIN r0_rd_out[137]
    DIRECTION OUTPUT ;
    USE SIGNAL ;
    SHAPE ABUTMENT ;
    PORT
      LAYER M3 ;
      RECT 130.671 0.000 130.689 0.054 ;
    END
  END r0_rd_out[137]
  PIN r0_rd_out[138]
    DIRECTION OUTPUT ;
    USE SIGNAL ;
    SHAPE ABUTMENT ;
    PORT
      LAYER M3 ;
      RECT 130.959 0.000 130.977 0.054 ;
    END
  END r0_rd_out[138]
  PIN r0_rd_out[139]
    DIRECTION OUTPUT ;
    USE SIGNAL ;
    SHAPE ABUTMENT ;
    PORT
      LAYER M3 ;
      RECT 131.247 0.000 131.265 0.054 ;
    END
  END r0_rd_out[139]
  PIN r0_rd_out[140]
    DIRECTION OUTPUT ;
    USE SIGNAL ;
    SHAPE ABUTMENT ;
    PORT
      LAYER M3 ;
      RECT 131.535 0.000 131.553 0.054 ;
    END
  END r0_rd_out[140]
  PIN r0_rd_out[141]
    DIRECTION OUTPUT ;
    USE SIGNAL ;
    SHAPE ABUTMENT ;
    PORT
      LAYER M3 ;
      RECT 131.823 0.000 131.841 0.054 ;
    END
  END r0_rd_out[141]
  PIN r0_rd_out[142]
    DIRECTION OUTPUT ;
    USE SIGNAL ;
    SHAPE ABUTMENT ;
    PORT
      LAYER M3 ;
      RECT 132.111 0.000 132.129 0.054 ;
    END
  END r0_rd_out[142]
  PIN r0_rd_out[143]
    DIRECTION OUTPUT ;
    USE SIGNAL ;
    SHAPE ABUTMENT ;
    PORT
      LAYER M3 ;
      RECT 132.399 0.000 132.417 0.054 ;
    END
  END r0_rd_out[143]
  PIN r0_rd_out[144]
    DIRECTION OUTPUT ;
    USE SIGNAL ;
    SHAPE ABUTMENT ;
    PORT
      LAYER M3 ;
      RECT 132.687 0.000 132.705 0.054 ;
    END
  END r0_rd_out[144]
  PIN r0_rd_out[145]
    DIRECTION OUTPUT ;
    USE SIGNAL ;
    SHAPE ABUTMENT ;
    PORT
      LAYER M3 ;
      RECT 132.975 0.000 132.993 0.054 ;
    END
  END r0_rd_out[145]
  PIN r0_rd_out[146]
    DIRECTION OUTPUT ;
    USE SIGNAL ;
    SHAPE ABUTMENT ;
    PORT
      LAYER M3 ;
      RECT 133.263 0.000 133.281 0.054 ;
    END
  END r0_rd_out[146]
  PIN r0_rd_out[147]
    DIRECTION OUTPUT ;
    USE SIGNAL ;
    SHAPE ABUTMENT ;
    PORT
      LAYER M3 ;
      RECT 133.551 0.000 133.569 0.054 ;
    END
  END r0_rd_out[147]
  PIN r0_rd_out[148]
    DIRECTION OUTPUT ;
    USE SIGNAL ;
    SHAPE ABUTMENT ;
    PORT
      LAYER M3 ;
      RECT 133.839 0.000 133.857 0.054 ;
    END
  END r0_rd_out[148]
  PIN r0_rd_out[149]
    DIRECTION OUTPUT ;
    USE SIGNAL ;
    SHAPE ABUTMENT ;
    PORT
      LAYER M3 ;
      RECT 134.127 0.000 134.145 0.054 ;
    END
  END r0_rd_out[149]
  PIN r0_rd_out[150]
    DIRECTION OUTPUT ;
    USE SIGNAL ;
    SHAPE ABUTMENT ;
    PORT
      LAYER M3 ;
      RECT 134.415 0.000 134.433 0.054 ;
    END
  END r0_rd_out[150]
  PIN r0_rd_out[151]
    DIRECTION OUTPUT ;
    USE SIGNAL ;
    SHAPE ABUTMENT ;
    PORT
      LAYER M3 ;
      RECT 134.703 0.000 134.721 0.054 ;
    END
  END r0_rd_out[151]
  PIN r0_rd_out[152]
    DIRECTION OUTPUT ;
    USE SIGNAL ;
    SHAPE ABUTMENT ;
    PORT
      LAYER M3 ;
      RECT 134.991 0.000 135.009 0.054 ;
    END
  END r0_rd_out[152]
  PIN r0_rd_out[153]
    DIRECTION OUTPUT ;
    USE SIGNAL ;
    SHAPE ABUTMENT ;
    PORT
      LAYER M3 ;
      RECT 135.279 0.000 135.297 0.054 ;
    END
  END r0_rd_out[153]
  PIN r0_rd_out[154]
    DIRECTION OUTPUT ;
    USE SIGNAL ;
    SHAPE ABUTMENT ;
    PORT
      LAYER M3 ;
      RECT 135.567 0.000 135.585 0.054 ;
    END
  END r0_rd_out[154]
  PIN r0_rd_out[155]
    DIRECTION OUTPUT ;
    USE SIGNAL ;
    SHAPE ABUTMENT ;
    PORT
      LAYER M3 ;
      RECT 135.855 0.000 135.873 0.054 ;
    END
  END r0_rd_out[155]
  PIN r0_rd_out[156]
    DIRECTION OUTPUT ;
    USE SIGNAL ;
    SHAPE ABUTMENT ;
    PORT
      LAYER M3 ;
      RECT 136.143 0.000 136.161 0.054 ;
    END
  END r0_rd_out[156]
  PIN r0_rd_out[157]
    DIRECTION OUTPUT ;
    USE SIGNAL ;
    SHAPE ABUTMENT ;
    PORT
      LAYER M3 ;
      RECT 136.431 0.000 136.449 0.054 ;
    END
  END r0_rd_out[157]
  PIN r0_rd_out[158]
    DIRECTION OUTPUT ;
    USE SIGNAL ;
    SHAPE ABUTMENT ;
    PORT
      LAYER M3 ;
      RECT 136.719 0.000 136.737 0.054 ;
    END
  END r0_rd_out[158]
  PIN r0_rd_out[159]
    DIRECTION OUTPUT ;
    USE SIGNAL ;
    SHAPE ABUTMENT ;
    PORT
      LAYER M3 ;
      RECT 137.007 0.000 137.025 0.054 ;
    END
  END r0_rd_out[159]
  PIN r0_rd_out[160]
    DIRECTION OUTPUT ;
    USE SIGNAL ;
    SHAPE ABUTMENT ;
    PORT
      LAYER M3 ;
      RECT 137.295 0.000 137.313 0.054 ;
    END
  END r0_rd_out[160]
  PIN r0_rd_out[161]
    DIRECTION OUTPUT ;
    USE SIGNAL ;
    SHAPE ABUTMENT ;
    PORT
      LAYER M3 ;
      RECT 137.583 0.000 137.601 0.054 ;
    END
  END r0_rd_out[161]
  PIN r0_rd_out[162]
    DIRECTION OUTPUT ;
    USE SIGNAL ;
    SHAPE ABUTMENT ;
    PORT
      LAYER M3 ;
      RECT 137.871 0.000 137.889 0.054 ;
    END
  END r0_rd_out[162]
  PIN r0_rd_out[163]
    DIRECTION OUTPUT ;
    USE SIGNAL ;
    SHAPE ABUTMENT ;
    PORT
      LAYER M3 ;
      RECT 138.159 0.000 138.177 0.054 ;
    END
  END r0_rd_out[163]
  PIN r0_rd_out[164]
    DIRECTION OUTPUT ;
    USE SIGNAL ;
    SHAPE ABUTMENT ;
    PORT
      LAYER M3 ;
      RECT 138.447 0.000 138.465 0.054 ;
    END
  END r0_rd_out[164]
  PIN r0_rd_out[165]
    DIRECTION OUTPUT ;
    USE SIGNAL ;
    SHAPE ABUTMENT ;
    PORT
      LAYER M3 ;
      RECT 138.735 0.000 138.753 0.054 ;
    END
  END r0_rd_out[165]
  PIN r0_rd_out[166]
    DIRECTION OUTPUT ;
    USE SIGNAL ;
    SHAPE ABUTMENT ;
    PORT
      LAYER M3 ;
      RECT 139.023 0.000 139.041 0.054 ;
    END
  END r0_rd_out[166]
  PIN r0_rd_out[167]
    DIRECTION OUTPUT ;
    USE SIGNAL ;
    SHAPE ABUTMENT ;
    PORT
      LAYER M3 ;
      RECT 139.311 0.000 139.329 0.054 ;
    END
  END r0_rd_out[167]
  PIN r0_rd_out[168]
    DIRECTION OUTPUT ;
    USE SIGNAL ;
    SHAPE ABUTMENT ;
    PORT
      LAYER M3 ;
      RECT 139.599 0.000 139.617 0.054 ;
    END
  END r0_rd_out[168]
  PIN r0_rd_out[169]
    DIRECTION OUTPUT ;
    USE SIGNAL ;
    SHAPE ABUTMENT ;
    PORT
      LAYER M3 ;
      RECT 139.887 0.000 139.905 0.054 ;
    END
  END r0_rd_out[169]
  PIN r0_rd_out[170]
    DIRECTION OUTPUT ;
    USE SIGNAL ;
    SHAPE ABUTMENT ;
    PORT
      LAYER M3 ;
      RECT 140.175 0.000 140.193 0.054 ;
    END
  END r0_rd_out[170]
  PIN r0_rd_out[171]
    DIRECTION OUTPUT ;
    USE SIGNAL ;
    SHAPE ABUTMENT ;
    PORT
      LAYER M3 ;
      RECT 140.463 0.000 140.481 0.054 ;
    END
  END r0_rd_out[171]
  PIN r0_rd_out[172]
    DIRECTION OUTPUT ;
    USE SIGNAL ;
    SHAPE ABUTMENT ;
    PORT
      LAYER M3 ;
      RECT 140.751 0.000 140.769 0.054 ;
    END
  END r0_rd_out[172]
  PIN r0_rd_out[173]
    DIRECTION OUTPUT ;
    USE SIGNAL ;
    SHAPE ABUTMENT ;
    PORT
      LAYER M3 ;
      RECT 141.039 0.000 141.057 0.054 ;
    END
  END r0_rd_out[173]
  PIN r0_rd_out[174]
    DIRECTION OUTPUT ;
    USE SIGNAL ;
    SHAPE ABUTMENT ;
    PORT
      LAYER M3 ;
      RECT 141.327 0.000 141.345 0.054 ;
    END
  END r0_rd_out[174]
  PIN r0_rd_out[175]
    DIRECTION OUTPUT ;
    USE SIGNAL ;
    SHAPE ABUTMENT ;
    PORT
      LAYER M3 ;
      RECT 141.615 0.000 141.633 0.054 ;
    END
  END r0_rd_out[175]
  PIN r0_rd_out[176]
    DIRECTION OUTPUT ;
    USE SIGNAL ;
    SHAPE ABUTMENT ;
    PORT
      LAYER M3 ;
      RECT 141.903 0.000 141.921 0.054 ;
    END
  END r0_rd_out[176]
  PIN r0_rd_out[177]
    DIRECTION OUTPUT ;
    USE SIGNAL ;
    SHAPE ABUTMENT ;
    PORT
      LAYER M3 ;
      RECT 142.191 0.000 142.209 0.054 ;
    END
  END r0_rd_out[177]
  PIN r0_rd_out[178]
    DIRECTION OUTPUT ;
    USE SIGNAL ;
    SHAPE ABUTMENT ;
    PORT
      LAYER M3 ;
      RECT 142.479 0.000 142.497 0.054 ;
    END
  END r0_rd_out[178]
  PIN r0_rd_out[179]
    DIRECTION OUTPUT ;
    USE SIGNAL ;
    SHAPE ABUTMENT ;
    PORT
      LAYER M3 ;
      RECT 142.767 0.000 142.785 0.054 ;
    END
  END r0_rd_out[179]
  PIN r0_rd_out[180]
    DIRECTION OUTPUT ;
    USE SIGNAL ;
    SHAPE ABUTMENT ;
    PORT
      LAYER M3 ;
      RECT 143.055 0.000 143.073 0.054 ;
    END
  END r0_rd_out[180]
  PIN r0_rd_out[181]
    DIRECTION OUTPUT ;
    USE SIGNAL ;
    SHAPE ABUTMENT ;
    PORT
      LAYER M3 ;
      RECT 143.343 0.000 143.361 0.054 ;
    END
  END r0_rd_out[181]
  PIN r0_rd_out[182]
    DIRECTION OUTPUT ;
    USE SIGNAL ;
    SHAPE ABUTMENT ;
    PORT
      LAYER M3 ;
      RECT 143.631 0.000 143.649 0.054 ;
    END
  END r0_rd_out[182]
  PIN r0_rd_out[183]
    DIRECTION OUTPUT ;
    USE SIGNAL ;
    SHAPE ABUTMENT ;
    PORT
      LAYER M3 ;
      RECT 143.919 0.000 143.937 0.054 ;
    END
  END r0_rd_out[183]
  PIN r0_rd_out[184]
    DIRECTION OUTPUT ;
    USE SIGNAL ;
    SHAPE ABUTMENT ;
    PORT
      LAYER M3 ;
      RECT 144.207 0.000 144.225 0.054 ;
    END
  END r0_rd_out[184]
  PIN r0_rd_out[185]
    DIRECTION OUTPUT ;
    USE SIGNAL ;
    SHAPE ABUTMENT ;
    PORT
      LAYER M3 ;
      RECT 144.495 0.000 144.513 0.054 ;
    END
  END r0_rd_out[185]
  PIN r0_rd_out[186]
    DIRECTION OUTPUT ;
    USE SIGNAL ;
    SHAPE ABUTMENT ;
    PORT
      LAYER M3 ;
      RECT 144.783 0.000 144.801 0.054 ;
    END
  END r0_rd_out[186]
  PIN r0_rd_out[187]
    DIRECTION OUTPUT ;
    USE SIGNAL ;
    SHAPE ABUTMENT ;
    PORT
      LAYER M3 ;
      RECT 145.071 0.000 145.089 0.054 ;
    END
  END r0_rd_out[187]
  PIN r0_rd_out[188]
    DIRECTION OUTPUT ;
    USE SIGNAL ;
    SHAPE ABUTMENT ;
    PORT
      LAYER M3 ;
      RECT 145.359 0.000 145.377 0.054 ;
    END
  END r0_rd_out[188]
  PIN r0_rd_out[189]
    DIRECTION OUTPUT ;
    USE SIGNAL ;
    SHAPE ABUTMENT ;
    PORT
      LAYER M3 ;
      RECT 145.647 0.000 145.665 0.054 ;
    END
  END r0_rd_out[189]
  PIN r0_rd_out[190]
    DIRECTION OUTPUT ;
    USE SIGNAL ;
    SHAPE ABUTMENT ;
    PORT
      LAYER M3 ;
      RECT 145.935 0.000 145.953 0.054 ;
    END
  END r0_rd_out[190]
  PIN r0_rd_out[191]
    DIRECTION OUTPUT ;
    USE SIGNAL ;
    SHAPE ABUTMENT ;
    PORT
      LAYER M3 ;
      RECT 146.223 0.000 146.241 0.054 ;
    END
  END r0_rd_out[191]
  PIN r0_rd_out[192]
    DIRECTION OUTPUT ;
    USE SIGNAL ;
    SHAPE ABUTMENT ;
    PORT
      LAYER M3 ;
      RECT 146.511 0.000 146.529 0.054 ;
    END
  END r0_rd_out[192]
  PIN r0_rd_out[193]
    DIRECTION OUTPUT ;
    USE SIGNAL ;
    SHAPE ABUTMENT ;
    PORT
      LAYER M3 ;
      RECT 146.799 0.000 146.817 0.054 ;
    END
  END r0_rd_out[193]
  PIN r0_rd_out[194]
    DIRECTION OUTPUT ;
    USE SIGNAL ;
    SHAPE ABUTMENT ;
    PORT
      LAYER M3 ;
      RECT 147.087 0.000 147.105 0.054 ;
    END
  END r0_rd_out[194]
  PIN r0_rd_out[195]
    DIRECTION OUTPUT ;
    USE SIGNAL ;
    SHAPE ABUTMENT ;
    PORT
      LAYER M3 ;
      RECT 147.375 0.000 147.393 0.054 ;
    END
  END r0_rd_out[195]
  PIN r0_rd_out[196]
    DIRECTION OUTPUT ;
    USE SIGNAL ;
    SHAPE ABUTMENT ;
    PORT
      LAYER M3 ;
      RECT 147.663 0.000 147.681 0.054 ;
    END
  END r0_rd_out[196]
  PIN r0_rd_out[197]
    DIRECTION OUTPUT ;
    USE SIGNAL ;
    SHAPE ABUTMENT ;
    PORT
      LAYER M3 ;
      RECT 147.951 0.000 147.969 0.054 ;
    END
  END r0_rd_out[197]
  PIN r0_rd_out[198]
    DIRECTION OUTPUT ;
    USE SIGNAL ;
    SHAPE ABUTMENT ;
    PORT
      LAYER M3 ;
      RECT 148.239 0.000 148.257 0.054 ;
    END
  END r0_rd_out[198]
  PIN r0_rd_out[199]
    DIRECTION OUTPUT ;
    USE SIGNAL ;
    SHAPE ABUTMENT ;
    PORT
      LAYER M3 ;
      RECT 148.527 0.000 148.545 0.054 ;
    END
  END r0_rd_out[199]
  PIN r0_rd_out[200]
    DIRECTION OUTPUT ;
    USE SIGNAL ;
    SHAPE ABUTMENT ;
    PORT
      LAYER M3 ;
      RECT 148.815 0.000 148.833 0.054 ;
    END
  END r0_rd_out[200]
  PIN r0_rd_out[201]
    DIRECTION OUTPUT ;
    USE SIGNAL ;
    SHAPE ABUTMENT ;
    PORT
      LAYER M3 ;
      RECT 149.103 0.000 149.121 0.054 ;
    END
  END r0_rd_out[201]
  PIN r0_rd_out[202]
    DIRECTION OUTPUT ;
    USE SIGNAL ;
    SHAPE ABUTMENT ;
    PORT
      LAYER M3 ;
      RECT 149.391 0.000 149.409 0.054 ;
    END
  END r0_rd_out[202]
  PIN r0_rd_out[203]
    DIRECTION OUTPUT ;
    USE SIGNAL ;
    SHAPE ABUTMENT ;
    PORT
      LAYER M3 ;
      RECT 149.679 0.000 149.697 0.054 ;
    END
  END r0_rd_out[203]
  PIN r0_rd_out[204]
    DIRECTION OUTPUT ;
    USE SIGNAL ;
    SHAPE ABUTMENT ;
    PORT
      LAYER M3 ;
      RECT 149.967 0.000 149.985 0.054 ;
    END
  END r0_rd_out[204]
  PIN r0_rd_out[205]
    DIRECTION OUTPUT ;
    USE SIGNAL ;
    SHAPE ABUTMENT ;
    PORT
      LAYER M3 ;
      RECT 150.255 0.000 150.273 0.054 ;
    END
  END r0_rd_out[205]
  PIN r0_rd_out[206]
    DIRECTION OUTPUT ;
    USE SIGNAL ;
    SHAPE ABUTMENT ;
    PORT
      LAYER M3 ;
      RECT 150.543 0.000 150.561 0.054 ;
    END
  END r0_rd_out[206]
  PIN r0_rd_out[207]
    DIRECTION OUTPUT ;
    USE SIGNAL ;
    SHAPE ABUTMENT ;
    PORT
      LAYER M3 ;
      RECT 150.831 0.000 150.849 0.054 ;
    END
  END r0_rd_out[207]
  PIN r0_rd_out[208]
    DIRECTION OUTPUT ;
    USE SIGNAL ;
    SHAPE ABUTMENT ;
    PORT
      LAYER M3 ;
      RECT 151.119 0.000 151.137 0.054 ;
    END
  END r0_rd_out[208]
  PIN r0_rd_out[209]
    DIRECTION OUTPUT ;
    USE SIGNAL ;
    SHAPE ABUTMENT ;
    PORT
      LAYER M3 ;
      RECT 151.407 0.000 151.425 0.054 ;
    END
  END r0_rd_out[209]
  PIN r0_rd_out[210]
    DIRECTION OUTPUT ;
    USE SIGNAL ;
    SHAPE ABUTMENT ;
    PORT
      LAYER M3 ;
      RECT 151.695 0.000 151.713 0.054 ;
    END
  END r0_rd_out[210]
  PIN r0_rd_out[211]
    DIRECTION OUTPUT ;
    USE SIGNAL ;
    SHAPE ABUTMENT ;
    PORT
      LAYER M3 ;
      RECT 151.983 0.000 152.001 0.054 ;
    END
  END r0_rd_out[211]
  PIN r0_rd_out[212]
    DIRECTION OUTPUT ;
    USE SIGNAL ;
    SHAPE ABUTMENT ;
    PORT
      LAYER M3 ;
      RECT 152.271 0.000 152.289 0.054 ;
    END
  END r0_rd_out[212]
  PIN r0_rd_out[213]
    DIRECTION OUTPUT ;
    USE SIGNAL ;
    SHAPE ABUTMENT ;
    PORT
      LAYER M3 ;
      RECT 152.559 0.000 152.577 0.054 ;
    END
  END r0_rd_out[213]
  PIN r0_rd_out[214]
    DIRECTION OUTPUT ;
    USE SIGNAL ;
    SHAPE ABUTMENT ;
    PORT
      LAYER M3 ;
      RECT 152.847 0.000 152.865 0.054 ;
    END
  END r0_rd_out[214]
  PIN r0_rd_out[215]
    DIRECTION OUTPUT ;
    USE SIGNAL ;
    SHAPE ABUTMENT ;
    PORT
      LAYER M3 ;
      RECT 153.135 0.000 153.153 0.054 ;
    END
  END r0_rd_out[215]
  PIN r0_rd_out[216]
    DIRECTION OUTPUT ;
    USE SIGNAL ;
    SHAPE ABUTMENT ;
    PORT
      LAYER M3 ;
      RECT 153.423 0.000 153.441 0.054 ;
    END
  END r0_rd_out[216]
  PIN r0_rd_out[217]
    DIRECTION OUTPUT ;
    USE SIGNAL ;
    SHAPE ABUTMENT ;
    PORT
      LAYER M3 ;
      RECT 153.711 0.000 153.729 0.054 ;
    END
  END r0_rd_out[217]
  PIN r0_rd_out[218]
    DIRECTION OUTPUT ;
    USE SIGNAL ;
    SHAPE ABUTMENT ;
    PORT
      LAYER M3 ;
      RECT 153.999 0.000 154.017 0.054 ;
    END
  END r0_rd_out[218]
  PIN r0_rd_out[219]
    DIRECTION OUTPUT ;
    USE SIGNAL ;
    SHAPE ABUTMENT ;
    PORT
      LAYER M3 ;
      RECT 154.287 0.000 154.305 0.054 ;
    END
  END r0_rd_out[219]
  PIN r0_rd_out[220]
    DIRECTION OUTPUT ;
    USE SIGNAL ;
    SHAPE ABUTMENT ;
    PORT
      LAYER M3 ;
      RECT 154.575 0.000 154.593 0.054 ;
    END
  END r0_rd_out[220]
  PIN r0_rd_out[221]
    DIRECTION OUTPUT ;
    USE SIGNAL ;
    SHAPE ABUTMENT ;
    PORT
      LAYER M3 ;
      RECT 154.863 0.000 154.881 0.054 ;
    END
  END r0_rd_out[221]
  PIN r0_rd_out[222]
    DIRECTION OUTPUT ;
    USE SIGNAL ;
    SHAPE ABUTMENT ;
    PORT
      LAYER M3 ;
      RECT 155.151 0.000 155.169 0.054 ;
    END
  END r0_rd_out[222]
  PIN r0_rd_out[223]
    DIRECTION OUTPUT ;
    USE SIGNAL ;
    SHAPE ABUTMENT ;
    PORT
      LAYER M3 ;
      RECT 155.439 0.000 155.457 0.054 ;
    END
  END r0_rd_out[223]
  PIN r0_rd_out[224]
    DIRECTION OUTPUT ;
    USE SIGNAL ;
    SHAPE ABUTMENT ;
    PORT
      LAYER M3 ;
      RECT 155.727 0.000 155.745 0.054 ;
    END
  END r0_rd_out[224]
  PIN r0_rd_out[225]
    DIRECTION OUTPUT ;
    USE SIGNAL ;
    SHAPE ABUTMENT ;
    PORT
      LAYER M3 ;
      RECT 156.015 0.000 156.033 0.054 ;
    END
  END r0_rd_out[225]
  PIN r0_rd_out[226]
    DIRECTION OUTPUT ;
    USE SIGNAL ;
    SHAPE ABUTMENT ;
    PORT
      LAYER M3 ;
      RECT 156.303 0.000 156.321 0.054 ;
    END
  END r0_rd_out[226]
  PIN r0_rd_out[227]
    DIRECTION OUTPUT ;
    USE SIGNAL ;
    SHAPE ABUTMENT ;
    PORT
      LAYER M3 ;
      RECT 156.591 0.000 156.609 0.054 ;
    END
  END r0_rd_out[227]
  PIN r0_rd_out[228]
    DIRECTION OUTPUT ;
    USE SIGNAL ;
    SHAPE ABUTMENT ;
    PORT
      LAYER M3 ;
      RECT 156.879 0.000 156.897 0.054 ;
    END
  END r0_rd_out[228]
  PIN r0_rd_out[229]
    DIRECTION OUTPUT ;
    USE SIGNAL ;
    SHAPE ABUTMENT ;
    PORT
      LAYER M3 ;
      RECT 157.167 0.000 157.185 0.054 ;
    END
  END r0_rd_out[229]
  PIN r0_rd_out[230]
    DIRECTION OUTPUT ;
    USE SIGNAL ;
    SHAPE ABUTMENT ;
    PORT
      LAYER M3 ;
      RECT 157.455 0.000 157.473 0.054 ;
    END
  END r0_rd_out[230]
  PIN r0_rd_out[231]
    DIRECTION OUTPUT ;
    USE SIGNAL ;
    SHAPE ABUTMENT ;
    PORT
      LAYER M3 ;
      RECT 157.743 0.000 157.761 0.054 ;
    END
  END r0_rd_out[231]
  PIN r0_rd_out[232]
    DIRECTION OUTPUT ;
    USE SIGNAL ;
    SHAPE ABUTMENT ;
    PORT
      LAYER M3 ;
      RECT 158.031 0.000 158.049 0.054 ;
    END
  END r0_rd_out[232]
  PIN r0_rd_out[233]
    DIRECTION OUTPUT ;
    USE SIGNAL ;
    SHAPE ABUTMENT ;
    PORT
      LAYER M3 ;
      RECT 158.319 0.000 158.337 0.054 ;
    END
  END r0_rd_out[233]
  PIN r0_rd_out[234]
    DIRECTION OUTPUT ;
    USE SIGNAL ;
    SHAPE ABUTMENT ;
    PORT
      LAYER M3 ;
      RECT 158.607 0.000 158.625 0.054 ;
    END
  END r0_rd_out[234]
  PIN r0_rd_out[235]
    DIRECTION OUTPUT ;
    USE SIGNAL ;
    SHAPE ABUTMENT ;
    PORT
      LAYER M3 ;
      RECT 158.895 0.000 158.913 0.054 ;
    END
  END r0_rd_out[235]
  PIN r0_rd_out[236]
    DIRECTION OUTPUT ;
    USE SIGNAL ;
    SHAPE ABUTMENT ;
    PORT
      LAYER M3 ;
      RECT 159.183 0.000 159.201 0.054 ;
    END
  END r0_rd_out[236]
  PIN r0_rd_out[237]
    DIRECTION OUTPUT ;
    USE SIGNAL ;
    SHAPE ABUTMENT ;
    PORT
      LAYER M3 ;
      RECT 159.471 0.000 159.489 0.054 ;
    END
  END r0_rd_out[237]
  PIN r0_rd_out[238]
    DIRECTION OUTPUT ;
    USE SIGNAL ;
    SHAPE ABUTMENT ;
    PORT
      LAYER M3 ;
      RECT 159.759 0.000 159.777 0.054 ;
    END
  END r0_rd_out[238]
  PIN r0_rd_out[239]
    DIRECTION OUTPUT ;
    USE SIGNAL ;
    SHAPE ABUTMENT ;
    PORT
      LAYER M3 ;
      RECT 160.047 0.000 160.065 0.054 ;
    END
  END r0_rd_out[239]
  PIN r0_rd_out[240]
    DIRECTION OUTPUT ;
    USE SIGNAL ;
    SHAPE ABUTMENT ;
    PORT
      LAYER M3 ;
      RECT 160.335 0.000 160.353 0.054 ;
    END
  END r0_rd_out[240]
  PIN r0_rd_out[241]
    DIRECTION OUTPUT ;
    USE SIGNAL ;
    SHAPE ABUTMENT ;
    PORT
      LAYER M3 ;
      RECT 160.623 0.000 160.641 0.054 ;
    END
  END r0_rd_out[241]
  PIN r0_rd_out[242]
    DIRECTION OUTPUT ;
    USE SIGNAL ;
    SHAPE ABUTMENT ;
    PORT
      LAYER M3 ;
      RECT 160.911 0.000 160.929 0.054 ;
    END
  END r0_rd_out[242]
  PIN r0_rd_out[243]
    DIRECTION OUTPUT ;
    USE SIGNAL ;
    SHAPE ABUTMENT ;
    PORT
      LAYER M3 ;
      RECT 161.199 0.000 161.217 0.054 ;
    END
  END r0_rd_out[243]
  PIN r0_rd_out[244]
    DIRECTION OUTPUT ;
    USE SIGNAL ;
    SHAPE ABUTMENT ;
    PORT
      LAYER M3 ;
      RECT 161.487 0.000 161.505 0.054 ;
    END
  END r0_rd_out[244]
  PIN r0_rd_out[245]
    DIRECTION OUTPUT ;
    USE SIGNAL ;
    SHAPE ABUTMENT ;
    PORT
      LAYER M3 ;
      RECT 161.775 0.000 161.793 0.054 ;
    END
  END r0_rd_out[245]
  PIN r0_rd_out[246]
    DIRECTION OUTPUT ;
    USE SIGNAL ;
    SHAPE ABUTMENT ;
    PORT
      LAYER M3 ;
      RECT 162.063 0.000 162.081 0.054 ;
    END
  END r0_rd_out[246]
  PIN r0_rd_out[247]
    DIRECTION OUTPUT ;
    USE SIGNAL ;
    SHAPE ABUTMENT ;
    PORT
      LAYER M3 ;
      RECT 162.351 0.000 162.369 0.054 ;
    END
  END r0_rd_out[247]
  PIN r0_rd_out[248]
    DIRECTION OUTPUT ;
    USE SIGNAL ;
    SHAPE ABUTMENT ;
    PORT
      LAYER M3 ;
      RECT 162.639 0.000 162.657 0.054 ;
    END
  END r0_rd_out[248]
  PIN r0_rd_out[249]
    DIRECTION OUTPUT ;
    USE SIGNAL ;
    SHAPE ABUTMENT ;
    PORT
      LAYER M3 ;
      RECT 162.927 0.000 162.945 0.054 ;
    END
  END r0_rd_out[249]
  PIN r0_rd_out[250]
    DIRECTION OUTPUT ;
    USE SIGNAL ;
    SHAPE ABUTMENT ;
    PORT
      LAYER M3 ;
      RECT 163.215 0.000 163.233 0.054 ;
    END
  END r0_rd_out[250]
  PIN r0_rd_out[251]
    DIRECTION OUTPUT ;
    USE SIGNAL ;
    SHAPE ABUTMENT ;
    PORT
      LAYER M3 ;
      RECT 163.503 0.000 163.521 0.054 ;
    END
  END r0_rd_out[251]
  PIN r0_rd_out[252]
    DIRECTION OUTPUT ;
    USE SIGNAL ;
    SHAPE ABUTMENT ;
    PORT
      LAYER M3 ;
      RECT 163.791 0.000 163.809 0.054 ;
    END
  END r0_rd_out[252]
  PIN r0_rd_out[253]
    DIRECTION OUTPUT ;
    USE SIGNAL ;
    SHAPE ABUTMENT ;
    PORT
      LAYER M3 ;
      RECT 164.079 0.000 164.097 0.054 ;
    END
  END r0_rd_out[253]
  PIN r0_rd_out[254]
    DIRECTION OUTPUT ;
    USE SIGNAL ;
    SHAPE ABUTMENT ;
    PORT
      LAYER M3 ;
      RECT 164.367 0.000 164.385 0.054 ;
    END
  END r0_rd_out[254]
  PIN r0_rd_out[255]
    DIRECTION OUTPUT ;
    USE SIGNAL ;
    SHAPE ABUTMENT ;
    PORT
      LAYER M3 ;
      RECT 164.655 0.000 164.673 0.054 ;
    END
  END r0_rd_out[255]
  PIN r0_rd_out[256]
    DIRECTION OUTPUT ;
    USE SIGNAL ;
    SHAPE ABUTMENT ;
    PORT
      LAYER M3 ;
      RECT 164.943 0.000 164.961 0.054 ;
    END
  END r0_rd_out[256]
  PIN r0_rd_out[257]
    DIRECTION OUTPUT ;
    USE SIGNAL ;
    SHAPE ABUTMENT ;
    PORT
      LAYER M3 ;
      RECT 165.231 0.000 165.249 0.054 ;
    END
  END r0_rd_out[257]
  PIN r0_rd_out[258]
    DIRECTION OUTPUT ;
    USE SIGNAL ;
    SHAPE ABUTMENT ;
    PORT
      LAYER M3 ;
      RECT 165.519 0.000 165.537 0.054 ;
    END
  END r0_rd_out[258]
  PIN r0_rd_out[259]
    DIRECTION OUTPUT ;
    USE SIGNAL ;
    SHAPE ABUTMENT ;
    PORT
      LAYER M3 ;
      RECT 165.807 0.000 165.825 0.054 ;
    END
  END r0_rd_out[259]
  PIN r0_rd_out[260]
    DIRECTION OUTPUT ;
    USE SIGNAL ;
    SHAPE ABUTMENT ;
    PORT
      LAYER M3 ;
      RECT 166.095 0.000 166.113 0.054 ;
    END
  END r0_rd_out[260]
  PIN r0_rd_out[261]
    DIRECTION OUTPUT ;
    USE SIGNAL ;
    SHAPE ABUTMENT ;
    PORT
      LAYER M3 ;
      RECT 166.383 0.000 166.401 0.054 ;
    END
  END r0_rd_out[261]
  PIN r0_rd_out[262]
    DIRECTION OUTPUT ;
    USE SIGNAL ;
    SHAPE ABUTMENT ;
    PORT
      LAYER M3 ;
      RECT 166.671 0.000 166.689 0.054 ;
    END
  END r0_rd_out[262]
  PIN r0_rd_out[263]
    DIRECTION OUTPUT ;
    USE SIGNAL ;
    SHAPE ABUTMENT ;
    PORT
      LAYER M3 ;
      RECT 166.959 0.000 166.977 0.054 ;
    END
  END r0_rd_out[263]
  PIN r0_rd_out[264]
    DIRECTION OUTPUT ;
    USE SIGNAL ;
    SHAPE ABUTMENT ;
    PORT
      LAYER M3 ;
      RECT 167.247 0.000 167.265 0.054 ;
    END
  END r0_rd_out[264]
  PIN r0_rd_out[265]
    DIRECTION OUTPUT ;
    USE SIGNAL ;
    SHAPE ABUTMENT ;
    PORT
      LAYER M3 ;
      RECT 167.535 0.000 167.553 0.054 ;
    END
  END r0_rd_out[265]
  PIN r0_rd_out[266]
    DIRECTION OUTPUT ;
    USE SIGNAL ;
    SHAPE ABUTMENT ;
    PORT
      LAYER M3 ;
      RECT 167.823 0.000 167.841 0.054 ;
    END
  END r0_rd_out[266]
  PIN r0_rd_out[267]
    DIRECTION OUTPUT ;
    USE SIGNAL ;
    SHAPE ABUTMENT ;
    PORT
      LAYER M3 ;
      RECT 168.111 0.000 168.129 0.054 ;
    END
  END r0_rd_out[267]
  PIN r0_rd_out[268]
    DIRECTION OUTPUT ;
    USE SIGNAL ;
    SHAPE ABUTMENT ;
    PORT
      LAYER M3 ;
      RECT 168.399 0.000 168.417 0.054 ;
    END
  END r0_rd_out[268]
  PIN r0_rd_out[269]
    DIRECTION OUTPUT ;
    USE SIGNAL ;
    SHAPE ABUTMENT ;
    PORT
      LAYER M3 ;
      RECT 168.687 0.000 168.705 0.054 ;
    END
  END r0_rd_out[269]
  PIN r0_rd_out[270]
    DIRECTION OUTPUT ;
    USE SIGNAL ;
    SHAPE ABUTMENT ;
    PORT
      LAYER M3 ;
      RECT 168.975 0.000 168.993 0.054 ;
    END
  END r0_rd_out[270]
  PIN r0_rd_out[271]
    DIRECTION OUTPUT ;
    USE SIGNAL ;
    SHAPE ABUTMENT ;
    PORT
      LAYER M3 ;
      RECT 169.263 0.000 169.281 0.054 ;
    END
  END r0_rd_out[271]
  PIN r0_rd_out[272]
    DIRECTION OUTPUT ;
    USE SIGNAL ;
    SHAPE ABUTMENT ;
    PORT
      LAYER M3 ;
      RECT 169.551 0.000 169.569 0.054 ;
    END
  END r0_rd_out[272]
  PIN r0_rd_out[273]
    DIRECTION OUTPUT ;
    USE SIGNAL ;
    SHAPE ABUTMENT ;
    PORT
      LAYER M3 ;
      RECT 169.839 0.000 169.857 0.054 ;
    END
  END r0_rd_out[273]
  PIN r0_rd_out[274]
    DIRECTION OUTPUT ;
    USE SIGNAL ;
    SHAPE ABUTMENT ;
    PORT
      LAYER M3 ;
      RECT 170.127 0.000 170.145 0.054 ;
    END
  END r0_rd_out[274]
  PIN r0_rd_out[275]
    DIRECTION OUTPUT ;
    USE SIGNAL ;
    SHAPE ABUTMENT ;
    PORT
      LAYER M3 ;
      RECT 170.415 0.000 170.433 0.054 ;
    END
  END r0_rd_out[275]
  PIN r0_rd_out[276]
    DIRECTION OUTPUT ;
    USE SIGNAL ;
    SHAPE ABUTMENT ;
    PORT
      LAYER M3 ;
      RECT 170.703 0.000 170.721 0.054 ;
    END
  END r0_rd_out[276]
  PIN r0_rd_out[277]
    DIRECTION OUTPUT ;
    USE SIGNAL ;
    SHAPE ABUTMENT ;
    PORT
      LAYER M3 ;
      RECT 170.991 0.000 171.009 0.054 ;
    END
  END r0_rd_out[277]
  PIN r0_rd_out[278]
    DIRECTION OUTPUT ;
    USE SIGNAL ;
    SHAPE ABUTMENT ;
    PORT
      LAYER M3 ;
      RECT 171.279 0.000 171.297 0.054 ;
    END
  END r0_rd_out[278]
  PIN r0_rd_out[279]
    DIRECTION OUTPUT ;
    USE SIGNAL ;
    SHAPE ABUTMENT ;
    PORT
      LAYER M3 ;
      RECT 171.567 0.000 171.585 0.054 ;
    END
  END r0_rd_out[279]
  PIN r0_rd_out[280]
    DIRECTION OUTPUT ;
    USE SIGNAL ;
    SHAPE ABUTMENT ;
    PORT
      LAYER M3 ;
      RECT 171.855 0.000 171.873 0.054 ;
    END
  END r0_rd_out[280]
  PIN r0_rd_out[281]
    DIRECTION OUTPUT ;
    USE SIGNAL ;
    SHAPE ABUTMENT ;
    PORT
      LAYER M3 ;
      RECT 172.143 0.000 172.161 0.054 ;
    END
  END r0_rd_out[281]
  PIN r0_rd_out[282]
    DIRECTION OUTPUT ;
    USE SIGNAL ;
    SHAPE ABUTMENT ;
    PORT
      LAYER M3 ;
      RECT 172.431 0.000 172.449 0.054 ;
    END
  END r0_rd_out[282]
  PIN r0_rd_out[283]
    DIRECTION OUTPUT ;
    USE SIGNAL ;
    SHAPE ABUTMENT ;
    PORT
      LAYER M3 ;
      RECT 172.719 0.000 172.737 0.054 ;
    END
  END r0_rd_out[283]
  PIN r0_rd_out[284]
    DIRECTION OUTPUT ;
    USE SIGNAL ;
    SHAPE ABUTMENT ;
    PORT
      LAYER M3 ;
      RECT 173.007 0.000 173.025 0.054 ;
    END
  END r0_rd_out[284]
  PIN r0_rd_out[285]
    DIRECTION OUTPUT ;
    USE SIGNAL ;
    SHAPE ABUTMENT ;
    PORT
      LAYER M3 ;
      RECT 173.295 0.000 173.313 0.054 ;
    END
  END r0_rd_out[285]
  PIN r0_rd_out[286]
    DIRECTION OUTPUT ;
    USE SIGNAL ;
    SHAPE ABUTMENT ;
    PORT
      LAYER M3 ;
      RECT 173.583 0.000 173.601 0.054 ;
    END
  END r0_rd_out[286]
  PIN r0_rd_out[287]
    DIRECTION OUTPUT ;
    USE SIGNAL ;
    SHAPE ABUTMENT ;
    PORT
      LAYER M3 ;
      RECT 173.871 0.000 173.889 0.054 ;
    END
  END r0_rd_out[287]
  PIN r0_rd_out[288]
    DIRECTION OUTPUT ;
    USE SIGNAL ;
    SHAPE ABUTMENT ;
    PORT
      LAYER M3 ;
      RECT 174.159 0.000 174.177 0.054 ;
    END
  END r0_rd_out[288]
  PIN r0_rd_out[289]
    DIRECTION OUTPUT ;
    USE SIGNAL ;
    SHAPE ABUTMENT ;
    PORT
      LAYER M3 ;
      RECT 174.447 0.000 174.465 0.054 ;
    END
  END r0_rd_out[289]
  PIN r0_rd_out[290]
    DIRECTION OUTPUT ;
    USE SIGNAL ;
    SHAPE ABUTMENT ;
    PORT
      LAYER M3 ;
      RECT 174.735 0.000 174.753 0.054 ;
    END
  END r0_rd_out[290]
  PIN r0_rd_out[291]
    DIRECTION OUTPUT ;
    USE SIGNAL ;
    SHAPE ABUTMENT ;
    PORT
      LAYER M3 ;
      RECT 175.023 0.000 175.041 0.054 ;
    END
  END r0_rd_out[291]
  PIN r0_rd_out[292]
    DIRECTION OUTPUT ;
    USE SIGNAL ;
    SHAPE ABUTMENT ;
    PORT
      LAYER M3 ;
      RECT 175.311 0.000 175.329 0.054 ;
    END
  END r0_rd_out[292]
  PIN r0_rd_out[293]
    DIRECTION OUTPUT ;
    USE SIGNAL ;
    SHAPE ABUTMENT ;
    PORT
      LAYER M3 ;
      RECT 175.599 0.000 175.617 0.054 ;
    END
  END r0_rd_out[293]
  PIN r0_rd_out[294]
    DIRECTION OUTPUT ;
    USE SIGNAL ;
    SHAPE ABUTMENT ;
    PORT
      LAYER M3 ;
      RECT 175.887 0.000 175.905 0.054 ;
    END
  END r0_rd_out[294]
  PIN r0_rd_out[295]
    DIRECTION OUTPUT ;
    USE SIGNAL ;
    SHAPE ABUTMENT ;
    PORT
      LAYER M3 ;
      RECT 176.175 0.000 176.193 0.054 ;
    END
  END r0_rd_out[295]
  PIN r0_rd_out[296]
    DIRECTION OUTPUT ;
    USE SIGNAL ;
    SHAPE ABUTMENT ;
    PORT
      LAYER M3 ;
      RECT 176.463 0.000 176.481 0.054 ;
    END
  END r0_rd_out[296]
  PIN r0_rd_out[297]
    DIRECTION OUTPUT ;
    USE SIGNAL ;
    SHAPE ABUTMENT ;
    PORT
      LAYER M3 ;
      RECT 176.751 0.000 176.769 0.054 ;
    END
  END r0_rd_out[297]
  PIN r0_rd_out[298]
    DIRECTION OUTPUT ;
    USE SIGNAL ;
    SHAPE ABUTMENT ;
    PORT
      LAYER M3 ;
      RECT 177.039 0.000 177.057 0.054 ;
    END
  END r0_rd_out[298]
  PIN r0_rd_out[299]
    DIRECTION OUTPUT ;
    USE SIGNAL ;
    SHAPE ABUTMENT ;
    PORT
      LAYER M3 ;
      RECT 177.327 0.000 177.345 0.054 ;
    END
  END r0_rd_out[299]
  PIN r0_rd_out[300]
    DIRECTION OUTPUT ;
    USE SIGNAL ;
    SHAPE ABUTMENT ;
    PORT
      LAYER M3 ;
      RECT 177.615 0.000 177.633 0.054 ;
    END
  END r0_rd_out[300]
  PIN r0_rd_out[301]
    DIRECTION OUTPUT ;
    USE SIGNAL ;
    SHAPE ABUTMENT ;
    PORT
      LAYER M3 ;
      RECT 177.903 0.000 177.921 0.054 ;
    END
  END r0_rd_out[301]
  PIN r0_rd_out[302]
    DIRECTION OUTPUT ;
    USE SIGNAL ;
    SHAPE ABUTMENT ;
    PORT
      LAYER M3 ;
      RECT 178.191 0.000 178.209 0.054 ;
    END
  END r0_rd_out[302]
  PIN r0_rd_out[303]
    DIRECTION OUTPUT ;
    USE SIGNAL ;
    SHAPE ABUTMENT ;
    PORT
      LAYER M3 ;
      RECT 178.479 0.000 178.497 0.054 ;
    END
  END r0_rd_out[303]
  PIN r0_rd_out[304]
    DIRECTION OUTPUT ;
    USE SIGNAL ;
    SHAPE ABUTMENT ;
    PORT
      LAYER M3 ;
      RECT 178.767 0.000 178.785 0.054 ;
    END
  END r0_rd_out[304]
  PIN r0_rd_out[305]
    DIRECTION OUTPUT ;
    USE SIGNAL ;
    SHAPE ABUTMENT ;
    PORT
      LAYER M3 ;
      RECT 179.055 0.000 179.073 0.054 ;
    END
  END r0_rd_out[305]
  PIN r0_rd_out[306]
    DIRECTION OUTPUT ;
    USE SIGNAL ;
    SHAPE ABUTMENT ;
    PORT
      LAYER M3 ;
      RECT 179.343 0.000 179.361 0.054 ;
    END
  END r0_rd_out[306]
  PIN r0_rd_out[307]
    DIRECTION OUTPUT ;
    USE SIGNAL ;
    SHAPE ABUTMENT ;
    PORT
      LAYER M3 ;
      RECT 179.631 0.000 179.649 0.054 ;
    END
  END r0_rd_out[307]
  PIN r0_rd_out[308]
    DIRECTION OUTPUT ;
    USE SIGNAL ;
    SHAPE ABUTMENT ;
    PORT
      LAYER M3 ;
      RECT 179.919 0.000 179.937 0.054 ;
    END
  END r0_rd_out[308]
  PIN r0_rd_out[309]
    DIRECTION OUTPUT ;
    USE SIGNAL ;
    SHAPE ABUTMENT ;
    PORT
      LAYER M3 ;
      RECT 180.207 0.000 180.225 0.054 ;
    END
  END r0_rd_out[309]
  PIN r0_rd_out[310]
    DIRECTION OUTPUT ;
    USE SIGNAL ;
    SHAPE ABUTMENT ;
    PORT
      LAYER M3 ;
      RECT 180.495 0.000 180.513 0.054 ;
    END
  END r0_rd_out[310]
  PIN r0_rd_out[311]
    DIRECTION OUTPUT ;
    USE SIGNAL ;
    SHAPE ABUTMENT ;
    PORT
      LAYER M3 ;
      RECT 180.783 0.000 180.801 0.054 ;
    END
  END r0_rd_out[311]
  PIN r0_rd_out[312]
    DIRECTION OUTPUT ;
    USE SIGNAL ;
    SHAPE ABUTMENT ;
    PORT
      LAYER M3 ;
      RECT 181.071 0.000 181.089 0.054 ;
    END
  END r0_rd_out[312]
  PIN r0_rd_out[313]
    DIRECTION OUTPUT ;
    USE SIGNAL ;
    SHAPE ABUTMENT ;
    PORT
      LAYER M3 ;
      RECT 181.359 0.000 181.377 0.054 ;
    END
  END r0_rd_out[313]
  PIN r0_rd_out[314]
    DIRECTION OUTPUT ;
    USE SIGNAL ;
    SHAPE ABUTMENT ;
    PORT
      LAYER M3 ;
      RECT 181.647 0.000 181.665 0.054 ;
    END
  END r0_rd_out[314]
  PIN r0_rd_out[315]
    DIRECTION OUTPUT ;
    USE SIGNAL ;
    SHAPE ABUTMENT ;
    PORT
      LAYER M3 ;
      RECT 181.935 0.000 181.953 0.054 ;
    END
  END r0_rd_out[315]
  PIN r0_rd_out[316]
    DIRECTION OUTPUT ;
    USE SIGNAL ;
    SHAPE ABUTMENT ;
    PORT
      LAYER M3 ;
      RECT 182.223 0.000 182.241 0.054 ;
    END
  END r0_rd_out[316]
  PIN r0_rd_out[317]
    DIRECTION OUTPUT ;
    USE SIGNAL ;
    SHAPE ABUTMENT ;
    PORT
      LAYER M3 ;
      RECT 91.215 56.359 91.233 56.413 ;
    END
  END r0_rd_out[317]
  PIN r0_rd_out[318]
    DIRECTION OUTPUT ;
    USE SIGNAL ;
    SHAPE ABUTMENT ;
    PORT
      LAYER M3 ;
      RECT 91.503 56.359 91.521 56.413 ;
    END
  END r0_rd_out[318]
  PIN r0_rd_out[319]
    DIRECTION OUTPUT ;
    USE SIGNAL ;
    SHAPE ABUTMENT ;
    PORT
      LAYER M3 ;
      RECT 91.791 56.359 91.809 56.413 ;
    END
  END r0_rd_out[319]
  PIN r0_rd_out[320]
    DIRECTION OUTPUT ;
    USE SIGNAL ;
    SHAPE ABUTMENT ;
    PORT
      LAYER M3 ;
      RECT 92.079 56.359 92.097 56.413 ;
    END
  END r0_rd_out[320]
  PIN r0_rd_out[321]
    DIRECTION OUTPUT ;
    USE SIGNAL ;
    SHAPE ABUTMENT ;
    PORT
      LAYER M3 ;
      RECT 92.367 56.359 92.385 56.413 ;
    END
  END r0_rd_out[321]
  PIN r0_rd_out[322]
    DIRECTION OUTPUT ;
    USE SIGNAL ;
    SHAPE ABUTMENT ;
    PORT
      LAYER M3 ;
      RECT 92.655 56.359 92.673 56.413 ;
    END
  END r0_rd_out[322]
  PIN r0_rd_out[323]
    DIRECTION OUTPUT ;
    USE SIGNAL ;
    SHAPE ABUTMENT ;
    PORT
      LAYER M3 ;
      RECT 92.943 56.359 92.961 56.413 ;
    END
  END r0_rd_out[323]
  PIN r0_rd_out[324]
    DIRECTION OUTPUT ;
    USE SIGNAL ;
    SHAPE ABUTMENT ;
    PORT
      LAYER M3 ;
      RECT 93.231 56.359 93.249 56.413 ;
    END
  END r0_rd_out[324]
  PIN r0_rd_out[325]
    DIRECTION OUTPUT ;
    USE SIGNAL ;
    SHAPE ABUTMENT ;
    PORT
      LAYER M3 ;
      RECT 93.519 56.359 93.537 56.413 ;
    END
  END r0_rd_out[325]
  PIN r0_rd_out[326]
    DIRECTION OUTPUT ;
    USE SIGNAL ;
    SHAPE ABUTMENT ;
    PORT
      LAYER M3 ;
      RECT 93.807 56.359 93.825 56.413 ;
    END
  END r0_rd_out[326]
  PIN r0_rd_out[327]
    DIRECTION OUTPUT ;
    USE SIGNAL ;
    SHAPE ABUTMENT ;
    PORT
      LAYER M3 ;
      RECT 94.095 56.359 94.113 56.413 ;
    END
  END r0_rd_out[327]
  PIN r0_rd_out[328]
    DIRECTION OUTPUT ;
    USE SIGNAL ;
    SHAPE ABUTMENT ;
    PORT
      LAYER M3 ;
      RECT 94.383 56.359 94.401 56.413 ;
    END
  END r0_rd_out[328]
  PIN r0_rd_out[329]
    DIRECTION OUTPUT ;
    USE SIGNAL ;
    SHAPE ABUTMENT ;
    PORT
      LAYER M3 ;
      RECT 94.671 56.359 94.689 56.413 ;
    END
  END r0_rd_out[329]
  PIN r0_rd_out[330]
    DIRECTION OUTPUT ;
    USE SIGNAL ;
    SHAPE ABUTMENT ;
    PORT
      LAYER M3 ;
      RECT 94.959 56.359 94.977 56.413 ;
    END
  END r0_rd_out[330]
  PIN r0_rd_out[331]
    DIRECTION OUTPUT ;
    USE SIGNAL ;
    SHAPE ABUTMENT ;
    PORT
      LAYER M3 ;
      RECT 95.247 56.359 95.265 56.413 ;
    END
  END r0_rd_out[331]
  PIN r0_rd_out[332]
    DIRECTION OUTPUT ;
    USE SIGNAL ;
    SHAPE ABUTMENT ;
    PORT
      LAYER M3 ;
      RECT 95.535 56.359 95.553 56.413 ;
    END
  END r0_rd_out[332]
  PIN r0_rd_out[333]
    DIRECTION OUTPUT ;
    USE SIGNAL ;
    SHAPE ABUTMENT ;
    PORT
      LAYER M3 ;
      RECT 95.823 56.359 95.841 56.413 ;
    END
  END r0_rd_out[333]
  PIN r0_rd_out[334]
    DIRECTION OUTPUT ;
    USE SIGNAL ;
    SHAPE ABUTMENT ;
    PORT
      LAYER M3 ;
      RECT 96.111 56.359 96.129 56.413 ;
    END
  END r0_rd_out[334]
  PIN r0_rd_out[335]
    DIRECTION OUTPUT ;
    USE SIGNAL ;
    SHAPE ABUTMENT ;
    PORT
      LAYER M3 ;
      RECT 96.399 56.359 96.417 56.413 ;
    END
  END r0_rd_out[335]
  PIN r0_rd_out[336]
    DIRECTION OUTPUT ;
    USE SIGNAL ;
    SHAPE ABUTMENT ;
    PORT
      LAYER M3 ;
      RECT 96.687 56.359 96.705 56.413 ;
    END
  END r0_rd_out[336]
  PIN r0_rd_out[337]
    DIRECTION OUTPUT ;
    USE SIGNAL ;
    SHAPE ABUTMENT ;
    PORT
      LAYER M3 ;
      RECT 96.975 56.359 96.993 56.413 ;
    END
  END r0_rd_out[337]
  PIN r0_rd_out[338]
    DIRECTION OUTPUT ;
    USE SIGNAL ;
    SHAPE ABUTMENT ;
    PORT
      LAYER M3 ;
      RECT 97.263 56.359 97.281 56.413 ;
    END
  END r0_rd_out[338]
  PIN r0_rd_out[339]
    DIRECTION OUTPUT ;
    USE SIGNAL ;
    SHAPE ABUTMENT ;
    PORT
      LAYER M3 ;
      RECT 97.551 56.359 97.569 56.413 ;
    END
  END r0_rd_out[339]
  PIN r0_rd_out[340]
    DIRECTION OUTPUT ;
    USE SIGNAL ;
    SHAPE ABUTMENT ;
    PORT
      LAYER M3 ;
      RECT 97.839 56.359 97.857 56.413 ;
    END
  END r0_rd_out[340]
  PIN r0_rd_out[341]
    DIRECTION OUTPUT ;
    USE SIGNAL ;
    SHAPE ABUTMENT ;
    PORT
      LAYER M3 ;
      RECT 98.127 56.359 98.145 56.413 ;
    END
  END r0_rd_out[341]
  PIN r0_rd_out[342]
    DIRECTION OUTPUT ;
    USE SIGNAL ;
    SHAPE ABUTMENT ;
    PORT
      LAYER M3 ;
      RECT 98.415 56.359 98.433 56.413 ;
    END
  END r0_rd_out[342]
  PIN r0_rd_out[343]
    DIRECTION OUTPUT ;
    USE SIGNAL ;
    SHAPE ABUTMENT ;
    PORT
      LAYER M3 ;
      RECT 98.703 56.359 98.721 56.413 ;
    END
  END r0_rd_out[343]
  PIN r0_rd_out[344]
    DIRECTION OUTPUT ;
    USE SIGNAL ;
    SHAPE ABUTMENT ;
    PORT
      LAYER M3 ;
      RECT 98.991 56.359 99.009 56.413 ;
    END
  END r0_rd_out[344]
  PIN r0_rd_out[345]
    DIRECTION OUTPUT ;
    USE SIGNAL ;
    SHAPE ABUTMENT ;
    PORT
      LAYER M3 ;
      RECT 99.279 56.359 99.297 56.413 ;
    END
  END r0_rd_out[345]
  PIN r0_rd_out[346]
    DIRECTION OUTPUT ;
    USE SIGNAL ;
    SHAPE ABUTMENT ;
    PORT
      LAYER M3 ;
      RECT 99.567 56.359 99.585 56.413 ;
    END
  END r0_rd_out[346]
  PIN r0_rd_out[347]
    DIRECTION OUTPUT ;
    USE SIGNAL ;
    SHAPE ABUTMENT ;
    PORT
      LAYER M3 ;
      RECT 99.855 56.359 99.873 56.413 ;
    END
  END r0_rd_out[347]
  PIN r0_rd_out[348]
    DIRECTION OUTPUT ;
    USE SIGNAL ;
    SHAPE ABUTMENT ;
    PORT
      LAYER M3 ;
      RECT 100.143 56.359 100.161 56.413 ;
    END
  END r0_rd_out[348]
  PIN r0_rd_out[349]
    DIRECTION OUTPUT ;
    USE SIGNAL ;
    SHAPE ABUTMENT ;
    PORT
      LAYER M3 ;
      RECT 100.431 56.359 100.449 56.413 ;
    END
  END r0_rd_out[349]
  PIN r0_rd_out[350]
    DIRECTION OUTPUT ;
    USE SIGNAL ;
    SHAPE ABUTMENT ;
    PORT
      LAYER M3 ;
      RECT 100.719 56.359 100.737 56.413 ;
    END
  END r0_rd_out[350]
  PIN r0_rd_out[351]
    DIRECTION OUTPUT ;
    USE SIGNAL ;
    SHAPE ABUTMENT ;
    PORT
      LAYER M3 ;
      RECT 101.007 56.359 101.025 56.413 ;
    END
  END r0_rd_out[351]
  PIN r0_rd_out[352]
    DIRECTION OUTPUT ;
    USE SIGNAL ;
    SHAPE ABUTMENT ;
    PORT
      LAYER M3 ;
      RECT 101.295 56.359 101.313 56.413 ;
    END
  END r0_rd_out[352]
  PIN r0_rd_out[353]
    DIRECTION OUTPUT ;
    USE SIGNAL ;
    SHAPE ABUTMENT ;
    PORT
      LAYER M3 ;
      RECT 101.583 56.359 101.601 56.413 ;
    END
  END r0_rd_out[353]
  PIN r0_rd_out[354]
    DIRECTION OUTPUT ;
    USE SIGNAL ;
    SHAPE ABUTMENT ;
    PORT
      LAYER M3 ;
      RECT 101.871 56.359 101.889 56.413 ;
    END
  END r0_rd_out[354]
  PIN r0_rd_out[355]
    DIRECTION OUTPUT ;
    USE SIGNAL ;
    SHAPE ABUTMENT ;
    PORT
      LAYER M3 ;
      RECT 102.159 56.359 102.177 56.413 ;
    END
  END r0_rd_out[355]
  PIN r0_rd_out[356]
    DIRECTION OUTPUT ;
    USE SIGNAL ;
    SHAPE ABUTMENT ;
    PORT
      LAYER M3 ;
      RECT 102.447 56.359 102.465 56.413 ;
    END
  END r0_rd_out[356]
  PIN r0_rd_out[357]
    DIRECTION OUTPUT ;
    USE SIGNAL ;
    SHAPE ABUTMENT ;
    PORT
      LAYER M3 ;
      RECT 102.735 56.359 102.753 56.413 ;
    END
  END r0_rd_out[357]
  PIN r0_rd_out[358]
    DIRECTION OUTPUT ;
    USE SIGNAL ;
    SHAPE ABUTMENT ;
    PORT
      LAYER M3 ;
      RECT 103.023 56.359 103.041 56.413 ;
    END
  END r0_rd_out[358]
  PIN r0_rd_out[359]
    DIRECTION OUTPUT ;
    USE SIGNAL ;
    SHAPE ABUTMENT ;
    PORT
      LAYER M3 ;
      RECT 103.311 56.359 103.329 56.413 ;
    END
  END r0_rd_out[359]
  PIN r0_rd_out[360]
    DIRECTION OUTPUT ;
    USE SIGNAL ;
    SHAPE ABUTMENT ;
    PORT
      LAYER M3 ;
      RECT 103.599 56.359 103.617 56.413 ;
    END
  END r0_rd_out[360]
  PIN r0_rd_out[361]
    DIRECTION OUTPUT ;
    USE SIGNAL ;
    SHAPE ABUTMENT ;
    PORT
      LAYER M3 ;
      RECT 103.887 56.359 103.905 56.413 ;
    END
  END r0_rd_out[361]
  PIN r0_rd_out[362]
    DIRECTION OUTPUT ;
    USE SIGNAL ;
    SHAPE ABUTMENT ;
    PORT
      LAYER M3 ;
      RECT 104.175 56.359 104.193 56.413 ;
    END
  END r0_rd_out[362]
  PIN r0_rd_out[363]
    DIRECTION OUTPUT ;
    USE SIGNAL ;
    SHAPE ABUTMENT ;
    PORT
      LAYER M3 ;
      RECT 104.463 56.359 104.481 56.413 ;
    END
  END r0_rd_out[363]
  PIN r0_rd_out[364]
    DIRECTION OUTPUT ;
    USE SIGNAL ;
    SHAPE ABUTMENT ;
    PORT
      LAYER M3 ;
      RECT 104.751 56.359 104.769 56.413 ;
    END
  END r0_rd_out[364]
  PIN r0_rd_out[365]
    DIRECTION OUTPUT ;
    USE SIGNAL ;
    SHAPE ABUTMENT ;
    PORT
      LAYER M3 ;
      RECT 105.039 56.359 105.057 56.413 ;
    END
  END r0_rd_out[365]
  PIN r0_rd_out[366]
    DIRECTION OUTPUT ;
    USE SIGNAL ;
    SHAPE ABUTMENT ;
    PORT
      LAYER M3 ;
      RECT 105.327 56.359 105.345 56.413 ;
    END
  END r0_rd_out[366]
  PIN r0_rd_out[367]
    DIRECTION OUTPUT ;
    USE SIGNAL ;
    SHAPE ABUTMENT ;
    PORT
      LAYER M3 ;
      RECT 105.615 56.359 105.633 56.413 ;
    END
  END r0_rd_out[367]
  PIN r0_rd_out[368]
    DIRECTION OUTPUT ;
    USE SIGNAL ;
    SHAPE ABUTMENT ;
    PORT
      LAYER M3 ;
      RECT 105.903 56.359 105.921 56.413 ;
    END
  END r0_rd_out[368]
  PIN r0_rd_out[369]
    DIRECTION OUTPUT ;
    USE SIGNAL ;
    SHAPE ABUTMENT ;
    PORT
      LAYER M3 ;
      RECT 106.191 56.359 106.209 56.413 ;
    END
  END r0_rd_out[369]
  PIN r0_rd_out[370]
    DIRECTION OUTPUT ;
    USE SIGNAL ;
    SHAPE ABUTMENT ;
    PORT
      LAYER M3 ;
      RECT 106.479 56.359 106.497 56.413 ;
    END
  END r0_rd_out[370]
  PIN r0_rd_out[371]
    DIRECTION OUTPUT ;
    USE SIGNAL ;
    SHAPE ABUTMENT ;
    PORT
      LAYER M3 ;
      RECT 106.767 56.359 106.785 56.413 ;
    END
  END r0_rd_out[371]
  PIN r0_rd_out[372]
    DIRECTION OUTPUT ;
    USE SIGNAL ;
    SHAPE ABUTMENT ;
    PORT
      LAYER M3 ;
      RECT 107.055 56.359 107.073 56.413 ;
    END
  END r0_rd_out[372]
  PIN r0_rd_out[373]
    DIRECTION OUTPUT ;
    USE SIGNAL ;
    SHAPE ABUTMENT ;
    PORT
      LAYER M3 ;
      RECT 107.343 56.359 107.361 56.413 ;
    END
  END r0_rd_out[373]
  PIN r0_rd_out[374]
    DIRECTION OUTPUT ;
    USE SIGNAL ;
    SHAPE ABUTMENT ;
    PORT
      LAYER M3 ;
      RECT 107.631 56.359 107.649 56.413 ;
    END
  END r0_rd_out[374]
  PIN r0_rd_out[375]
    DIRECTION OUTPUT ;
    USE SIGNAL ;
    SHAPE ABUTMENT ;
    PORT
      LAYER M3 ;
      RECT 107.919 56.359 107.937 56.413 ;
    END
  END r0_rd_out[375]
  PIN r0_rd_out[376]
    DIRECTION OUTPUT ;
    USE SIGNAL ;
    SHAPE ABUTMENT ;
    PORT
      LAYER M3 ;
      RECT 108.207 56.359 108.225 56.413 ;
    END
  END r0_rd_out[376]
  PIN r0_rd_out[377]
    DIRECTION OUTPUT ;
    USE SIGNAL ;
    SHAPE ABUTMENT ;
    PORT
      LAYER M3 ;
      RECT 108.495 56.359 108.513 56.413 ;
    END
  END r0_rd_out[377]
  PIN r0_rd_out[378]
    DIRECTION OUTPUT ;
    USE SIGNAL ;
    SHAPE ABUTMENT ;
    PORT
      LAYER M3 ;
      RECT 108.783 56.359 108.801 56.413 ;
    END
  END r0_rd_out[378]
  PIN r0_rd_out[379]
    DIRECTION OUTPUT ;
    USE SIGNAL ;
    SHAPE ABUTMENT ;
    PORT
      LAYER M3 ;
      RECT 109.071 56.359 109.089 56.413 ;
    END
  END r0_rd_out[379]
  PIN r0_rd_out[380]
    DIRECTION OUTPUT ;
    USE SIGNAL ;
    SHAPE ABUTMENT ;
    PORT
      LAYER M3 ;
      RECT 109.359 56.359 109.377 56.413 ;
    END
  END r0_rd_out[380]
  PIN r0_rd_out[381]
    DIRECTION OUTPUT ;
    USE SIGNAL ;
    SHAPE ABUTMENT ;
    PORT
      LAYER M3 ;
      RECT 109.647 56.359 109.665 56.413 ;
    END
  END r0_rd_out[381]
  PIN r0_rd_out[382]
    DIRECTION OUTPUT ;
    USE SIGNAL ;
    SHAPE ABUTMENT ;
    PORT
      LAYER M3 ;
      RECT 109.935 56.359 109.953 56.413 ;
    END
  END r0_rd_out[382]
  PIN r0_rd_out[383]
    DIRECTION OUTPUT ;
    USE SIGNAL ;
    SHAPE ABUTMENT ;
    PORT
      LAYER M3 ;
      RECT 110.223 56.359 110.241 56.413 ;
    END
  END r0_rd_out[383]
  PIN r0_rd_out[384]
    DIRECTION OUTPUT ;
    USE SIGNAL ;
    SHAPE ABUTMENT ;
    PORT
      LAYER M3 ;
      RECT 110.511 56.359 110.529 56.413 ;
    END
  END r0_rd_out[384]
  PIN r0_rd_out[385]
    DIRECTION OUTPUT ;
    USE SIGNAL ;
    SHAPE ABUTMENT ;
    PORT
      LAYER M3 ;
      RECT 110.799 56.359 110.817 56.413 ;
    END
  END r0_rd_out[385]
  PIN r0_rd_out[386]
    DIRECTION OUTPUT ;
    USE SIGNAL ;
    SHAPE ABUTMENT ;
    PORT
      LAYER M3 ;
      RECT 111.087 56.359 111.105 56.413 ;
    END
  END r0_rd_out[386]
  PIN r0_rd_out[387]
    DIRECTION OUTPUT ;
    USE SIGNAL ;
    SHAPE ABUTMENT ;
    PORT
      LAYER M3 ;
      RECT 111.375 56.359 111.393 56.413 ;
    END
  END r0_rd_out[387]
  PIN r0_rd_out[388]
    DIRECTION OUTPUT ;
    USE SIGNAL ;
    SHAPE ABUTMENT ;
    PORT
      LAYER M3 ;
      RECT 111.663 56.359 111.681 56.413 ;
    END
  END r0_rd_out[388]
  PIN r0_rd_out[389]
    DIRECTION OUTPUT ;
    USE SIGNAL ;
    SHAPE ABUTMENT ;
    PORT
      LAYER M3 ;
      RECT 111.951 56.359 111.969 56.413 ;
    END
  END r0_rd_out[389]
  PIN r0_rd_out[390]
    DIRECTION OUTPUT ;
    USE SIGNAL ;
    SHAPE ABUTMENT ;
    PORT
      LAYER M3 ;
      RECT 112.239 56.359 112.257 56.413 ;
    END
  END r0_rd_out[390]
  PIN r0_rd_out[391]
    DIRECTION OUTPUT ;
    USE SIGNAL ;
    SHAPE ABUTMENT ;
    PORT
      LAYER M3 ;
      RECT 112.527 56.359 112.545 56.413 ;
    END
  END r0_rd_out[391]
  PIN r0_rd_out[392]
    DIRECTION OUTPUT ;
    USE SIGNAL ;
    SHAPE ABUTMENT ;
    PORT
      LAYER M3 ;
      RECT 112.815 56.359 112.833 56.413 ;
    END
  END r0_rd_out[392]
  PIN r0_rd_out[393]
    DIRECTION OUTPUT ;
    USE SIGNAL ;
    SHAPE ABUTMENT ;
    PORT
      LAYER M3 ;
      RECT 113.103 56.359 113.121 56.413 ;
    END
  END r0_rd_out[393]
  PIN r0_rd_out[394]
    DIRECTION OUTPUT ;
    USE SIGNAL ;
    SHAPE ABUTMENT ;
    PORT
      LAYER M3 ;
      RECT 113.391 56.359 113.409 56.413 ;
    END
  END r0_rd_out[394]
  PIN r0_rd_out[395]
    DIRECTION OUTPUT ;
    USE SIGNAL ;
    SHAPE ABUTMENT ;
    PORT
      LAYER M3 ;
      RECT 113.679 56.359 113.697 56.413 ;
    END
  END r0_rd_out[395]
  PIN r0_rd_out[396]
    DIRECTION OUTPUT ;
    USE SIGNAL ;
    SHAPE ABUTMENT ;
    PORT
      LAYER M3 ;
      RECT 113.967 56.359 113.985 56.413 ;
    END
  END r0_rd_out[396]
  PIN r0_rd_out[397]
    DIRECTION OUTPUT ;
    USE SIGNAL ;
    SHAPE ABUTMENT ;
    PORT
      LAYER M3 ;
      RECT 114.255 56.359 114.273 56.413 ;
    END
  END r0_rd_out[397]
  PIN r0_rd_out[398]
    DIRECTION OUTPUT ;
    USE SIGNAL ;
    SHAPE ABUTMENT ;
    PORT
      LAYER M3 ;
      RECT 114.543 56.359 114.561 56.413 ;
    END
  END r0_rd_out[398]
  PIN r0_rd_out[399]
    DIRECTION OUTPUT ;
    USE SIGNAL ;
    SHAPE ABUTMENT ;
    PORT
      LAYER M3 ;
      RECT 114.831 56.359 114.849 56.413 ;
    END
  END r0_rd_out[399]
  PIN r0_rd_out[400]
    DIRECTION OUTPUT ;
    USE SIGNAL ;
    SHAPE ABUTMENT ;
    PORT
      LAYER M3 ;
      RECT 115.119 56.359 115.137 56.413 ;
    END
  END r0_rd_out[400]
  PIN r0_rd_out[401]
    DIRECTION OUTPUT ;
    USE SIGNAL ;
    SHAPE ABUTMENT ;
    PORT
      LAYER M3 ;
      RECT 115.407 56.359 115.425 56.413 ;
    END
  END r0_rd_out[401]
  PIN r0_rd_out[402]
    DIRECTION OUTPUT ;
    USE SIGNAL ;
    SHAPE ABUTMENT ;
    PORT
      LAYER M3 ;
      RECT 115.695 56.359 115.713 56.413 ;
    END
  END r0_rd_out[402]
  PIN r0_rd_out[403]
    DIRECTION OUTPUT ;
    USE SIGNAL ;
    SHAPE ABUTMENT ;
    PORT
      LAYER M3 ;
      RECT 115.983 56.359 116.001 56.413 ;
    END
  END r0_rd_out[403]
  PIN r0_rd_out[404]
    DIRECTION OUTPUT ;
    USE SIGNAL ;
    SHAPE ABUTMENT ;
    PORT
      LAYER M3 ;
      RECT 116.271 56.359 116.289 56.413 ;
    END
  END r0_rd_out[404]
  PIN r0_rd_out[405]
    DIRECTION OUTPUT ;
    USE SIGNAL ;
    SHAPE ABUTMENT ;
    PORT
      LAYER M3 ;
      RECT 116.559 56.359 116.577 56.413 ;
    END
  END r0_rd_out[405]
  PIN r0_rd_out[406]
    DIRECTION OUTPUT ;
    USE SIGNAL ;
    SHAPE ABUTMENT ;
    PORT
      LAYER M3 ;
      RECT 116.847 56.359 116.865 56.413 ;
    END
  END r0_rd_out[406]
  PIN r0_rd_out[407]
    DIRECTION OUTPUT ;
    USE SIGNAL ;
    SHAPE ABUTMENT ;
    PORT
      LAYER M3 ;
      RECT 117.135 56.359 117.153 56.413 ;
    END
  END r0_rd_out[407]
  PIN r0_rd_out[408]
    DIRECTION OUTPUT ;
    USE SIGNAL ;
    SHAPE ABUTMENT ;
    PORT
      LAYER M3 ;
      RECT 117.423 56.359 117.441 56.413 ;
    END
  END r0_rd_out[408]
  PIN r0_rd_out[409]
    DIRECTION OUTPUT ;
    USE SIGNAL ;
    SHAPE ABUTMENT ;
    PORT
      LAYER M3 ;
      RECT 117.711 56.359 117.729 56.413 ;
    END
  END r0_rd_out[409]
  PIN r0_rd_out[410]
    DIRECTION OUTPUT ;
    USE SIGNAL ;
    SHAPE ABUTMENT ;
    PORT
      LAYER M3 ;
      RECT 117.999 56.359 118.017 56.413 ;
    END
  END r0_rd_out[410]
  PIN r0_rd_out[411]
    DIRECTION OUTPUT ;
    USE SIGNAL ;
    SHAPE ABUTMENT ;
    PORT
      LAYER M3 ;
      RECT 118.287 56.359 118.305 56.413 ;
    END
  END r0_rd_out[411]
  PIN r0_rd_out[412]
    DIRECTION OUTPUT ;
    USE SIGNAL ;
    SHAPE ABUTMENT ;
    PORT
      LAYER M3 ;
      RECT 118.575 56.359 118.593 56.413 ;
    END
  END r0_rd_out[412]
  PIN r0_rd_out[413]
    DIRECTION OUTPUT ;
    USE SIGNAL ;
    SHAPE ABUTMENT ;
    PORT
      LAYER M3 ;
      RECT 118.863 56.359 118.881 56.413 ;
    END
  END r0_rd_out[413]
  PIN r0_rd_out[414]
    DIRECTION OUTPUT ;
    USE SIGNAL ;
    SHAPE ABUTMENT ;
    PORT
      LAYER M3 ;
      RECT 119.151 56.359 119.169 56.413 ;
    END
  END r0_rd_out[414]
  PIN r0_rd_out[415]
    DIRECTION OUTPUT ;
    USE SIGNAL ;
    SHAPE ABUTMENT ;
    PORT
      LAYER M3 ;
      RECT 119.439 56.359 119.457 56.413 ;
    END
  END r0_rd_out[415]
  PIN r0_rd_out[416]
    DIRECTION OUTPUT ;
    USE SIGNAL ;
    SHAPE ABUTMENT ;
    PORT
      LAYER M3 ;
      RECT 119.727 56.359 119.745 56.413 ;
    END
  END r0_rd_out[416]
  PIN r0_rd_out[417]
    DIRECTION OUTPUT ;
    USE SIGNAL ;
    SHAPE ABUTMENT ;
    PORT
      LAYER M3 ;
      RECT 120.015 56.359 120.033 56.413 ;
    END
  END r0_rd_out[417]
  PIN r0_rd_out[418]
    DIRECTION OUTPUT ;
    USE SIGNAL ;
    SHAPE ABUTMENT ;
    PORT
      LAYER M3 ;
      RECT 120.303 56.359 120.321 56.413 ;
    END
  END r0_rd_out[418]
  PIN r0_rd_out[419]
    DIRECTION OUTPUT ;
    USE SIGNAL ;
    SHAPE ABUTMENT ;
    PORT
      LAYER M3 ;
      RECT 120.591 56.359 120.609 56.413 ;
    END
  END r0_rd_out[419]
  PIN r0_rd_out[420]
    DIRECTION OUTPUT ;
    USE SIGNAL ;
    SHAPE ABUTMENT ;
    PORT
      LAYER M3 ;
      RECT 120.879 56.359 120.897 56.413 ;
    END
  END r0_rd_out[420]
  PIN r0_rd_out[421]
    DIRECTION OUTPUT ;
    USE SIGNAL ;
    SHAPE ABUTMENT ;
    PORT
      LAYER M3 ;
      RECT 121.167 56.359 121.185 56.413 ;
    END
  END r0_rd_out[421]
  PIN r0_rd_out[422]
    DIRECTION OUTPUT ;
    USE SIGNAL ;
    SHAPE ABUTMENT ;
    PORT
      LAYER M3 ;
      RECT 121.455 56.359 121.473 56.413 ;
    END
  END r0_rd_out[422]
  PIN r0_rd_out[423]
    DIRECTION OUTPUT ;
    USE SIGNAL ;
    SHAPE ABUTMENT ;
    PORT
      LAYER M3 ;
      RECT 121.743 56.359 121.761 56.413 ;
    END
  END r0_rd_out[423]
  PIN r0_rd_out[424]
    DIRECTION OUTPUT ;
    USE SIGNAL ;
    SHAPE ABUTMENT ;
    PORT
      LAYER M3 ;
      RECT 122.031 56.359 122.049 56.413 ;
    END
  END r0_rd_out[424]
  PIN r0_rd_out[425]
    DIRECTION OUTPUT ;
    USE SIGNAL ;
    SHAPE ABUTMENT ;
    PORT
      LAYER M3 ;
      RECT 122.319 56.359 122.337 56.413 ;
    END
  END r0_rd_out[425]
  PIN r0_rd_out[426]
    DIRECTION OUTPUT ;
    USE SIGNAL ;
    SHAPE ABUTMENT ;
    PORT
      LAYER M3 ;
      RECT 122.607 56.359 122.625 56.413 ;
    END
  END r0_rd_out[426]
  PIN r0_rd_out[427]
    DIRECTION OUTPUT ;
    USE SIGNAL ;
    SHAPE ABUTMENT ;
    PORT
      LAYER M3 ;
      RECT 122.895 56.359 122.913 56.413 ;
    END
  END r0_rd_out[427]
  PIN r0_rd_out[428]
    DIRECTION OUTPUT ;
    USE SIGNAL ;
    SHAPE ABUTMENT ;
    PORT
      LAYER M3 ;
      RECT 123.183 56.359 123.201 56.413 ;
    END
  END r0_rd_out[428]
  PIN r0_rd_out[429]
    DIRECTION OUTPUT ;
    USE SIGNAL ;
    SHAPE ABUTMENT ;
    PORT
      LAYER M3 ;
      RECT 123.471 56.359 123.489 56.413 ;
    END
  END r0_rd_out[429]
  PIN r0_rd_out[430]
    DIRECTION OUTPUT ;
    USE SIGNAL ;
    SHAPE ABUTMENT ;
    PORT
      LAYER M3 ;
      RECT 123.759 56.359 123.777 56.413 ;
    END
  END r0_rd_out[430]
  PIN r0_rd_out[431]
    DIRECTION OUTPUT ;
    USE SIGNAL ;
    SHAPE ABUTMENT ;
    PORT
      LAYER M3 ;
      RECT 124.047 56.359 124.065 56.413 ;
    END
  END r0_rd_out[431]
  PIN r0_rd_out[432]
    DIRECTION OUTPUT ;
    USE SIGNAL ;
    SHAPE ABUTMENT ;
    PORT
      LAYER M3 ;
      RECT 124.335 56.359 124.353 56.413 ;
    END
  END r0_rd_out[432]
  PIN r0_rd_out[433]
    DIRECTION OUTPUT ;
    USE SIGNAL ;
    SHAPE ABUTMENT ;
    PORT
      LAYER M3 ;
      RECT 124.623 56.359 124.641 56.413 ;
    END
  END r0_rd_out[433]
  PIN r0_rd_out[434]
    DIRECTION OUTPUT ;
    USE SIGNAL ;
    SHAPE ABUTMENT ;
    PORT
      LAYER M3 ;
      RECT 124.911 56.359 124.929 56.413 ;
    END
  END r0_rd_out[434]
  PIN r0_rd_out[435]
    DIRECTION OUTPUT ;
    USE SIGNAL ;
    SHAPE ABUTMENT ;
    PORT
      LAYER M3 ;
      RECT 125.199 56.359 125.217 56.413 ;
    END
  END r0_rd_out[435]
  PIN r0_rd_out[436]
    DIRECTION OUTPUT ;
    USE SIGNAL ;
    SHAPE ABUTMENT ;
    PORT
      LAYER M3 ;
      RECT 125.487 56.359 125.505 56.413 ;
    END
  END r0_rd_out[436]
  PIN r0_rd_out[437]
    DIRECTION OUTPUT ;
    USE SIGNAL ;
    SHAPE ABUTMENT ;
    PORT
      LAYER M3 ;
      RECT 125.775 56.359 125.793 56.413 ;
    END
  END r0_rd_out[437]
  PIN r0_rd_out[438]
    DIRECTION OUTPUT ;
    USE SIGNAL ;
    SHAPE ABUTMENT ;
    PORT
      LAYER M3 ;
      RECT 126.063 56.359 126.081 56.413 ;
    END
  END r0_rd_out[438]
  PIN r0_rd_out[439]
    DIRECTION OUTPUT ;
    USE SIGNAL ;
    SHAPE ABUTMENT ;
    PORT
      LAYER M3 ;
      RECT 126.351 56.359 126.369 56.413 ;
    END
  END r0_rd_out[439]
  PIN r0_rd_out[440]
    DIRECTION OUTPUT ;
    USE SIGNAL ;
    SHAPE ABUTMENT ;
    PORT
      LAYER M3 ;
      RECT 126.639 56.359 126.657 56.413 ;
    END
  END r0_rd_out[440]
  PIN r0_rd_out[441]
    DIRECTION OUTPUT ;
    USE SIGNAL ;
    SHAPE ABUTMENT ;
    PORT
      LAYER M3 ;
      RECT 126.927 56.359 126.945 56.413 ;
    END
  END r0_rd_out[441]
  PIN r0_rd_out[442]
    DIRECTION OUTPUT ;
    USE SIGNAL ;
    SHAPE ABUTMENT ;
    PORT
      LAYER M3 ;
      RECT 127.215 56.359 127.233 56.413 ;
    END
  END r0_rd_out[442]
  PIN r0_rd_out[443]
    DIRECTION OUTPUT ;
    USE SIGNAL ;
    SHAPE ABUTMENT ;
    PORT
      LAYER M3 ;
      RECT 127.503 56.359 127.521 56.413 ;
    END
  END r0_rd_out[443]
  PIN r0_rd_out[444]
    DIRECTION OUTPUT ;
    USE SIGNAL ;
    SHAPE ABUTMENT ;
    PORT
      LAYER M3 ;
      RECT 127.791 56.359 127.809 56.413 ;
    END
  END r0_rd_out[444]
  PIN r0_rd_out[445]
    DIRECTION OUTPUT ;
    USE SIGNAL ;
    SHAPE ABUTMENT ;
    PORT
      LAYER M3 ;
      RECT 128.079 56.359 128.097 56.413 ;
    END
  END r0_rd_out[445]
  PIN r0_rd_out[446]
    DIRECTION OUTPUT ;
    USE SIGNAL ;
    SHAPE ABUTMENT ;
    PORT
      LAYER M3 ;
      RECT 128.367 56.359 128.385 56.413 ;
    END
  END r0_rd_out[446]
  PIN r0_rd_out[447]
    DIRECTION OUTPUT ;
    USE SIGNAL ;
    SHAPE ABUTMENT ;
    PORT
      LAYER M3 ;
      RECT 128.655 56.359 128.673 56.413 ;
    END
  END r0_rd_out[447]
  PIN r0_rd_out[448]
    DIRECTION OUTPUT ;
    USE SIGNAL ;
    SHAPE ABUTMENT ;
    PORT
      LAYER M3 ;
      RECT 128.943 56.359 128.961 56.413 ;
    END
  END r0_rd_out[448]
  PIN r0_rd_out[449]
    DIRECTION OUTPUT ;
    USE SIGNAL ;
    SHAPE ABUTMENT ;
    PORT
      LAYER M3 ;
      RECT 129.231 56.359 129.249 56.413 ;
    END
  END r0_rd_out[449]
  PIN r0_rd_out[450]
    DIRECTION OUTPUT ;
    USE SIGNAL ;
    SHAPE ABUTMENT ;
    PORT
      LAYER M3 ;
      RECT 129.519 56.359 129.537 56.413 ;
    END
  END r0_rd_out[450]
  PIN r0_rd_out[451]
    DIRECTION OUTPUT ;
    USE SIGNAL ;
    SHAPE ABUTMENT ;
    PORT
      LAYER M3 ;
      RECT 129.807 56.359 129.825 56.413 ;
    END
  END r0_rd_out[451]
  PIN r0_rd_out[452]
    DIRECTION OUTPUT ;
    USE SIGNAL ;
    SHAPE ABUTMENT ;
    PORT
      LAYER M3 ;
      RECT 130.095 56.359 130.113 56.413 ;
    END
  END r0_rd_out[452]
  PIN r0_rd_out[453]
    DIRECTION OUTPUT ;
    USE SIGNAL ;
    SHAPE ABUTMENT ;
    PORT
      LAYER M3 ;
      RECT 130.383 56.359 130.401 56.413 ;
    END
  END r0_rd_out[453]
  PIN r0_rd_out[454]
    DIRECTION OUTPUT ;
    USE SIGNAL ;
    SHAPE ABUTMENT ;
    PORT
      LAYER M3 ;
      RECT 130.671 56.359 130.689 56.413 ;
    END
  END r0_rd_out[454]
  PIN r0_rd_out[455]
    DIRECTION OUTPUT ;
    USE SIGNAL ;
    SHAPE ABUTMENT ;
    PORT
      LAYER M3 ;
      RECT 130.959 56.359 130.977 56.413 ;
    END
  END r0_rd_out[455]
  PIN r0_rd_out[456]
    DIRECTION OUTPUT ;
    USE SIGNAL ;
    SHAPE ABUTMENT ;
    PORT
      LAYER M3 ;
      RECT 131.247 56.359 131.265 56.413 ;
    END
  END r0_rd_out[456]
  PIN r0_rd_out[457]
    DIRECTION OUTPUT ;
    USE SIGNAL ;
    SHAPE ABUTMENT ;
    PORT
      LAYER M3 ;
      RECT 131.535 56.359 131.553 56.413 ;
    END
  END r0_rd_out[457]
  PIN r0_rd_out[458]
    DIRECTION OUTPUT ;
    USE SIGNAL ;
    SHAPE ABUTMENT ;
    PORT
      LAYER M3 ;
      RECT 131.823 56.359 131.841 56.413 ;
    END
  END r0_rd_out[458]
  PIN r0_rd_out[459]
    DIRECTION OUTPUT ;
    USE SIGNAL ;
    SHAPE ABUTMENT ;
    PORT
      LAYER M3 ;
      RECT 132.111 56.359 132.129 56.413 ;
    END
  END r0_rd_out[459]
  PIN r0_rd_out[460]
    DIRECTION OUTPUT ;
    USE SIGNAL ;
    SHAPE ABUTMENT ;
    PORT
      LAYER M3 ;
      RECT 132.399 56.359 132.417 56.413 ;
    END
  END r0_rd_out[460]
  PIN r0_rd_out[461]
    DIRECTION OUTPUT ;
    USE SIGNAL ;
    SHAPE ABUTMENT ;
    PORT
      LAYER M3 ;
      RECT 132.687 56.359 132.705 56.413 ;
    END
  END r0_rd_out[461]
  PIN r0_rd_out[462]
    DIRECTION OUTPUT ;
    USE SIGNAL ;
    SHAPE ABUTMENT ;
    PORT
      LAYER M3 ;
      RECT 132.975 56.359 132.993 56.413 ;
    END
  END r0_rd_out[462]
  PIN r0_rd_out[463]
    DIRECTION OUTPUT ;
    USE SIGNAL ;
    SHAPE ABUTMENT ;
    PORT
      LAYER M3 ;
      RECT 133.263 56.359 133.281 56.413 ;
    END
  END r0_rd_out[463]
  PIN r0_rd_out[464]
    DIRECTION OUTPUT ;
    USE SIGNAL ;
    SHAPE ABUTMENT ;
    PORT
      LAYER M3 ;
      RECT 133.551 56.359 133.569 56.413 ;
    END
  END r0_rd_out[464]
  PIN r0_rd_out[465]
    DIRECTION OUTPUT ;
    USE SIGNAL ;
    SHAPE ABUTMENT ;
    PORT
      LAYER M3 ;
      RECT 133.839 56.359 133.857 56.413 ;
    END
  END r0_rd_out[465]
  PIN r0_rd_out[466]
    DIRECTION OUTPUT ;
    USE SIGNAL ;
    SHAPE ABUTMENT ;
    PORT
      LAYER M3 ;
      RECT 134.127 56.359 134.145 56.413 ;
    END
  END r0_rd_out[466]
  PIN r0_rd_out[467]
    DIRECTION OUTPUT ;
    USE SIGNAL ;
    SHAPE ABUTMENT ;
    PORT
      LAYER M3 ;
      RECT 134.415 56.359 134.433 56.413 ;
    END
  END r0_rd_out[467]
  PIN r0_rd_out[468]
    DIRECTION OUTPUT ;
    USE SIGNAL ;
    SHAPE ABUTMENT ;
    PORT
      LAYER M3 ;
      RECT 134.703 56.359 134.721 56.413 ;
    END
  END r0_rd_out[468]
  PIN r0_rd_out[469]
    DIRECTION OUTPUT ;
    USE SIGNAL ;
    SHAPE ABUTMENT ;
    PORT
      LAYER M3 ;
      RECT 134.991 56.359 135.009 56.413 ;
    END
  END r0_rd_out[469]
  PIN r0_rd_out[470]
    DIRECTION OUTPUT ;
    USE SIGNAL ;
    SHAPE ABUTMENT ;
    PORT
      LAYER M3 ;
      RECT 135.279 56.359 135.297 56.413 ;
    END
  END r0_rd_out[470]
  PIN r0_rd_out[471]
    DIRECTION OUTPUT ;
    USE SIGNAL ;
    SHAPE ABUTMENT ;
    PORT
      LAYER M3 ;
      RECT 135.567 56.359 135.585 56.413 ;
    END
  END r0_rd_out[471]
  PIN r0_rd_out[472]
    DIRECTION OUTPUT ;
    USE SIGNAL ;
    SHAPE ABUTMENT ;
    PORT
      LAYER M3 ;
      RECT 135.855 56.359 135.873 56.413 ;
    END
  END r0_rd_out[472]
  PIN r0_rd_out[473]
    DIRECTION OUTPUT ;
    USE SIGNAL ;
    SHAPE ABUTMENT ;
    PORT
      LAYER M3 ;
      RECT 136.143 56.359 136.161 56.413 ;
    END
  END r0_rd_out[473]
  PIN r0_rd_out[474]
    DIRECTION OUTPUT ;
    USE SIGNAL ;
    SHAPE ABUTMENT ;
    PORT
      LAYER M3 ;
      RECT 136.431 56.359 136.449 56.413 ;
    END
  END r0_rd_out[474]
  PIN r0_rd_out[475]
    DIRECTION OUTPUT ;
    USE SIGNAL ;
    SHAPE ABUTMENT ;
    PORT
      LAYER M3 ;
      RECT 136.719 56.359 136.737 56.413 ;
    END
  END r0_rd_out[475]
  PIN r0_rd_out[476]
    DIRECTION OUTPUT ;
    USE SIGNAL ;
    SHAPE ABUTMENT ;
    PORT
      LAYER M3 ;
      RECT 137.007 56.359 137.025 56.413 ;
    END
  END r0_rd_out[476]
  PIN r0_rd_out[477]
    DIRECTION OUTPUT ;
    USE SIGNAL ;
    SHAPE ABUTMENT ;
    PORT
      LAYER M3 ;
      RECT 137.295 56.359 137.313 56.413 ;
    END
  END r0_rd_out[477]
  PIN r0_rd_out[478]
    DIRECTION OUTPUT ;
    USE SIGNAL ;
    SHAPE ABUTMENT ;
    PORT
      LAYER M3 ;
      RECT 137.583 56.359 137.601 56.413 ;
    END
  END r0_rd_out[478]
  PIN r0_rd_out[479]
    DIRECTION OUTPUT ;
    USE SIGNAL ;
    SHAPE ABUTMENT ;
    PORT
      LAYER M3 ;
      RECT 137.871 56.359 137.889 56.413 ;
    END
  END r0_rd_out[479]
  PIN r0_rd_out[480]
    DIRECTION OUTPUT ;
    USE SIGNAL ;
    SHAPE ABUTMENT ;
    PORT
      LAYER M3 ;
      RECT 138.159 56.359 138.177 56.413 ;
    END
  END r0_rd_out[480]
  PIN r0_rd_out[481]
    DIRECTION OUTPUT ;
    USE SIGNAL ;
    SHAPE ABUTMENT ;
    PORT
      LAYER M3 ;
      RECT 138.447 56.359 138.465 56.413 ;
    END
  END r0_rd_out[481]
  PIN r0_rd_out[482]
    DIRECTION OUTPUT ;
    USE SIGNAL ;
    SHAPE ABUTMENT ;
    PORT
      LAYER M3 ;
      RECT 138.735 56.359 138.753 56.413 ;
    END
  END r0_rd_out[482]
  PIN r0_rd_out[483]
    DIRECTION OUTPUT ;
    USE SIGNAL ;
    SHAPE ABUTMENT ;
    PORT
      LAYER M3 ;
      RECT 139.023 56.359 139.041 56.413 ;
    END
  END r0_rd_out[483]
  PIN r0_rd_out[484]
    DIRECTION OUTPUT ;
    USE SIGNAL ;
    SHAPE ABUTMENT ;
    PORT
      LAYER M3 ;
      RECT 139.311 56.359 139.329 56.413 ;
    END
  END r0_rd_out[484]
  PIN r0_rd_out[485]
    DIRECTION OUTPUT ;
    USE SIGNAL ;
    SHAPE ABUTMENT ;
    PORT
      LAYER M3 ;
      RECT 139.599 56.359 139.617 56.413 ;
    END
  END r0_rd_out[485]
  PIN r0_rd_out[486]
    DIRECTION OUTPUT ;
    USE SIGNAL ;
    SHAPE ABUTMENT ;
    PORT
      LAYER M3 ;
      RECT 139.887 56.359 139.905 56.413 ;
    END
  END r0_rd_out[486]
  PIN r0_rd_out[487]
    DIRECTION OUTPUT ;
    USE SIGNAL ;
    SHAPE ABUTMENT ;
    PORT
      LAYER M3 ;
      RECT 140.175 56.359 140.193 56.413 ;
    END
  END r0_rd_out[487]
  PIN r0_rd_out[488]
    DIRECTION OUTPUT ;
    USE SIGNAL ;
    SHAPE ABUTMENT ;
    PORT
      LAYER M3 ;
      RECT 140.463 56.359 140.481 56.413 ;
    END
  END r0_rd_out[488]
  PIN r0_rd_out[489]
    DIRECTION OUTPUT ;
    USE SIGNAL ;
    SHAPE ABUTMENT ;
    PORT
      LAYER M3 ;
      RECT 140.751 56.359 140.769 56.413 ;
    END
  END r0_rd_out[489]
  PIN r0_rd_out[490]
    DIRECTION OUTPUT ;
    USE SIGNAL ;
    SHAPE ABUTMENT ;
    PORT
      LAYER M3 ;
      RECT 141.039 56.359 141.057 56.413 ;
    END
  END r0_rd_out[490]
  PIN r0_rd_out[491]
    DIRECTION OUTPUT ;
    USE SIGNAL ;
    SHAPE ABUTMENT ;
    PORT
      LAYER M3 ;
      RECT 141.327 56.359 141.345 56.413 ;
    END
  END r0_rd_out[491]
  PIN r0_rd_out[492]
    DIRECTION OUTPUT ;
    USE SIGNAL ;
    SHAPE ABUTMENT ;
    PORT
      LAYER M3 ;
      RECT 141.615 56.359 141.633 56.413 ;
    END
  END r0_rd_out[492]
  PIN r0_rd_out[493]
    DIRECTION OUTPUT ;
    USE SIGNAL ;
    SHAPE ABUTMENT ;
    PORT
      LAYER M3 ;
      RECT 141.903 56.359 141.921 56.413 ;
    END
  END r0_rd_out[493]
  PIN r0_rd_out[494]
    DIRECTION OUTPUT ;
    USE SIGNAL ;
    SHAPE ABUTMENT ;
    PORT
      LAYER M3 ;
      RECT 142.191 56.359 142.209 56.413 ;
    END
  END r0_rd_out[494]
  PIN r0_rd_out[495]
    DIRECTION OUTPUT ;
    USE SIGNAL ;
    SHAPE ABUTMENT ;
    PORT
      LAYER M3 ;
      RECT 142.479 56.359 142.497 56.413 ;
    END
  END r0_rd_out[495]
  PIN r0_rd_out[496]
    DIRECTION OUTPUT ;
    USE SIGNAL ;
    SHAPE ABUTMENT ;
    PORT
      LAYER M3 ;
      RECT 142.767 56.359 142.785 56.413 ;
    END
  END r0_rd_out[496]
  PIN r0_rd_out[497]
    DIRECTION OUTPUT ;
    USE SIGNAL ;
    SHAPE ABUTMENT ;
    PORT
      LAYER M3 ;
      RECT 143.055 56.359 143.073 56.413 ;
    END
  END r0_rd_out[497]
  PIN r0_rd_out[498]
    DIRECTION OUTPUT ;
    USE SIGNAL ;
    SHAPE ABUTMENT ;
    PORT
      LAYER M3 ;
      RECT 143.343 56.359 143.361 56.413 ;
    END
  END r0_rd_out[498]
  PIN r0_rd_out[499]
    DIRECTION OUTPUT ;
    USE SIGNAL ;
    SHAPE ABUTMENT ;
    PORT
      LAYER M3 ;
      RECT 143.631 56.359 143.649 56.413 ;
    END
  END r0_rd_out[499]
  PIN r0_rd_out[500]
    DIRECTION OUTPUT ;
    USE SIGNAL ;
    SHAPE ABUTMENT ;
    PORT
      LAYER M3 ;
      RECT 143.919 56.359 143.937 56.413 ;
    END
  END r0_rd_out[500]
  PIN r0_rd_out[501]
    DIRECTION OUTPUT ;
    USE SIGNAL ;
    SHAPE ABUTMENT ;
    PORT
      LAYER M3 ;
      RECT 144.207 56.359 144.225 56.413 ;
    END
  END r0_rd_out[501]
  PIN r0_rd_out[502]
    DIRECTION OUTPUT ;
    USE SIGNAL ;
    SHAPE ABUTMENT ;
    PORT
      LAYER M3 ;
      RECT 144.495 56.359 144.513 56.413 ;
    END
  END r0_rd_out[502]
  PIN r0_rd_out[503]
    DIRECTION OUTPUT ;
    USE SIGNAL ;
    SHAPE ABUTMENT ;
    PORT
      LAYER M3 ;
      RECT 144.783 56.359 144.801 56.413 ;
    END
  END r0_rd_out[503]
  PIN r0_rd_out[504]
    DIRECTION OUTPUT ;
    USE SIGNAL ;
    SHAPE ABUTMENT ;
    PORT
      LAYER M3 ;
      RECT 145.071 56.359 145.089 56.413 ;
    END
  END r0_rd_out[504]
  PIN r0_rd_out[505]
    DIRECTION OUTPUT ;
    USE SIGNAL ;
    SHAPE ABUTMENT ;
    PORT
      LAYER M3 ;
      RECT 145.359 56.359 145.377 56.413 ;
    END
  END r0_rd_out[505]
  PIN r0_rd_out[506]
    DIRECTION OUTPUT ;
    USE SIGNAL ;
    SHAPE ABUTMENT ;
    PORT
      LAYER M3 ;
      RECT 145.647 56.359 145.665 56.413 ;
    END
  END r0_rd_out[506]
  PIN r0_rd_out[507]
    DIRECTION OUTPUT ;
    USE SIGNAL ;
    SHAPE ABUTMENT ;
    PORT
      LAYER M3 ;
      RECT 145.935 56.359 145.953 56.413 ;
    END
  END r0_rd_out[507]
  PIN r0_rd_out[508]
    DIRECTION OUTPUT ;
    USE SIGNAL ;
    SHAPE ABUTMENT ;
    PORT
      LAYER M3 ;
      RECT 146.223 56.359 146.241 56.413 ;
    END
  END r0_rd_out[508]
  PIN r0_rd_out[509]
    DIRECTION OUTPUT ;
    USE SIGNAL ;
    SHAPE ABUTMENT ;
    PORT
      LAYER M3 ;
      RECT 146.511 56.359 146.529 56.413 ;
    END
  END r0_rd_out[509]
  PIN r0_rd_out[510]
    DIRECTION OUTPUT ;
    USE SIGNAL ;
    SHAPE ABUTMENT ;
    PORT
      LAYER M3 ;
      RECT 146.799 56.359 146.817 56.413 ;
    END
  END r0_rd_out[510]
  PIN r0_rd_out[511]
    DIRECTION OUTPUT ;
    USE SIGNAL ;
    SHAPE ABUTMENT ;
    PORT
      LAYER M3 ;
      RECT 147.087 56.359 147.105 56.413 ;
    END
  END r0_rd_out[511]
  PIN r0_rd_out[512]
    DIRECTION OUTPUT ;
    USE SIGNAL ;
    SHAPE ABUTMENT ;
    PORT
      LAYER M3 ;
      RECT 147.375 56.359 147.393 56.413 ;
    END
  END r0_rd_out[512]
  PIN r0_rd_out[513]
    DIRECTION OUTPUT ;
    USE SIGNAL ;
    SHAPE ABUTMENT ;
    PORT
      LAYER M3 ;
      RECT 147.663 56.359 147.681 56.413 ;
    END
  END r0_rd_out[513]
  PIN r0_rd_out[514]
    DIRECTION OUTPUT ;
    USE SIGNAL ;
    SHAPE ABUTMENT ;
    PORT
      LAYER M3 ;
      RECT 147.951 56.359 147.969 56.413 ;
    END
  END r0_rd_out[514]
  PIN r0_rd_out[515]
    DIRECTION OUTPUT ;
    USE SIGNAL ;
    SHAPE ABUTMENT ;
    PORT
      LAYER M3 ;
      RECT 148.239 56.359 148.257 56.413 ;
    END
  END r0_rd_out[515]
  PIN r0_rd_out[516]
    DIRECTION OUTPUT ;
    USE SIGNAL ;
    SHAPE ABUTMENT ;
    PORT
      LAYER M3 ;
      RECT 148.527 56.359 148.545 56.413 ;
    END
  END r0_rd_out[516]
  PIN r0_rd_out[517]
    DIRECTION OUTPUT ;
    USE SIGNAL ;
    SHAPE ABUTMENT ;
    PORT
      LAYER M3 ;
      RECT 148.815 56.359 148.833 56.413 ;
    END
  END r0_rd_out[517]
  PIN r0_rd_out[518]
    DIRECTION OUTPUT ;
    USE SIGNAL ;
    SHAPE ABUTMENT ;
    PORT
      LAYER M3 ;
      RECT 149.103 56.359 149.121 56.413 ;
    END
  END r0_rd_out[518]
  PIN r0_rd_out[519]
    DIRECTION OUTPUT ;
    USE SIGNAL ;
    SHAPE ABUTMENT ;
    PORT
      LAYER M3 ;
      RECT 149.391 56.359 149.409 56.413 ;
    END
  END r0_rd_out[519]
  PIN r0_rd_out[520]
    DIRECTION OUTPUT ;
    USE SIGNAL ;
    SHAPE ABUTMENT ;
    PORT
      LAYER M3 ;
      RECT 149.679 56.359 149.697 56.413 ;
    END
  END r0_rd_out[520]
  PIN r0_rd_out[521]
    DIRECTION OUTPUT ;
    USE SIGNAL ;
    SHAPE ABUTMENT ;
    PORT
      LAYER M3 ;
      RECT 149.967 56.359 149.985 56.413 ;
    END
  END r0_rd_out[521]
  PIN r0_rd_out[522]
    DIRECTION OUTPUT ;
    USE SIGNAL ;
    SHAPE ABUTMENT ;
    PORT
      LAYER M3 ;
      RECT 150.255 56.359 150.273 56.413 ;
    END
  END r0_rd_out[522]
  PIN r0_rd_out[523]
    DIRECTION OUTPUT ;
    USE SIGNAL ;
    SHAPE ABUTMENT ;
    PORT
      LAYER M3 ;
      RECT 150.543 56.359 150.561 56.413 ;
    END
  END r0_rd_out[523]
  PIN r0_rd_out[524]
    DIRECTION OUTPUT ;
    USE SIGNAL ;
    SHAPE ABUTMENT ;
    PORT
      LAYER M3 ;
      RECT 150.831 56.359 150.849 56.413 ;
    END
  END r0_rd_out[524]
  PIN r0_rd_out[525]
    DIRECTION OUTPUT ;
    USE SIGNAL ;
    SHAPE ABUTMENT ;
    PORT
      LAYER M3 ;
      RECT 151.119 56.359 151.137 56.413 ;
    END
  END r0_rd_out[525]
  PIN r0_rd_out[526]
    DIRECTION OUTPUT ;
    USE SIGNAL ;
    SHAPE ABUTMENT ;
    PORT
      LAYER M3 ;
      RECT 151.407 56.359 151.425 56.413 ;
    END
  END r0_rd_out[526]
  PIN r0_rd_out[527]
    DIRECTION OUTPUT ;
    USE SIGNAL ;
    SHAPE ABUTMENT ;
    PORT
      LAYER M3 ;
      RECT 151.695 56.359 151.713 56.413 ;
    END
  END r0_rd_out[527]
  PIN r0_rd_out[528]
    DIRECTION OUTPUT ;
    USE SIGNAL ;
    SHAPE ABUTMENT ;
    PORT
      LAYER M3 ;
      RECT 151.983 56.359 152.001 56.413 ;
    END
  END r0_rd_out[528]
  PIN r0_rd_out[529]
    DIRECTION OUTPUT ;
    USE SIGNAL ;
    SHAPE ABUTMENT ;
    PORT
      LAYER M3 ;
      RECT 152.271 56.359 152.289 56.413 ;
    END
  END r0_rd_out[529]
  PIN r0_rd_out[530]
    DIRECTION OUTPUT ;
    USE SIGNAL ;
    SHAPE ABUTMENT ;
    PORT
      LAYER M3 ;
      RECT 152.559 56.359 152.577 56.413 ;
    END
  END r0_rd_out[530]
  PIN r0_rd_out[531]
    DIRECTION OUTPUT ;
    USE SIGNAL ;
    SHAPE ABUTMENT ;
    PORT
      LAYER M3 ;
      RECT 152.847 56.359 152.865 56.413 ;
    END
  END r0_rd_out[531]
  PIN r0_rd_out[532]
    DIRECTION OUTPUT ;
    USE SIGNAL ;
    SHAPE ABUTMENT ;
    PORT
      LAYER M3 ;
      RECT 153.135 56.359 153.153 56.413 ;
    END
  END r0_rd_out[532]
  PIN r0_rd_out[533]
    DIRECTION OUTPUT ;
    USE SIGNAL ;
    SHAPE ABUTMENT ;
    PORT
      LAYER M3 ;
      RECT 153.423 56.359 153.441 56.413 ;
    END
  END r0_rd_out[533]
  PIN r0_rd_out[534]
    DIRECTION OUTPUT ;
    USE SIGNAL ;
    SHAPE ABUTMENT ;
    PORT
      LAYER M3 ;
      RECT 153.711 56.359 153.729 56.413 ;
    END
  END r0_rd_out[534]
  PIN r0_rd_out[535]
    DIRECTION OUTPUT ;
    USE SIGNAL ;
    SHAPE ABUTMENT ;
    PORT
      LAYER M3 ;
      RECT 153.999 56.359 154.017 56.413 ;
    END
  END r0_rd_out[535]
  PIN r0_rd_out[536]
    DIRECTION OUTPUT ;
    USE SIGNAL ;
    SHAPE ABUTMENT ;
    PORT
      LAYER M3 ;
      RECT 154.287 56.359 154.305 56.413 ;
    END
  END r0_rd_out[536]
  PIN r0_rd_out[537]
    DIRECTION OUTPUT ;
    USE SIGNAL ;
    SHAPE ABUTMENT ;
    PORT
      LAYER M3 ;
      RECT 154.575 56.359 154.593 56.413 ;
    END
  END r0_rd_out[537]
  PIN r0_rd_out[538]
    DIRECTION OUTPUT ;
    USE SIGNAL ;
    SHAPE ABUTMENT ;
    PORT
      LAYER M3 ;
      RECT 154.863 56.359 154.881 56.413 ;
    END
  END r0_rd_out[538]
  PIN r0_rd_out[539]
    DIRECTION OUTPUT ;
    USE SIGNAL ;
    SHAPE ABUTMENT ;
    PORT
      LAYER M3 ;
      RECT 155.151 56.359 155.169 56.413 ;
    END
  END r0_rd_out[539]
  PIN r0_rd_out[540]
    DIRECTION OUTPUT ;
    USE SIGNAL ;
    SHAPE ABUTMENT ;
    PORT
      LAYER M3 ;
      RECT 155.439 56.359 155.457 56.413 ;
    END
  END r0_rd_out[540]
  PIN r0_rd_out[541]
    DIRECTION OUTPUT ;
    USE SIGNAL ;
    SHAPE ABUTMENT ;
    PORT
      LAYER M3 ;
      RECT 155.727 56.359 155.745 56.413 ;
    END
  END r0_rd_out[541]
  PIN r0_rd_out[542]
    DIRECTION OUTPUT ;
    USE SIGNAL ;
    SHAPE ABUTMENT ;
    PORT
      LAYER M3 ;
      RECT 156.015 56.359 156.033 56.413 ;
    END
  END r0_rd_out[542]
  PIN r0_rd_out[543]
    DIRECTION OUTPUT ;
    USE SIGNAL ;
    SHAPE ABUTMENT ;
    PORT
      LAYER M3 ;
      RECT 156.303 56.359 156.321 56.413 ;
    END
  END r0_rd_out[543]
  PIN r0_rd_out[544]
    DIRECTION OUTPUT ;
    USE SIGNAL ;
    SHAPE ABUTMENT ;
    PORT
      LAYER M3 ;
      RECT 156.591 56.359 156.609 56.413 ;
    END
  END r0_rd_out[544]
  PIN r0_rd_out[545]
    DIRECTION OUTPUT ;
    USE SIGNAL ;
    SHAPE ABUTMENT ;
    PORT
      LAYER M3 ;
      RECT 156.879 56.359 156.897 56.413 ;
    END
  END r0_rd_out[545]
  PIN r0_rd_out[546]
    DIRECTION OUTPUT ;
    USE SIGNAL ;
    SHAPE ABUTMENT ;
    PORT
      LAYER M3 ;
      RECT 157.167 56.359 157.185 56.413 ;
    END
  END r0_rd_out[546]
  PIN r0_rd_out[547]
    DIRECTION OUTPUT ;
    USE SIGNAL ;
    SHAPE ABUTMENT ;
    PORT
      LAYER M3 ;
      RECT 157.455 56.359 157.473 56.413 ;
    END
  END r0_rd_out[547]
  PIN r0_rd_out[548]
    DIRECTION OUTPUT ;
    USE SIGNAL ;
    SHAPE ABUTMENT ;
    PORT
      LAYER M3 ;
      RECT 157.743 56.359 157.761 56.413 ;
    END
  END r0_rd_out[548]
  PIN r0_rd_out[549]
    DIRECTION OUTPUT ;
    USE SIGNAL ;
    SHAPE ABUTMENT ;
    PORT
      LAYER M3 ;
      RECT 158.031 56.359 158.049 56.413 ;
    END
  END r0_rd_out[549]
  PIN r0_rd_out[550]
    DIRECTION OUTPUT ;
    USE SIGNAL ;
    SHAPE ABUTMENT ;
    PORT
      LAYER M3 ;
      RECT 158.319 56.359 158.337 56.413 ;
    END
  END r0_rd_out[550]
  PIN r0_rd_out[551]
    DIRECTION OUTPUT ;
    USE SIGNAL ;
    SHAPE ABUTMENT ;
    PORT
      LAYER M3 ;
      RECT 158.607 56.359 158.625 56.413 ;
    END
  END r0_rd_out[551]
  PIN r0_rd_out[552]
    DIRECTION OUTPUT ;
    USE SIGNAL ;
    SHAPE ABUTMENT ;
    PORT
      LAYER M3 ;
      RECT 158.895 56.359 158.913 56.413 ;
    END
  END r0_rd_out[552]
  PIN r0_rd_out[553]
    DIRECTION OUTPUT ;
    USE SIGNAL ;
    SHAPE ABUTMENT ;
    PORT
      LAYER M3 ;
      RECT 159.183 56.359 159.201 56.413 ;
    END
  END r0_rd_out[553]
  PIN r0_rd_out[554]
    DIRECTION OUTPUT ;
    USE SIGNAL ;
    SHAPE ABUTMENT ;
    PORT
      LAYER M3 ;
      RECT 159.471 56.359 159.489 56.413 ;
    END
  END r0_rd_out[554]
  PIN r0_rd_out[555]
    DIRECTION OUTPUT ;
    USE SIGNAL ;
    SHAPE ABUTMENT ;
    PORT
      LAYER M3 ;
      RECT 159.759 56.359 159.777 56.413 ;
    END
  END r0_rd_out[555]
  PIN r0_rd_out[556]
    DIRECTION OUTPUT ;
    USE SIGNAL ;
    SHAPE ABUTMENT ;
    PORT
      LAYER M3 ;
      RECT 160.047 56.359 160.065 56.413 ;
    END
  END r0_rd_out[556]
  PIN r0_rd_out[557]
    DIRECTION OUTPUT ;
    USE SIGNAL ;
    SHAPE ABUTMENT ;
    PORT
      LAYER M3 ;
      RECT 160.335 56.359 160.353 56.413 ;
    END
  END r0_rd_out[557]
  PIN r0_rd_out[558]
    DIRECTION OUTPUT ;
    USE SIGNAL ;
    SHAPE ABUTMENT ;
    PORT
      LAYER M3 ;
      RECT 160.623 56.359 160.641 56.413 ;
    END
  END r0_rd_out[558]
  PIN r0_rd_out[559]
    DIRECTION OUTPUT ;
    USE SIGNAL ;
    SHAPE ABUTMENT ;
    PORT
      LAYER M3 ;
      RECT 160.911 56.359 160.929 56.413 ;
    END
  END r0_rd_out[559]
  PIN r0_rd_out[560]
    DIRECTION OUTPUT ;
    USE SIGNAL ;
    SHAPE ABUTMENT ;
    PORT
      LAYER M3 ;
      RECT 161.199 56.359 161.217 56.413 ;
    END
  END r0_rd_out[560]
  PIN r0_rd_out[561]
    DIRECTION OUTPUT ;
    USE SIGNAL ;
    SHAPE ABUTMENT ;
    PORT
      LAYER M3 ;
      RECT 161.487 56.359 161.505 56.413 ;
    END
  END r0_rd_out[561]
  PIN r0_rd_out[562]
    DIRECTION OUTPUT ;
    USE SIGNAL ;
    SHAPE ABUTMENT ;
    PORT
      LAYER M3 ;
      RECT 161.775 56.359 161.793 56.413 ;
    END
  END r0_rd_out[562]
  PIN r0_rd_out[563]
    DIRECTION OUTPUT ;
    USE SIGNAL ;
    SHAPE ABUTMENT ;
    PORT
      LAYER M3 ;
      RECT 162.063 56.359 162.081 56.413 ;
    END
  END r0_rd_out[563]
  PIN r0_rd_out[564]
    DIRECTION OUTPUT ;
    USE SIGNAL ;
    SHAPE ABUTMENT ;
    PORT
      LAYER M3 ;
      RECT 162.351 56.359 162.369 56.413 ;
    END
  END r0_rd_out[564]
  PIN r0_rd_out[565]
    DIRECTION OUTPUT ;
    USE SIGNAL ;
    SHAPE ABUTMENT ;
    PORT
      LAYER M3 ;
      RECT 162.639 56.359 162.657 56.413 ;
    END
  END r0_rd_out[565]
  PIN r0_rd_out[566]
    DIRECTION OUTPUT ;
    USE SIGNAL ;
    SHAPE ABUTMENT ;
    PORT
      LAYER M3 ;
      RECT 162.927 56.359 162.945 56.413 ;
    END
  END r0_rd_out[566]
  PIN r0_rd_out[567]
    DIRECTION OUTPUT ;
    USE SIGNAL ;
    SHAPE ABUTMENT ;
    PORT
      LAYER M3 ;
      RECT 163.215 56.359 163.233 56.413 ;
    END
  END r0_rd_out[567]
  PIN r0_rd_out[568]
    DIRECTION OUTPUT ;
    USE SIGNAL ;
    SHAPE ABUTMENT ;
    PORT
      LAYER M3 ;
      RECT 163.503 56.359 163.521 56.413 ;
    END
  END r0_rd_out[568]
  PIN r0_rd_out[569]
    DIRECTION OUTPUT ;
    USE SIGNAL ;
    SHAPE ABUTMENT ;
    PORT
      LAYER M3 ;
      RECT 163.791 56.359 163.809 56.413 ;
    END
  END r0_rd_out[569]
  PIN r0_rd_out[570]
    DIRECTION OUTPUT ;
    USE SIGNAL ;
    SHAPE ABUTMENT ;
    PORT
      LAYER M3 ;
      RECT 164.079 56.359 164.097 56.413 ;
    END
  END r0_rd_out[570]
  PIN r0_rd_out[571]
    DIRECTION OUTPUT ;
    USE SIGNAL ;
    SHAPE ABUTMENT ;
    PORT
      LAYER M3 ;
      RECT 164.367 56.359 164.385 56.413 ;
    END
  END r0_rd_out[571]
  PIN r0_rd_out[572]
    DIRECTION OUTPUT ;
    USE SIGNAL ;
    SHAPE ABUTMENT ;
    PORT
      LAYER M3 ;
      RECT 164.655 56.359 164.673 56.413 ;
    END
  END r0_rd_out[572]
  PIN r0_rd_out[573]
    DIRECTION OUTPUT ;
    USE SIGNAL ;
    SHAPE ABUTMENT ;
    PORT
      LAYER M3 ;
      RECT 164.943 56.359 164.961 56.413 ;
    END
  END r0_rd_out[573]
  PIN r0_rd_out[574]
    DIRECTION OUTPUT ;
    USE SIGNAL ;
    SHAPE ABUTMENT ;
    PORT
      LAYER M3 ;
      RECT 165.231 56.359 165.249 56.413 ;
    END
  END r0_rd_out[574]
  PIN r0_rd_out[575]
    DIRECTION OUTPUT ;
    USE SIGNAL ;
    SHAPE ABUTMENT ;
    PORT
      LAYER M3 ;
      RECT 165.519 56.359 165.537 56.413 ;
    END
  END r0_rd_out[575]
  PIN r0_rd_out[576]
    DIRECTION OUTPUT ;
    USE SIGNAL ;
    SHAPE ABUTMENT ;
    PORT
      LAYER M3 ;
      RECT 165.807 56.359 165.825 56.413 ;
    END
  END r0_rd_out[576]
  PIN r0_rd_out[577]
    DIRECTION OUTPUT ;
    USE SIGNAL ;
    SHAPE ABUTMENT ;
    PORT
      LAYER M3 ;
      RECT 166.095 56.359 166.113 56.413 ;
    END
  END r0_rd_out[577]
  PIN r0_rd_out[578]
    DIRECTION OUTPUT ;
    USE SIGNAL ;
    SHAPE ABUTMENT ;
    PORT
      LAYER M3 ;
      RECT 166.383 56.359 166.401 56.413 ;
    END
  END r0_rd_out[578]
  PIN r0_rd_out[579]
    DIRECTION OUTPUT ;
    USE SIGNAL ;
    SHAPE ABUTMENT ;
    PORT
      LAYER M3 ;
      RECT 166.671 56.359 166.689 56.413 ;
    END
  END r0_rd_out[579]
  PIN r0_rd_out[580]
    DIRECTION OUTPUT ;
    USE SIGNAL ;
    SHAPE ABUTMENT ;
    PORT
      LAYER M3 ;
      RECT 166.959 56.359 166.977 56.413 ;
    END
  END r0_rd_out[580]
  PIN r0_rd_out[581]
    DIRECTION OUTPUT ;
    USE SIGNAL ;
    SHAPE ABUTMENT ;
    PORT
      LAYER M3 ;
      RECT 167.247 56.359 167.265 56.413 ;
    END
  END r0_rd_out[581]
  PIN r0_rd_out[582]
    DIRECTION OUTPUT ;
    USE SIGNAL ;
    SHAPE ABUTMENT ;
    PORT
      LAYER M3 ;
      RECT 167.535 56.359 167.553 56.413 ;
    END
  END r0_rd_out[582]
  PIN r0_rd_out[583]
    DIRECTION OUTPUT ;
    USE SIGNAL ;
    SHAPE ABUTMENT ;
    PORT
      LAYER M3 ;
      RECT 167.823 56.359 167.841 56.413 ;
    END
  END r0_rd_out[583]
  PIN r0_rd_out[584]
    DIRECTION OUTPUT ;
    USE SIGNAL ;
    SHAPE ABUTMENT ;
    PORT
      LAYER M3 ;
      RECT 168.111 56.359 168.129 56.413 ;
    END
  END r0_rd_out[584]
  PIN r0_rd_out[585]
    DIRECTION OUTPUT ;
    USE SIGNAL ;
    SHAPE ABUTMENT ;
    PORT
      LAYER M3 ;
      RECT 168.399 56.359 168.417 56.413 ;
    END
  END r0_rd_out[585]
  PIN r0_rd_out[586]
    DIRECTION OUTPUT ;
    USE SIGNAL ;
    SHAPE ABUTMENT ;
    PORT
      LAYER M3 ;
      RECT 168.687 56.359 168.705 56.413 ;
    END
  END r0_rd_out[586]
  PIN r0_rd_out[587]
    DIRECTION OUTPUT ;
    USE SIGNAL ;
    SHAPE ABUTMENT ;
    PORT
      LAYER M3 ;
      RECT 168.975 56.359 168.993 56.413 ;
    END
  END r0_rd_out[587]
  PIN r0_rd_out[588]
    DIRECTION OUTPUT ;
    USE SIGNAL ;
    SHAPE ABUTMENT ;
    PORT
      LAYER M3 ;
      RECT 169.263 56.359 169.281 56.413 ;
    END
  END r0_rd_out[588]
  PIN r0_rd_out[589]
    DIRECTION OUTPUT ;
    USE SIGNAL ;
    SHAPE ABUTMENT ;
    PORT
      LAYER M3 ;
      RECT 169.551 56.359 169.569 56.413 ;
    END
  END r0_rd_out[589]
  PIN r0_rd_out[590]
    DIRECTION OUTPUT ;
    USE SIGNAL ;
    SHAPE ABUTMENT ;
    PORT
      LAYER M3 ;
      RECT 169.839 56.359 169.857 56.413 ;
    END
  END r0_rd_out[590]
  PIN r0_rd_out[591]
    DIRECTION OUTPUT ;
    USE SIGNAL ;
    SHAPE ABUTMENT ;
    PORT
      LAYER M3 ;
      RECT 170.127 56.359 170.145 56.413 ;
    END
  END r0_rd_out[591]
  PIN r0_rd_out[592]
    DIRECTION OUTPUT ;
    USE SIGNAL ;
    SHAPE ABUTMENT ;
    PORT
      LAYER M3 ;
      RECT 170.415 56.359 170.433 56.413 ;
    END
  END r0_rd_out[592]
  PIN r0_rd_out[593]
    DIRECTION OUTPUT ;
    USE SIGNAL ;
    SHAPE ABUTMENT ;
    PORT
      LAYER M3 ;
      RECT 170.703 56.359 170.721 56.413 ;
    END
  END r0_rd_out[593]
  PIN r0_rd_out[594]
    DIRECTION OUTPUT ;
    USE SIGNAL ;
    SHAPE ABUTMENT ;
    PORT
      LAYER M3 ;
      RECT 170.991 56.359 171.009 56.413 ;
    END
  END r0_rd_out[594]
  PIN r0_rd_out[595]
    DIRECTION OUTPUT ;
    USE SIGNAL ;
    SHAPE ABUTMENT ;
    PORT
      LAYER M3 ;
      RECT 171.279 56.359 171.297 56.413 ;
    END
  END r0_rd_out[595]
  PIN r0_rd_out[596]
    DIRECTION OUTPUT ;
    USE SIGNAL ;
    SHAPE ABUTMENT ;
    PORT
      LAYER M3 ;
      RECT 171.567 56.359 171.585 56.413 ;
    END
  END r0_rd_out[596]
  PIN r0_rd_out[597]
    DIRECTION OUTPUT ;
    USE SIGNAL ;
    SHAPE ABUTMENT ;
    PORT
      LAYER M3 ;
      RECT 171.855 56.359 171.873 56.413 ;
    END
  END r0_rd_out[597]
  PIN r0_rd_out[598]
    DIRECTION OUTPUT ;
    USE SIGNAL ;
    SHAPE ABUTMENT ;
    PORT
      LAYER M3 ;
      RECT 172.143 56.359 172.161 56.413 ;
    END
  END r0_rd_out[598]
  PIN r0_rd_out[599]
    DIRECTION OUTPUT ;
    USE SIGNAL ;
    SHAPE ABUTMENT ;
    PORT
      LAYER M3 ;
      RECT 172.431 56.359 172.449 56.413 ;
    END
  END r0_rd_out[599]
  PIN r0_rd_out[600]
    DIRECTION OUTPUT ;
    USE SIGNAL ;
    SHAPE ABUTMENT ;
    PORT
      LAYER M3 ;
      RECT 172.719 56.359 172.737 56.413 ;
    END
  END r0_rd_out[600]
  PIN r0_rd_out[601]
    DIRECTION OUTPUT ;
    USE SIGNAL ;
    SHAPE ABUTMENT ;
    PORT
      LAYER M3 ;
      RECT 173.007 56.359 173.025 56.413 ;
    END
  END r0_rd_out[601]
  PIN r0_rd_out[602]
    DIRECTION OUTPUT ;
    USE SIGNAL ;
    SHAPE ABUTMENT ;
    PORT
      LAYER M3 ;
      RECT 173.295 56.359 173.313 56.413 ;
    END
  END r0_rd_out[602]
  PIN r0_rd_out[603]
    DIRECTION OUTPUT ;
    USE SIGNAL ;
    SHAPE ABUTMENT ;
    PORT
      LAYER M3 ;
      RECT 173.583 56.359 173.601 56.413 ;
    END
  END r0_rd_out[603]
  PIN r0_rd_out[604]
    DIRECTION OUTPUT ;
    USE SIGNAL ;
    SHAPE ABUTMENT ;
    PORT
      LAYER M3 ;
      RECT 173.871 56.359 173.889 56.413 ;
    END
  END r0_rd_out[604]
  PIN r0_rd_out[605]
    DIRECTION OUTPUT ;
    USE SIGNAL ;
    SHAPE ABUTMENT ;
    PORT
      LAYER M3 ;
      RECT 174.159 56.359 174.177 56.413 ;
    END
  END r0_rd_out[605]
  PIN r0_rd_out[606]
    DIRECTION OUTPUT ;
    USE SIGNAL ;
    SHAPE ABUTMENT ;
    PORT
      LAYER M3 ;
      RECT 174.447 56.359 174.465 56.413 ;
    END
  END r0_rd_out[606]
  PIN r0_rd_out[607]
    DIRECTION OUTPUT ;
    USE SIGNAL ;
    SHAPE ABUTMENT ;
    PORT
      LAYER M3 ;
      RECT 174.735 56.359 174.753 56.413 ;
    END
  END r0_rd_out[607]
  PIN r0_rd_out[608]
    DIRECTION OUTPUT ;
    USE SIGNAL ;
    SHAPE ABUTMENT ;
    PORT
      LAYER M3 ;
      RECT 175.023 56.359 175.041 56.413 ;
    END
  END r0_rd_out[608]
  PIN r0_rd_out[609]
    DIRECTION OUTPUT ;
    USE SIGNAL ;
    SHAPE ABUTMENT ;
    PORT
      LAYER M3 ;
      RECT 175.311 56.359 175.329 56.413 ;
    END
  END r0_rd_out[609]
  PIN r0_rd_out[610]
    DIRECTION OUTPUT ;
    USE SIGNAL ;
    SHAPE ABUTMENT ;
    PORT
      LAYER M3 ;
      RECT 175.599 56.359 175.617 56.413 ;
    END
  END r0_rd_out[610]
  PIN r0_rd_out[611]
    DIRECTION OUTPUT ;
    USE SIGNAL ;
    SHAPE ABUTMENT ;
    PORT
      LAYER M3 ;
      RECT 175.887 56.359 175.905 56.413 ;
    END
  END r0_rd_out[611]
  PIN r0_rd_out[612]
    DIRECTION OUTPUT ;
    USE SIGNAL ;
    SHAPE ABUTMENT ;
    PORT
      LAYER M3 ;
      RECT 176.175 56.359 176.193 56.413 ;
    END
  END r0_rd_out[612]
  PIN r0_rd_out[613]
    DIRECTION OUTPUT ;
    USE SIGNAL ;
    SHAPE ABUTMENT ;
    PORT
      LAYER M3 ;
      RECT 176.463 56.359 176.481 56.413 ;
    END
  END r0_rd_out[613]
  PIN r0_rd_out[614]
    DIRECTION OUTPUT ;
    USE SIGNAL ;
    SHAPE ABUTMENT ;
    PORT
      LAYER M3 ;
      RECT 176.751 56.359 176.769 56.413 ;
    END
  END r0_rd_out[614]
  PIN r0_rd_out[615]
    DIRECTION OUTPUT ;
    USE SIGNAL ;
    SHAPE ABUTMENT ;
    PORT
      LAYER M3 ;
      RECT 177.039 56.359 177.057 56.413 ;
    END
  END r0_rd_out[615]
  PIN r0_rd_out[616]
    DIRECTION OUTPUT ;
    USE SIGNAL ;
    SHAPE ABUTMENT ;
    PORT
      LAYER M3 ;
      RECT 177.327 56.359 177.345 56.413 ;
    END
  END r0_rd_out[616]
  PIN r0_rd_out[617]
    DIRECTION OUTPUT ;
    USE SIGNAL ;
    SHAPE ABUTMENT ;
    PORT
      LAYER M3 ;
      RECT 177.615 56.359 177.633 56.413 ;
    END
  END r0_rd_out[617]
  PIN r0_rd_out[618]
    DIRECTION OUTPUT ;
    USE SIGNAL ;
    SHAPE ABUTMENT ;
    PORT
      LAYER M3 ;
      RECT 177.903 56.359 177.921 56.413 ;
    END
  END r0_rd_out[618]
  PIN r0_rd_out[619]
    DIRECTION OUTPUT ;
    USE SIGNAL ;
    SHAPE ABUTMENT ;
    PORT
      LAYER M3 ;
      RECT 178.191 56.359 178.209 56.413 ;
    END
  END r0_rd_out[619]
  PIN r0_rd_out[620]
    DIRECTION OUTPUT ;
    USE SIGNAL ;
    SHAPE ABUTMENT ;
    PORT
      LAYER M3 ;
      RECT 178.479 56.359 178.497 56.413 ;
    END
  END r0_rd_out[620]
  PIN r0_rd_out[621]
    DIRECTION OUTPUT ;
    USE SIGNAL ;
    SHAPE ABUTMENT ;
    PORT
      LAYER M3 ;
      RECT 178.767 56.359 178.785 56.413 ;
    END
  END r0_rd_out[621]
  PIN r0_rd_out[622]
    DIRECTION OUTPUT ;
    USE SIGNAL ;
    SHAPE ABUTMENT ;
    PORT
      LAYER M3 ;
      RECT 179.055 56.359 179.073 56.413 ;
    END
  END r0_rd_out[622]
  PIN r0_rd_out[623]
    DIRECTION OUTPUT ;
    USE SIGNAL ;
    SHAPE ABUTMENT ;
    PORT
      LAYER M3 ;
      RECT 179.343 56.359 179.361 56.413 ;
    END
  END r0_rd_out[623]
  PIN r0_rd_out[624]
    DIRECTION OUTPUT ;
    USE SIGNAL ;
    SHAPE ABUTMENT ;
    PORT
      LAYER M3 ;
      RECT 179.631 56.359 179.649 56.413 ;
    END
  END r0_rd_out[624]
  PIN r0_rd_out[625]
    DIRECTION OUTPUT ;
    USE SIGNAL ;
    SHAPE ABUTMENT ;
    PORT
      LAYER M3 ;
      RECT 179.919 56.359 179.937 56.413 ;
    END
  END r0_rd_out[625]
  PIN r0_rd_out[626]
    DIRECTION OUTPUT ;
    USE SIGNAL ;
    SHAPE ABUTMENT ;
    PORT
      LAYER M3 ;
      RECT 180.207 56.359 180.225 56.413 ;
    END
  END r0_rd_out[626]
  PIN r0_rd_out[627]
    DIRECTION OUTPUT ;
    USE SIGNAL ;
    SHAPE ABUTMENT ;
    PORT
      LAYER M3 ;
      RECT 180.495 56.359 180.513 56.413 ;
    END
  END r0_rd_out[627]
  PIN r0_rd_out[628]
    DIRECTION OUTPUT ;
    USE SIGNAL ;
    SHAPE ABUTMENT ;
    PORT
      LAYER M3 ;
      RECT 180.783 56.359 180.801 56.413 ;
    END
  END r0_rd_out[628]
  PIN r0_rd_out[629]
    DIRECTION OUTPUT ;
    USE SIGNAL ;
    SHAPE ABUTMENT ;
    PORT
      LAYER M3 ;
      RECT 181.071 56.359 181.089 56.413 ;
    END
  END r0_rd_out[629]
  PIN r0_rd_out[630]
    DIRECTION OUTPUT ;
    USE SIGNAL ;
    SHAPE ABUTMENT ;
    PORT
      LAYER M3 ;
      RECT 181.359 56.359 181.377 56.413 ;
    END
  END r0_rd_out[630]
  PIN r0_rd_out[631]
    DIRECTION OUTPUT ;
    USE SIGNAL ;
    SHAPE ABUTMENT ;
    PORT
      LAYER M3 ;
      RECT 181.647 56.359 181.665 56.413 ;
    END
  END r0_rd_out[631]
  PIN r0_rd_out[632]
    DIRECTION OUTPUT ;
    USE SIGNAL ;
    SHAPE ABUTMENT ;
    PORT
      LAYER M3 ;
      RECT 181.935 56.359 181.953 56.413 ;
    END
  END r0_rd_out[632]
  PIN w0_addr_in[0]
    DIRECTION INPUT ;
    USE SIGNAL ;
    SHAPE ABUTMENT ;
    PORT
      LAYER M4 ;
      RECT 0.000 46.068 0.072 46.092 ;
    END
  END w0_addr_in[0]
  PIN r0_addr_in[0]
    DIRECTION INPUT ;
    USE SIGNAL ;
    SHAPE ABUTMENT ;
    PORT
      LAYER M4 ;
      RECT 0.000 46.212 0.072 46.236 ;
    END
  END r0_addr_in[0]
  PIN w0_we_in
    DIRECTION INPUT ;
    USE SIGNAL ;
    SHAPE ABUTMENT ;
    PORT
      LAYER M3 ;
      RECT 182.223 56.359 182.241 56.413 ;
    END
  END w0_we_in
  PIN w0_ce_in
    DIRECTION INPUT ;
    USE SIGNAL ;
    SHAPE ABUTMENT ;
    PORT
      LAYER M3 ;
      RECT 182.511 56.359 182.529 56.413 ;
    END
  END w0_ce_in
  PIN w0_clk
    DIRECTION INPUT ;
    USE SIGNAL ;
    SHAPE ABUTMENT ;
    PORT
      LAYER M3 ;
      RECT 182.799 56.359 182.817 56.413 ;
    END
  END w0_clk
  PIN r0_ce_in
    DIRECTION INPUT ;
    USE SIGNAL ;
    SHAPE ABUTMENT ;
    PORT
      LAYER M3 ;
      RECT 183.087 56.359 183.105 56.413 ;
    END
  END r0_ce_in
  PIN r0_clk
    DIRECTION INPUT ;
    USE SIGNAL ;
    SHAPE ABUTMENT ;
    PORT
      LAYER M3 ;
      RECT 183.375 56.359 183.393 56.413 ;
    END
  END r0_clk
  PIN VSS
    DIRECTION INOUT ;
    USE GROUND ;
    PORT
      LAYER M4 ;
      RECT 0.216 0.240 201.595 0.336 ;
      RECT 0.216 1.008 201.595 1.104 ;
      RECT 0.216 1.776 201.595 1.872 ;
      RECT 0.216 2.544 201.595 2.640 ;
      RECT 0.216 3.312 201.595 3.408 ;
      RECT 0.216 4.080 201.595 4.176 ;
      RECT 0.216 4.848 201.595 4.944 ;
      RECT 0.216 5.616 201.595 5.712 ;
      RECT 0.216 6.384 201.595 6.480 ;
      RECT 0.216 7.152 201.595 7.248 ;
      RECT 0.216 7.920 201.595 8.016 ;
      RECT 0.216 8.688 201.595 8.784 ;
      RECT 0.216 9.456 201.595 9.552 ;
      RECT 0.216 10.224 201.595 10.320 ;
      RECT 0.216 10.992 201.595 11.088 ;
      RECT 0.216 11.760 201.595 11.856 ;
      RECT 0.216 12.528 201.595 12.624 ;
      RECT 0.216 13.296 201.595 13.392 ;
      RECT 0.216 14.064 201.595 14.160 ;
      RECT 0.216 14.832 201.595 14.928 ;
      RECT 0.216 15.600 201.595 15.696 ;
      RECT 0.216 16.368 201.595 16.464 ;
      RECT 0.216 17.136 201.595 17.232 ;
      RECT 0.216 17.904 201.595 18.000 ;
      RECT 0.216 18.672 201.595 18.768 ;
      RECT 0.216 19.440 201.595 19.536 ;
      RECT 0.216 20.208 201.595 20.304 ;
      RECT 0.216 20.976 201.595 21.072 ;
      RECT 0.216 21.744 201.595 21.840 ;
      RECT 0.216 22.512 201.595 22.608 ;
      RECT 0.216 23.280 201.595 23.376 ;
      RECT 0.216 24.048 201.595 24.144 ;
      RECT 0.216 24.816 201.595 24.912 ;
      RECT 0.216 25.584 201.595 25.680 ;
      RECT 0.216 26.352 201.595 26.448 ;
      RECT 0.216 27.120 201.595 27.216 ;
      RECT 0.216 27.888 201.595 27.984 ;
      RECT 0.216 28.656 201.595 28.752 ;
      RECT 0.216 29.424 201.595 29.520 ;
      RECT 0.216 30.192 201.595 30.288 ;
      RECT 0.216 30.960 201.595 31.056 ;
      RECT 0.216 31.728 201.595 31.824 ;
      RECT 0.216 32.496 201.595 32.592 ;
      RECT 0.216 33.264 201.595 33.360 ;
      RECT 0.216 34.032 201.595 34.128 ;
      RECT 0.216 34.800 201.595 34.896 ;
      RECT 0.216 35.568 201.595 35.664 ;
      RECT 0.216 36.336 201.595 36.432 ;
      RECT 0.216 37.104 201.595 37.200 ;
      RECT 0.216 37.872 201.595 37.968 ;
      RECT 0.216 38.640 201.595 38.736 ;
      RECT 0.216 39.408 201.595 39.504 ;
      RECT 0.216 40.176 201.595 40.272 ;
      RECT 0.216 40.944 201.595 41.040 ;
      RECT 0.216 41.712 201.595 41.808 ;
      RECT 0.216 42.480 201.595 42.576 ;
      RECT 0.216 43.248 201.595 43.344 ;
      RECT 0.216 44.016 201.595 44.112 ;
      RECT 0.216 44.784 201.595 44.880 ;
      RECT 0.216 45.552 201.595 45.648 ;
      RECT 0.216 46.320 201.595 46.416 ;
      RECT 0.216 47.088 201.595 47.184 ;
      RECT 0.216 47.856 201.595 47.952 ;
      RECT 0.216 48.624 201.595 48.720 ;
      RECT 0.216 49.392 201.595 49.488 ;
      RECT 0.216 50.160 201.595 50.256 ;
      RECT 0.216 50.928 201.595 51.024 ;
      RECT 0.216 51.696 201.595 51.792 ;
      RECT 0.216 52.464 201.595 52.560 ;
      RECT 0.216 53.232 201.595 53.328 ;
      RECT 0.216 54.000 201.595 54.096 ;
      RECT 0.216 54.768 201.595 54.864 ;
      RECT 0.216 55.536 201.595 55.632 ;
      RECT 0.216 56.304 201.595 56.400 ;
    END
  END VSS
  PIN VDD
    DIRECTION INOUT ;
    USE POWER ;
    PORT
      LAYER M4 ;
      RECT 0.216 0.240 201.595 0.336 ;
      RECT 0.216 1.008 201.595 1.104 ;
      RECT 0.216 1.776 201.595 1.872 ;
      RECT 0.216 2.544 201.595 2.640 ;
      RECT 0.216 3.312 201.595 3.408 ;
      RECT 0.216 4.080 201.595 4.176 ;
      RECT 0.216 4.848 201.595 4.944 ;
      RECT 0.216 5.616 201.595 5.712 ;
      RECT 0.216 6.384 201.595 6.480 ;
      RECT 0.216 7.152 201.595 7.248 ;
      RECT 0.216 7.920 201.595 8.016 ;
      RECT 0.216 8.688 201.595 8.784 ;
      RECT 0.216 9.456 201.595 9.552 ;
      RECT 0.216 10.224 201.595 10.320 ;
      RECT 0.216 10.992 201.595 11.088 ;
      RECT 0.216 11.760 201.595 11.856 ;
      RECT 0.216 12.528 201.595 12.624 ;
      RECT 0.216 13.296 201.595 13.392 ;
      RECT 0.216 14.064 201.595 14.160 ;
      RECT 0.216 14.832 201.595 14.928 ;
      RECT 0.216 15.600 201.595 15.696 ;
      RECT 0.216 16.368 201.595 16.464 ;
      RECT 0.216 17.136 201.595 17.232 ;
      RECT 0.216 17.904 201.595 18.000 ;
      RECT 0.216 18.672 201.595 18.768 ;
      RECT 0.216 19.440 201.595 19.536 ;
      RECT 0.216 20.208 201.595 20.304 ;
      RECT 0.216 20.976 201.595 21.072 ;
      RECT 0.216 21.744 201.595 21.840 ;
      RECT 0.216 22.512 201.595 22.608 ;
      RECT 0.216 23.280 201.595 23.376 ;
      RECT 0.216 24.048 201.595 24.144 ;
      RECT 0.216 24.816 201.595 24.912 ;
      RECT 0.216 25.584 201.595 25.680 ;
      RECT 0.216 26.352 201.595 26.448 ;
      RECT 0.216 27.120 201.595 27.216 ;
      RECT 0.216 27.888 201.595 27.984 ;
      RECT 0.216 28.656 201.595 28.752 ;
      RECT 0.216 29.424 201.595 29.520 ;
      RECT 0.216 30.192 201.595 30.288 ;
      RECT 0.216 30.960 201.595 31.056 ;
      RECT 0.216 31.728 201.595 31.824 ;
      RECT 0.216 32.496 201.595 32.592 ;
      RECT 0.216 33.264 201.595 33.360 ;
      RECT 0.216 34.032 201.595 34.128 ;
      RECT 0.216 34.800 201.595 34.896 ;
      RECT 0.216 35.568 201.595 35.664 ;
      RECT 0.216 36.336 201.595 36.432 ;
      RECT 0.216 37.104 201.595 37.200 ;
      RECT 0.216 37.872 201.595 37.968 ;
      RECT 0.216 38.640 201.595 38.736 ;
      RECT 0.216 39.408 201.595 39.504 ;
      RECT 0.216 40.176 201.595 40.272 ;
      RECT 0.216 40.944 201.595 41.040 ;
      RECT 0.216 41.712 201.595 41.808 ;
      RECT 0.216 42.480 201.595 42.576 ;
      RECT 0.216 43.248 201.595 43.344 ;
      RECT 0.216 44.016 201.595 44.112 ;
      RECT 0.216 44.784 201.595 44.880 ;
      RECT 0.216 45.552 201.595 45.648 ;
      RECT 0.216 46.320 201.595 46.416 ;
      RECT 0.216 47.088 201.595 47.184 ;
      RECT 0.216 47.856 201.595 47.952 ;
      RECT 0.216 48.624 201.595 48.720 ;
      RECT 0.216 49.392 201.595 49.488 ;
      RECT 0.216 50.160 201.595 50.256 ;
      RECT 0.216 50.928 201.595 51.024 ;
      RECT 0.216 51.696 201.595 51.792 ;
      RECT 0.216 52.464 201.595 52.560 ;
      RECT 0.216 53.232 201.595 53.328 ;
      RECT 0.216 54.000 201.595 54.096 ;
      RECT 0.216 54.768 201.595 54.864 ;
      RECT 0.216 55.536 201.595 55.632 ;
      RECT 0.216 56.304 201.595 56.400 ;
    END
  END VDD
  OBS
    LAYER M1 ;
    RECT 0 0 201.811 56.413 ;
    LAYER M2 ;
    RECT 0 0 201.811 56.413 ;
    LAYER M3 ;
    RECT 0 0 201.811 56.413 ;
    LAYER M4 ;
    RECT 0 0 201.811 56.413 ;
  END
END fakeram_633x8_1r1w

END LIBRARY
